###############################################################
#  Generated by:      Cadence Innovus 21.16-s078_1
#  OS:                Linux x86_64(Host ID cadpc24)
#  Generated on:      Thu Apr 11 01:46:05 2024
#  Design:            ibex_top
#  Command:           write_lef_abstract ibex_top.lef -5.7 -PgpinLayers {1 2 3 4 5} -specifyTopLayer 5 -stripePin
###############################################################

VERSION 5.7 ;

BUSBITCHARS "[]" ;
DIVIDERCHAR "/" ;

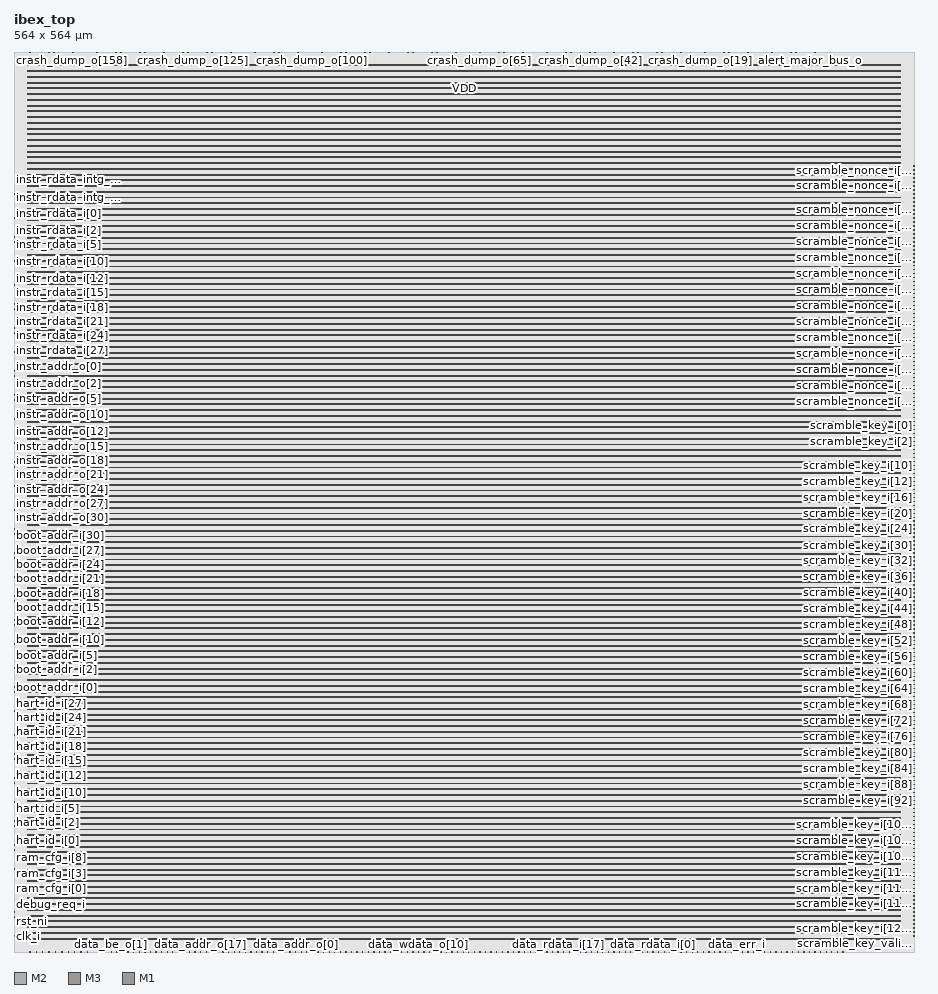
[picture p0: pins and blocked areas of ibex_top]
MACRO ibex_top
  CLASS BLOCK ;
  SIZE 564.000000 BY 564.000000 ;
  FOREIGN ibex_top 0.000000 0.000000 ;
  ORIGIN 0 0 ;
  SYMMETRY X Y R90 ;
  PIN clk_i
    DIRECTION INPUT ;
    USE SIGNAL ;
    ANTENNAPARTIALMETALAREA 0.06 LAYER M2  ;
    ANTENNAPARTIALMETALSIDEAREA 0.222 LAYER M2  ;
    ANTENNAPARTIALCUTAREA 0.04 LAYER V2  ;
    ANTENNAPARTIALMETALAREA 13.76 LAYER M3  ;
    ANTENNAPARTIALMETALSIDEAREA 51.208 LAYER M3  ;
    ANTENNAMODEL OXIDE1 ;
    ANTENNAGATEAREA 0.5976 LAYER M3  ;
    ANTENNAMAXAREACAR 67.0509 LAYER M3  ;
    ANTENNAMAXSIDEAREACAR 249.814 LAYER M3  ;
    ANTENNAMAXCUTCAR 1.38889 LAYER VL  ;
    PORT
      LAYER M2 ;
        RECT 0.000000 9.900000 0.600000 10.100000 ;
    END
  END clk_i
  PIN rst_ni
    DIRECTION INPUT ;
    USE SIGNAL ;
    ANTENNAPARTIALMETALAREA 0.06 LAYER M2  ;
    ANTENNAPARTIALMETALSIDEAREA 0.222 LAYER M2  ;
    ANTENNAPARTIALCUTAREA 0.04 LAYER V2  ;
    ANTENNAPARTIALMETALAREA 2.12 LAYER M3  ;
    ANTENNAPARTIALMETALSIDEAREA 7.992 LAYER M3  ;
    ANTENNAMODEL OXIDE1 ;
    ANTENNAGATEAREA 0.0888 LAYER M3  ;
    ANTENNAMAXAREACAR 26.9369 LAYER M3  ;
    ANTENNAMAXSIDEAREACAR 103.329 LAYER M3  ;
    ANTENNAMAXCUTCAR 0.900901 LAYER VL  ;
    PORT
      LAYER M2 ;
        RECT 0.000000 13.900000 0.600000 14.100000 ;
    END
  END rst_ni
  PIN test_en_i
    DIRECTION INPUT ;
    USE SIGNAL ;
    ANTENNAPARTIALMETALAREA 1.92 LAYER M3  ;
    ANTENNAPARTIALMETALSIDEAREA 7.4 LAYER M3  ;
    ANTENNAMODEL OXIDE1 ;
    ANTENNAGATEAREA 0.0888 LAYER M3  ;
    ANTENNAMAXAREACAR 23.6171 LAYER M3  ;
    ANTENNAMAXSIDEAREACAR 93.0225 LAYER M3  ;
    ANTENNAMAXCUTCAR 0.900901 LAYER VL  ;
    PORT
      LAYER M3 ;
        RECT 0.000000 21.900000 0.600000 22.100000 ;
    END
  END test_en_i
  PIN ram_cfg_i[9]
    DIRECTION INPUT ;
    USE SIGNAL ;
    PORT
      LAYER M2 ;
        RECT 0.000000 66.900000 0.600000 67.100000 ;
    END
  END ram_cfg_i[9]
  PIN ram_cfg_i[8]
    DIRECTION INPUT ;
    USE SIGNAL ;
    PORT
      LAYER M2 ;
        RECT 0.000000 63.900000 0.600000 64.100000 ;
    END
  END ram_cfg_i[8]
  PIN ram_cfg_i[7]
    DIRECTION INPUT ;
    USE SIGNAL ;
    PORT
      LAYER M2 ;
        RECT 0.000000 60.900000 0.600000 61.100000 ;
    END
  END ram_cfg_i[7]
  PIN ram_cfg_i[6]
    DIRECTION INPUT ;
    USE SIGNAL ;
    PORT
      LAYER M2 ;
        RECT 0.000000 57.900000 0.600000 58.100000 ;
    END
  END ram_cfg_i[6]
  PIN ram_cfg_i[5]
    DIRECTION INPUT ;
    USE SIGNAL ;
    PORT
      LAYER M2 ;
        RECT 0.000000 54.900000 0.600000 55.100000 ;
    END
  END ram_cfg_i[5]
  PIN ram_cfg_i[4]
    DIRECTION INPUT ;
    USE SIGNAL ;
    PORT
      LAYER M2 ;
        RECT 0.000000 51.900000 0.600000 52.100000 ;
    END
  END ram_cfg_i[4]
  PIN ram_cfg_i[3]
    DIRECTION INPUT ;
    USE SIGNAL ;
    PORT
      LAYER M2 ;
        RECT 0.000000 48.900000 0.600000 49.100000 ;
    END
  END ram_cfg_i[3]
  PIN ram_cfg_i[2]
    DIRECTION INPUT ;
    USE SIGNAL ;
    PORT
      LAYER M2 ;
        RECT 0.000000 45.900000 0.600000 46.100000 ;
    END
  END ram_cfg_i[2]
  PIN ram_cfg_i[1]
    DIRECTION INPUT ;
    USE SIGNAL ;
    PORT
      LAYER M2 ;
        RECT 0.000000 42.900000 0.600000 43.100000 ;
    END
  END ram_cfg_i[1]
  PIN ram_cfg_i[0]
    DIRECTION INPUT ;
    USE SIGNAL ;
    PORT
      LAYER M2 ;
        RECT 0.000000 39.900000 0.600000 40.100000 ;
    END
  END ram_cfg_i[0]
  PIN hart_id_i[31]
    DIRECTION INPUT ;
    USE SIGNAL ;
    ANTENNAPARTIALMETALAREA 0.02 LAYER M2  ;
    ANTENNAPARTIALMETALSIDEAREA 0.074 LAYER M2  ;
    ANTENNAPARTIALCUTAREA 0.04 LAYER V2  ;
    ANTENNAPARTIALMETALAREA 1.84 LAYER M3  ;
    ANTENNAPARTIALMETALSIDEAREA 7.104 LAYER M3  ;
    ANTENNAMODEL OXIDE1 ;
    ANTENNAGATEAREA 0.0888 LAYER M3  ;
    ANTENNAMAXAREACAR 22.7162 LAYER M3  ;
    ANTENNAMAXSIDEAREACAR 89.6892 LAYER M3  ;
    ANTENNAMAXCUTCAR 0.900901 LAYER VL  ;
    PORT
      LAYER M2 ;
        RECT 0.000000 162.900000 0.600000 163.100000 ;
    END
  END hart_id_i[31]
  PIN hart_id_i[30]
    DIRECTION INPUT ;
    USE SIGNAL ;
    ANTENNAPARTIALMETALAREA 0.3 LAYER M2  ;
    ANTENNAPARTIALMETALSIDEAREA 1.11 LAYER M2  ;
    ANTENNAPARTIALCUTAREA 0.04 LAYER V2  ;
    ANTENNAPARTIALMETALAREA 2.52 LAYER M3  ;
    ANTENNAPARTIALMETALSIDEAREA 9.472 LAYER M3  ;
    ANTENNAMODEL OXIDE1 ;
    ANTENNAGATEAREA 0.0888 LAYER M3  ;
    ANTENNAMAXAREACAR 31.4414 LAYER M3  ;
    ANTENNAMAXSIDEAREACAR 119.995 LAYER M3  ;
    ANTENNAMAXCUTCAR 0.900901 LAYER VL  ;
    PORT
      LAYER M2 ;
        RECT 0.000000 159.900000 0.600000 160.100000 ;
    END
  END hart_id_i[30]
  PIN hart_id_i[29]
    DIRECTION INPUT ;
    USE SIGNAL ;
    ANTENNAPARTIALMETALAREA 0.02 LAYER M2  ;
    ANTENNAPARTIALMETALSIDEAREA 0.074 LAYER M2  ;
    ANTENNAPARTIALCUTAREA 0.04 LAYER V2  ;
    ANTENNAPARTIALMETALAREA 1.92 LAYER M3  ;
    ANTENNAPARTIALMETALSIDEAREA 7.4 LAYER M3  ;
    ANTENNAMODEL OXIDE1 ;
    ANTENNAGATEAREA 0.0888 LAYER M3  ;
    ANTENNAMAXAREACAR 23.6171 LAYER M3  ;
    ANTENNAMAXSIDEAREACAR 93.0225 LAYER M3  ;
    ANTENNAMAXCUTCAR 0.900901 LAYER VL  ;
    PORT
      LAYER M2 ;
        RECT 0.000000 156.900000 0.600000 157.100000 ;
    END
  END hart_id_i[29]
  PIN hart_id_i[28]
    DIRECTION INPUT ;
    USE SIGNAL ;
    ANTENNAPARTIALMETALAREA 0.06 LAYER M2  ;
    ANTENNAPARTIALMETALSIDEAREA 0.222 LAYER M2  ;
    ANTENNAPARTIALCUTAREA 0.04 LAYER V2  ;
    ANTENNAPARTIALMETALAREA 2.08 LAYER M3  ;
    ANTENNAPARTIALMETALSIDEAREA 7.992 LAYER M3  ;
    ANTENNAMODEL OXIDE1 ;
    ANTENNAGATEAREA 0.0888 LAYER M3  ;
    ANTENNAMAXAREACAR 25.4189 LAYER M3  ;
    ANTENNAMAXSIDEAREACAR 99.6892 LAYER M3  ;
    ANTENNAMAXCUTCAR 0.900901 LAYER VL  ;
    PORT
      LAYER M2 ;
        RECT 0.000000 153.900000 0.600000 154.100000 ;
    END
  END hart_id_i[28]
  PIN hart_id_i[27]
    DIRECTION INPUT ;
    USE SIGNAL ;
    ANTENNAPARTIALMETALAREA 0.02 LAYER M2  ;
    ANTENNAPARTIALMETALSIDEAREA 0.074 LAYER M2  ;
    ANTENNAPARTIALCUTAREA 0.04 LAYER V2  ;
    ANTENNAPARTIALMETALAREA 2.08 LAYER M3  ;
    ANTENNAPARTIALMETALSIDEAREA 7.992 LAYER M3  ;
    ANTENNAMODEL OXIDE1 ;
    ANTENNAGATEAREA 0.0888 LAYER M3  ;
    ANTENNAMAXAREACAR 25.4189 LAYER M3  ;
    ANTENNAMAXSIDEAREACAR 99.6892 LAYER M3  ;
    ANTENNAMAXCUTCAR 0.900901 LAYER VL  ;
    PORT
      LAYER M2 ;
        RECT 0.000000 150.900000 0.600000 151.100000 ;
    END
  END hart_id_i[27]
  PIN hart_id_i[26]
    DIRECTION INPUT ;
    USE SIGNAL ;
    ANTENNAPARTIALMETALAREA 0.06 LAYER M2  ;
    ANTENNAPARTIALMETALSIDEAREA 0.222 LAYER M2  ;
    ANTENNAPARTIALCUTAREA 0.04 LAYER V2  ;
    ANTENNAPARTIALMETALAREA 2 LAYER M3  ;
    ANTENNAPARTIALMETALSIDEAREA 7.696 LAYER M3  ;
    ANTENNAMODEL OXIDE1 ;
    ANTENNAGATEAREA 0.0888 LAYER M3  ;
    ANTENNAMAXAREACAR 25.5856 LAYER M3  ;
    ANTENNAMAXSIDEAREACAR 99.9955 LAYER M3  ;
    ANTENNAMAXCUTCAR 0.900901 LAYER VL  ;
    PORT
      LAYER M2 ;
        RECT 0.000000 147.900000 0.600000 148.100000 ;
    END
  END hart_id_i[26]
  PIN hart_id_i[25]
    DIRECTION INPUT ;
    USE SIGNAL ;
    ANTENNAPARTIALMETALAREA 0.02 LAYER M2  ;
    ANTENNAPARTIALMETALSIDEAREA 0.074 LAYER M2  ;
    ANTENNAPARTIALCUTAREA 0.04 LAYER V2  ;
    ANTENNAPARTIALMETALAREA 1.92 LAYER M3  ;
    ANTENNAPARTIALMETALSIDEAREA 7.4 LAYER M3  ;
    ANTENNAMODEL OXIDE1 ;
    ANTENNAGATEAREA 0.0888 LAYER M3  ;
    ANTENNAMAXAREACAR 23.6171 LAYER M3  ;
    ANTENNAMAXSIDEAREACAR 93.0225 LAYER M3  ;
    ANTENNAMAXCUTCAR 0.900901 LAYER VL  ;
    PORT
      LAYER M2 ;
        RECT 0.000000 144.900000 0.600000 145.100000 ;
    END
  END hart_id_i[25]
  PIN hart_id_i[24]
    DIRECTION INPUT ;
    USE SIGNAL ;
    ANTENNAPARTIALMETALAREA 0.14 LAYER M2  ;
    ANTENNAPARTIALMETALSIDEAREA 0.518 LAYER M2  ;
    ANTENNAPARTIALCUTAREA 0.04 LAYER V2  ;
    ANTENNAPARTIALMETALAREA 1.96 LAYER M3  ;
    ANTENNAPARTIALMETALSIDEAREA 7.4 LAYER M3  ;
    ANTENNAMODEL OXIDE1 ;
    ANTENNAGATEAREA 0.0888 LAYER M3  ;
    ANTENNAMAXAREACAR 25.1351 LAYER M3  ;
    ANTENNAMAXSIDEAREACAR 96.6622 LAYER M3  ;
    ANTENNAMAXCUTCAR 0.900901 LAYER VL  ;
    PORT
      LAYER M2 ;
        RECT 0.000000 141.900000 0.600000 142.100000 ;
    END
  END hart_id_i[24]
  PIN hart_id_i[23]
    DIRECTION INPUT ;
    USE SIGNAL ;
    ANTENNAPARTIALMETALAREA 0.18 LAYER M2  ;
    ANTENNAPARTIALMETALSIDEAREA 0.666 LAYER M2  ;
    ANTENNAPARTIALCUTAREA 0.04 LAYER V2  ;
    ANTENNAPARTIALMETALAREA 2.28 LAYER M3  ;
    ANTENNAPARTIALMETALSIDEAREA 8.584 LAYER M3  ;
    ANTENNAMODEL OXIDE1 ;
    ANTENNAGATEAREA 0.0888 LAYER M3  ;
    ANTENNAMAXAREACAR 28.7387 LAYER M3  ;
    ANTENNAMAXSIDEAREACAR 109.995 LAYER M3  ;
    ANTENNAMAXCUTCAR 0.900901 LAYER VL  ;
    PORT
      LAYER M2 ;
        RECT 0.000000 138.900000 0.600000 139.100000 ;
    END
  END hart_id_i[23]
  PIN hart_id_i[22]
    DIRECTION INPUT ;
    USE SIGNAL ;
    ANTENNAPARTIALMETALAREA 0.06 LAYER M2  ;
    ANTENNAPARTIALMETALSIDEAREA 0.222 LAYER M2  ;
    ANTENNAPARTIALCUTAREA 0.04 LAYER V2  ;
    ANTENNAPARTIALMETALAREA 1.92 LAYER M3  ;
    ANTENNAPARTIALMETALSIDEAREA 7.4 LAYER M3  ;
    ANTENNAMODEL OXIDE1 ;
    ANTENNAGATEAREA 0.0888 LAYER M3  ;
    ANTENNAMAXAREACAR 23.6171 LAYER M3  ;
    ANTENNAMAXSIDEAREACAR 93.0225 LAYER M3  ;
    ANTENNAMAXCUTCAR 0.900901 LAYER VL  ;
    PORT
      LAYER M2 ;
        RECT 0.000000 135.900000 0.600000 136.100000 ;
    END
  END hart_id_i[22]
  PIN hart_id_i[21]
    DIRECTION INPUT ;
    USE SIGNAL ;
    ANTENNAPARTIALMETALAREA 0.02 LAYER M2  ;
    ANTENNAPARTIALMETALSIDEAREA 0.074 LAYER M2  ;
    ANTENNAPARTIALCUTAREA 0.04 LAYER V2  ;
    ANTENNAPARTIALMETALAREA 1.88 LAYER M3  ;
    ANTENNAPARTIALMETALSIDEAREA 7.104 LAYER M3  ;
    ANTENNAMODEL OXIDE1 ;
    ANTENNAGATEAREA 0.0888 LAYER M3  ;
    ANTENNAMAXAREACAR 23.1667 LAYER M3  ;
    ANTENNAMAXSIDEAREACAR 89.6892 LAYER M3  ;
    ANTENNAMAXCUTCAR 0.900901 LAYER VL  ;
    PORT
      LAYER M2 ;
        RECT 0.000000 132.900000 0.600000 133.100000 ;
    END
  END hart_id_i[21]
  PIN hart_id_i[20]
    DIRECTION INPUT ;
    USE SIGNAL ;
    ANTENNAPARTIALMETALAREA 0.06 LAYER M2  ;
    ANTENNAPARTIALMETALSIDEAREA 0.222 LAYER M2  ;
    ANTENNAPARTIALCUTAREA 0.04 LAYER V2  ;
    ANTENNAPARTIALMETALAREA 0.44 LAYER M3  ;
    ANTENNAPARTIALMETALSIDEAREA 1.776 LAYER M3  ;
    PORT
      LAYER M2 ;
        RECT 0.000000 129.900000 0.600000 130.100000 ;
    END
  END hart_id_i[20]
  PIN hart_id_i[19]
    DIRECTION INPUT ;
    USE SIGNAL ;
    ANTENNAPARTIALMETALAREA 0.02 LAYER M2  ;
    ANTENNAPARTIALMETALSIDEAREA 0.074 LAYER M2  ;
    ANTENNAPARTIALCUTAREA 0.04 LAYER V2  ;
    ANTENNAPARTIALMETALAREA 2.16 LAYER M3  ;
    ANTENNAPARTIALMETALSIDEAREA 8.288 LAYER M3  ;
    ANTENNAMODEL OXIDE1 ;
    ANTENNAGATEAREA 0.0888 LAYER M3  ;
    ANTENNAMAXAREACAR 26.3198 LAYER M3  ;
    ANTENNAMAXSIDEAREACAR 103.023 LAYER M3  ;
    ANTENNAMAXCUTCAR 0.900901 LAYER VL  ;
    PORT
      LAYER M2 ;
        RECT 0.000000 126.900000 0.600000 127.100000 ;
    END
  END hart_id_i[19]
  PIN hart_id_i[18]
    DIRECTION INPUT ;
    USE SIGNAL ;
    ANTENNAPARTIALMETALAREA 0.3 LAYER M2  ;
    ANTENNAPARTIALMETALSIDEAREA 1.11 LAYER M2  ;
    ANTENNAPARTIALCUTAREA 0.04 LAYER V2  ;
    ANTENNAPARTIALMETALAREA 1.8 LAYER M3  ;
    ANTENNAPARTIALMETALSIDEAREA 6.808 LAYER M3  ;
    ANTENNAMODEL OXIDE1 ;
    ANTENNAGATEAREA 0.0888 LAYER M3  ;
    ANTENNAMAXAREACAR 23.3333 LAYER M3  ;
    ANTENNAMAXSIDEAREACAR 89.9955 LAYER M3  ;
    ANTENNAMAXCUTCAR 0.900901 LAYER VL  ;
    PORT
      LAYER M2 ;
        RECT 0.000000 123.900000 0.600000 124.100000 ;
    END
  END hart_id_i[18]
  PIN hart_id_i[17]
    DIRECTION INPUT ;
    USE SIGNAL ;
    ANTENNAPARTIALMETALAREA 0.02 LAYER M2  ;
    ANTENNAPARTIALMETALSIDEAREA 0.074 LAYER M2  ;
    ANTENNAPARTIALCUTAREA 0.04 LAYER V2  ;
    ANTENNAPARTIALMETALAREA 0.52 LAYER M3  ;
    ANTENNAPARTIALMETALSIDEAREA 2.072 LAYER M3  ;
    PORT
      LAYER M2 ;
        RECT 0.000000 120.900000 0.600000 121.100000 ;
    END
  END hart_id_i[17]
  PIN hart_id_i[16]
    DIRECTION INPUT ;
    USE SIGNAL ;
    ANTENNAPARTIALMETALAREA 0.06 LAYER M2  ;
    ANTENNAPARTIALMETALSIDEAREA 0.222 LAYER M2  ;
    ANTENNAPARTIALCUTAREA 0.04 LAYER V2  ;
    ANTENNAPARTIALMETALAREA 1.84 LAYER M3  ;
    ANTENNAPARTIALMETALSIDEAREA 7.104 LAYER M3  ;
    PORT
      LAYER M2 ;
        RECT 0.000000 117.900000 0.600000 118.100000 ;
    END
  END hart_id_i[16]
  PIN hart_id_i[15]
    DIRECTION INPUT ;
    USE SIGNAL ;
    ANTENNAPARTIALMETALAREA 0.1 LAYER M2  ;
    ANTENNAPARTIALMETALSIDEAREA 0.37 LAYER M2  ;
    ANTENNAPARTIALCUTAREA 0.04 LAYER V2  ;
    ANTENNAPARTIALMETALAREA 1.88 LAYER M3  ;
    ANTENNAPARTIALMETALSIDEAREA 7.104 LAYER M3  ;
    ANTENNAMODEL OXIDE1 ;
    ANTENNAGATEAREA 0.0888 LAYER M3  ;
    ANTENNAMAXAREACAR 24.2342 LAYER M3  ;
    ANTENNAMAXSIDEAREACAR 93.3288 LAYER M3  ;
    ANTENNAMAXCUTCAR 0.900901 LAYER VL  ;
    PORT
      LAYER M2 ;
        RECT 0.000000 114.900000 0.600000 115.100000 ;
    END
  END hart_id_i[15]
  PIN hart_id_i[14]
    DIRECTION INPUT ;
    USE SIGNAL ;
    ANTENNAPARTIALMETALAREA 0.06 LAYER M2  ;
    ANTENNAPARTIALMETALSIDEAREA 0.222 LAYER M2  ;
    ANTENNAPARTIALCUTAREA 0.04 LAYER V2  ;
    ANTENNAPARTIALMETALAREA 0.6 LAYER M3  ;
    ANTENNAPARTIALMETALSIDEAREA 2.368 LAYER M3  ;
    PORT
      LAYER M2 ;
        RECT 0.000000 111.900000 0.600000 112.100000 ;
    END
  END hart_id_i[14]
  PIN hart_id_i[13]
    DIRECTION INPUT ;
    USE SIGNAL ;
    ANTENNAPARTIALMETALAREA 0.02 LAYER M2  ;
    ANTENNAPARTIALMETALSIDEAREA 0.074 LAYER M2  ;
    ANTENNAPARTIALCUTAREA 0.04 LAYER V2  ;
    ANTENNAPARTIALMETALAREA 0.36 LAYER M3  ;
    ANTENNAPARTIALMETALSIDEAREA 1.48 LAYER M3  ;
    PORT
      LAYER M2 ;
        RECT 0.000000 108.900000 0.600000 109.100000 ;
    END
  END hart_id_i[13]
  PIN hart_id_i[12]
    DIRECTION INPUT ;
    USE SIGNAL ;
    ANTENNAPARTIALMETALAREA 0.06 LAYER M2  ;
    ANTENNAPARTIALMETALSIDEAREA 0.222 LAYER M2  ;
    ANTENNAPARTIALCUTAREA 0.04 LAYER V2  ;
    ANTENNAPARTIALMETALAREA 1.92 LAYER M3  ;
    ANTENNAPARTIALMETALSIDEAREA 7.4 LAYER M3  ;
    PORT
      LAYER M2 ;
        RECT 0.000000 105.900000 0.600000 106.100000 ;
    END
  END hart_id_i[12]
  PIN hart_id_i[11]
    DIRECTION INPUT ;
    USE SIGNAL ;
    ANTENNAPARTIALMETALAREA 0.02 LAYER M2  ;
    ANTENNAPARTIALMETALSIDEAREA 0.074 LAYER M2  ;
    ANTENNAPARTIALCUTAREA 0.04 LAYER V2  ;
    ANTENNAPARTIALMETALAREA 0.28 LAYER M3  ;
    ANTENNAPARTIALMETALSIDEAREA 1.184 LAYER M3  ;
    PORT
      LAYER M2 ;
        RECT 0.000000 102.900000 0.600000 103.100000 ;
    END
  END hart_id_i[11]
  PIN hart_id_i[10]
    DIRECTION INPUT ;
    USE SIGNAL ;
    ANTENNAPARTIALMETALAREA 0.06 LAYER M2  ;
    ANTENNAPARTIALMETALSIDEAREA 0.222 LAYER M2  ;
    ANTENNAPARTIALCUTAREA 0.04 LAYER V2  ;
    ANTENNAPARTIALMETALAREA 2.16 LAYER M3  ;
    ANTENNAPARTIALMETALSIDEAREA 8.288 LAYER M3  ;
    ANTENNAMODEL OXIDE1 ;
    ANTENNAGATEAREA 0.0888 LAYER M3  ;
    ANTENNAMAXAREACAR 26.3198 LAYER M3  ;
    ANTENNAMAXSIDEAREACAR 103.023 LAYER M3  ;
    ANTENNAMAXCUTCAR 0.900901 LAYER VL  ;
    PORT
      LAYER M2 ;
        RECT 0.000000 99.900000 0.600000 100.100000 ;
    END
  END hart_id_i[10]
  PIN hart_id_i[9]
    DIRECTION INPUT ;
    USE SIGNAL ;
    ANTENNAPARTIALMETALAREA 0.02 LAYER M2  ;
    ANTENNAPARTIALMETALSIDEAREA 0.074 LAYER M2  ;
    ANTENNAPARTIALCUTAREA 0.04 LAYER V2  ;
    ANTENNAPARTIALMETALAREA 0.44 LAYER M3  ;
    ANTENNAPARTIALMETALSIDEAREA 1.776 LAYER M3  ;
    PORT
      LAYER M2 ;
        RECT 0.000000 96.900000 0.600000 97.100000 ;
    END
  END hart_id_i[9]
  PIN hart_id_i[8]
    DIRECTION INPUT ;
    USE SIGNAL ;
    ANTENNAPARTIALMETALAREA 0.06 LAYER M2  ;
    ANTENNAPARTIALMETALSIDEAREA 0.222 LAYER M2  ;
    ANTENNAPARTIALCUTAREA 0.04 LAYER V2  ;
    ANTENNAPARTIALMETALAREA 0.36 LAYER M3  ;
    ANTENNAPARTIALMETALSIDEAREA 1.48 LAYER M3  ;
    PORT
      LAYER M2 ;
        RECT 0.000000 93.900000 0.600000 94.100000 ;
    END
  END hart_id_i[8]
  PIN hart_id_i[7]
    DIRECTION INPUT ;
    USE SIGNAL ;
    ANTENNAPARTIALMETALAREA 0.02 LAYER M2  ;
    ANTENNAPARTIALMETALSIDEAREA 0.074 LAYER M2  ;
    ANTENNAPARTIALCUTAREA 0.04 LAYER V2  ;
    ANTENNAPARTIALMETALAREA 2.48 LAYER M3  ;
    ANTENNAPARTIALMETALSIDEAREA 9.472 LAYER M3  ;
    PORT
      LAYER M2 ;
        RECT 0.000000 90.900000 0.600000 91.100000 ;
    END
  END hart_id_i[7]
  PIN hart_id_i[6]
    DIRECTION INPUT ;
    USE SIGNAL ;
    ANTENNAPARTIALMETALAREA 0.06 LAYER M2  ;
    ANTENNAPARTIALMETALSIDEAREA 0.222 LAYER M2  ;
    ANTENNAPARTIALCUTAREA 0.04 LAYER V2  ;
    ANTENNAPARTIALMETALAREA 2 LAYER M3  ;
    ANTENNAPARTIALMETALSIDEAREA 7.696 LAYER M3  ;
    PORT
      LAYER M2 ;
        RECT 0.000000 87.900000 0.600000 88.100000 ;
    END
  END hart_id_i[6]
  PIN hart_id_i[5]
    DIRECTION INPUT ;
    USE SIGNAL ;
    ANTENNAPARTIALMETALAREA 0.02 LAYER M2  ;
    ANTENNAPARTIALMETALSIDEAREA 0.074 LAYER M2  ;
    ANTENNAPARTIALCUTAREA 0.04 LAYER V2  ;
    ANTENNAPARTIALMETALAREA 1.8 LAYER M3  ;
    ANTENNAPARTIALMETALSIDEAREA 6.808 LAYER M3  ;
    PORT
      LAYER M2 ;
        RECT 0.000000 84.900000 0.600000 85.100000 ;
    END
  END hart_id_i[5]
  PIN hart_id_i[4]
    DIRECTION INPUT ;
    USE SIGNAL ;
    ANTENNAPARTIALMETALAREA 0.06 LAYER M2  ;
    ANTENNAPARTIALMETALSIDEAREA 0.222 LAYER M2  ;
    ANTENNAPARTIALCUTAREA 0.04 LAYER V2  ;
    ANTENNAPARTIALMETALAREA 0.28 LAYER M3  ;
    ANTENNAPARTIALMETALSIDEAREA 1.184 LAYER M3  ;
    PORT
      LAYER M2 ;
        RECT 0.000000 81.900000 0.600000 82.100000 ;
    END
  END hart_id_i[4]
  PIN hart_id_i[3]
    DIRECTION INPUT ;
    USE SIGNAL ;
    ANTENNAPARTIALMETALAREA 0.02 LAYER M2  ;
    ANTENNAPARTIALMETALSIDEAREA 0.074 LAYER M2  ;
    ANTENNAPARTIALCUTAREA 0.04 LAYER V2  ;
    ANTENNAPARTIALMETALAREA 2.24 LAYER M3  ;
    ANTENNAPARTIALMETALSIDEAREA 8.584 LAYER M3  ;
    PORT
      LAYER M2 ;
        RECT 0.000000 78.900000 0.600000 79.100000 ;
    END
  END hart_id_i[3]
  PIN hart_id_i[2]
    DIRECTION INPUT ;
    USE SIGNAL ;
    ANTENNAPARTIALMETALAREA 0.06 LAYER M2  ;
    ANTENNAPARTIALMETALSIDEAREA 0.222 LAYER M2  ;
    ANTENNAPARTIALCUTAREA 0.04 LAYER V2  ;
    ANTENNAPARTIALMETALAREA 1.88 LAYER M3  ;
    ANTENNAPARTIALMETALSIDEAREA 7.104 LAYER M3  ;
    PORT
      LAYER M2 ;
        RECT 0.000000 75.900000 0.600000 76.100000 ;
    END
  END hart_id_i[2]
  PIN hart_id_i[1]
    DIRECTION INPUT ;
    USE SIGNAL ;
    ANTENNAPARTIALMETALAREA 0.02 LAYER M2  ;
    ANTENNAPARTIALMETALSIDEAREA 0.074 LAYER M2  ;
    ANTENNAPARTIALCUTAREA 0.04 LAYER V2  ;
    ANTENNAPARTIALMETALAREA 1.84 LAYER M3  ;
    ANTENNAPARTIALMETALSIDEAREA 7.104 LAYER M3  ;
    ANTENNAMODEL OXIDE1 ;
    ANTENNAGATEAREA 0.0888 LAYER M3  ;
    ANTENNAMAXAREACAR 23.7838 LAYER M3  ;
    ANTENNAMAXSIDEAREACAR 93.3288 LAYER M3  ;
    ANTENNAMAXCUTCAR 0.900901 LAYER VL  ;
    PORT
      LAYER M2 ;
        RECT 0.000000 72.900000 0.600000 73.100000 ;
    END
  END hart_id_i[1]
  PIN hart_id_i[0]
    DIRECTION INPUT ;
    USE SIGNAL ;
    ANTENNAPARTIALMETALAREA 0.06 LAYER M2  ;
    ANTENNAPARTIALMETALSIDEAREA 0.222 LAYER M2  ;
    ANTENNAPARTIALCUTAREA 0.04 LAYER V2  ;
    ANTENNAPARTIALMETALAREA 1.84 LAYER M3  ;
    ANTENNAPARTIALMETALSIDEAREA 7.104 LAYER M3  ;
    ANTENNAMODEL OXIDE1 ;
    ANTENNAGATEAREA 0.0888 LAYER M3  ;
    ANTENNAMAXAREACAR 22.7162 LAYER M3  ;
    ANTENNAMAXSIDEAREACAR 89.6892 LAYER M3  ;
    ANTENNAMAXCUTCAR 0.900901 LAYER VL  ;
    PORT
      LAYER M2 ;
        RECT 0.000000 69.900000 0.600000 70.100000 ;
    END
  END hart_id_i[0]
  PIN boot_addr_i[31]
    DIRECTION INPUT ;
    USE SIGNAL ;
    ANTENNAPARTIALMETALAREA 0.02 LAYER M2  ;
    ANTENNAPARTIALMETALSIDEAREA 0.074 LAYER M2  ;
    ANTENNAPARTIALCUTAREA 0.04 LAYER V2  ;
    ANTENNAPARTIALMETALAREA 1.56 LAYER M3  ;
    ANTENNAPARTIALMETALSIDEAREA 5.92 LAYER M3  ;
    PORT
      LAYER M2 ;
        RECT 0.000000 258.900000 0.600000 259.100000 ;
    END
  END boot_addr_i[31]
  PIN boot_addr_i[30]
    DIRECTION INPUT ;
    USE SIGNAL ;
    ANTENNAPARTIALMETALAREA 0.06 LAYER M2  ;
    ANTENNAPARTIALMETALSIDEAREA 0.222 LAYER M2  ;
    ANTENNAPARTIALCUTAREA 0.04 LAYER V2  ;
    ANTENNAPARTIALMETALAREA 0.36 LAYER M3  ;
    ANTENNAPARTIALMETALSIDEAREA 1.48 LAYER M3  ;
    PORT
      LAYER M2 ;
        RECT 0.000000 255.900000 0.600000 256.100000 ;
    END
  END boot_addr_i[30]
  PIN boot_addr_i[29]
    DIRECTION INPUT ;
    USE SIGNAL ;
    ANTENNAPARTIALMETALAREA 0.02 LAYER M2  ;
    ANTENNAPARTIALMETALSIDEAREA 0.074 LAYER M2  ;
    ANTENNAPARTIALCUTAREA 0.04 LAYER V2  ;
    ANTENNAPARTIALMETALAREA 3.12 LAYER M3  ;
    ANTENNAPARTIALMETALSIDEAREA 11.84 LAYER M3  ;
    ANTENNAMODEL OXIDE1 ;
    ANTENNAGATEAREA 0.0888 LAYER M3  ;
    ANTENNAMAXAREACAR 37.1306 LAYER M3  ;
    ANTENNAMAXSIDEAREACAR 143.023 LAYER M3  ;
    ANTENNAMAXCUTCAR 0.900901 LAYER VL  ;
    PORT
      LAYER M2 ;
        RECT 0.000000 252.900000 0.600000 253.100000 ;
    END
  END boot_addr_i[29]
  PIN boot_addr_i[28]
    DIRECTION INPUT ;
    USE SIGNAL ;
    ANTENNAPARTIALMETALAREA 0.14 LAYER M2  ;
    ANTENNAPARTIALMETALSIDEAREA 0.518 LAYER M2  ;
    ANTENNAPARTIALCUTAREA 0.04 LAYER V2  ;
    ANTENNAPARTIALMETALAREA 2.2 LAYER M3  ;
    ANTENNAPARTIALMETALSIDEAREA 8.288 LAYER M3  ;
    ANTENNAMODEL OXIDE1 ;
    ANTENNAGATEAREA 0.0888 LAYER M3  ;
    ANTENNAMAXAREACAR 27.8378 LAYER M3  ;
    ANTENNAMAXSIDEAREACAR 106.662 LAYER M3  ;
    ANTENNAMAXCUTCAR 0.900901 LAYER VL  ;
    PORT
      LAYER M2 ;
        RECT 0.000000 249.900000 0.600000 250.100000 ;
    END
  END boot_addr_i[28]
  PIN boot_addr_i[27]
    DIRECTION INPUT ;
    USE SIGNAL ;
    ANTENNAPARTIALMETALAREA 0.02 LAYER M2  ;
    ANTENNAPARTIALMETALSIDEAREA 0.074 LAYER M2  ;
    ANTENNAPARTIALCUTAREA 0.04 LAYER V2  ;
    ANTENNAPARTIALMETALAREA 1.8 LAYER M3  ;
    ANTENNAPARTIALMETALSIDEAREA 6.808 LAYER M3  ;
    PORT
      LAYER M2 ;
        RECT 0.000000 246.900000 0.600000 247.100000 ;
    END
  END boot_addr_i[27]
  PIN boot_addr_i[26]
    DIRECTION INPUT ;
    USE SIGNAL ;
    ANTENNAPARTIALMETALAREA 0.06 LAYER M2  ;
    ANTENNAPARTIALMETALSIDEAREA 0.222 LAYER M2  ;
    ANTENNAPARTIALCUTAREA 0.04 LAYER V2  ;
    ANTENNAPARTIALMETALAREA 3.88 LAYER M3  ;
    ANTENNAPARTIALMETALSIDEAREA 14.504 LAYER M3  ;
    ANTENNAMODEL OXIDE1 ;
    ANTENNAGATEAREA 0.0888 LAYER M3  ;
    ANTENNAMAXAREACAR 45.6892 LAYER M3  ;
    ANTENNAMAXSIDEAREACAR 173.023 LAYER M3  ;
    ANTENNAMAXCUTCAR 0.900901 LAYER VL  ;
    PORT
      LAYER M2 ;
        RECT 0.000000 243.900000 0.600000 244.100000 ;
    END
  END boot_addr_i[26]
  PIN boot_addr_i[25]
    DIRECTION INPUT ;
    USE SIGNAL ;
    ANTENNAPARTIALMETALAREA 0.02 LAYER M2  ;
    ANTENNAPARTIALMETALSIDEAREA 0.074 LAYER M2  ;
    ANTENNAPARTIALCUTAREA 0.04 LAYER V2  ;
    ANTENNAPARTIALMETALAREA 2.24 LAYER M3  ;
    ANTENNAPARTIALMETALSIDEAREA 8.584 LAYER M3  ;
    ANTENNAMODEL OXIDE1 ;
    ANTENNAGATEAREA 0.0888 LAYER M3  ;
    ANTENNAMAXAREACAR 28.2883 LAYER M3  ;
    ANTENNAMAXSIDEAREACAR 109.995 LAYER M3  ;
    ANTENNAMAXCUTCAR 0.900901 LAYER VL  ;
    PORT
      LAYER M2 ;
        RECT 0.000000 240.900000 0.600000 241.100000 ;
    END
  END boot_addr_i[25]
  PIN boot_addr_i[24]
    DIRECTION INPUT ;
    USE SIGNAL ;
    ANTENNAPARTIALMETALAREA 0.06 LAYER M2  ;
    ANTENNAPARTIALMETALSIDEAREA 0.222 LAYER M2  ;
    ANTENNAPARTIALCUTAREA 0.04 LAYER V2  ;
    ANTENNAPARTIALMETALAREA 3.12 LAYER M3  ;
    ANTENNAPARTIALMETALSIDEAREA 11.84 LAYER M3  ;
    ANTENNAMODEL OXIDE1 ;
    ANTENNAGATEAREA 0.0888 LAYER M3  ;
    ANTENNAMAXAREACAR 37.1306 LAYER M3  ;
    ANTENNAMAXSIDEAREACAR 143.023 LAYER M3  ;
    ANTENNAMAXCUTCAR 0.900901 LAYER VL  ;
    PORT
      LAYER M2 ;
        RECT 0.000000 237.900000 0.600000 238.100000 ;
    END
  END boot_addr_i[24]
  PIN boot_addr_i[23]
    DIRECTION INPUT ;
    USE SIGNAL ;
    ANTENNAPARTIALMETALAREA 0.02 LAYER M2  ;
    ANTENNAPARTIALMETALSIDEAREA 0.074 LAYER M2  ;
    ANTENNAPARTIALCUTAREA 0.04 LAYER V2  ;
    ANTENNAPARTIALMETALAREA 2.16 LAYER M3  ;
    ANTENNAPARTIALMETALSIDEAREA 8.288 LAYER M3  ;
    ANTENNAMODEL OXIDE1 ;
    ANTENNAGATEAREA 0.0888 LAYER M3  ;
    ANTENNAMAXAREACAR 27.3874 LAYER M3  ;
    ANTENNAMAXSIDEAREACAR 106.662 LAYER M3  ;
    ANTENNAMAXCUTCAR 0.900901 LAYER VL  ;
    PORT
      LAYER M2 ;
        RECT 0.000000 234.900000 0.600000 235.100000 ;
    END
  END boot_addr_i[23]
  PIN boot_addr_i[22]
    DIRECTION INPUT ;
    USE SIGNAL ;
    ANTENNAPARTIALMETALAREA 0.3 LAYER M2  ;
    ANTENNAPARTIALMETALSIDEAREA 1.11 LAYER M2  ;
    ANTENNAPARTIALCUTAREA 0.04 LAYER V2  ;
    ANTENNAPARTIALMETALAREA 2.92 LAYER M3  ;
    ANTENNAPARTIALMETALSIDEAREA 10.952 LAYER M3  ;
    ANTENNAMODEL OXIDE1 ;
    ANTENNAGATEAREA 0.0888 LAYER M3  ;
    ANTENNAMAXAREACAR 35.9459 LAYER M3  ;
    ANTENNAMAXSIDEAREACAR 136.662 LAYER M3  ;
    ANTENNAMAXCUTCAR 0.900901 LAYER VL  ;
    PORT
      LAYER M2 ;
        RECT 0.000000 231.900000 0.600000 232.100000 ;
    END
  END boot_addr_i[22]
  PIN boot_addr_i[21]
    DIRECTION INPUT ;
    USE SIGNAL ;
    ANTENNAPARTIALMETALAREA 0.02 LAYER M2  ;
    ANTENNAPARTIALMETALSIDEAREA 0.074 LAYER M2  ;
    ANTENNAPARTIALCUTAREA 0.04 LAYER V2  ;
    ANTENNAPARTIALMETALAREA 1.64 LAYER M3  ;
    ANTENNAPARTIALMETALSIDEAREA 6.216 LAYER M3  ;
    PORT
      LAYER M2 ;
        RECT 0.000000 228.900000 0.600000 229.100000 ;
    END
  END boot_addr_i[21]
  PIN boot_addr_i[20]
    DIRECTION INPUT ;
    USE SIGNAL ;
    ANTENNAPARTIALMETALAREA 0.06 LAYER M2  ;
    ANTENNAPARTIALMETALSIDEAREA 0.222 LAYER M2  ;
    ANTENNAPARTIALCUTAREA 0.04 LAYER V2  ;
    ANTENNAPARTIALMETALAREA 0.28 LAYER M3  ;
    ANTENNAPARTIALMETALSIDEAREA 1.184 LAYER M3  ;
    PORT
      LAYER M2 ;
        RECT 0.000000 225.900000 0.600000 226.100000 ;
    END
  END boot_addr_i[20]
  PIN boot_addr_i[19]
    DIRECTION INPUT ;
    USE SIGNAL ;
    ANTENNAPARTIALMETALAREA 0.02 LAYER M2  ;
    ANTENNAPARTIALMETALSIDEAREA 0.074 LAYER M2  ;
    ANTENNAPARTIALCUTAREA 0.04 LAYER V2  ;
    ANTENNAPARTIALMETALAREA 2.16 LAYER M3  ;
    ANTENNAPARTIALMETALSIDEAREA 8.288 LAYER M3  ;
    ANTENNAMODEL OXIDE1 ;
    ANTENNAGATEAREA 0.0888 LAYER M3  ;
    ANTENNAMAXAREACAR 26.3198 LAYER M3  ;
    ANTENNAMAXSIDEAREACAR 103.023 LAYER M3  ;
    ANTENNAMAXCUTCAR 0.900901 LAYER VL  ;
    PORT
      LAYER M2 ;
        RECT 0.000000 222.900000 0.600000 223.100000 ;
    END
  END boot_addr_i[19]
  PIN boot_addr_i[18]
    DIRECTION INPUT ;
    USE SIGNAL ;
    ANTENNAPARTIALMETALAREA 0.06 LAYER M2  ;
    ANTENNAPARTIALMETALSIDEAREA 0.222 LAYER M2  ;
    ANTENNAPARTIALCUTAREA 0.04 LAYER V2  ;
    ANTENNAPARTIALMETALAREA 2.16 LAYER M3  ;
    ANTENNAPARTIALMETALSIDEAREA 8.288 LAYER M3  ;
    ANTENNAMODEL OXIDE1 ;
    ANTENNAGATEAREA 0.0888 LAYER M3  ;
    ANTENNAMAXAREACAR 26.3198 LAYER M3  ;
    ANTENNAMAXSIDEAREACAR 103.023 LAYER M3  ;
    ANTENNAMAXCUTCAR 0.900901 LAYER VL  ;
    PORT
      LAYER M2 ;
        RECT 0.000000 219.900000 0.600000 220.100000 ;
    END
  END boot_addr_i[18]
  PIN boot_addr_i[17]
    DIRECTION INPUT ;
    USE SIGNAL ;
    ANTENNAPARTIALMETALAREA 0.02 LAYER M2  ;
    ANTENNAPARTIALMETALSIDEAREA 0.074 LAYER M2  ;
    ANTENNAPARTIALCUTAREA 0.04 LAYER V2  ;
    ANTENNAPARTIALMETALAREA 1.8 LAYER M3  ;
    ANTENNAPARTIALMETALSIDEAREA 6.808 LAYER M3  ;
    PORT
      LAYER M2 ;
        RECT 0.000000 216.900000 0.600000 217.100000 ;
    END
  END boot_addr_i[17]
  PIN boot_addr_i[16]
    DIRECTION INPUT ;
    USE SIGNAL ;
    ANTENNAPARTIALMETALAREA 0.06 LAYER M2  ;
    ANTENNAPARTIALMETALSIDEAREA 0.222 LAYER M2  ;
    ANTENNAPARTIALCUTAREA 0.04 LAYER V2  ;
    ANTENNAPARTIALMETALAREA 0.44 LAYER M3  ;
    ANTENNAPARTIALMETALSIDEAREA 1.776 LAYER M3  ;
    PORT
      LAYER M2 ;
        RECT 0.000000 213.900000 0.600000 214.100000 ;
    END
  END boot_addr_i[16]
  PIN boot_addr_i[15]
    DIRECTION INPUT ;
    USE SIGNAL ;
    ANTENNAPARTIALMETALAREA 0.02 LAYER M2  ;
    ANTENNAPARTIALMETALSIDEAREA 0.074 LAYER M2  ;
    ANTENNAPARTIALCUTAREA 0.04 LAYER V2  ;
    ANTENNAPARTIALMETALAREA 1.8 LAYER M3  ;
    ANTENNAPARTIALMETALSIDEAREA 6.808 LAYER M3  ;
    PORT
      LAYER M2 ;
        RECT 0.000000 210.900000 0.600000 211.100000 ;
    END
  END boot_addr_i[15]
  PIN boot_addr_i[14]
    DIRECTION INPUT ;
    USE SIGNAL ;
    ANTENNAPARTIALMETALAREA 0.06 LAYER M2  ;
    ANTENNAPARTIALMETALSIDEAREA 0.222 LAYER M2  ;
    ANTENNAPARTIALCUTAREA 0.04 LAYER V2  ;
    ANTENNAPARTIALMETALAREA 1.8 LAYER M3  ;
    ANTENNAPARTIALMETALSIDEAREA 6.808 LAYER M3  ;
    ANTENNAMODEL OXIDE1 ;
    ANTENNAGATEAREA 0.0888 LAYER M3  ;
    ANTENNAMAXAREACAR 22.4324 LAYER M3  ;
    ANTENNAMAXSIDEAREACAR 86.6622 LAYER M3  ;
    ANTENNAMAXCUTCAR 0.900901 LAYER VL  ;
    PORT
      LAYER M2 ;
        RECT 0.000000 207.900000 0.600000 208.100000 ;
    END
  END boot_addr_i[14]
  PIN boot_addr_i[13]
    DIRECTION INPUT ;
    USE SIGNAL ;
    ANTENNAPARTIALMETALAREA 0.02 LAYER M2  ;
    ANTENNAPARTIALMETALSIDEAREA 0.074 LAYER M2  ;
    ANTENNAPARTIALCUTAREA 0.04 LAYER V2  ;
    ANTENNAPARTIALMETALAREA 1.8 LAYER M3  ;
    ANTENNAPARTIALMETALSIDEAREA 6.808 LAYER M3  ;
    ANTENNAMODEL OXIDE1 ;
    ANTENNAGATEAREA 0.0888 LAYER M3  ;
    ANTENNAMAXAREACAR 22.4324 LAYER M3  ;
    ANTENNAMAXSIDEAREACAR 86.6622 LAYER M3  ;
    ANTENNAMAXCUTCAR 0.900901 LAYER VL  ;
    PORT
      LAYER M2 ;
        RECT 0.000000 204.900000 0.600000 205.100000 ;
    END
  END boot_addr_i[13]
  PIN boot_addr_i[12]
    DIRECTION INPUT ;
    USE SIGNAL ;
    ANTENNAPARTIALMETALAREA 0.06 LAYER M2  ;
    ANTENNAPARTIALMETALSIDEAREA 0.222 LAYER M2  ;
    ANTENNAPARTIALCUTAREA 0.04 LAYER V2  ;
    ANTENNAPARTIALMETALAREA 1.8 LAYER M3  ;
    ANTENNAPARTIALMETALSIDEAREA 6.808 LAYER M3  ;
    PORT
      LAYER M2 ;
        RECT 0.000000 201.900000 0.600000 202.100000 ;
    END
  END boot_addr_i[12]
  PIN boot_addr_i[11]
    DIRECTION INPUT ;
    USE SIGNAL ;
    ANTENNAPARTIALMETALAREA 0.02 LAYER M2  ;
    ANTENNAPARTIALMETALSIDEAREA 0.074 LAYER M2  ;
    ANTENNAPARTIALCUTAREA 0.04 LAYER V2  ;
    ANTENNAPARTIALMETALAREA 1.8 LAYER M3  ;
    ANTENNAPARTIALMETALSIDEAREA 6.808 LAYER M3  ;
    PORT
      LAYER M2 ;
        RECT 0.000000 198.900000 0.600000 199.100000 ;
    END
  END boot_addr_i[11]
  PIN boot_addr_i[10]
    DIRECTION INPUT ;
    USE SIGNAL ;
    ANTENNAPARTIALMETALAREA 0.22 LAYER M2  ;
    ANTENNAPARTIALMETALSIDEAREA 0.814 LAYER M2  ;
    ANTENNAPARTIALCUTAREA 0.04 LAYER V2  ;
    ANTENNAPARTIALMETALAREA 1.88 LAYER M3  ;
    ANTENNAPARTIALMETALSIDEAREA 7.104 LAYER M3  ;
    PORT
      LAYER M2 ;
        RECT 0.000000 195.900000 0.600000 196.100000 ;
    END
  END boot_addr_i[10]
  PIN boot_addr_i[9]
    DIRECTION INPUT ;
    USE SIGNAL ;
    ANTENNAPARTIALMETALAREA 0.02 LAYER M2  ;
    ANTENNAPARTIALMETALSIDEAREA 0.074 LAYER M2  ;
    ANTENNAPARTIALCUTAREA 0.04 LAYER V2  ;
    ANTENNAPARTIALMETALAREA 0.28 LAYER M3  ;
    ANTENNAPARTIALMETALSIDEAREA 1.184 LAYER M3  ;
    PORT
      LAYER M2 ;
        RECT 0.000000 192.900000 0.600000 193.100000 ;
    END
  END boot_addr_i[9]
  PIN boot_addr_i[8]
    DIRECTION INPUT ;
    USE SIGNAL ;
    ANTENNAPARTIALMETALAREA 0.06 LAYER M2  ;
    ANTENNAPARTIALMETALSIDEAREA 0.222 LAYER M2  ;
    ANTENNAPARTIALCUTAREA 0.04 LAYER V2  ;
    ANTENNAPARTIALMETALAREA 0.36 LAYER M3  ;
    ANTENNAPARTIALMETALSIDEAREA 1.48 LAYER M3  ;
    PORT
      LAYER M2 ;
        RECT 0.000000 189.900000 0.600000 190.100000 ;
    END
  END boot_addr_i[8]
  PIN boot_addr_i[7]
    DIRECTION INPUT ;
    USE SIGNAL ;
    PORT
      LAYER M2 ;
        RECT 0.000000 186.900000 0.600000 187.100000 ;
    END
  END boot_addr_i[7]
  PIN boot_addr_i[6]
    DIRECTION INPUT ;
    USE SIGNAL ;
    PORT
      LAYER M2 ;
        RECT 0.000000 183.900000 0.600000 184.100000 ;
    END
  END boot_addr_i[6]
  PIN boot_addr_i[5]
    DIRECTION INPUT ;
    USE SIGNAL ;
    PORT
      LAYER M2 ;
        RECT 0.000000 180.900000 0.600000 181.100000 ;
    END
  END boot_addr_i[5]
  PIN boot_addr_i[4]
    DIRECTION INPUT ;
    USE SIGNAL ;
    PORT
      LAYER M2 ;
        RECT 0.000000 177.900000 0.600000 178.100000 ;
    END
  END boot_addr_i[4]
  PIN boot_addr_i[3]
    DIRECTION INPUT ;
    USE SIGNAL ;
    PORT
      LAYER M2 ;
        RECT 0.000000 174.900000 0.600000 175.100000 ;
    END
  END boot_addr_i[3]
  PIN boot_addr_i[2]
    DIRECTION INPUT ;
    USE SIGNAL ;
    PORT
      LAYER M2 ;
        RECT 0.000000 171.900000 0.600000 172.100000 ;
    END
  END boot_addr_i[2]
  PIN boot_addr_i[1]
    DIRECTION INPUT ;
    USE SIGNAL ;
    PORT
      LAYER M2 ;
        RECT 0.000000 168.900000 0.600000 169.100000 ;
    END
  END boot_addr_i[1]
  PIN boot_addr_i[0]
    DIRECTION INPUT ;
    USE SIGNAL ;
    PORT
      LAYER M2 ;
        RECT 0.000000 165.900000 0.600000 166.100000 ;
    END
  END boot_addr_i[0]
  PIN instr_req_o
    DIRECTION OUTPUT ;
    USE SIGNAL ;
    ANTENNAPARTIALMETALAREA 8.78 LAYER M3  ;
    ANTENNAPARTIALMETALSIDEAREA 32.56 LAYER M3  ;
    ANTENNAMODEL OXIDE1 ;
    ANTENNAGATEAREA 0.3 LAYER M3  ;
    ANTENNAMAXAREACAR 158.209 LAYER M3  ;
    ANTENNAMAXSIDEAREACAR 586.476 LAYER M3  ;
    ANTENNAMAXCUTCAR 2.08333 LAYER VL  ;
    PORT
      LAYER M3 ;
        RECT 0.000000 261.900000 0.600000 262.100000 ;
    END
  END instr_req_o
  PIN instr_gnt_i
    DIRECTION INPUT ;
    USE SIGNAL ;
    ANTENNAPARTIALMETALAREA 2.76 LAYER M3  ;
    ANTENNAPARTIALMETALSIDEAREA 10.508 LAYER M3  ;
    ANTENNAMODEL OXIDE1 ;
    ANTENNAGATEAREA 0.0696 LAYER M3  ;
    ANTENNAMAXAREACAR 46.9195 LAYER M3  ;
    ANTENNAMAXSIDEAREACAR 177.069 LAYER M3  ;
    ANTENNAMAXCUTCAR 1.14943 LAYER VL  ;
    PORT
      LAYER M3 ;
        RECT 0.000000 264.900000 0.600000 265.100000 ;
    END
  END instr_gnt_i
  PIN instr_rvalid_i
    DIRECTION INPUT ;
    USE SIGNAL ;
    ANTENNAPARTIALMETALAREA 2.08 LAYER M3  ;
    ANTENNAPARTIALMETALSIDEAREA 7.992 LAYER M3  ;
    ANTENNAMODEL OXIDE1 ;
    ANTENNAGATEAREA 0.0888 LAYER M3  ;
    ANTENNAMAXAREACAR 28.2883 LAYER M3  ;
    ANTENNAMAXSIDEAREACAR 109.995 LAYER M3  ;
    ANTENNAMAXCUTCAR 0.900901 LAYER VL  ;
    PORT
      LAYER M3 ;
        RECT 0.000000 267.900000 0.600000 268.100000 ;
    END
  END instr_rvalid_i
  PIN instr_addr_o[31]
    DIRECTION OUTPUT ;
    USE SIGNAL ;
    ANTENNAPARTIALMETALAREA 2.3 LAYER M3  ;
    ANTENNAPARTIALMETALSIDEAREA 8.288 LAYER M3  ;
    ANTENNAMODEL OXIDE1 ;
    ANTENNAGATEAREA 2.56 LAYER M3  ;
    ANTENNAMAXAREACAR 1.14141 LAYER M3  ;
    ANTENNAMAXSIDEAREACAR 4.17125 LAYER M3  ;
    ANTENNAMAXCUTCAR 0.03125 LAYER VL  ;
    PORT
      LAYER M3 ;
        RECT 0.000000 273.900000 0.600000 274.100000 ;
    END
  END instr_addr_o[31]
  PIN instr_addr_o[30]
    DIRECTION OUTPUT ;
    USE SIGNAL ;
    ANTENNAPARTIALMETALAREA 3.18 LAYER M3  ;
    ANTENNAPARTIALMETALSIDEAREA 11.914 LAYER M3  ;
    ANTENNAMODEL OXIDE1 ;
    ANTENNAGATEAREA 2.56 LAYER M3  ;
    ANTENNAMAXAREACAR 1.54672 LAYER M3  ;
    ANTENNAMAXSIDEAREACAR 5.81891 LAYER M3  ;
    ANTENNAMAXCUTCAR 0.03125 LAYER VL  ;
    PORT
      LAYER M3 ;
        RECT 0.000000 276.900000 0.600000 277.100000 ;
    END
  END instr_addr_o[30]
  PIN instr_addr_o[29]
    DIRECTION OUTPUT ;
    USE SIGNAL ;
    ANTENNAPARTIALMETALAREA 2.38 LAYER M3  ;
    ANTENNAPARTIALMETALSIDEAREA 8.584 LAYER M3  ;
    ANTENNAMODEL OXIDE1 ;
    ANTENNAGATEAREA 2.56 LAYER M3  ;
    ANTENNAMAXAREACAR 1.17266 LAYER M3  ;
    ANTENNAMAXSIDEAREACAR 4.28687 LAYER M3  ;
    ANTENNAMAXCUTCAR 0.03125 LAYER VL  ;
    PORT
      LAYER M3 ;
        RECT 0.000000 279.900000 0.600000 280.100000 ;
    END
  END instr_addr_o[29]
  PIN instr_addr_o[28]
    DIRECTION OUTPUT ;
    USE SIGNAL ;
    ANTENNAPARTIALMETALAREA 2.64 LAYER M3  ;
    ANTENNAPARTIALMETALSIDEAREA 9.916 LAYER M3  ;
    ANTENNAMODEL OXIDE1 ;
    ANTENNAGATEAREA 2.56 LAYER M3  ;
    ANTENNAMAXAREACAR 1.30453 LAYER M3  ;
    ANTENNAMAXSIDEAREACAR 4.92281 LAYER M3  ;
    ANTENNAMAXCUTCAR 0.03125 LAYER VL  ;
    PORT
      LAYER M3 ;
        RECT 0.000000 282.900000 0.600000 283.100000 ;
    END
  END instr_addr_o[28]
  PIN instr_addr_o[27]
    DIRECTION OUTPUT ;
    USE SIGNAL ;
    ANTENNAPARTIALMETALAREA 5.38 LAYER M3  ;
    ANTENNAPARTIALMETALSIDEAREA 19.536 LAYER M3  ;
    ANTENNAMODEL OXIDE1 ;
    ANTENNAGATEAREA 2.56 LAYER M3  ;
    ANTENNAMAXAREACAR 3.09359 LAYER M3  ;
    ANTENNAMAXSIDEAREACAR 11.34 LAYER M3  ;
    ANTENNAMAXCUTCAR 0.03125 LAYER VL  ;
    PORT
      LAYER M3 ;
        RECT 0.000000 285.900000 0.600000 286.100000 ;
    END
  END instr_addr_o[27]
  PIN instr_addr_o[26]
    DIRECTION OUTPUT ;
    USE SIGNAL ;
    ANTENNAPARTIALMETALAREA 6.48 LAYER M3  ;
    ANTENNAPARTIALMETALSIDEAREA 24.124 LAYER M3  ;
    ANTENNAMODEL OXIDE1 ;
    ANTENNAGATEAREA 2.56 LAYER M3  ;
    ANTENNAMAXAREACAR 2.77422 LAYER M3  ;
    ANTENNAMAXSIDEAREACAR 10.3572 LAYER M3  ;
    ANTENNAMAXCUTCAR 0.03125 LAYER VL  ;
    PORT
      LAYER M3 ;
        RECT 0.000000 288.900000 0.600000 289.100000 ;
    END
  END instr_addr_o[26]
  PIN instr_addr_o[25]
    DIRECTION OUTPUT ;
    USE SIGNAL ;
    ANTENNAPARTIALMETALAREA 5.98 LAYER M3  ;
    ANTENNAPARTIALMETALSIDEAREA 21.904 LAYER M3  ;
    ANTENNAMODEL OXIDE1 ;
    ANTENNAGATEAREA 2.56 LAYER M3  ;
    ANTENNAMAXAREACAR 2.57891 LAYER M3  ;
    ANTENNAMAXSIDEAREACAR 9.49 LAYER M3  ;
    ANTENNAMAXCUTCAR 0.03125 LAYER VL  ;
    PORT
      LAYER M3 ;
        RECT 0.000000 291.900000 0.600000 292.100000 ;
    END
  END instr_addr_o[25]
  PIN instr_addr_o[24]
    DIRECTION OUTPUT ;
    USE SIGNAL ;
    ANTENNAPARTIALMETALAREA 5.68 LAYER M3  ;
    ANTENNAPARTIALMETALSIDEAREA 21.164 LAYER M3  ;
    ANTENNAMODEL OXIDE1 ;
    ANTENNAGATEAREA 2.56 LAYER M3  ;
    ANTENNAMAXAREACAR 2.46172 LAYER M3  ;
    ANTENNAMAXSIDEAREACAR 9.20094 LAYER M3  ;
    ANTENNAMAXCUTCAR 0.03125 LAYER VL  ;
    PORT
      LAYER M3 ;
        RECT 0.000000 294.900000 0.600000 295.100000 ;
    END
  END instr_addr_o[24]
  PIN instr_addr_o[23]
    DIRECTION OUTPUT ;
    USE SIGNAL ;
    ANTENNAPARTIALMETALAREA 6.22 LAYER M3  ;
    ANTENNAPARTIALMETALSIDEAREA 22.792 LAYER M3  ;
    ANTENNAMODEL OXIDE1 ;
    ANTENNAGATEAREA 2.56 LAYER M3  ;
    ANTENNAMAXAREACAR 2.67266 LAYER M3  ;
    ANTENNAMAXSIDEAREACAR 9.83687 LAYER M3  ;
    ANTENNAMAXCUTCAR 0.03125 LAYER VL  ;
    PORT
      LAYER M3 ;
        RECT 0.000000 297.900000 0.600000 298.100000 ;
    END
  END instr_addr_o[23]
  PIN instr_addr_o[22]
    DIRECTION OUTPUT ;
    USE SIGNAL ;
    ANTENNAPARTIALMETALAREA 6.08 LAYER M3  ;
    ANTENNAPARTIALMETALSIDEAREA 22.644 LAYER M3  ;
    ANTENNAMODEL OXIDE1 ;
    ANTENNAGATEAREA 2.56 LAYER M3  ;
    ANTENNAMAXAREACAR 2.61797 LAYER M3  ;
    ANTENNAMAXSIDEAREACAR 9.77906 LAYER M3  ;
    ANTENNAMAXCUTCAR 0.03125 LAYER VL  ;
    PORT
      LAYER M3 ;
        RECT 0.000000 300.900000 0.600000 301.100000 ;
    END
  END instr_addr_o[22]
  PIN instr_addr_o[21]
    DIRECTION OUTPUT ;
    USE SIGNAL ;
    ANTENNAPARTIALMETALAREA 2.3 LAYER M3  ;
    ANTENNAPARTIALMETALSIDEAREA 8.288 LAYER M3  ;
    ANTENNAMODEL OXIDE1 ;
    ANTENNAGATEAREA 1.066 LAYER M3  ;
    ANTENNAMAXAREACAR 2.70657 LAYER M3  ;
    ANTENNAMAXSIDEAREACAR 9.87054 LAYER M3  ;
    ANTENNAMAXCUTCAR 0.0750469 LAYER VL  ;
    PORT
      LAYER M3 ;
        RECT 0.000000 303.900000 0.600000 304.100000 ;
    END
  END instr_addr_o[21]
  PIN instr_addr_o[20]
    DIRECTION OUTPUT ;
    USE SIGNAL ;
    ANTENNAPARTIALMETALAREA 2.64 LAYER M3  ;
    ANTENNAPARTIALMETALSIDEAREA 9.916 LAYER M3  ;
    ANTENNAMODEL OXIDE1 ;
    ANTENNAGATEAREA 2.56 LAYER M3  ;
    ANTENNAMAXAREACAR 1.30453 LAYER M3  ;
    ANTENNAMAXSIDEAREACAR 4.92281 LAYER M3  ;
    ANTENNAMAXCUTCAR 0.03125 LAYER VL  ;
    PORT
      LAYER M3 ;
        RECT 0.000000 306.900000 0.600000 307.100000 ;
    END
  END instr_addr_o[20]
  PIN instr_addr_o[19]
    DIRECTION OUTPUT ;
    USE SIGNAL ;
    ANTENNAPARTIALMETALAREA 2.94 LAYER M3  ;
    ANTENNAPARTIALMETALSIDEAREA 10.656 LAYER M3  ;
    ANTENNAMODEL OXIDE1 ;
    ANTENNAGATEAREA 2.56 LAYER M3  ;
    ANTENNAMAXAREACAR 1.39141 LAYER M3  ;
    ANTENNAMAXSIDEAREACAR 5.09625 LAYER M3  ;
    ANTENNAMAXCUTCAR 0.03125 LAYER VL  ;
    PORT
      LAYER M3 ;
        RECT 0.000000 309.900000 0.600000 310.100000 ;
    END
  END instr_addr_o[19]
  PIN instr_addr_o[18]
    DIRECTION OUTPUT ;
    USE SIGNAL ;
    ANTENNAPARTIALMETALAREA 2.16 LAYER M3  ;
    ANTENNAPARTIALMETALSIDEAREA 8.14 LAYER M3  ;
    ANTENNAMODEL OXIDE1 ;
    ANTENNAGATEAREA 2.56 LAYER M3  ;
    ANTENNAMAXAREACAR 1.08672 LAYER M3  ;
    ANTENNAMAXSIDEAREACAR 4.11344 LAYER M3  ;
    ANTENNAMAXCUTCAR 0.03125 LAYER VL  ;
    PORT
      LAYER M3 ;
        RECT 0.000000 312.900000 0.600000 313.100000 ;
    END
  END instr_addr_o[18]
  PIN instr_addr_o[17]
    DIRECTION OUTPUT ;
    USE SIGNAL ;
    ANTENNAPARTIALMETALAREA 5.82 LAYER M3  ;
    ANTENNAPARTIALMETALSIDEAREA 21.312 LAYER M3  ;
    ANTENNAMODEL OXIDE1 ;
    ANTENNAGATEAREA 2.56 LAYER M3  ;
    ANTENNAMAXAREACAR 2.51641 LAYER M3  ;
    ANTENNAMAXSIDEAREACAR 9.25875 LAYER M3  ;
    ANTENNAMAXCUTCAR 0.03125 LAYER VL  ;
    PORT
      LAYER M3 ;
        RECT 0.000000 315.900000 0.600000 316.100000 ;
    END
  END instr_addr_o[17]
  PIN instr_addr_o[16]
    DIRECTION OUTPUT ;
    USE SIGNAL ;
    ANTENNAPARTIALMETALAREA 6.16 LAYER M3  ;
    ANTENNAPARTIALMETALSIDEAREA 22.94 LAYER M3  ;
    ANTENNAMODEL OXIDE1 ;
    ANTENNAGATEAREA 2.56 LAYER M3  ;
    ANTENNAMAXAREACAR 2.64922 LAYER M3  ;
    ANTENNAMAXSIDEAREACAR 9.89469 LAYER M3  ;
    ANTENNAMAXCUTCAR 0.03125 LAYER VL  ;
    PORT
      LAYER M3 ;
        RECT 0.000000 318.900000 0.600000 319.100000 ;
    END
  END instr_addr_o[16]
  PIN instr_addr_o[15]
    DIRECTION OUTPUT ;
    USE SIGNAL ;
    ANTENNAPARTIALMETALAREA 5.66 LAYER M3  ;
    ANTENNAPARTIALMETALSIDEAREA 20.72 LAYER M3  ;
    ANTENNAMODEL OXIDE1 ;
    ANTENNAGATEAREA 2.56 LAYER M3  ;
    ANTENNAMAXAREACAR 2.48422 LAYER M3  ;
    ANTENNAMAXSIDEAREACAR 9.14312 LAYER M3  ;
    ANTENNAMAXCUTCAR 0.03125 LAYER VL  ;
    PORT
      LAYER M3 ;
        RECT 0.000000 321.900000 0.600000 322.100000 ;
    END
  END instr_addr_o[15]
  PIN instr_addr_o[14]
    DIRECTION OUTPUT ;
    USE SIGNAL ;
    ANTENNAPARTIALMETALAREA 5.78 LAYER M3  ;
    ANTENNAPARTIALMETALSIDEAREA 21.682 LAYER M3  ;
    ANTENNAMODEL OXIDE1 ;
    ANTENNAGATEAREA 2.56 LAYER M3  ;
    ANTENNAMAXAREACAR 2.50078 LAYER M3  ;
    ANTENNAMAXSIDEAREACAR 9.40328 LAYER M3  ;
    ANTENNAMAXCUTCAR 0.03125 LAYER VL  ;
    PORT
      LAYER M3 ;
        RECT 0.000000 324.900000 0.600000 325.100000 ;
    END
  END instr_addr_o[14]
  PIN instr_addr_o[13]
    DIRECTION OUTPUT ;
    USE SIGNAL ;
    ANTENNAPARTIALMETALAREA 4.38 LAYER M3  ;
    ANTENNAPARTIALMETALSIDEAREA 15.984 LAYER M3  ;
    ANTENNAMODEL OXIDE1 ;
    ANTENNAGATEAREA 2.56 LAYER M3  ;
    ANTENNAMAXAREACAR 1.95391 LAYER M3  ;
    ANTENNAMAXSIDEAREACAR 7.1775 LAYER M3  ;
    ANTENNAMAXCUTCAR 0.03125 LAYER VL  ;
    PORT
      LAYER M3 ;
        RECT 0.000000 327.900000 0.600000 328.100000 ;
    END
  END instr_addr_o[13]
  PIN instr_addr_o[12]
    DIRECTION OUTPUT ;
    USE SIGNAL ;
    ANTENNAPARTIALMETALAREA 2.16 LAYER M3  ;
    ANTENNAPARTIALMETALSIDEAREA 8.14 LAYER M3  ;
    ANTENNAMODEL OXIDE1 ;
    ANTENNAGATEAREA 2.56 LAYER M3  ;
    ANTENNAMAXAREACAR 1.11703 LAYER M3  ;
    ANTENNAMAXSIDEAREACAR 4.22906 LAYER M3  ;
    ANTENNAMAXCUTCAR 0.03125 LAYER VL  ;
    PORT
      LAYER M3 ;
        RECT 0.000000 330.900000 0.600000 331.100000 ;
    END
  END instr_addr_o[12]
  PIN instr_addr_o[11]
    DIRECTION OUTPUT ;
    USE SIGNAL ;
    ANTENNAPARTIALMETALAREA 5.26 LAYER M3  ;
    ANTENNAPARTIALMETALSIDEAREA 19.24 LAYER M3  ;
    ANTENNAMODEL OXIDE1 ;
    ANTENNAGATEAREA 2.56 LAYER M3  ;
    ANTENNAMAXAREACAR 2.29766 LAYER M3  ;
    ANTENNAMAXSIDEAREACAR 8.44938 LAYER M3  ;
    ANTENNAMAXCUTCAR 0.03125 LAYER VL  ;
    PORT
      LAYER M3 ;
        RECT 0.000000 333.900000 0.600000 334.100000 ;
    END
  END instr_addr_o[11]
  PIN instr_addr_o[10]
    DIRECTION OUTPUT ;
    USE SIGNAL ;
    ANTENNAPARTIALMETALAREA 3.8 LAYER M3  ;
    ANTENNAPARTIALMETALSIDEAREA 14.06 LAYER M3  ;
    ANTENNAMODEL OXIDE1 ;
    ANTENNAGATEAREA 2.56 LAYER M3  ;
    ANTENNAMAXAREACAR 4.10141 LAYER M3  ;
    ANTENNAMAXSIDEAREACAR 15.2134 LAYER M3  ;
    ANTENNAMAXCUTCAR 0.03125 LAYER VL  ;
    PORT
      LAYER M3 ;
        RECT 0.000000 336.900000 0.600000 337.100000 ;
    END
  END instr_addr_o[10]
  PIN instr_addr_o[9]
    DIRECTION OUTPUT ;
    USE SIGNAL ;
    ANTENNAPARTIALMETALAREA 5.54 LAYER M3  ;
    ANTENNAPARTIALMETALSIDEAREA 20.128 LAYER M3  ;
    ANTENNAMODEL OXIDE1 ;
    ANTENNAGATEAREA 2.56 LAYER M3  ;
    ANTENNAMAXAREACAR 4.56234 LAYER M3  ;
    ANTENNAMAXSIDEAREACAR 16.7744 LAYER M3  ;
    ANTENNAMAXCUTCAR 0.03125 LAYER VL  ;
    PORT
      LAYER M3 ;
        RECT 0.000000 339.900000 0.600000 340.100000 ;
    END
  END instr_addr_o[9]
  PIN instr_addr_o[8]
    DIRECTION OUTPUT ;
    USE SIGNAL ;
    ANTENNAPARTIALMETALAREA 4.32 LAYER M3  ;
    ANTENNAPARTIALMETALSIDEAREA 16.132 LAYER M3  ;
    ANTENNAMODEL OXIDE1 ;
    ANTENNAGATEAREA 2.56 LAYER M3  ;
    ANTENNAMAXAREACAR 1.96078 LAYER M3  ;
    ANTENNAMAXSIDEAREACAR 7.35094 LAYER M3  ;
    ANTENNAMAXCUTCAR 0.03125 LAYER VL  ;
    PORT
      LAYER M3 ;
        RECT 0.000000 342.900000 0.600000 343.100000 ;
    END
  END instr_addr_o[8]
  PIN instr_addr_o[7]
    DIRECTION OUTPUT ;
    USE SIGNAL ;
    ANTENNAPARTIALMETALAREA 5.18 LAYER M3  ;
    ANTENNAPARTIALMETALSIDEAREA 18.944 LAYER M3  ;
    ANTENNAMODEL OXIDE1 ;
    ANTENNAGATEAREA 2.56 LAYER M3  ;
    ANTENNAMAXAREACAR 2.26641 LAYER M3  ;
    ANTENNAMAXSIDEAREACAR 8.33375 LAYER M3  ;
    ANTENNAMAXCUTCAR 0.03125 LAYER VL  ;
    PORT
      LAYER M3 ;
        RECT 0.000000 345.900000 0.600000 346.100000 ;
    END
  END instr_addr_o[7]
  PIN instr_addr_o[6]
    DIRECTION OUTPUT ;
    USE SIGNAL ;
    ANTENNAPARTIALMETALAREA 4.64 LAYER M3  ;
    ANTENNAPARTIALMETALSIDEAREA 17.316 LAYER M3  ;
    PORT
      LAYER M3 ;
        RECT 0.000000 348.900000 0.600000 349.100000 ;
    END
  END instr_addr_o[6]
  PIN instr_addr_o[5]
    DIRECTION OUTPUT ;
    USE SIGNAL ;
    ANTENNAPARTIALMETALAREA 3.58 LAYER M3  ;
    ANTENNAPARTIALMETALSIDEAREA 13.024 LAYER M3  ;
    ANTENNAMODEL OXIDE1 ;
    ANTENNAGATEAREA 4.044 LAYER M3  ;
    ANTENNAMAXAREACAR 1.17109 LAYER M3  ;
    ANTENNAMAXSIDEAREACAR 4.25816 LAYER M3  ;
    ANTENNAMAXCUTCAR 0.0197824 LAYER VL  ;
    PORT
      LAYER M3 ;
        RECT 0.000000 351.900000 0.600000 352.100000 ;
    END
  END instr_addr_o[5]
  PIN instr_addr_o[4]
    DIRECTION OUTPUT ;
    USE SIGNAL ;
    ANTENNAPARTIALMETALAREA 3.84 LAYER M3  ;
    ANTENNAPARTIALMETALSIDEAREA 14.356 LAYER M3  ;
    PORT
      LAYER M3 ;
        RECT 0.000000 354.900000 0.600000 355.100000 ;
    END
  END instr_addr_o[4]
  PIN instr_addr_o[3]
    DIRECTION OUTPUT ;
    USE SIGNAL ;
    ANTENNAPARTIALMETALAREA 4.7 LAYER M3  ;
    ANTENNAPARTIALMETALSIDEAREA 17.168 LAYER M3  ;
    ANTENNAMODEL OXIDE1 ;
    ANTENNAGATEAREA 4.044 LAYER M3  ;
    ANTENNAMAXAREACAR 1.43301 LAYER M3  ;
    ANTENNAMAXSIDEAREACAR 5.21978 LAYER M3  ;
    ANTENNAMAXCUTCAR 0.0197824 LAYER VL  ;
    PORT
      LAYER M3 ;
        RECT 0.000000 357.900000 0.600000 358.100000 ;
    END
  END instr_addr_o[3]
  PIN instr_addr_o[2]
    DIRECTION OUTPUT ;
    USE SIGNAL ;
    ANTENNAPARTIALMETALAREA 5.2 LAYER M3  ;
    ANTENNAPARTIALMETALSIDEAREA 19.388 LAYER M3  ;
    ANTENNAMODEL OXIDE1 ;
    ANTENNAGATEAREA 4.044 LAYER M3  ;
    ANTENNAMAXAREACAR 1.55665 LAYER M3  ;
    ANTENNAMAXSIDEAREACAR 5.76874 LAYER M3  ;
    ANTENNAMAXCUTCAR 0.0197824 LAYER VL  ;
    PORT
      LAYER M3 ;
        RECT 0.000000 360.900000 0.600000 361.100000 ;
    END
  END instr_addr_o[2]
  PIN instr_addr_o[1]
    DIRECTION OUTPUT ;
    USE SIGNAL ;
    PORT
      LAYER M3 ;
        RECT 0.000000 363.900000 0.600000 364.100000 ;
    END
  END instr_addr_o[1]
  PIN instr_addr_o[0]
    DIRECTION OUTPUT ;
    USE SIGNAL ;
    PORT
      LAYER M3 ;
        RECT 0.000000 366.900000 0.600000 367.100000 ;
    END
  END instr_addr_o[0]
  PIN instr_rdata_i[31]
    DIRECTION INPUT ;
    USE SIGNAL ;
    ANTENNAPARTIALMETALAREA 1.98 LAYER M3  ;
    ANTENNAPARTIALMETALSIDEAREA 7.104 LAYER M3  ;
    PORT
      LAYER M3 ;
        RECT 0.000000 369.900000 0.600000 370.100000 ;
    END
  END instr_rdata_i[31]
  PIN instr_rdata_i[30]
    DIRECTION INPUT ;
    USE SIGNAL ;
    ANTENNAPARTIALMETALAREA 0.52 LAYER M3  ;
    ANTENNAPARTIALMETALSIDEAREA 1.924 LAYER M3  ;
    PORT
      LAYER M3 ;
        RECT 0.000000 372.900000 0.600000 373.100000 ;
    END
  END instr_rdata_i[30]
  PIN instr_rdata_i[29]
    DIRECTION INPUT ;
    USE SIGNAL ;
    ANTENNAPARTIALMETALAREA 1.86 LAYER M3  ;
    ANTENNAPARTIALMETALSIDEAREA 6.512 LAYER M3  ;
    PORT
      LAYER M3 ;
        RECT 0.000000 375.900000 0.600000 376.100000 ;
    END
  END instr_rdata_i[29]
  PIN instr_rdata_i[28]
    DIRECTION INPUT ;
    USE SIGNAL ;
    ANTENNAPARTIALMETALAREA 0.44 LAYER M3  ;
    ANTENNAPARTIALMETALSIDEAREA 1.628 LAYER M3  ;
    PORT
      LAYER M3 ;
        RECT 0.000000 378.900000 0.600000 379.100000 ;
    END
  END instr_rdata_i[28]
  PIN instr_rdata_i[27]
    DIRECTION INPUT ;
    USE SIGNAL ;
    ANTENNAPARTIALMETALAREA 0.34 LAYER M3  ;
    ANTENNAPARTIALMETALSIDEAREA 0.888 LAYER M3  ;
    PORT
      LAYER M3 ;
        RECT 0.000000 381.900000 0.600000 382.100000 ;
    END
  END instr_rdata_i[27]
  PIN instr_rdata_i[26]
    DIRECTION INPUT ;
    USE SIGNAL ;
    ANTENNAPARTIALMETALAREA 0.36 LAYER M3  ;
    ANTENNAPARTIALMETALSIDEAREA 1.332 LAYER M3  ;
    PORT
      LAYER M3 ;
        RECT 0.000000 384.900000 0.600000 385.100000 ;
    END
  END instr_rdata_i[26]
  PIN instr_rdata_i[25]
    DIRECTION INPUT ;
    USE SIGNAL ;
    ANTENNAPARTIALMETALAREA 1.88 LAYER M3  ;
    ANTENNAPARTIALMETALSIDEAREA 7.104 LAYER M3  ;
    ANTENNAMODEL OXIDE1 ;
    ANTENNAGATEAREA 0.0888 LAYER M3  ;
    ANTENNAMAXAREACAR 23.3333 LAYER M3  ;
    ANTENNAMAXSIDEAREACAR 89.9955 LAYER M3  ;
    ANTENNAMAXCUTCAR 0.900901 LAYER VL  ;
    PORT
      LAYER M3 ;
        RECT 0.000000 387.900000 0.600000 388.100000 ;
    END
  END instr_rdata_i[25]
  PIN instr_rdata_i[24]
    DIRECTION INPUT ;
    USE SIGNAL ;
    ANTENNAPARTIALMETALAREA 1.72 LAYER M3  ;
    ANTENNAPARTIALMETALSIDEAREA 6.364 LAYER M3  ;
    PORT
      LAYER M3 ;
        RECT 0.000000 390.900000 0.600000 391.100000 ;
    END
  END instr_rdata_i[24]
  PIN instr_rdata_i[23]
    DIRECTION INPUT ;
    USE SIGNAL ;
    ANTENNAPARTIALMETALAREA 2.24 LAYER M3  ;
    ANTENNAPARTIALMETALSIDEAREA 8.584 LAYER M3  ;
    ANTENNAMODEL OXIDE1 ;
    ANTENNAGATEAREA 0.0888 LAYER M3  ;
    ANTENNAMAXAREACAR 29.1892 LAYER M3  ;
    ANTENNAMAXSIDEAREACAR 113.329 LAYER M3  ;
    ANTENNAMAXCUTCAR 0.900901 LAYER VL  ;
    PORT
      LAYER M3 ;
        RECT 0.000000 393.900000 0.600000 394.100000 ;
    END
  END instr_rdata_i[23]
  PIN instr_rdata_i[22]
    DIRECTION INPUT ;
    USE SIGNAL ;
    ANTENNAPARTIALMETALAREA 1.72 LAYER M3  ;
    ANTENNAPARTIALMETALSIDEAREA 6.364 LAYER M3  ;
    PORT
      LAYER M3 ;
        RECT 0.000000 396.900000 0.600000 397.100000 ;
    END
  END instr_rdata_i[22]
  PIN instr_rdata_i[21]
    DIRECTION INPUT ;
    USE SIGNAL ;
    ANTENNAPARTIALMETALAREA 2 LAYER M3  ;
    ANTENNAPARTIALMETALSIDEAREA 7.696 LAYER M3  ;
    ANTENNAMODEL OXIDE1 ;
    ANTENNAGATEAREA 0.0888 LAYER M3  ;
    ANTENNAMAXAREACAR 24.518 LAYER M3  ;
    ANTENNAMAXSIDEAREACAR 96.3559 LAYER M3  ;
    ANTENNAMAXCUTCAR 0.900901 LAYER VL  ;
    PORT
      LAYER M3 ;
        RECT 0.000000 399.900000 0.600000 400.100000 ;
    END
  END instr_rdata_i[21]
  PIN instr_rdata_i[20]
    DIRECTION INPUT ;
    USE SIGNAL ;
    ANTENNAPARTIALMETALAREA 1.76 LAYER M3  ;
    ANTENNAPARTIALMETALSIDEAREA 6.66 LAYER M3  ;
    PORT
      LAYER M3 ;
        RECT 0.000000 402.900000 0.600000 403.100000 ;
    END
  END instr_rdata_i[20]
  PIN instr_rdata_i[19]
    DIRECTION INPUT ;
    USE SIGNAL ;
    ANTENNAPARTIALMETALAREA 0.66 LAYER M3  ;
    ANTENNAPARTIALMETALSIDEAREA 2.072 LAYER M3  ;
    PORT
      LAYER M3 ;
        RECT 0.000000 405.900000 0.600000 406.100000 ;
    END
  END instr_rdata_i[19]
  PIN instr_rdata_i[18]
    DIRECTION INPUT ;
    USE SIGNAL ;
    ANTENNAPARTIALMETALAREA 0.28 LAYER M3  ;
    ANTENNAPARTIALMETALSIDEAREA 1.036 LAYER M3  ;
    PORT
      LAYER M3 ;
        RECT 0.000000 408.900000 0.600000 409.100000 ;
    END
  END instr_rdata_i[18]
  PIN instr_rdata_i[17]
    DIRECTION INPUT ;
    USE SIGNAL ;
    ANTENNAPARTIALMETALAREA 2.92 LAYER M3  ;
    ANTENNAPARTIALMETALSIDEAREA 10.952 LAYER M3  ;
    ANTENNAMODEL OXIDE1 ;
    ANTENNAGATEAREA 0.0888 LAYER M3  ;
    ANTENNAMAXAREACAR 45.8559 LAYER M3  ;
    ANTENNAMAXSIDEAREACAR 173.329 LAYER M3  ;
    ANTENNAMAXCUTCAR 0.900901 LAYER VL  ;
    PORT
      LAYER M3 ;
        RECT 0.000000 411.900000 0.600000 412.100000 ;
    END
  END instr_rdata_i[17]
  PIN instr_rdata_i[16]
    DIRECTION INPUT ;
    USE SIGNAL ;
    ANTENNAPARTIALMETALAREA 2.6 LAYER M3  ;
    ANTENNAPARTIALMETALSIDEAREA 9.916 LAYER M3  ;
    ANTENNAMODEL OXIDE1 ;
    ANTENNAGATEAREA 0.0888 LAYER M3  ;
    ANTENNAMAXAREACAR 32.3423 LAYER M3  ;
    ANTENNAMAXSIDEAREACAR 124.995 LAYER M3  ;
    ANTENNAMAXCUTCAR 0.900901 LAYER VL  ;
    PORT
      LAYER M3 ;
        RECT 0.000000 414.900000 0.600000 415.100000 ;
    END
  END instr_rdata_i[16]
  PIN instr_rdata_i[15]
    DIRECTION INPUT ;
    USE SIGNAL ;
    ANTENNAPARTIALMETALAREA 0.5 LAYER M3  ;
    ANTENNAPARTIALMETALSIDEAREA 1.48 LAYER M3  ;
    PORT
      LAYER M3 ;
        RECT 0.000000 417.900000 0.600000 418.100000 ;
    END
  END instr_rdata_i[15]
  PIN instr_rdata_i[14]
    DIRECTION INPUT ;
    USE SIGNAL ;
    ANTENNAPARTIALMETALAREA 1.96 LAYER M3  ;
    ANTENNAPARTIALMETALSIDEAREA 7.548 LAYER M3  ;
    ANTENNAMODEL OXIDE1 ;
    ANTENNAGATEAREA 0.0888 LAYER M3  ;
    ANTENNAMAXAREACAR 25.1351 LAYER M3  ;
    ANTENNAMAXSIDEAREACAR 98.3288 LAYER M3  ;
    ANTENNAMAXCUTCAR 0.900901 LAYER VL  ;
    PORT
      LAYER M3 ;
        RECT 0.000000 420.900000 0.600000 421.100000 ;
    END
  END instr_rdata_i[14]
  PIN instr_rdata_i[13]
    DIRECTION INPUT ;
    USE SIGNAL ;
    ANTENNAPARTIALMETALAREA 2.08 LAYER M3  ;
    ANTENNAPARTIALMETALSIDEAREA 7.992 LAYER M3  ;
    ANTENNAMODEL OXIDE1 ;
    ANTENNAGATEAREA 0.0888 LAYER M3  ;
    ANTENNAMAXAREACAR 25.4189 LAYER M3  ;
    ANTENNAMAXSIDEAREACAR 99.6892 LAYER M3  ;
    ANTENNAMAXCUTCAR 0.900901 LAYER VL  ;
    PORT
      LAYER M3 ;
        RECT 0.000000 423.900000 0.600000 424.100000 ;
    END
  END instr_rdata_i[13]
  PIN instr_rdata_i[12]
    DIRECTION INPUT ;
    USE SIGNAL ;
    ANTENNAPARTIALMETALAREA 1.96 LAYER M3  ;
    ANTENNAPARTIALMETALSIDEAREA 7.548 LAYER M3  ;
    ANTENNAMODEL OXIDE1 ;
    ANTENNAGATEAREA 0.0888 LAYER M3  ;
    ANTENNAMAXAREACAR 26.036 LAYER M3  ;
    ANTENNAMAXSIDEAREACAR 101.662 LAYER M3  ;
    ANTENNAMAXCUTCAR 0.900901 LAYER VL  ;
    PORT
      LAYER M3 ;
        RECT 0.000000 426.900000 0.600000 427.100000 ;
    END
  END instr_rdata_i[12]
  PIN instr_rdata_i[11]
    DIRECTION INPUT ;
    USE SIGNAL ;
    ANTENNAPARTIALMETALAREA 2.4 LAYER M3  ;
    ANTENNAPARTIALMETALSIDEAREA 9.176 LAYER M3  ;
    ANTENNAMODEL OXIDE1 ;
    ANTENNAGATEAREA 0.0888 LAYER M3  ;
    ANTENNAMAXAREACAR 30.991 LAYER M3  ;
    ANTENNAMAXSIDEAREACAR 119.995 LAYER M3  ;
    ANTENNAMAXCUTCAR 0.900901 LAYER VL  ;
    PORT
      LAYER M3 ;
        RECT 0.000000 429.900000 0.600000 430.100000 ;
    END
  END instr_rdata_i[11]
  PIN instr_rdata_i[10]
    DIRECTION INPUT ;
    USE SIGNAL ;
    ANTENNAPARTIALMETALAREA 2.04 LAYER M3  ;
    ANTENNAPARTIALMETALSIDEAREA 7.844 LAYER M3  ;
    ANTENNAMODEL OXIDE1 ;
    ANTENNAGATEAREA 0.0888 LAYER M3  ;
    ANTENNAMAXAREACAR 26.036 LAYER M3  ;
    ANTENNAMAXSIDEAREACAR 101.662 LAYER M3  ;
    ANTENNAMAXCUTCAR 0.900901 LAYER VL  ;
    PORT
      LAYER M3 ;
        RECT 0.000000 432.900000 0.600000 433.100000 ;
    END
  END instr_rdata_i[10]
  PIN instr_rdata_i[9]
    DIRECTION INPUT ;
    USE SIGNAL ;
    ANTENNAPARTIALMETALAREA 1.9 LAYER M3  ;
    ANTENNAPARTIALMETALSIDEAREA 6.808 LAYER M3  ;
    PORT
      LAYER M3 ;
        RECT 0.000000 435.900000 0.600000 436.100000 ;
    END
  END instr_rdata_i[9]
  PIN instr_rdata_i[8]
    DIRECTION INPUT ;
    USE SIGNAL ;
    ANTENNAPARTIALMETALAREA 0.2 LAYER M3  ;
    ANTENNAPARTIALMETALSIDEAREA 0.74 LAYER M3  ;
    PORT
      LAYER M3 ;
        RECT 0.000000 438.900000 0.600000 439.100000 ;
    END
  END instr_rdata_i[8]
  PIN instr_rdata_i[7]
    DIRECTION INPUT ;
    USE SIGNAL ;
    ANTENNAPARTIALMETALAREA 0.42 LAYER M3  ;
    ANTENNAPARTIALMETALSIDEAREA 1.184 LAYER M3  ;
    PORT
      LAYER M3 ;
        RECT 0.000000 441.900000 0.600000 442.100000 ;
    END
  END instr_rdata_i[7]
  PIN instr_rdata_i[6]
    DIRECTION INPUT ;
    USE SIGNAL ;
    ANTENNAPARTIALMETALAREA 1.76 LAYER M3  ;
    ANTENNAPARTIALMETALSIDEAREA 6.66 LAYER M3  ;
    PORT
      LAYER M3 ;
        RECT 0.000000 444.900000 0.600000 445.100000 ;
    END
  END instr_rdata_i[6]
  PIN instr_rdata_i[5]
    DIRECTION INPUT ;
    USE SIGNAL ;
    ANTENNAPARTIALMETALAREA 0.58 LAYER M3  ;
    ANTENNAPARTIALMETALSIDEAREA 1.776 LAYER M3  ;
    PORT
      LAYER M3 ;
        RECT 0.000000 447.900000 0.600000 448.100000 ;
    END
  END instr_rdata_i[5]
  PIN instr_rdata_i[4]
    DIRECTION INPUT ;
    USE SIGNAL ;
    ANTENNAPARTIALMETALAREA 1.76 LAYER M3  ;
    ANTENNAPARTIALMETALSIDEAREA 6.66 LAYER M3  ;
    PORT
      LAYER M3 ;
        RECT 0.000000 450.900000 0.600000 451.100000 ;
    END
  END instr_rdata_i[4]
  PIN instr_rdata_i[3]
    DIRECTION INPUT ;
    USE SIGNAL ;
    ANTENNAPARTIALMETALAREA 0.5 LAYER M3  ;
    ANTENNAPARTIALMETALSIDEAREA 1.48 LAYER M3  ;
    PORT
      LAYER M3 ;
        RECT 0.000000 453.900000 0.600000 454.100000 ;
    END
  END instr_rdata_i[3]
  PIN instr_rdata_i[2]
    DIRECTION INPUT ;
    USE SIGNAL ;
    ANTENNAPARTIALMETALAREA 0.28 LAYER M3  ;
    ANTENNAPARTIALMETALSIDEAREA 1.036 LAYER M3  ;
    PORT
      LAYER M3 ;
        RECT 0.000000 456.900000 0.600000 457.100000 ;
    END
  END instr_rdata_i[2]
  PIN instr_rdata_i[1]
    DIRECTION INPUT ;
    USE SIGNAL ;
    ANTENNAPARTIALMETALAREA 2.04 LAYER M3  ;
    ANTENNAPARTIALMETALSIDEAREA 7.696 LAYER M3  ;
    ANTENNAMODEL OXIDE1 ;
    ANTENNAGATEAREA 0.0888 LAYER M3  ;
    ANTENNAMAXAREACAR 24.9685 LAYER M3  ;
    ANTENNAMAXSIDEAREACAR 96.3559 LAYER M3  ;
    ANTENNAMAXCUTCAR 0.900901 LAYER VL  ;
    PORT
      LAYER M3 ;
        RECT 0.000000 459.900000 0.600000 460.100000 ;
    END
  END instr_rdata_i[1]
  PIN instr_rdata_i[0]
    DIRECTION INPUT ;
    USE SIGNAL ;
    ANTENNAPARTIALMETALAREA 1.88 LAYER M3  ;
    ANTENNAPARTIALMETALSIDEAREA 7.252 LAYER M3  ;
    ANTENNAMODEL OXIDE1 ;
    ANTENNAGATEAREA 0.0888 LAYER M3  ;
    ANTENNAMAXAREACAR 24.2342 LAYER M3  ;
    ANTENNAMAXSIDEAREACAR 94.9955 LAYER M3  ;
    ANTENNAMAXCUTCAR 0.900901 LAYER VL  ;
    PORT
      LAYER M3 ;
        RECT 0.000000 462.900000 0.600000 463.100000 ;
    END
  END instr_rdata_i[0]
  PIN instr_rdata_intg_i[6]
    DIRECTION INPUT ;
    USE SIGNAL ;
    PORT
      LAYER M3 ;
        RECT 0.000000 465.900000 0.600000 466.100000 ;
    END
  END instr_rdata_intg_i[6]
  PIN instr_rdata_intg_i[5]
    DIRECTION INPUT ;
    USE SIGNAL ;
    PORT
      LAYER M3 ;
        RECT 0.000000 468.900000 0.600000 469.100000 ;
    END
  END instr_rdata_intg_i[5]
  PIN instr_rdata_intg_i[4]
    DIRECTION INPUT ;
    USE SIGNAL ;
    PORT
      LAYER M3 ;
        RECT 0.000000 471.900000 0.600000 472.100000 ;
    END
  END instr_rdata_intg_i[4]
  PIN instr_rdata_intg_i[3]
    DIRECTION INPUT ;
    USE SIGNAL ;
    PORT
      LAYER M3 ;
        RECT 0.000000 474.900000 0.600000 475.100000 ;
    END
  END instr_rdata_intg_i[3]
  PIN instr_rdata_intg_i[2]
    DIRECTION INPUT ;
    USE SIGNAL ;
    PORT
      LAYER M3 ;
        RECT 0.000000 477.900000 0.600000 478.100000 ;
    END
  END instr_rdata_intg_i[2]
  PIN instr_rdata_intg_i[1]
    DIRECTION INPUT ;
    USE SIGNAL ;
    PORT
      LAYER M3 ;
        RECT 0.000000 480.900000 0.600000 481.100000 ;
    END
  END instr_rdata_intg_i[1]
  PIN instr_rdata_intg_i[0]
    DIRECTION INPUT ;
    USE SIGNAL ;
    PORT
      LAYER M3 ;
        RECT 0.000000 483.900000 0.600000 484.100000 ;
    END
  END instr_rdata_intg_i[0]
  PIN instr_err_i
    DIRECTION INPUT ;
    USE SIGNAL ;
    ANTENNAPARTIALMETALAREA 2.12 LAYER M3  ;
    ANTENNAPARTIALMETALSIDEAREA 8.14 LAYER M3  ;
    ANTENNAMODEL OXIDE1 ;
    ANTENNAGATEAREA 0.0888 LAYER M3  ;
    ANTENNAMAXAREACAR 25.8694 LAYER M3  ;
    ANTENNAMAXSIDEAREACAR 101.356 LAYER M3  ;
    ANTENNAMAXCUTCAR 0.900901 LAYER VL  ;
    PORT
      LAYER M3 ;
        RECT 0.000000 270.900000 0.600000 271.100000 ;
    END
  END instr_err_i
  PIN data_req_o
    DIRECTION OUTPUT ;
    USE SIGNAL ;
    ANTENNAPARTIALMETALAREA 1.06 LAYER M2  ;
    ANTENNAPARTIALMETALSIDEAREA 3.552 LAYER M2  ;
    ANTENNAPARTIALCUTAREA 0.04 LAYER V2  ;
    ANTENNAPARTIALMETALAREA 41.48 LAYER M3  ;
    ANTENNAPARTIALMETALSIDEAREA 153.624 LAYER M3  ;
    ANTENNAMODEL OXIDE1 ;
    ANTENNAGATEAREA 2.112 LAYER M3  ;
    ANTENNAMAXAREACAR 22.8235 LAYER M3  ;
    ANTENNAMAXSIDEAREACAR 84.5205 LAYER M3  ;
    ANTENNAMAXCUTCAR 0.0378788 LAYER VL  ;
    PORT
      LAYER M2 ;
        RECT 33.900000 0.000000 34.100000 0.600000 ;
    END
  END data_req_o
  PIN data_gnt_i
    DIRECTION INPUT ;
    USE SIGNAL ;
    ANTENNAPARTIALMETALAREA 0.34 LAYER M2  ;
    ANTENNAPARTIALMETALSIDEAREA 0.888 LAYER M2  ;
    ANTENNAPARTIALCUTAREA 0.04 LAYER V2  ;
    ANTENNAPARTIALMETALAREA 0.2 LAYER M3  ;
    ANTENNAPARTIALMETALSIDEAREA 0.888 LAYER M3  ;
    PORT
      LAYER M2 ;
        RECT 37.900000 0.000000 38.100000 0.600000 ;
    END
  END data_gnt_i
  PIN data_rvalid_i
    DIRECTION INPUT ;
    USE SIGNAL ;
    ANTENNAPARTIALMETALAREA 2.02 LAYER M2  ;
    ANTENNAPARTIALMETALSIDEAREA 7.104 LAYER M2  ;
    PORT
      LAYER M2 ;
        RECT 41.900000 0.000000 42.100000 0.600000 ;
    END
  END data_rvalid_i
  PIN data_we_o
    DIRECTION OUTPUT ;
    USE SIGNAL ;
    ANTENNAPARTIALMETALAREA 13.42 LAYER M2  ;
    ANTENNAPARTIALMETALSIDEAREA 49.284 LAYER M2  ;
    ANTENNAPARTIALCUTAREA 0.12 LAYER V2  ;
    ANTENNAPARTIALMETALAREA 55.32 LAYER M3  ;
    ANTENNAPARTIALMETALSIDEAREA 205.128 LAYER M3  ;
    ANTENNAMODEL OXIDE1 ;
    ANTENNAGATEAREA 3.0444 LAYER M3  ;
    ANTENNAMAXAREACAR 20.3861 LAYER M3  ;
    ANTENNAMAXSIDEAREACAR 77.8465 LAYER M3  ;
    ANTENNAMAXCUTCAR 1.07527 LAYER VL  ;
    PORT
      LAYER M2 ;
        RECT 45.900000 0.000000 46.100000 0.600000 ;
    END
  END data_we_o
  PIN data_be_o[3]
    DIRECTION OUTPUT ;
    USE SIGNAL ;
    ANTENNAPARTIALMETALAREA 2.02 LAYER M2  ;
    ANTENNAPARTIALMETALSIDEAREA 7.104 LAYER M2  ;
    ANTENNAPARTIALCUTAREA 0.04 LAYER V2  ;
    ANTENNAPARTIALMETALAREA 30.44 LAYER M3  ;
    ANTENNAPARTIALMETALSIDEAREA 112.776 LAYER M3  ;
    ANTENNAMODEL OXIDE1 ;
    ANTENNAGATEAREA 2.848 LAYER M3  ;
    ANTENNAMAXAREACAR 10.8991 LAYER M3  ;
    ANTENNAMAXSIDEAREACAR 40.3087 LAYER M3  ;
    ANTENNAMAXCUTCAR 0.0280899 LAYER VL  ;
    PORT
      LAYER M2 ;
        RECT 53.900000 0.000000 54.100000 0.600000 ;
    END
  END data_be_o[3]
  PIN data_be_o[2]
    DIRECTION OUTPUT ;
    USE SIGNAL ;
    ANTENNAPARTIALMETALAREA 6.19 LAYER M2  ;
    ANTENNAPARTIALMETALSIDEAREA 22.718 LAYER M2  ;
    ANTENNAPARTIALCUTAREA 0.04 LAYER V2  ;
    ANTENNAPARTIALMETALAREA 32.12 LAYER M3  ;
    ANTENNAPARTIALMETALSIDEAREA 118.992 LAYER M3  ;
    ANTENNAMODEL OXIDE1 ;
    ANTENNAGATEAREA 3.762 LAYER M3  ;
    ANTENNAMAXAREACAR 8.7412 LAYER M3  ;
    ANTENNAMAXSIDEAREACAR 32.4299 LAYER M3  ;
    ANTENNAMAXCUTCAR 0.0212653 LAYER VL  ;
    PORT
      LAYER M2 ;
        RECT 57.400000 0.000000 57.600000 0.600000 ;
    END
  END data_be_o[2]
  PIN data_be_o[1]
    DIRECTION OUTPUT ;
    USE SIGNAL ;
    ANTENNAPARTIALMETALAREA 1 LAYER M2  ;
    ANTENNAPARTIALMETALSIDEAREA 3.7 LAYER M2  ;
    ANTENNAPARTIALCUTAREA 0.04 LAYER V2  ;
    ANTENNAPARTIALMETALAREA 30.36 LAYER M3  ;
    ANTENNAPARTIALMETALSIDEAREA 112.48 LAYER M3  ;
    ANTENNAMODEL OXIDE1 ;
    ANTENNAGATEAREA 2.848 LAYER M3  ;
    ANTENNAMAXAREACAR 12.7013 LAYER M3  ;
    ANTENNAMAXSIDEAREACAR 46.9699 LAYER M3  ;
    ANTENNAMAXCUTCAR 0.0280899 LAYER VL  ;
    PORT
      LAYER M2 ;
        RECT 60.900000 0.000000 61.100000 0.600000 ;
    END
  END data_be_o[1]
  PIN data_be_o[0]
    DIRECTION OUTPUT ;
    USE SIGNAL ;
    ANTENNAPARTIALMETALAREA 1.15 LAYER M2  ;
    ANTENNAPARTIALMETALSIDEAREA 4.07 LAYER M2  ;
    ANTENNAPARTIALCUTAREA 0.04 LAYER V2  ;
    ANTENNAPARTIALMETALAREA 31.2 LAYER M3  ;
    ANTENNAPARTIALMETALSIDEAREA 115.736 LAYER M3  ;
    ANTENNAMODEL OXIDE1 ;
    ANTENNAGATEAREA 1.76 LAYER M3  ;
    ANTENNAMAXAREACAR 18.1823 LAYER M3  ;
    ANTENNAMAXSIDEAREACAR 67.1984 LAYER M3  ;
    ANTENNAMAXCUTCAR 0.0454545 LAYER VL  ;
    PORT
      LAYER M2 ;
        RECT 64.400000 0.000000 64.600000 0.600000 ;
    END
  END data_be_o[0]
  PIN data_addr_o[31]
    DIRECTION OUTPUT ;
    USE SIGNAL ;
    ANTENNAPARTIALMETALAREA 0.34 LAYER M2  ;
    ANTENNAPARTIALMETALSIDEAREA 0.888 LAYER M2  ;
    ANTENNAPARTIALCUTAREA 0.04 LAYER V2  ;
    ANTENNAPARTIALMETALAREA 1.32 LAYER M3  ;
    ANTENNAPARTIALMETALSIDEAREA 5.032 LAYER M3  ;
    ANTENNAMODEL OXIDE1 ;
    ANTENNAGATEAREA 1.76 LAYER M3  ;
    ANTENNAMAXAREACAR 17.1339 LAYER M3  ;
    ANTENNAMAXSIDEAREACAR 63.2705 LAYER M3  ;
    ANTENNAMAXCUTCAR 0.0454545 LAYER VL  ;
    PORT
      LAYER M2 ;
        RECT 67.900000 0.000000 68.100000 0.600000 ;
    END
  END data_addr_o[31]
  PIN data_addr_o[30]
    DIRECTION OUTPUT ;
    USE SIGNAL ;
    ANTENNAPARTIALMETALAREA 0.43 LAYER M2  ;
    ANTENNAPARTIALMETALSIDEAREA 1.406 LAYER M2  ;
    ANTENNAPARTIALCUTAREA 0.04 LAYER V2  ;
    ANTENNAPARTIALMETALAREA 7.52 LAYER M3  ;
    ANTENNAPARTIALMETALSIDEAREA 28.416 LAYER M3  ;
    ANTENNAMODEL OXIDE1 ;
    ANTENNAGATEAREA 3.4192 LAYER M3  ;
    ANTENNAMAXAREACAR 16.5984 LAYER M3  ;
    ANTENNAMAXSIDEAREACAR 62.1011 LAYER M3  ;
    ANTENNAMAXCUTCAR 0.70922 LAYER VL  ;
    PORT
      LAYER M2 ;
        RECT 71.400000 0.000000 71.600000 0.600000 ;
    END
  END data_addr_o[30]
  PIN data_addr_o[29]
    DIRECTION OUTPUT ;
    USE SIGNAL ;
    ANTENNAPARTIALMETALAREA 0.28 LAYER M2  ;
    ANTENNAPARTIALMETALSIDEAREA 1.036 LAYER M2  ;
    ANTENNAPARTIALCUTAREA 0.04 LAYER V2  ;
    ANTENNAPARTIALMETALAREA 5.12 LAYER M3  ;
    ANTENNAPARTIALMETALSIDEAREA 19.24 LAYER M3  ;
    ANTENNAMODEL OXIDE1 ;
    ANTENNAGATEAREA 3.6328 LAYER M3  ;
    ANTENNAMAXAREACAR 6.06529 LAYER M3  ;
    ANTENNAMAXSIDEAREACAR 22.2821 LAYER M3  ;
    ANTENNAMAXCUTCAR 0.70922 LAYER VL  ;
    PORT
      LAYER M2 ;
        RECT 74.900000 0.000000 75.100000 0.600000 ;
    END
  END data_addr_o[29]
  PIN data_addr_o[28]
    DIRECTION OUTPUT ;
    USE SIGNAL ;
    ANTENNAPARTIALMETALAREA 0.27 LAYER M2  ;
    ANTENNAPARTIALMETALSIDEAREA 0.814 LAYER M2  ;
    ANTENNAPARTIALCUTAREA 0.04 LAYER V2  ;
    ANTENNAPARTIALMETALAREA 5.6 LAYER M3  ;
    ANTENNAPARTIALMETALSIDEAREA 21.016 LAYER M3  ;
    ANTENNAMODEL OXIDE1 ;
    ANTENNAGATEAREA 2.9608 LAYER M3  ;
    ANTENNAMAXAREACAR 9.74717 LAYER M3  ;
    ANTENNAMAXSIDEAREACAR 36.0877 LAYER M3  ;
    ANTENNAMAXCUTCAR 0.70922 LAYER VL  ;
    PORT
      LAYER M2 ;
        RECT 78.400000 0.000000 78.600000 0.600000 ;
    END
  END data_addr_o[28]
  PIN data_addr_o[27]
    DIRECTION OUTPUT ;
    USE SIGNAL ;
    ANTENNAPARTIALMETALAREA 25.94 LAYER M2  ;
    ANTENNAPARTIALMETALSIDEAREA 95.608 LAYER M2  ;
    ANTENNAPARTIALCUTAREA 0.04 LAYER V2  ;
    ANTENNAPARTIALMETALAREA 9.48 LAYER M3  ;
    ANTENNAPARTIALMETALSIDEAREA 35.816 LAYER M3  ;
    ANTENNAMODEL OXIDE1 ;
    ANTENNAGATEAREA 3.8488 LAYER M3  ;
    ANTENNAMAXAREACAR 6.14396 LAYER M3  ;
    ANTENNAMAXSIDEAREACAR 21.9972 LAYER M3  ;
    ANTENNAMAXCUTCAR 0.775194 LAYER VL  ;
    PORT
      LAYER M2 ;
        RECT 81.900000 0.000000 82.100000 0.600000 ;
    END
  END data_addr_o[27]
  PIN data_addr_o[26]
    DIRECTION OUTPUT ;
    USE SIGNAL ;
    ANTENNAPARTIALMETALAREA 0.51 LAYER M2  ;
    ANTENNAPARTIALMETALSIDEAREA 1.702 LAYER M2  ;
    ANTENNAPARTIALCUTAREA 0.04 LAYER V2  ;
    ANTENNAPARTIALMETALAREA 5.92 LAYER M3  ;
    ANTENNAPARTIALMETALSIDEAREA 22.2 LAYER M3  ;
    ANTENNAMODEL OXIDE1 ;
    ANTENNAGATEAREA 3.6328 LAYER M3  ;
    ANTENNAMAXAREACAR 8.39497 LAYER M3  ;
    ANTENNAMAXSIDEAREACAR 31.6475 LAYER M3  ;
    ANTENNAMAXCUTCAR 0.365621 LAYER VL  ;
    PORT
      LAYER M2 ;
        RECT 85.400000 0.000000 85.600000 0.600000 ;
    END
  END data_addr_o[26]
  PIN data_addr_o[25]
    DIRECTION OUTPUT ;
    USE SIGNAL ;
    ANTENNAPARTIALMETALAREA 0.28 LAYER M2  ;
    ANTENNAPARTIALMETALSIDEAREA 1.036 LAYER M2  ;
    ANTENNAPARTIALCUTAREA 0.04 LAYER V2  ;
    ANTENNAPARTIALMETALAREA 6.64 LAYER M3  ;
    ANTENNAPARTIALMETALSIDEAREA 25.456 LAYER M3  ;
    ANTENNAMODEL OXIDE1 ;
    ANTENNAGATEAREA 3.8488 LAYER M3  ;
    ANTENNAMAXAREACAR 6.89543 LAYER M3  ;
    ANTENNAMAXSIDEAREACAR 24.7949 LAYER M3  ;
    ANTENNAMAXCUTCAR 0.775194 LAYER VL  ;
    PORT
      LAYER M2 ;
        RECT 88.900000 0.000000 89.100000 0.600000 ;
    END
  END data_addr_o[25]
  PIN data_addr_o[24]
    DIRECTION OUTPUT ;
    USE SIGNAL ;
    ANTENNAPARTIALMETALAREA 23.39 LAYER M2  ;
    ANTENNAPARTIALMETALSIDEAREA 86.358 LAYER M2  ;
    ANTENNAPARTIALCUTAREA 0.04 LAYER V2  ;
    ANTENNAPARTIALMETALAREA 3.56 LAYER M3  ;
    ANTENNAPARTIALMETALSIDEAREA 13.616 LAYER M3  ;
    ANTENNAMODEL OXIDE1 ;
    ANTENNAGATEAREA 3.0736 LAYER M3  ;
    ANTENNAMAXAREACAR 131.109 LAYER M3  ;
    ANTENNAMAXSIDEAREACAR 487.022 LAYER M3  ;
    ANTENNAMAXCUTCAR 1.06383 LAYER VL  ;
    PORT
      LAYER M2 ;
        RECT 92.400000 0.000000 92.600000 0.600000 ;
    END
  END data_addr_o[24]
  PIN data_addr_o[23]
    DIRECTION OUTPUT ;
    USE SIGNAL ;
    ANTENNAPARTIALMETALAREA 24.1 LAYER M2  ;
    ANTENNAPARTIALMETALSIDEAREA 88.8 LAYER M2  ;
    ANTENNAPARTIALCUTAREA 0.04 LAYER V2  ;
    ANTENNAPARTIALMETALAREA 6.24 LAYER M3  ;
    ANTENNAPARTIALMETALSIDEAREA 23.68 LAYER M3  ;
    ANTENNAMODEL OXIDE1 ;
    ANTENNAGATEAREA 3.2464 LAYER M3  ;
    ANTENNAMAXAREACAR 12.4684 LAYER M3  ;
    ANTENNAMAXSIDEAREACAR 46.4123 LAYER M3  ;
    ANTENNAMAXCUTCAR 0.70922 LAYER VL  ;
    PORT
      LAYER M2 ;
        RECT 95.900000 0.000000 96.100000 0.600000 ;
    END
  END data_addr_o[23]
  PIN data_addr_o[22]
    DIRECTION OUTPUT ;
    USE SIGNAL ;
    ANTENNAPARTIALMETALAREA 0.43 LAYER M2  ;
    ANTENNAPARTIALMETALSIDEAREA 1.406 LAYER M2  ;
    ANTENNAPARTIALCUTAREA 0.04 LAYER V2  ;
    ANTENNAPARTIALMETALAREA 8.12 LAYER M3  ;
    ANTENNAPARTIALMETALSIDEAREA 30.784 LAYER M3  ;
    ANTENNAMODEL OXIDE1 ;
    ANTENNAGATEAREA 3.9184 LAYER M3  ;
    ANTENNAMAXAREACAR 5.75313 LAYER M3  ;
    ANTENNAMAXSIDEAREACAR 20.7322 LAYER M3  ;
    ANTENNAMAXCUTCAR 0.70922 LAYER VL  ;
    PORT
      LAYER M2 ;
        RECT 99.400000 0.000000 99.600000 0.600000 ;
    END
  END data_addr_o[22]
  PIN data_addr_o[21]
    DIRECTION OUTPUT ;
    USE SIGNAL ;
    ANTENNAPARTIALMETALAREA 21.8 LAYER M2  ;
    ANTENNAPARTIALMETALSIDEAREA 80.66 LAYER M2  ;
    ANTENNAPARTIALCUTAREA 0.04 LAYER V2  ;
    ANTENNAPARTIALMETALAREA 5.84 LAYER M3  ;
    ANTENNAPARTIALMETALSIDEAREA 21.904 LAYER M3  ;
    ANTENNAMODEL OXIDE1 ;
    ANTENNAGATEAREA 3.0736 LAYER M3  ;
    ANTENNAMAXAREACAR 10.0662 LAYER M3  ;
    ANTENNAMAXSIDEAREACAR 35.1302 LAYER M3  ;
    ANTENNAMAXCUTCAR 0.70922 LAYER VL  ;
    PORT
      LAYER M2 ;
        RECT 102.900000 0.000000 103.100000 0.600000 ;
    END
  END data_addr_o[21]
  PIN data_addr_o[20]
    DIRECTION OUTPUT ;
    USE SIGNAL ;
    ANTENNAPARTIALMETALAREA 0.59 LAYER M2  ;
    ANTENNAPARTIALMETALSIDEAREA 1.998 LAYER M2  ;
    ANTENNAPARTIALCUTAREA 0.04 LAYER V2  ;
    ANTENNAPARTIALMETALAREA 8.8 LAYER M3  ;
    ANTENNAPARTIALMETALSIDEAREA 33.152 LAYER M3  ;
    ANTENNAMODEL OXIDE1 ;
    ANTENNAGATEAREA 4.0912 LAYER M3  ;
    ANTENNAMAXAREACAR 309.449 LAYER M3  ;
    ANTENNAMAXSIDEAREACAR 1144.16 LAYER M3  ;
    ANTENNAMAXCUTCAR 1.41844 LAYER VL  ;
    PORT
      LAYER M2 ;
        RECT 106.400000 0.000000 106.600000 0.600000 ;
    END
  END data_addr_o[20]
  PIN data_addr_o[19]
    DIRECTION OUTPUT ;
    USE SIGNAL ;
    ANTENNAPARTIALMETALAREA 0.34 LAYER M2  ;
    ANTENNAPARTIALMETALSIDEAREA 0.888 LAYER M2  ;
    ANTENNAPARTIALCUTAREA 0.04 LAYER V2  ;
    ANTENNAPARTIALMETALAREA 8.84 LAYER M3  ;
    ANTENNAPARTIALMETALSIDEAREA 33.152 LAYER M3  ;
    ANTENNAMODEL OXIDE1 ;
    ANTENNAGATEAREA 3.736 LAYER M3  ;
    ANTENNAMAXAREACAR 7.53638 LAYER M3  ;
    ANTENNAMAXSIDEAREACAR 27.0545 LAYER M3  ;
    ANTENNAMAXCUTCAR 0.70922 LAYER VL  ;
    PORT
      LAYER M2 ;
        RECT 109.900000 0.000000 110.100000 0.600000 ;
    END
  END data_addr_o[19]
  PIN data_addr_o[18]
    DIRECTION OUTPUT ;
    USE SIGNAL ;
    ANTENNAPARTIALMETALAREA 16.11 LAYER M2  ;
    ANTENNAPARTIALMETALSIDEAREA 59.422 LAYER M2  ;
    ANTENNAPARTIALCUTAREA 0.04 LAYER V2  ;
    ANTENNAPARTIALMETALAREA 12.32 LAYER M3  ;
    ANTENNAPARTIALMETALSIDEAREA 46.176 LAYER M3  ;
    ANTENNAMODEL OXIDE1 ;
    ANTENNAGATEAREA 3.736 LAYER M3  ;
    ANTENNAMAXAREACAR 198.539 LAYER M3  ;
    ANTENNAMAXSIDEAREACAR 733.803 LAYER M3  ;
    ANTENNAMAXCUTCAR 1.41844 LAYER VL  ;
    PORT
      LAYER M2 ;
        RECT 113.400000 0.000000 113.600000 0.600000 ;
    END
  END data_addr_o[18]
  PIN data_addr_o[17]
    DIRECTION OUTPUT ;
    USE SIGNAL ;
    ANTENNAPARTIALMETALAREA 0.28 LAYER M2  ;
    ANTENNAPARTIALMETALSIDEAREA 1.036 LAYER M2  ;
    ANTENNAPARTIALCUTAREA 0.04 LAYER V2  ;
    ANTENNAPARTIALMETALAREA 7.96 LAYER M3  ;
    ANTENNAPARTIALMETALSIDEAREA 29.896 LAYER M3  ;
    ANTENNAMODEL OXIDE1 ;
    ANTENNAGATEAREA 3.8488 LAYER M3  ;
    ANTENNAMAXAREACAR 283.792 LAYER M3  ;
    ANTENNAMAXSIDEAREACAR 1051.92 LAYER M3  ;
    ANTENNAMAXCUTCAR 1.06383 LAYER VL  ;
    PORT
      LAYER M2 ;
        RECT 116.900000 0.000000 117.100000 0.600000 ;
    END
  END data_addr_o[17]
  PIN data_addr_o[16]
    DIRECTION OUTPUT ;
    USE SIGNAL ;
    ANTENNAPARTIALMETALAREA 0.51 LAYER M2  ;
    ANTENNAPARTIALMETALSIDEAREA 1.702 LAYER M2  ;
    ANTENNAPARTIALCUTAREA 0.04 LAYER V2  ;
    ANTENNAPARTIALMETALAREA 9.72 LAYER M3  ;
    ANTENNAPARTIALMETALSIDEAREA 36.704 LAYER M3  ;
    ANTENNAMODEL OXIDE1 ;
    ANTENNAGATEAREA 3.9784 LAYER M3  ;
    ANTENNAMAXAREACAR 9.03185 LAYER M3  ;
    ANTENNAMAXSIDEAREACAR 32.6549 LAYER M3  ;
    ANTENNAMAXCUTCAR 0.70922 LAYER VL  ;
    PORT
      LAYER M2 ;
        RECT 120.400000 0.000000 120.600000 0.600000 ;
    END
  END data_addr_o[16]
  PIN data_addr_o[15]
    DIRECTION OUTPUT ;
    USE SIGNAL ;
    ANTENNAPARTIALMETALAREA 0.74 LAYER M2  ;
    ANTENNAPARTIALMETALSIDEAREA 2.368 LAYER M2  ;
    ANTENNAPARTIALCUTAREA 0.04 LAYER V2  ;
    ANTENNAPARTIALMETALAREA 1.92 LAYER M3  ;
    ANTENNAPARTIALMETALSIDEAREA 7.4 LAYER M3  ;
    ANTENNAMODEL OXIDE1 ;
    ANTENNAGATEAREA 3.8056 LAYER M3  ;
    ANTENNAMAXAREACAR 119.799 LAYER M3  ;
    ANTENNAMAXSIDEAREACAR 444.315 LAYER M3  ;
    ANTENNAMAXCUTCAR 0.634722 LAYER VL  ;
    PORT
      LAYER M2 ;
        RECT 123.900000 0.000000 124.100000 0.600000 ;
    END
  END data_addr_o[15]
  PIN data_addr_o[14]
    DIRECTION OUTPUT ;
    USE SIGNAL ;
    ANTENNAPARTIALMETALAREA 0.43 LAYER M2  ;
    ANTENNAPARTIALMETALSIDEAREA 1.406 LAYER M2  ;
    ANTENNAPARTIALCUTAREA 0.04 LAYER V2  ;
    ANTENNAPARTIALMETALAREA 19.68 LAYER M3  ;
    ANTENNAPARTIALMETALSIDEAREA 73.408 LAYER M3  ;
    ANTENNAMODEL OXIDE1 ;
    ANTENNAGATEAREA 3.6928 LAYER M3  ;
    ANTENNAMAXAREACAR 7.12732 LAYER M3  ;
    ANTENNAMAXSIDEAREACAR 27.0824 LAYER M3  ;
    ANTENNAMAXCUTCAR 0.462963 LAYER VL  ;
    PORT
      LAYER M2 ;
        RECT 127.400000 0.000000 127.600000 0.600000 ;
    END
  END data_addr_o[14]
  PIN data_addr_o[13]
    DIRECTION OUTPUT ;
    USE SIGNAL ;
    ANTENNAPARTIALMETALAREA 13.88 LAYER M2  ;
    ANTENNAPARTIALMETALSIDEAREA 51.356 LAYER M2  ;
    ANTENNAPARTIALCUTAREA 0.04 LAYER V2  ;
    ANTENNAPARTIALMETALAREA 26.4 LAYER M3  ;
    ANTENNAPARTIALMETALSIDEAREA 97.976 LAYER M3  ;
    ANTENNAMODEL OXIDE1 ;
    ANTENNAGATEAREA 3.6328 LAYER M3  ;
    ANTENNAMAXAREACAR 8.70684 LAYER M3  ;
    ANTENNAMAXSIDEAREACAR 34.1152 LAYER M3  ;
    ANTENNAMAXCUTCAR 0.70922 LAYER VL  ;
    PORT
      LAYER M2 ;
        RECT 130.900000 0.000000 131.100000 0.600000 ;
    END
  END data_addr_o[13]
  PIN data_addr_o[12]
    DIRECTION OUTPUT ;
    USE SIGNAL ;
    ANTENNAPARTIALMETALAREA 15.39 LAYER M2  ;
    ANTENNAPARTIALMETALSIDEAREA 56.758 LAYER M2  ;
    ANTENNAPARTIALCUTAREA 0.04 LAYER V2  ;
    ANTENNAPARTIALMETALAREA 29.88 LAYER M3  ;
    ANTENNAPARTIALMETALSIDEAREA 111.296 LAYER M3  ;
    ANTENNAMODEL OXIDE1 ;
    ANTENNAGATEAREA 3.8056 LAYER M3  ;
    ANTENNAMAXAREACAR 9.90833 LAYER M3  ;
    ANTENNAMAXSIDEAREACAR 37.4155 LAYER M3  ;
    ANTENNAMAXCUTCAR 0.70922 LAYER VL  ;
    PORT
      LAYER M2 ;
        RECT 134.400000 0.000000 134.600000 0.600000 ;
    END
  END data_addr_o[12]
  PIN data_addr_o[11]
    DIRECTION OUTPUT ;
    USE SIGNAL ;
    ANTENNAPARTIALMETALAREA 27.34 LAYER M2  ;
    ANTENNAPARTIALMETALSIDEAREA 100.788 LAYER M2  ;
    ANTENNAPARTIALCUTAREA 0.12 LAYER V2  ;
    ANTENNAPARTIALMETALAREA 20.52 LAYER M3  ;
    ANTENNAPARTIALMETALSIDEAREA 76.368 LAYER M3  ;
    ANTENNAMODEL OXIDE1 ;
    ANTENNAGATEAREA 3.8056 LAYER M3  ;
    ANTENNAMAXAREACAR 106.974 LAYER M3  ;
    ANTENNAMAXSIDEAREACAR 397.695 LAYER M3  ;
    ANTENNAMAXCUTCAR 0.70922 LAYER VL  ;
    PORT
      LAYER M2 ;
        RECT 137.900000 0.000000 138.100000 0.600000 ;
    END
  END data_addr_o[11]
  PIN data_addr_o[10]
    DIRECTION OUTPUT ;
    USE SIGNAL ;
    ANTENNAPARTIALMETALAREA 0.59 LAYER M2  ;
    ANTENNAPARTIALMETALSIDEAREA 1.998 LAYER M2  ;
    ANTENNAPARTIALCUTAREA 0.04 LAYER V2  ;
    ANTENNAPARTIALMETALAREA 20.12 LAYER M3  ;
    ANTENNAPARTIALMETALSIDEAREA 74.888 LAYER M3  ;
    ANTENNAMODEL OXIDE1 ;
    ANTENNAGATEAREA 3.4696 LAYER M3  ;
    ANTENNAMAXAREACAR 168.708 LAYER M3  ;
    ANTENNAMAXSIDEAREACAR 624.899 LAYER M3  ;
    ANTENNAMAXCUTCAR 0.775194 LAYER VL  ;
    PORT
      LAYER M2 ;
        RECT 141.400000 0.000000 141.600000 0.600000 ;
    END
  END data_addr_o[10]
  PIN data_addr_o[9]
    DIRECTION OUTPUT ;
    USE SIGNAL ;
    ANTENNAPARTIALMETALAREA 0.6 LAYER M2  ;
    ANTENNAPARTIALMETALSIDEAREA 2.22 LAYER M2  ;
    ANTENNAPARTIALCUTAREA 0.04 LAYER V2  ;
    ANTENNAPARTIALMETALAREA 20.48 LAYER M3  ;
    ANTENNAPARTIALMETALSIDEAREA 76.368 LAYER M3  ;
    ANTENNAMODEL OXIDE1 ;
    ANTENNAGATEAREA 3.8056 LAYER M3  ;
    ANTENNAMAXAREACAR 85.5943 LAYER M3  ;
    ANTENNAMAXSIDEAREACAR 317.372 LAYER M3  ;
    ANTENNAMAXCUTCAR 0.70922 LAYER VL  ;
    PORT
      LAYER M2 ;
        RECT 144.900000 0.000000 145.100000 0.600000 ;
    END
  END data_addr_o[9]
  PIN data_addr_o[8]
    DIRECTION OUTPUT ;
    USE SIGNAL ;
    ANTENNAPARTIALMETALAREA 14.75 LAYER M2  ;
    ANTENNAPARTIALMETALSIDEAREA 54.39 LAYER M2  ;
    ANTENNAPARTIALCUTAREA 0.04 LAYER V2  ;
    ANTENNAPARTIALMETALAREA 16.56 LAYER M3  ;
    ANTENNAPARTIALMETALSIDEAREA 61.864 LAYER M3  ;
    ANTENNAMODEL OXIDE1 ;
    ANTENNAGATEAREA 3.6928 LAYER M3  ;
    ANTENNAMAXAREACAR 6.7454 LAYER M3  ;
    ANTENNAMAXSIDEAREACAR 25.6693 LAYER M3  ;
    ANTENNAMAXCUTCAR 0.462963 LAYER VL  ;
    PORT
      LAYER M2 ;
        RECT 148.400000 0.000000 148.600000 0.600000 ;
    END
  END data_addr_o[8]
  PIN data_addr_o[7]
    DIRECTION OUTPUT ;
    USE SIGNAL ;
    ANTENNAPARTIALMETALAREA 13.46 LAYER M2  ;
    ANTENNAPARTIALMETALSIDEAREA 49.432 LAYER M2  ;
    ANTENNAPARTIALCUTAREA 0.04 LAYER V2  ;
    ANTENNAPARTIALMETALAREA 24 LAYER M3  ;
    ANTENNAPARTIALMETALSIDEAREA 89.392 LAYER M3  ;
    ANTENNAMODEL OXIDE1 ;
    ANTENNAGATEAREA 3.8656 LAYER M3  ;
    ANTENNAMAXAREACAR 21.7318 LAYER M3  ;
    ANTENNAMAXSIDEAREACAR 81.5995 LAYER M3  ;
    ANTENNAMAXCUTCAR 0.694444 LAYER VL  ;
    PORT
      LAYER M2 ;
        RECT 151.900000 0.000000 152.100000 0.600000 ;
    END
  END data_addr_o[7]
  PIN data_addr_o[6]
    DIRECTION OUTPUT ;
    USE SIGNAL ;
    ANTENNAPARTIALMETALAREA 24.75 LAYER M2  ;
    ANTENNAPARTIALMETALSIDEAREA 91.39 LAYER M2  ;
    ANTENNAPARTIALCUTAREA 0.04 LAYER V2  ;
    ANTENNAPARTIALMETALAREA 18.92 LAYER M3  ;
    ANTENNAPARTIALMETALSIDEAREA 70.744 LAYER M3  ;
    ANTENNAMODEL OXIDE1 ;
    ANTENNAGATEAREA 4.2612 LAYER M3  ;
    ANTENNAMAXAREACAR 21.2912 LAYER M3  ;
    ANTENNAMAXSIDEAREACAR 79.2403 LAYER M3  ;
    ANTENNAMAXCUTCAR 0.775194 LAYER VL  ;
    PORT
      LAYER M2 ;
        RECT 155.400000 0.000000 155.600000 0.600000 ;
    END
  END data_addr_o[6]
  PIN data_addr_o[5]
    DIRECTION OUTPUT ;
    USE SIGNAL ;
    ANTENNAPARTIALMETALAREA 15.8 LAYER M2  ;
    ANTENNAPARTIALMETALSIDEAREA 58.46 LAYER M2  ;
    ANTENNAPARTIALCUTAREA 0.04 LAYER V2  ;
    ANTENNAPARTIALMETALAREA 7.28 LAYER M3  ;
    ANTENNAPARTIALMETALSIDEAREA 27.232 LAYER M3  ;
    ANTENNAMODEL OXIDE1 ;
    ANTENNAGATEAREA 0.252 LAYER M3  ;
    ANTENNAMAXAREACAR 31.0245 LAYER M3  ;
    ANTENNAMAXSIDEAREACAR 116.532 LAYER M3  ;
    ANTENNAMAXCUTCAR 0.775194 LAYER VL  ;
    PORT
      LAYER M2 ;
        RECT 158.900000 0.000000 159.100000 0.600000 ;
    END
  END data_addr_o[5]
  PIN data_addr_o[4]
    DIRECTION OUTPUT ;
    USE SIGNAL ;
    ANTENNAPARTIALMETALAREA 0.27 LAYER M2  ;
    ANTENNAPARTIALMETALSIDEAREA 0.814 LAYER M2  ;
    ANTENNAPARTIALCUTAREA 0.04 LAYER V2  ;
    ANTENNAPARTIALMETALAREA 19.28 LAYER M3  ;
    ANTENNAPARTIALMETALSIDEAREA 71.632 LAYER M3  ;
    ANTENNAMODEL OXIDE1 ;
    ANTENNAGATEAREA 0.1128 LAYER M3  ;
    ANTENNAMAXAREACAR 172.362 LAYER M3  ;
    ANTENNAMAXSIDEAREACAR 642.181 LAYER M3  ;
    ANTENNAMAXCUTCAR 0.70922 LAYER VL  ;
    PORT
      LAYER M2 ;
        RECT 162.400000 0.000000 162.600000 0.600000 ;
    END
  END data_addr_o[4]
  PIN data_addr_o[3]
    DIRECTION OUTPUT ;
    USE SIGNAL ;
    ANTENNAPARTIALMETALAREA 0.58 LAYER M2  ;
    ANTENNAPARTIALMETALSIDEAREA 1.776 LAYER M2  ;
    ANTENNAPARTIALCUTAREA 0.04 LAYER V2  ;
    ANTENNAPARTIALMETALAREA 24.12 LAYER M3  ;
    ANTENNAPARTIALMETALSIDEAREA 89.688 LAYER M3  ;
    ANTENNAMODEL OXIDE1 ;
    ANTENNAGATEAREA 9.396 LAYER M3  ;
    ANTENNAMAXAREACAR 2.75085 LAYER M3  ;
    ANTENNAMAXSIDEAREACAR 10.0169 LAYER M3  ;
    ANTENNAMAXCUTCAR 0.00851426 LAYER VL  ;
    PORT
      LAYER M2 ;
        RECT 165.900000 0.000000 166.100000 0.600000 ;
    END
  END data_addr_o[3]
  PIN data_addr_o[2]
    DIRECTION OUTPUT ;
    USE SIGNAL ;
    ANTENNAPARTIALMETALAREA 0.35 LAYER M2  ;
    ANTENNAPARTIALMETALSIDEAREA 1.11 LAYER M2  ;
    ANTENNAPARTIALCUTAREA 0.04 LAYER V2  ;
    ANTENNAPARTIALMETALAREA 16.48 LAYER M3  ;
    ANTENNAPARTIALMETALSIDEAREA 61.272 LAYER M3  ;
    ANTENNAMODEL OXIDE1 ;
    ANTENNAGATEAREA 3.6328 LAYER M3  ;
    ANTENNAMAXAREACAR 11.8969 LAYER M3  ;
    ANTENNAMAXSIDEAREACAR 43.8591 LAYER M3  ;
    ANTENNAMAXCUTCAR 0.70922 LAYER VL  ;
    PORT
      LAYER M2 ;
        RECT 169.400000 0.000000 169.600000 0.600000 ;
    END
  END data_addr_o[2]
  PIN data_addr_o[1]
    DIRECTION OUTPUT ;
    USE SIGNAL ;
    PORT
      LAYER M2 ;
        RECT 172.900000 0.000000 173.100000 0.600000 ;
    END
  END data_addr_o[1]
  PIN data_addr_o[0]
    DIRECTION OUTPUT ;
    USE SIGNAL ;
    PORT
      LAYER M2 ;
        RECT 176.400000 0.000000 176.600000 0.600000 ;
    END
  END data_addr_o[0]
  PIN data_wdata_o[31]
    DIRECTION OUTPUT ;
    USE SIGNAL ;
    ANTENNAPARTIALMETALAREA 1.22 LAYER M2  ;
    ANTENNAPARTIALMETALSIDEAREA 4.144 LAYER M2  ;
    ANTENNAPARTIALCUTAREA 0.04 LAYER V2  ;
    ANTENNAPARTIALMETALAREA 8.6 LAYER M3  ;
    ANTENNAPARTIALMETALSIDEAREA 31.968 LAYER M3  ;
    ANTENNAMODEL OXIDE1 ;
    ANTENNAGATEAREA 2.112 LAYER M3  ;
    ANTENNAMAXAREACAR 8.12652 LAYER M3  ;
    ANTENNAMAXSIDEAREACAR 30.1417 LAYER M3  ;
    ANTENNAMAXCUTCAR 0.0378788 LAYER VL  ;
    PORT
      LAYER M2 ;
        RECT 179.900000 0.000000 180.100000 0.600000 ;
    END
  END data_wdata_o[31]
  PIN data_wdata_o[30]
    DIRECTION OUTPUT ;
    USE SIGNAL ;
    ANTENNAPARTIALMETALAREA 2.03 LAYER M2  ;
    ANTENNAPARTIALMETALSIDEAREA 7.326 LAYER M2  ;
    ANTENNAPARTIALCUTAREA 0.04 LAYER V2  ;
    ANTENNAPARTIALMETALAREA 6.68 LAYER M3  ;
    ANTENNAPARTIALMETALSIDEAREA 24.864 LAYER M3  ;
    ANTENNAMODEL OXIDE1 ;
    ANTENNAGATEAREA 2.112 LAYER M3  ;
    ANTENNAMAXAREACAR 3.46742 LAYER M3  ;
    ANTENNAMAXSIDEAREACAR 12.903 LAYER M3  ;
    ANTENNAMAXCUTCAR 0.0378788 LAYER VL  ;
    PORT
      LAYER M2 ;
        RECT 183.400000 0.000000 183.600000 0.600000 ;
    END
  END data_wdata_o[30]
  PIN data_wdata_o[29]
    DIRECTION OUTPUT ;
    USE SIGNAL ;
    ANTENNAPARTIALMETALAREA 3.32 LAYER M2  ;
    ANTENNAPARTIALMETALSIDEAREA 12.284 LAYER M2  ;
    ANTENNAPARTIALCUTAREA 0.04 LAYER V2  ;
    ANTENNAPARTIALMETALAREA 5 LAYER M3  ;
    ANTENNAPARTIALMETALSIDEAREA 18.648 LAYER M3  ;
    ANTENNAMODEL OXIDE1 ;
    ANTENNAGATEAREA 2.112 LAYER M3  ;
    ANTENNAMAXAREACAR 2.6303 LAYER M3  ;
    ANTENNAMAXSIDEAREACAR 9.80682 LAYER M3  ;
    ANTENNAMAXCUTCAR 0.0378788 LAYER VL  ;
    PORT
      LAYER M2 ;
        RECT 186.900000 0.000000 187.100000 0.600000 ;
    END
  END data_wdata_o[29]
  PIN data_wdata_o[28]
    DIRECTION OUTPUT ;
    USE SIGNAL ;
    ANTENNAPARTIALMETALAREA 7.71 LAYER M2  ;
    ANTENNAPARTIALMETALSIDEAREA 28.342 LAYER M2  ;
    ANTENNAPARTIALCUTAREA 0.04 LAYER V2  ;
    ANTENNAPARTIALMETALAREA 5.32 LAYER M3  ;
    ANTENNAPARTIALMETALSIDEAREA 19.832 LAYER M3  ;
    ANTENNAMODEL OXIDE1 ;
    ANTENNAGATEAREA 2.112 LAYER M3  ;
    ANTENNAMAXAREACAR 2.80909 LAYER M3  ;
    ANTENNAMAXSIDEAREACAR 10.4254 LAYER M3  ;
    ANTENNAMAXCUTCAR 0.0378788 LAYER VL  ;
    PORT
      LAYER M2 ;
        RECT 190.400000 0.000000 190.600000 0.600000 ;
    END
  END data_wdata_o[28]
  PIN data_wdata_o[27]
    DIRECTION OUTPUT ;
    USE SIGNAL ;
    ANTENNAPARTIALMETALAREA 1.94 LAYER M2  ;
    ANTENNAPARTIALMETALSIDEAREA 6.808 LAYER M2  ;
    ANTENNAPARTIALCUTAREA 0.04 LAYER V2  ;
    ANTENNAPARTIALMETALAREA 5.24 LAYER M3  ;
    ANTENNAPARTIALMETALSIDEAREA 19.536 LAYER M3  ;
    ANTENNAMODEL OXIDE1 ;
    ANTENNAGATEAREA 2.112 LAYER M3  ;
    ANTENNAMAXAREACAR 2.78561 LAYER M3  ;
    ANTENNAMAXSIDEAREACAR 10.3803 LAYER M3  ;
    ANTENNAMAXCUTCAR 0.0378788 LAYER VL  ;
    PORT
      LAYER M2 ;
        RECT 193.900000 0.000000 194.100000 0.600000 ;
    END
  END data_wdata_o[27]
  PIN data_wdata_o[26]
    DIRECTION OUTPUT ;
    USE SIGNAL ;
    ANTENNAPARTIALMETALAREA 1.23 LAYER M2  ;
    ANTENNAPARTIALMETALSIDEAREA 4.366 LAYER M2  ;
    ANTENNAPARTIALCUTAREA 0.04 LAYER V2  ;
    ANTENNAPARTIALMETALAREA 3.92 LAYER M3  ;
    ANTENNAPARTIALMETALSIDEAREA 14.8 LAYER M3  ;
    ANTENNAMODEL OXIDE1 ;
    ANTENNAGATEAREA 2.112 LAYER M3  ;
    ANTENNAMAXAREACAR 2.11894 LAYER M3  ;
    ANTENNAMAXSIDEAREACAR 7.98485 LAYER M3  ;
    ANTENNAMAXCUTCAR 0.0378788 LAYER VL  ;
    PORT
      LAYER M2 ;
        RECT 197.400000 0.000000 197.600000 0.600000 ;
    END
  END data_wdata_o[26]
  PIN data_wdata_o[25]
    DIRECTION OUTPUT ;
    USE SIGNAL ;
    ANTENNAPARTIALMETALAREA 0.02 LAYER M2  ;
    ANTENNAPARTIALMETALSIDEAREA 0.074 LAYER M2  ;
    ANTENNAPARTIALCUTAREA 0.04 LAYER V2  ;
    ANTENNAPARTIALMETALAREA 4.56 LAYER M3  ;
    ANTENNAPARTIALMETALSIDEAREA 17.168 LAYER M3  ;
    ANTENNAMODEL OXIDE1 ;
    ANTENNAGATEAREA 2.112 LAYER M3  ;
    ANTENNAMAXAREACAR 2.46364 LAYER M3  ;
    ANTENNAMAXSIDEAREACAR 9.25909 LAYER M3  ;
    ANTENNAMAXCUTCAR 0.0378788 LAYER VL  ;
    PORT
      LAYER M2 ;
        RECT 200.900000 0.000000 201.100000 0.600000 ;
    END
  END data_wdata_o[25]
  PIN data_wdata_o[24]
    DIRECTION OUTPUT ;
    USE SIGNAL ;
    ANTENNAPARTIALMETALAREA 4.83 LAYER M2  ;
    ANTENNAPARTIALMETALSIDEAREA 17.686 LAYER M2  ;
    ANTENNAPARTIALCUTAREA 0.04 LAYER V2  ;
    ANTENNAPARTIALMETALAREA 4.68 LAYER M3  ;
    ANTENNAPARTIALMETALSIDEAREA 17.464 LAYER M3  ;
    ANTENNAMODEL OXIDE1 ;
    ANTENNAGATEAREA 2.112 LAYER M3  ;
    ANTENNAMAXAREACAR 2.47879 LAYER M3  ;
    ANTENNAMAXSIDEAREACAR 9.24621 LAYER M3  ;
    ANTENNAMAXCUTCAR 0.0378788 LAYER VL  ;
    PORT
      LAYER M2 ;
        RECT 204.400000 0.000000 204.600000 0.600000 ;
    END
  END data_wdata_o[24]
  PIN data_wdata_o[23]
    DIRECTION OUTPUT ;
    USE SIGNAL ;
    ANTENNAPARTIALMETALAREA 0.5 LAYER M2  ;
    ANTENNAPARTIALMETALSIDEAREA 1.48 LAYER M2  ;
    ANTENNAPARTIALCUTAREA 0.04 LAYER V2  ;
    ANTENNAPARTIALMETALAREA 3.8 LAYER M3  ;
    ANTENNAPARTIALMETALSIDEAREA 14.208 LAYER M3  ;
    PORT
      LAYER M2 ;
        RECT 207.900000 0.000000 208.100000 0.600000 ;
    END
  END data_wdata_o[23]
  PIN data_wdata_o[22]
    DIRECTION OUTPUT ;
    USE SIGNAL ;
    ANTENNAPARTIALMETALAREA 1.95 LAYER M2  ;
    ANTENNAPARTIALMETALSIDEAREA 7.03 LAYER M2  ;
    ANTENNAPARTIALCUTAREA 0.04 LAYER V2  ;
    ANTENNAPARTIALMETALAREA 2.04 LAYER M3  ;
    ANTENNAPARTIALMETALSIDEAREA 7.696 LAYER M3  ;
    ANTENNAMODEL OXIDE1 ;
    ANTENNAGATEAREA 2.112 LAYER M3  ;
    ANTENNAMAXAREACAR 1.22879 LAYER M3  ;
    ANTENNAMAXSIDEAREACAR 4.62121 LAYER M3  ;
    ANTENNAMAXCUTCAR 0.0378788 LAYER VL  ;
    PORT
      LAYER M2 ;
        RECT 211.400000 0.000000 211.600000 0.600000 ;
    END
  END data_wdata_o[22]
  PIN data_wdata_o[21]
    DIRECTION OUTPUT ;
    USE SIGNAL ;
    ANTENNAPARTIALMETALAREA 0.52 LAYER M2  ;
    ANTENNAPARTIALMETALSIDEAREA 1.924 LAYER M2  ;
    ANTENNAPARTIALCUTAREA 0.04 LAYER V2  ;
    ANTENNAPARTIALMETALAREA 1.76 LAYER M3  ;
    ANTENNAPARTIALMETALSIDEAREA 6.808 LAYER M3  ;
    ANTENNAMODEL OXIDE1 ;
    ANTENNAGATEAREA 2.112 LAYER M3  ;
    ANTENNAMAXAREACAR 1.09621 LAYER M3  ;
    ANTENNAMAXSIDEAREACAR 4.20076 LAYER M3  ;
    ANTENNAMAXCUTCAR 0.0378788 LAYER VL  ;
    PORT
      LAYER M2 ;
        RECT 214.900000 0.000000 215.100000 0.600000 ;
    END
  END data_wdata_o[21]
  PIN data_wdata_o[20]
    DIRECTION OUTPUT ;
    USE SIGNAL ;
    ANTENNAPARTIALMETALAREA 0.51 LAYER M2  ;
    ANTENNAPARTIALMETALSIDEAREA 1.702 LAYER M2  ;
    ANTENNAPARTIALCUTAREA 0.04 LAYER V2  ;
    ANTENNAPARTIALMETALAREA 1.88 LAYER M3  ;
    ANTENNAPARTIALMETALSIDEAREA 7.104 LAYER M3  ;
    ANTENNAMODEL OXIDE1 ;
    ANTENNAGATEAREA 2.112 LAYER M3  ;
    ANTENNAMAXAREACAR 4.58485 LAYER M3  ;
    ANTENNAMAXSIDEAREACAR 17.0318 LAYER M3  ;
    ANTENNAMAXCUTCAR 0.0378788 LAYER VL  ;
    PORT
      LAYER M2 ;
        RECT 218.400000 0.000000 218.600000 0.600000 ;
    END
  END data_wdata_o[20]
  PIN data_wdata_o[19]
    DIRECTION OUTPUT ;
    USE SIGNAL ;
    ANTENNAPARTIALMETALAREA 1.94 LAYER M2  ;
    ANTENNAPARTIALMETALSIDEAREA 6.808 LAYER M2  ;
    ANTENNAPARTIALCUTAREA 0.04 LAYER V2  ;
    ANTENNAPARTIALMETALAREA 1.32 LAYER M3  ;
    ANTENNAPARTIALMETALSIDEAREA 5.032 LAYER M3  ;
    ANTENNAMODEL OXIDE1 ;
    ANTENNAGATEAREA 2.112 LAYER M3  ;
    ANTENNAMAXAREACAR 0.929545 LAYER M3  ;
    ANTENNAMAXSIDEAREACAR 3.51288 LAYER M3  ;
    ANTENNAMAXCUTCAR 0.0378788 LAYER VL  ;
    PORT
      LAYER M2 ;
        RECT 221.900000 0.000000 222.100000 0.600000 ;
    END
  END data_wdata_o[19]
  PIN data_wdata_o[18]
    DIRECTION OUTPUT ;
    USE SIGNAL ;
    ANTENNAPARTIALMETALAREA 0.59 LAYER M2  ;
    ANTENNAPARTIALMETALSIDEAREA 1.998 LAYER M2  ;
    ANTENNAPARTIALCUTAREA 0.04 LAYER V2  ;
    ANTENNAPARTIALMETALAREA 0.76 LAYER M3  ;
    ANTENNAPARTIALMETALSIDEAREA 2.96 LAYER M3  ;
    ANTENNAMODEL OXIDE1 ;
    ANTENNAGATEAREA 2.112 LAYER M3  ;
    ANTENNAMAXAREACAR 3.0697 LAYER M3  ;
    ANTENNAMAXSIDEAREACAR 11.4258 LAYER M3  ;
    ANTENNAMAXCUTCAR 0.0378788 LAYER VL  ;
    PORT
      LAYER M2 ;
        RECT 225.400000 0.000000 225.600000 0.600000 ;
    END
  END data_wdata_o[18]
  PIN data_wdata_o[17]
    DIRECTION OUTPUT ;
    USE SIGNAL ;
    ANTENNAPARTIALMETALAREA 0.36 LAYER M2  ;
    ANTENNAPARTIALMETALSIDEAREA 1.332 LAYER M2  ;
    ANTENNAPARTIALCUTAREA 0.04 LAYER V2  ;
    ANTENNAPARTIALMETALAREA 2.12 LAYER M3  ;
    ANTENNAPARTIALMETALSIDEAREA 7.992 LAYER M3  ;
    ANTENNAMODEL OXIDE1 ;
    ANTENNAGATEAREA 2.112 LAYER M3  ;
    ANTENNAMAXAREACAR 3.08864 LAYER M3  ;
    ANTENNAMAXSIDEAREACAR 11.5015 LAYER M3  ;
    ANTENNAMAXCUTCAR 0.0378788 LAYER VL  ;
    PORT
      LAYER M2 ;
        RECT 228.900000 0.000000 229.100000 0.600000 ;
    END
  END data_wdata_o[17]
  PIN data_wdata_o[16]
    DIRECTION OUTPUT ;
    USE SIGNAL ;
    ANTENNAPARTIALMETALAREA 3.87 LAYER M2  ;
    ANTENNAPARTIALMETALSIDEAREA 14.134 LAYER M2  ;
    ANTENNAPARTIALCUTAREA 0.04 LAYER V2  ;
    ANTENNAPARTIALMETALAREA 0.28 LAYER M3  ;
    ANTENNAPARTIALMETALSIDEAREA 1.184 LAYER M3  ;
    ANTENNAMODEL OXIDE1 ;
    ANTENNAGATEAREA 2.112 LAYER M3  ;
    ANTENNAMAXAREACAR 0.588636 LAYER M3  ;
    ANTENNAMAXSIDEAREACAR 2.25152 LAYER M3  ;
    ANTENNAMAXCUTCAR 0.0378788 LAYER VL  ;
    PORT
      LAYER M2 ;
        RECT 232.400000 0.000000 232.600000 0.600000 ;
    END
  END data_wdata_o[16]
  PIN data_wdata_o[15]
    DIRECTION OUTPUT ;
    USE SIGNAL ;
    ANTENNAPARTIALMETALAREA 9.26 LAYER M2  ;
    ANTENNAPARTIALMETALSIDEAREA 33.892 LAYER M2  ;
    ANTENNAPARTIALCUTAREA 0.12 LAYER V2  ;
    ANTENNAPARTIALMETALAREA 0.24 LAYER M3  ;
    ANTENNAPARTIALMETALSIDEAREA 1.184 LAYER M3  ;
    PORT
      LAYER M2 ;
        RECT 235.900000 0.000000 236.100000 0.600000 ;
    END
  END data_wdata_o[15]
  PIN data_wdata_o[14]
    DIRECTION OUTPUT ;
    USE SIGNAL ;
    ANTENNAPARTIALMETALAREA 0.59 LAYER M2  ;
    ANTENNAPARTIALMETALSIDEAREA 1.998 LAYER M2  ;
    ANTENNAPARTIALCUTAREA 0.04 LAYER V2  ;
    ANTENNAPARTIALMETALAREA 0.52 LAYER M3  ;
    ANTENNAPARTIALMETALSIDEAREA 2.072 LAYER M3  ;
    ANTENNAMODEL OXIDE1 ;
    ANTENNAGATEAREA 2.112 LAYER M3  ;
    ANTENNAMAXAREACAR 1.15682 LAYER M3  ;
    ANTENNAMAXSIDEAREACAR 4.35379 LAYER M3  ;
    ANTENNAMAXCUTCAR 0.0378788 LAYER VL  ;
    PORT
      LAYER M2 ;
        RECT 239.400000 0.000000 239.600000 0.600000 ;
    END
  END data_wdata_o[14]
  PIN data_wdata_o[13]
    DIRECTION OUTPUT ;
    USE SIGNAL ;
    ANTENNAPARTIALMETALAREA 0.02 LAYER M2  ;
    ANTENNAPARTIALMETALSIDEAREA 0.074 LAYER M2  ;
    ANTENNAPARTIALCUTAREA 0.04 LAYER V2  ;
    ANTENNAPARTIALMETALAREA 0.24 LAYER M3  ;
    ANTENNAPARTIALMETALSIDEAREA 1.184 LAYER M3  ;
    ANTENNAMODEL OXIDE1 ;
    ANTENNAGATEAREA 2.112 LAYER M3  ;
    ANTENNAMAXAREACAR 0.376515 LAYER M3  ;
    ANTENNAMAXSIDEAREACAR 1.53788 LAYER M3  ;
    ANTENNAMAXCUTCAR 0.0378788 LAYER VL  ;
    PORT
      LAYER M2 ;
        RECT 242.900000 0.000000 243.100000 0.600000 ;
    END
  END data_wdata_o[13]
  PIN data_wdata_o[12]
    DIRECTION OUTPUT ;
    USE SIGNAL ;
    ANTENNAPARTIALMETALAREA 0.51 LAYER M2  ;
    ANTENNAPARTIALMETALSIDEAREA 1.702 LAYER M2  ;
    ANTENNAPARTIALCUTAREA 0.04 LAYER V2  ;
    ANTENNAPARTIALMETALAREA 1.64 LAYER M3  ;
    ANTENNAPARTIALMETALSIDEAREA 6.216 LAYER M3  ;
    PORT
      LAYER M2 ;
        RECT 246.400000 0.000000 246.600000 0.600000 ;
    END
  END data_wdata_o[12]
  PIN data_wdata_o[11]
    DIRECTION OUTPUT ;
    USE SIGNAL ;
    ANTENNAPARTIALMETALAREA 1.94 LAYER M2  ;
    ANTENNAPARTIALMETALSIDEAREA 6.808 LAYER M2  ;
    ANTENNAPARTIALCUTAREA 0.04 LAYER V2  ;
    ANTENNAPARTIALMETALAREA 1.16 LAYER M3  ;
    ANTENNAPARTIALMETALSIDEAREA 4.44 LAYER M3  ;
    ANTENNAMODEL OXIDE1 ;
    ANTENNAGATEAREA 2.112 LAYER M3  ;
    ANTENNAMAXAREACAR 0.853788 LAYER M3  ;
    ANTENNAMAXSIDEAREACAR 3.23258 LAYER M3  ;
    ANTENNAMAXCUTCAR 0.0378788 LAYER VL  ;
    PORT
      LAYER M2 ;
        RECT 249.900000 0.000000 250.100000 0.600000 ;
    END
  END data_wdata_o[11]
  PIN data_wdata_o[10]
    DIRECTION OUTPUT ;
    USE SIGNAL ;
    ANTENNAPARTIALMETALAREA 0.59 LAYER M2  ;
    ANTENNAPARTIALMETALSIDEAREA 1.998 LAYER M2  ;
    ANTENNAPARTIALCUTAREA 0.04 LAYER V2  ;
    ANTENNAPARTIALMETALAREA 1.36 LAYER M3  ;
    ANTENNAPARTIALMETALSIDEAREA 5.328 LAYER M3  ;
    PORT
      LAYER M2 ;
        RECT 253.400000 0.000000 253.600000 0.600000 ;
    END
  END data_wdata_o[10]
  PIN data_wdata_o[9]
    DIRECTION OUTPUT ;
    USE SIGNAL ;
    ANTENNAPARTIALMETALAREA 0.36 LAYER M2  ;
    ANTENNAPARTIALMETALSIDEAREA 1.332 LAYER M2  ;
    ANTENNAPARTIALCUTAREA 0.04 LAYER V2  ;
    ANTENNAPARTIALMETALAREA 1 LAYER M3  ;
    ANTENNAPARTIALMETALSIDEAREA 3.848 LAYER M3  ;
    ANTENNAMODEL OXIDE1 ;
    ANTENNAGATEAREA 2.112 LAYER M3  ;
    ANTENNAMAXAREACAR 2.82348 LAYER M3  ;
    ANTENNAMAXSIDEAREACAR 10.5205 LAYER M3  ;
    ANTENNAMAXCUTCAR 0.0378788 LAYER VL  ;
    PORT
      LAYER M2 ;
        RECT 256.900000 0.000000 257.100000 0.600000 ;
    END
  END data_wdata_o[9]
  PIN data_wdata_o[8]
    DIRECTION OUTPUT ;
    USE SIGNAL ;
    ANTENNAPARTIALMETALAREA 4.19 LAYER M2  ;
    ANTENNAPARTIALMETALSIDEAREA 15.318 LAYER M2  ;
    ANTENNAPARTIALCUTAREA 0.04 LAYER V2  ;
    ANTENNAPARTIALMETALAREA 1.8 LAYER M3  ;
    ANTENNAPARTIALMETALSIDEAREA 6.808 LAYER M3  ;
    ANTENNAMODEL OXIDE1 ;
    ANTENNAGATEAREA 2.112 LAYER M3  ;
    ANTENNAMAXAREACAR 1.15682 LAYER M3  ;
    ANTENNAMAXSIDEAREACAR 4.35379 LAYER M3  ;
    ANTENNAMAXCUTCAR 0.0378788 LAYER VL  ;
    PORT
      LAYER M2 ;
        RECT 260.400000 0.000000 260.600000 0.600000 ;
    END
  END data_wdata_o[8]
  PIN data_wdata_o[7]
    DIRECTION OUTPUT ;
    USE SIGNAL ;
    ANTENNAPARTIALMETALAREA 9.26 LAYER M2  ;
    ANTENNAPARTIALMETALSIDEAREA 33.892 LAYER M2  ;
    ANTENNAPARTIALCUTAREA 0.12 LAYER V2  ;
    ANTENNAPARTIALMETALAREA 5.36 LAYER M3  ;
    ANTENNAPARTIALMETALSIDEAREA 20.128 LAYER M3  ;
    PORT
      LAYER M2 ;
        RECT 263.900000 0.000000 264.100000 0.600000 ;
    END
  END data_wdata_o[7]
  PIN data_wdata_o[6]
    DIRECTION OUTPUT ;
    USE SIGNAL ;
    ANTENNAPARTIALMETALAREA 2.03 LAYER M2  ;
    ANTENNAPARTIALMETALSIDEAREA 7.326 LAYER M2  ;
    ANTENNAPARTIALCUTAREA 0.04 LAYER V2  ;
    ANTENNAPARTIALMETALAREA 4.2 LAYER M3  ;
    ANTENNAPARTIALMETALSIDEAREA 15.688 LAYER M3  ;
    ANTENNAMODEL OXIDE1 ;
    ANTENNAGATEAREA 2.112 LAYER M3  ;
    ANTENNAMAXAREACAR 2.29318 LAYER M3  ;
    ANTENNAMAXSIDEAREACAR 8.55833 LAYER M3  ;
    ANTENNAMAXCUTCAR 0.0378788 LAYER VL  ;
    PORT
      LAYER M2 ;
        RECT 267.400000 0.000000 267.600000 0.600000 ;
    END
  END data_wdata_o[6]
  PIN data_wdata_o[5]
    DIRECTION OUTPUT ;
    USE SIGNAL ;
    ANTENNAPARTIALMETALAREA 3.32 LAYER M2  ;
    ANTENNAPARTIALMETALSIDEAREA 12.284 LAYER M2  ;
    ANTENNAPARTIALCUTAREA 0.04 LAYER V2  ;
    ANTENNAPARTIALMETALAREA 2.76 LAYER M3  ;
    ANTENNAPARTIALMETALSIDEAREA 10.36 LAYER M3  ;
    ANTENNAMODEL OXIDE1 ;
    ANTENNAGATEAREA 2.112 LAYER M3  ;
    ANTENNAMAXAREACAR 1.5697 LAYER M3  ;
    ANTENNAMAXSIDEAREACAR 5.88258 LAYER M3  ;
    ANTENNAMAXCUTCAR 0.0378788 LAYER VL  ;
    PORT
      LAYER M2 ;
        RECT 270.900000 0.000000 271.100000 0.600000 ;
    END
  END data_wdata_o[5]
  PIN data_wdata_o[4]
    DIRECTION OUTPUT ;
    USE SIGNAL ;
    ANTENNAPARTIALMETALAREA 8.59 LAYER M2  ;
    ANTENNAPARTIALMETALSIDEAREA 31.598 LAYER M2  ;
    ANTENNAPARTIALCUTAREA 0.04 LAYER V2  ;
    ANTENNAPARTIALMETALAREA 7.48 LAYER M3  ;
    ANTENNAPARTIALMETALSIDEAREA 27.824 LAYER M3  ;
    ANTENNAMODEL OXIDE1 ;
    ANTENNAGATEAREA 2.112 LAYER M3  ;
    ANTENNAMAXAREACAR 3.80455 LAYER M3  ;
    ANTENNAMAXSIDEAREACAR 14.1515 LAYER M3  ;
    ANTENNAMAXCUTCAR 0.0378788 LAYER VL  ;
    PORT
      LAYER M2 ;
        RECT 274.400000 0.000000 274.600000 0.600000 ;
    END
  END data_wdata_o[4]
  PIN data_wdata_o[3]
    DIRECTION OUTPUT ;
    USE SIGNAL ;
    ANTENNAPARTIALMETALAREA 2.02 LAYER M2  ;
    ANTENNAPARTIALMETALSIDEAREA 7.104 LAYER M2  ;
    ANTENNAPARTIALCUTAREA 0.04 LAYER V2  ;
    ANTENNAPARTIALMETALAREA 5.4 LAYER M3  ;
    ANTENNAPARTIALMETALSIDEAREA 20.128 LAYER M3  ;
    ANTENNAMODEL OXIDE1 ;
    ANTENNAGATEAREA 2.112 LAYER M3  ;
    ANTENNAMAXAREACAR 2.8197 LAYER M3  ;
    ANTENNAMAXSIDEAREACAR 10.5076 LAYER M3  ;
    ANTENNAMAXCUTCAR 0.0378788 LAYER VL  ;
    PORT
      LAYER M2 ;
        RECT 277.900000 0.000000 278.100000 0.600000 ;
    END
  END data_wdata_o[3]
  PIN data_wdata_o[2]
    DIRECTION OUTPUT ;
    USE SIGNAL ;
    ANTENNAPARTIALMETALAREA 5.71 LAYER M2  ;
    ANTENNAPARTIALMETALSIDEAREA 20.942 LAYER M2  ;
    ANTENNAPARTIALCUTAREA 0.04 LAYER V2  ;
    ANTENNAPARTIALMETALAREA 5.64 LAYER M3  ;
    ANTENNAPARTIALMETALSIDEAREA 21.016 LAYER M3  ;
    PORT
      LAYER M2 ;
        RECT 281.400000 0.000000 281.600000 0.600000 ;
    END
  END data_wdata_o[2]
  PIN data_wdata_o[1]
    DIRECTION OUTPUT ;
    USE SIGNAL ;
    ANTENNAPARTIALMETALAREA 0.28 LAYER M2  ;
    ANTENNAPARTIALMETALSIDEAREA 1.036 LAYER M2  ;
    ANTENNAPARTIALCUTAREA 0.04 LAYER V2  ;
    ANTENNAPARTIALMETALAREA 5.24 LAYER M3  ;
    ANTENNAPARTIALMETALSIDEAREA 19.536 LAYER M3  ;
    ANTENNAMODEL OXIDE1 ;
    ANTENNAGATEAREA 2.112 LAYER M3  ;
    ANTENNAMAXAREACAR 4.60379 LAYER M3  ;
    ANTENNAMAXSIDEAREACAR 17.1076 LAYER M3  ;
    ANTENNAMAXCUTCAR 0.0378788 LAYER VL  ;
    PORT
      LAYER M2 ;
        RECT 284.900000 0.000000 285.100000 0.600000 ;
    END
  END data_wdata_o[1]
  PIN data_wdata_o[0]
    DIRECTION OUTPUT ;
    USE SIGNAL ;
    ANTENNAPARTIALMETALAREA 4.27 LAYER M2  ;
    ANTENNAPARTIALMETALSIDEAREA 15.614 LAYER M2  ;
    ANTENNAPARTIALCUTAREA 0.04 LAYER V2  ;
    ANTENNAPARTIALMETALAREA 6.28 LAYER M3  ;
    ANTENNAPARTIALMETALSIDEAREA 23.384 LAYER M3  ;
    ANTENNAMODEL OXIDE1 ;
    ANTENNAGATEAREA 2.112 LAYER M3  ;
    ANTENNAMAXAREACAR 3.23636 LAYER M3  ;
    ANTENNAMAXSIDEAREACAR 12.0492 LAYER M3  ;
    ANTENNAMAXCUTCAR 0.0378788 LAYER VL  ;
    PORT
      LAYER M2 ;
        RECT 288.400000 0.000000 288.600000 0.600000 ;
    END
  END data_wdata_o[0]
  PIN data_wdata_intg_o[6]
    DIRECTION OUTPUT ;
    USE SIGNAL ;
    PORT
      LAYER M2 ;
        RECT 403.900000 0.000000 404.100000 0.600000 ;
    END
  END data_wdata_intg_o[6]
  PIN data_wdata_intg_o[5]
    DIRECTION OUTPUT ;
    USE SIGNAL ;
    PORT
      LAYER M2 ;
        RECT 407.400000 0.000000 407.600000 0.600000 ;
    END
  END data_wdata_intg_o[5]
  PIN data_wdata_intg_o[4]
    DIRECTION OUTPUT ;
    USE SIGNAL ;
    PORT
      LAYER M2 ;
        RECT 410.900000 0.000000 411.100000 0.600000 ;
    END
  END data_wdata_intg_o[4]
  PIN data_wdata_intg_o[3]
    DIRECTION OUTPUT ;
    USE SIGNAL ;
    PORT
      LAYER M2 ;
        RECT 414.400000 0.000000 414.600000 0.600000 ;
    END
  END data_wdata_intg_o[3]
  PIN data_wdata_intg_o[2]
    DIRECTION OUTPUT ;
    USE SIGNAL ;
    PORT
      LAYER M2 ;
        RECT 417.900000 0.000000 418.100000 0.600000 ;
    END
  END data_wdata_intg_o[2]
  PIN data_wdata_intg_o[1]
    DIRECTION OUTPUT ;
    USE SIGNAL ;
    PORT
      LAYER M2 ;
        RECT 421.400000 0.000000 421.600000 0.600000 ;
    END
  END data_wdata_intg_o[1]
  PIN data_wdata_intg_o[0]
    DIRECTION OUTPUT ;
    USE SIGNAL ;
    PORT
      LAYER M2 ;
        RECT 424.900000 0.000000 425.100000 0.600000 ;
    END
  END data_wdata_intg_o[0]
  PIN data_rdata_i[31]
    DIRECTION INPUT ;
    USE SIGNAL ;
    ANTENNAPARTIALMETALAREA 2.18 LAYER M2  ;
    ANTENNAPARTIALMETALSIDEAREA 7.696 LAYER M2  ;
    ANTENNAPARTIALCUTAREA 0.04 LAYER V2  ;
    ANTENNAPARTIALMETALAREA 0.36 LAYER M3  ;
    ANTENNAPARTIALMETALSIDEAREA 1.48 LAYER M3  ;
    PORT
      LAYER M2 ;
        RECT 291.900000 0.000000 292.100000 0.600000 ;
    END
  END data_rdata_i[31]
  PIN data_rdata_i[30]
    DIRECTION INPUT ;
    USE SIGNAL ;
    ANTENNAPARTIALMETALAREA 0.43 LAYER M2  ;
    ANTENNAPARTIALMETALSIDEAREA 1.406 LAYER M2  ;
    ANTENNAPARTIALCUTAREA 0.04 LAYER V2  ;
    ANTENNAPARTIALMETALAREA 0.44 LAYER M3  ;
    ANTENNAPARTIALMETALSIDEAREA 1.776 LAYER M3  ;
    PORT
      LAYER M2 ;
        RECT 295.400000 0.000000 295.600000 0.600000 ;
    END
  END data_rdata_i[30]
  PIN data_rdata_i[29]
    DIRECTION INPUT ;
    USE SIGNAL ;
    ANTENNAPARTIALMETALAREA 0.44 LAYER M2  ;
    ANTENNAPARTIALMETALSIDEAREA 1.628 LAYER M2  ;
    ANTENNAPARTIALCUTAREA 0.04 LAYER V2  ;
    ANTENNAPARTIALMETALAREA 0.36 LAYER M3  ;
    ANTENNAPARTIALMETALSIDEAREA 1.48 LAYER M3  ;
    PORT
      LAYER M2 ;
        RECT 298.900000 0.000000 299.100000 0.600000 ;
    END
  END data_rdata_i[29]
  PIN data_rdata_i[28]
    DIRECTION INPUT ;
    USE SIGNAL ;
    ANTENNAPARTIALMETALAREA 2.11 LAYER M2  ;
    ANTENNAPARTIALMETALSIDEAREA 7.622 LAYER M2  ;
    PORT
      LAYER M2 ;
        RECT 302.400000 0.000000 302.600000 0.600000 ;
    END
  END data_rdata_i[28]
  PIN data_rdata_i[27]
    DIRECTION INPUT ;
    USE SIGNAL ;
    ANTENNAPARTIALMETALAREA 0.1 LAYER M2  ;
    ANTENNAPARTIALMETALSIDEAREA 0.222 LAYER M2  ;
    ANTENNAPARTIALCUTAREA 0.04 LAYER V2  ;
    ANTENNAPARTIALMETALAREA 0.4 LAYER M3  ;
    ANTENNAPARTIALMETALSIDEAREA 1.776 LAYER M3  ;
    PORT
      LAYER M2 ;
        RECT 305.900000 0.000000 306.100000 0.600000 ;
    END
  END data_rdata_i[27]
  PIN data_rdata_i[26]
    DIRECTION INPUT ;
    USE SIGNAL ;
    ANTENNAPARTIALMETALAREA 0.43 LAYER M2  ;
    ANTENNAPARTIALMETALSIDEAREA 1.406 LAYER M2  ;
    ANTENNAPARTIALCUTAREA 0.04 LAYER V2  ;
    ANTENNAPARTIALMETALAREA 1.56 LAYER M3  ;
    ANTENNAPARTIALMETALSIDEAREA 5.92 LAYER M3  ;
    PORT
      LAYER M2 ;
        RECT 309.400000 0.000000 309.600000 0.600000 ;
    END
  END data_rdata_i[26]
  PIN data_rdata_i[25]
    DIRECTION INPUT ;
    USE SIGNAL ;
    ANTENNAPARTIALMETALAREA 1.88 LAYER M2  ;
    ANTENNAPARTIALMETALSIDEAREA 6.956 LAYER M2  ;
    PORT
      LAYER M2 ;
        RECT 312.900000 0.000000 313.100000 0.600000 ;
    END
  END data_rdata_i[25]
  PIN data_rdata_i[24]
    DIRECTION INPUT ;
    USE SIGNAL ;
    ANTENNAPARTIALMETALAREA 1.95 LAYER M2  ;
    ANTENNAPARTIALMETALSIDEAREA 7.03 LAYER M2  ;
    PORT
      LAYER M2 ;
        RECT 316.400000 0.000000 316.600000 0.600000 ;
    END
  END data_rdata_i[24]
  PIN data_rdata_i[23]
    DIRECTION INPUT ;
    USE SIGNAL ;
    ANTENNAPARTIALMETALAREA 0.42 LAYER M2  ;
    ANTENNAPARTIALMETALSIDEAREA 1.184 LAYER M2  ;
    PORT
      LAYER M2 ;
        RECT 319.900000 0.000000 320.100000 0.600000 ;
    END
  END data_rdata_i[23]
  PIN data_rdata_i[22]
    DIRECTION INPUT ;
    USE SIGNAL ;
    ANTENNAPARTIALMETALAREA 0.43 LAYER M2  ;
    ANTENNAPARTIALMETALSIDEAREA 1.406 LAYER M2  ;
    ANTENNAPARTIALCUTAREA 0.04 LAYER V2  ;
    ANTENNAPARTIALMETALAREA 0.92 LAYER M3  ;
    ANTENNAPARTIALMETALSIDEAREA 3.552 LAYER M3  ;
    ANTENNAMODEL OXIDE1 ;
    ANTENNAGATEAREA 0.0888 LAYER M3  ;
    ANTENNAMAXAREACAR 31.4414 LAYER M3  ;
    ANTENNAMAXSIDEAREACAR 119.995 LAYER M3  ;
    ANTENNAMAXCUTCAR 0.900901 LAYER VL  ;
    PORT
      LAYER M2 ;
        RECT 323.400000 0.000000 323.600000 0.600000 ;
    END
  END data_rdata_i[22]
  PIN data_rdata_i[21]
    DIRECTION INPUT ;
    USE SIGNAL ;
    ANTENNAPARTIALMETALAREA 1.88 LAYER M2  ;
    ANTENNAPARTIALMETALSIDEAREA 6.956 LAYER M2  ;
    PORT
      LAYER M2 ;
        RECT 326.900000 0.000000 327.100000 0.600000 ;
    END
  END data_rdata_i[21]
  PIN data_rdata_i[20]
    DIRECTION INPUT ;
    USE SIGNAL ;
    ANTENNAPARTIALMETALAREA 0.35 LAYER M2  ;
    ANTENNAPARTIALMETALSIDEAREA 1.11 LAYER M2  ;
    ANTENNAPARTIALCUTAREA 0.04 LAYER V2  ;
    ANTENNAPARTIALMETALAREA 1.8 LAYER M3  ;
    ANTENNAPARTIALMETALSIDEAREA 6.808 LAYER M3  ;
    PORT
      LAYER M2 ;
        RECT 330.400000 0.000000 330.600000 0.600000 ;
    END
  END data_rdata_i[20]
  PIN data_rdata_i[19]
    DIRECTION INPUT ;
    USE SIGNAL ;
    ANTENNAPARTIALMETALAREA 0.34 LAYER M2  ;
    ANTENNAPARTIALMETALSIDEAREA 0.888 LAYER M2  ;
    PORT
      LAYER M2 ;
        RECT 333.900000 0.000000 334.100000 0.600000 ;
    END
  END data_rdata_i[19]
  PIN data_rdata_i[18]
    DIRECTION INPUT ;
    USE SIGNAL ;
    ANTENNAPARTIALMETALAREA 0.06 LAYER M2  ;
    ANTENNAPARTIALMETALSIDEAREA 0.148 LAYER M2  ;
    ANTENNAPARTIALCUTAREA 0.04 LAYER V2  ;
    ANTENNAPARTIALMETALAREA 0.24 LAYER M3  ;
    ANTENNAPARTIALMETALSIDEAREA 1.184 LAYER M3  ;
    ANTENNAMODEL OXIDE1 ;
    ANTENNAGATEAREA 0.0888 LAYER M3  ;
    ANTENNAMAXAREACAR 4.6982 LAYER M3  ;
    ANTENNAMAXSIDEAREACAR 23.0225 LAYER M3  ;
    ANTENNAMAXCUTCAR 0.900901 LAYER VL  ;
    PORT
      LAYER M2 ;
        RECT 337.400000 0.000000 337.600000 0.600000 ;
    END
  END data_rdata_i[18]
  PIN data_rdata_i[17]
    DIRECTION INPUT ;
    USE SIGNAL ;
    ANTENNAPARTIALMETALAREA 0.02 LAYER M2  ;
    ANTENNAPARTIALMETALSIDEAREA 0.074 LAYER M2  ;
    ANTENNAPARTIALCUTAREA 0.04 LAYER V2  ;
    ANTENNAPARTIALMETALAREA 0.12 LAYER M3  ;
    ANTENNAPARTIALMETALSIDEAREA 0.592 LAYER M3  ;
    PORT
      LAYER M2 ;
        RECT 340.900000 0.000000 341.100000 0.600000 ;
    END
  END data_rdata_i[17]
  PIN data_rdata_i[16]
    DIRECTION INPUT ;
    USE SIGNAL ;
    ANTENNAPARTIALMETALAREA 0.06 LAYER M2  ;
    ANTENNAPARTIALMETALSIDEAREA 0.148 LAYER M2  ;
    ANTENNAPARTIALCUTAREA 0.04 LAYER V2  ;
    ANTENNAPARTIALMETALAREA 0.24 LAYER M3  ;
    ANTENNAPARTIALMETALSIDEAREA 1.184 LAYER M3  ;
    PORT
      LAYER M2 ;
        RECT 344.400000 0.000000 344.600000 0.600000 ;
    END
  END data_rdata_i[16]
  PIN data_rdata_i[15]
    DIRECTION INPUT ;
    USE SIGNAL ;
    ANTENNAPARTIALMETALAREA 2.78 LAYER M2  ;
    ANTENNAPARTIALMETALSIDEAREA 9.916 LAYER M2  ;
    ANTENNAPARTIALCUTAREA 0.08 LAYER V2  ;
    ANTENNAPARTIALMETALAREA 0.12 LAYER M3  ;
    ANTENNAPARTIALMETALSIDEAREA 0.592 LAYER M3  ;
    PORT
      LAYER M2 ;
        RECT 347.900000 0.000000 348.100000 0.600000 ;
    END
  END data_rdata_i[15]
  PIN data_rdata_i[14]
    DIRECTION INPUT ;
    USE SIGNAL ;
    ANTENNAPARTIALMETALAREA 0.59 LAYER M2  ;
    ANTENNAPARTIALMETALSIDEAREA 1.998 LAYER M2  ;
    ANTENNAPARTIALCUTAREA 0.04 LAYER V2  ;
    ANTENNAPARTIALMETALAREA 1.88 LAYER M3  ;
    ANTENNAPARTIALMETALSIDEAREA 7.104 LAYER M3  ;
    PORT
      LAYER M2 ;
        RECT 351.400000 0.000000 351.600000 0.600000 ;
    END
  END data_rdata_i[14]
  PIN data_rdata_i[13]
    DIRECTION INPUT ;
    USE SIGNAL ;
    ANTENNAPARTIALMETALAREA 0.6 LAYER M2  ;
    ANTENNAPARTIALMETALSIDEAREA 2.22 LAYER M2  ;
    ANTENNAPARTIALCUTAREA 0.04 LAYER V2  ;
    ANTENNAPARTIALMETALAREA 0.28 LAYER M3  ;
    ANTENNAPARTIALMETALSIDEAREA 1.184 LAYER M3  ;
    PORT
      LAYER M2 ;
        RECT 354.900000 0.000000 355.100000 0.600000 ;
    END
  END data_rdata_i[13]
  PIN data_rdata_i[12]
    DIRECTION INPUT ;
    USE SIGNAL ;
    ANTENNAPARTIALMETALAREA 0.43 LAYER M2  ;
    ANTENNAPARTIALMETALSIDEAREA 1.406 LAYER M2  ;
    PORT
      LAYER M2 ;
        RECT 358.400000 0.000000 358.600000 0.600000 ;
    END
  END data_rdata_i[12]
  PIN data_rdata_i[11]
    DIRECTION INPUT ;
    USE SIGNAL ;
    ANTENNAPARTIALMETALAREA 0.82 LAYER M2  ;
    ANTENNAPARTIALMETALSIDEAREA 2.664 LAYER M2  ;
    ANTENNAPARTIALCUTAREA 0.04 LAYER V2  ;
    ANTENNAPARTIALMETALAREA 1.24 LAYER M3  ;
    ANTENNAPARTIALMETALSIDEAREA 4.736 LAYER M3  ;
    PORT
      LAYER M2 ;
        RECT 361.900000 0.000000 362.100000 0.600000 ;
    END
  END data_rdata_i[11]
  PIN data_rdata_i[10]
    DIRECTION INPUT ;
    USE SIGNAL ;
    ANTENNAPARTIALMETALAREA 0.51 LAYER M2  ;
    ANTENNAPARTIALMETALSIDEAREA 1.702 LAYER M2  ;
    PORT
      LAYER M2 ;
        RECT 365.400000 0.000000 365.600000 0.600000 ;
    END
  END data_rdata_i[10]
  PIN data_rdata_i[9]
    DIRECTION INPUT ;
    USE SIGNAL ;
    ANTENNAPARTIALMETALAREA 1.88 LAYER M2  ;
    ANTENNAPARTIALMETALSIDEAREA 6.956 LAYER M2  ;
    PORT
      LAYER M2 ;
        RECT 368.900000 0.000000 369.100000 0.600000 ;
    END
  END data_rdata_i[9]
  PIN data_rdata_i[8]
    DIRECTION INPUT ;
    USE SIGNAL ;
    ANTENNAPARTIALMETALAREA 0.67 LAYER M2  ;
    ANTENNAPARTIALMETALSIDEAREA 2.294 LAYER M2  ;
    PORT
      LAYER M2 ;
        RECT 372.400000 0.000000 372.600000 0.600000 ;
    END
  END data_rdata_i[8]
  PIN data_rdata_i[7]
    DIRECTION INPUT ;
    USE SIGNAL ;
    ANTENNAPARTIALMETALAREA 0.66 LAYER M2  ;
    ANTENNAPARTIALMETALSIDEAREA 2.072 LAYER M2  ;
    PORT
      LAYER M2 ;
        RECT 375.900000 0.000000 376.100000 0.600000 ;
    END
  END data_rdata_i[7]
  PIN data_rdata_i[6]
    DIRECTION INPUT ;
    USE SIGNAL ;
    ANTENNAPARTIALMETALAREA 1.95 LAYER M2  ;
    ANTENNAPARTIALMETALSIDEAREA 7.03 LAYER M2  ;
    PORT
      LAYER M2 ;
        RECT 379.400000 0.000000 379.600000 0.600000 ;
    END
  END data_rdata_i[6]
  PIN data_rdata_i[5]
    DIRECTION INPUT ;
    USE SIGNAL ;
    ANTENNAPARTIALMETALAREA 1.88 LAYER M2  ;
    ANTENNAPARTIALMETALSIDEAREA 6.956 LAYER M2  ;
    PORT
      LAYER M2 ;
        RECT 382.900000 0.000000 383.100000 0.600000 ;
    END
  END data_rdata_i[5]
  PIN data_rdata_i[4]
    DIRECTION INPUT ;
    USE SIGNAL ;
    ANTENNAPARTIALMETALAREA 0.27 LAYER M2  ;
    ANTENNAPARTIALMETALSIDEAREA 0.814 LAYER M2  ;
    PORT
      LAYER M2 ;
        RECT 386.400000 0.000000 386.600000 0.600000 ;
    END
  END data_rdata_i[4]
  PIN data_rdata_i[3]
    DIRECTION INPUT ;
    USE SIGNAL ;
    ANTENNAPARTIALMETALAREA 2.06 LAYER M2  ;
    ANTENNAPARTIALMETALSIDEAREA 7.252 LAYER M2  ;
    ANTENNAPARTIALCUTAREA 0.08 LAYER V2  ;
    ANTENNAPARTIALMETALAREA 0.12 LAYER M3  ;
    ANTENNAPARTIALMETALSIDEAREA 0.592 LAYER M3  ;
    PORT
      LAYER M2 ;
        RECT 389.900000 0.000000 390.100000 0.600000 ;
    END
  END data_rdata_i[3]
  PIN data_rdata_i[2]
    DIRECTION INPUT ;
    USE SIGNAL ;
    ANTENNAPARTIALMETALAREA 0.35 LAYER M2  ;
    ANTENNAPARTIALMETALSIDEAREA 1.11 LAYER M2  ;
    PORT
      LAYER M2 ;
        RECT 393.400000 0.000000 393.600000 0.600000 ;
    END
  END data_rdata_i[2]
  PIN data_rdata_i[1]
    DIRECTION INPUT ;
    USE SIGNAL ;
    ANTENNAPARTIALMETALAREA 0.36 LAYER M2  ;
    ANTENNAPARTIALMETALSIDEAREA 1.332 LAYER M2  ;
    PORT
      LAYER M2 ;
        RECT 396.900000 0.000000 397.100000 0.600000 ;
    END
  END data_rdata_i[1]
  PIN data_rdata_i[0]
    DIRECTION INPUT ;
    USE SIGNAL ;
    ANTENNAPARTIALMETALAREA 0.51 LAYER M2  ;
    ANTENNAPARTIALMETALSIDEAREA 1.702 LAYER M2  ;
    PORT
      LAYER M2 ;
        RECT 400.400000 0.000000 400.600000 0.600000 ;
    END
  END data_rdata_i[0]
  PIN data_rdata_intg_i[6]
    DIRECTION INPUT ;
    USE SIGNAL ;
    PORT
      LAYER M2 ;
        RECT 428.400000 0.000000 428.600000 0.600000 ;
    END
  END data_rdata_intg_i[6]
  PIN data_rdata_intg_i[5]
    DIRECTION INPUT ;
    USE SIGNAL ;
    PORT
      LAYER M2 ;
        RECT 431.900000 0.000000 432.100000 0.600000 ;
    END
  END data_rdata_intg_i[5]
  PIN data_rdata_intg_i[4]
    DIRECTION INPUT ;
    USE SIGNAL ;
    PORT
      LAYER M2 ;
        RECT 435.400000 0.000000 435.600000 0.600000 ;
    END
  END data_rdata_intg_i[4]
  PIN data_rdata_intg_i[3]
    DIRECTION INPUT ;
    USE SIGNAL ;
    PORT
      LAYER M2 ;
        RECT 438.900000 0.000000 439.100000 0.600000 ;
    END
  END data_rdata_intg_i[3]
  PIN data_rdata_intg_i[2]
    DIRECTION INPUT ;
    USE SIGNAL ;
    PORT
      LAYER M2 ;
        RECT 442.400000 0.000000 442.600000 0.600000 ;
    END
  END data_rdata_intg_i[2]
  PIN data_rdata_intg_i[1]
    DIRECTION INPUT ;
    USE SIGNAL ;
    PORT
      LAYER M2 ;
        RECT 445.900000 0.000000 446.100000 0.600000 ;
    END
  END data_rdata_intg_i[1]
  PIN data_rdata_intg_i[0]
    DIRECTION INPUT ;
    USE SIGNAL ;
    PORT
      LAYER M2 ;
        RECT 449.400000 0.000000 449.600000 0.600000 ;
    END
  END data_rdata_intg_i[0]
  PIN data_err_i
    DIRECTION INPUT ;
    USE SIGNAL ;
    ANTENNAPARTIALMETALAREA 0.44 LAYER M2  ;
    ANTENNAPARTIALMETALSIDEAREA 1.628 LAYER M2  ;
    ANTENNAPARTIALCUTAREA 0.04 LAYER V2  ;
    ANTENNAPARTIALMETALAREA 1.16 LAYER M3  ;
    ANTENNAPARTIALMETALSIDEAREA 4.44 LAYER M3  ;
    PORT
      LAYER M2 ;
        RECT 452.900000 0.000000 453.100000 0.600000 ;
    END
  END data_err_i
  PIN irq_software_i
    DIRECTION INPUT ;
    USE SIGNAL ;
    ANTENNAPARTIALMETALAREA 0.12 LAYER M3  ;
    ANTENNAPARTIALMETALSIDEAREA 0.444 LAYER M3  ;
    PORT
      LAYER M3 ;
        RECT 456.400000 0.000000 456.600000 0.600000 ;
    END
  END irq_software_i
  PIN irq_timer_i
    DIRECTION INPUT ;
    USE SIGNAL ;
    ANTENNAPARTIALMETALAREA 0.06 LAYER M3  ;
    ANTENNAPARTIALMETALSIDEAREA 0.222 LAYER M3  ;
    PORT
      LAYER M3 ;
        RECT 459.900000 0.000000 460.100000 0.600000 ;
    END
  END irq_timer_i
  PIN irq_external_i
    DIRECTION INPUT ;
    USE SIGNAL ;
    ANTENNAPARTIALMETALAREA 0.08 LAYER M3  ;
    ANTENNAPARTIALMETALSIDEAREA 0.296 LAYER M3  ;
    PORT
      LAYER M3 ;
        RECT 463.400000 0.000000 463.600000 0.600000 ;
    END
  END irq_external_i
  PIN irq_fast_i[14]
    DIRECTION INPUT ;
    USE SIGNAL ;
    ANTENNAPARTIALMETALAREA 0.02 LAYER M3  ;
    ANTENNAPARTIALMETALSIDEAREA 0.074 LAYER M3  ;
    PORT
      LAYER M3 ;
        RECT 466.900000 0.000000 467.100000 0.600000 ;
    END
  END irq_fast_i[14]
  PIN irq_fast_i[13]
    DIRECTION INPUT ;
    USE SIGNAL ;
    ANTENNAPARTIALMETALAREA 0.12 LAYER M3  ;
    ANTENNAPARTIALMETALSIDEAREA 0.444 LAYER M3  ;
    PORT
      LAYER M3 ;
        RECT 470.400000 0.000000 470.600000 0.600000 ;
    END
  END irq_fast_i[13]
  PIN irq_fast_i[12]
    DIRECTION INPUT ;
    USE SIGNAL ;
    ANTENNAPARTIALMETALAREA 0.02 LAYER M3  ;
    ANTENNAPARTIALMETALSIDEAREA 0.074 LAYER M3  ;
    ANTENNAMODEL OXIDE1 ;
    ANTENNAGATEAREA 0.1608 LAYER M3  ;
    ANTENNAMAXAREACAR 15.8259 LAYER M3  ;
    ANTENNAMAXSIDEAREACAR 60.2164 LAYER M3  ;
    ANTENNAMAXCUTCAR 0.497512 LAYER VL  ;
    PORT
      LAYER M3 ;
        RECT 473.900000 0.000000 474.100000 0.600000 ;
    END
  END irq_fast_i[12]
  PIN irq_fast_i[11]
    DIRECTION INPUT ;
    USE SIGNAL ;
    ANTENNAPARTIALMETALAREA 1.28 LAYER M3  ;
    ANTENNAPARTIALMETALSIDEAREA 4.884 LAYER M3  ;
    PORT
      LAYER M3 ;
        RECT 477.400000 0.000000 477.600000 0.600000 ;
    END
  END irq_fast_i[11]
  PIN irq_fast_i[10]
    DIRECTION INPUT ;
    USE SIGNAL ;
    ANTENNAPARTIALMETALAREA 0.26 LAYER M3  ;
    ANTENNAPARTIALMETALSIDEAREA 0.962 LAYER M3  ;
    ANTENNAMODEL OXIDE1 ;
    ANTENNAGATEAREA 0.1608 LAYER M3  ;
    ANTENNAMAXAREACAR 15.8458 LAYER M3  ;
    ANTENNAMAXSIDEAREACAR 59.6493 LAYER M3  ;
    ANTENNAMAXCUTCAR 0.497512 LAYER VL  ;
    PORT
      LAYER M3 ;
        RECT 480.900000 0.000000 481.100000 0.600000 ;
    END
  END irq_fast_i[10]
  PIN irq_fast_i[9]
    DIRECTION INPUT ;
    USE SIGNAL ;
    ANTENNAPARTIALMETALAREA 0.4 LAYER M3  ;
    ANTENNAPARTIALMETALSIDEAREA 1.628 LAYER M3  ;
    PORT
      LAYER M3 ;
        RECT 484.400000 0.000000 484.600000 0.600000 ;
    END
  END irq_fast_i[9]
  PIN irq_fast_i[8]
    DIRECTION INPUT ;
    USE SIGNAL ;
    ANTENNAPARTIALMETALAREA 0.06 LAYER M3  ;
    ANTENNAPARTIALMETALSIDEAREA 0.222 LAYER M3  ;
    ANTENNAMODEL OXIDE1 ;
    ANTENNAGATEAREA 0.1608 LAYER M3  ;
    ANTENNAMAXAREACAR 14.602 LAYER M3  ;
    ANTENNAMAXSIDEAREACAR 55.0473 LAYER M3  ;
    ANTENNAMAXCUTCAR 0.497512 LAYER VL  ;
    PORT
      LAYER M3 ;
        RECT 487.900000 0.000000 488.100000 0.600000 ;
    END
  END irq_fast_i[8]
  PIN irq_fast_i[7]
    DIRECTION INPUT ;
    USE SIGNAL ;
    ANTENNAPARTIALMETALAREA 0.08 LAYER M3  ;
    ANTENNAPARTIALMETALSIDEAREA 0.296 LAYER M3  ;
    ANTENNAMODEL OXIDE1 ;
    ANTENNAGATEAREA 0.1608 LAYER M3  ;
    ANTENNAMAXAREACAR 14.7264 LAYER M3  ;
    ANTENNAMAXSIDEAREACAR 55.5075 LAYER M3  ;
    ANTENNAMAXCUTCAR 0.497512 LAYER VL  ;
    PORT
      LAYER M3 ;
        RECT 491.400000 0.000000 491.600000 0.600000 ;
    END
  END irq_fast_i[7]
  PIN irq_fast_i[6]
    DIRECTION INPUT ;
    USE SIGNAL ;
    ANTENNAPARTIALMETALAREA 0.1 LAYER M3  ;
    ANTENNAPARTIALMETALSIDEAREA 0.37 LAYER M3  ;
    ANTENNAMODEL OXIDE1 ;
    ANTENNAGATEAREA 0.1608 LAYER M3  ;
    ANTENNAMAXAREACAR 14.8507 LAYER M3  ;
    ANTENNAMAXSIDEAREACAR 55.9677 LAYER M3  ;
    ANTENNAMAXCUTCAR 0.497512 LAYER VL  ;
    PORT
      LAYER M3 ;
        RECT 494.900000 0.000000 495.100000 0.600000 ;
    END
  END irq_fast_i[6]
  PIN irq_fast_i[5]
    DIRECTION INPUT ;
    USE SIGNAL ;
    ANTENNAPARTIALMETALAREA 0.4 LAYER M3  ;
    ANTENNAPARTIALMETALSIDEAREA 1.628 LAYER M3  ;
    PORT
      LAYER M3 ;
        RECT 498.400000 0.000000 498.600000 0.600000 ;
    END
  END irq_fast_i[5]
  PIN irq_fast_i[4]
    DIRECTION INPUT ;
    USE SIGNAL ;
    ANTENNAPARTIALMETALAREA 0.74 LAYER M3  ;
    ANTENNAPARTIALMETALSIDEAREA 2.886 LAYER M3  ;
    PORT
      LAYER M3 ;
        RECT 501.900000 0.000000 502.100000 0.600000 ;
    END
  END irq_fast_i[4]
  PIN irq_fast_i[3]
    DIRECTION INPUT ;
    USE SIGNAL ;
    ANTENNAPARTIALMETALAREA 0.02 LAYER M3  ;
    ANTENNAPARTIALMETALSIDEAREA 0.074 LAYER M3  ;
    ANTENNAMODEL OXIDE1 ;
    ANTENNAGATEAREA 0.1608 LAYER M3  ;
    ANTENNAMAXAREACAR 16.1244 LAYER M3  ;
    ANTENNAMAXSIDEAREACAR 61.4851 LAYER M3  ;
    ANTENNAMAXCUTCAR 0.497512 LAYER VL  ;
    PORT
      LAYER M3 ;
        RECT 505.400000 0.000000 505.600000 0.600000 ;
    END
  END irq_fast_i[3]
  PIN irq_fast_i[2]
    DIRECTION INPUT ;
    USE SIGNAL ;
    ANTENNAPARTIALMETALAREA 0.02 LAYER M3  ;
    ANTENNAPARTIALMETALSIDEAREA 0.074 LAYER M3  ;
    PORT
      LAYER M3 ;
        RECT 508.900000 0.000000 509.100000 0.600000 ;
    END
  END irq_fast_i[2]
  PIN irq_fast_i[1]
    DIRECTION INPUT ;
    USE SIGNAL ;
    ANTENNAPARTIALMETALAREA 0.56 LAYER M3  ;
    ANTENNAPARTIALMETALSIDEAREA 2.22 LAYER M3  ;
    PORT
      LAYER M3 ;
        RECT 512.400000 0.000000 512.600000 0.600000 ;
    END
  END irq_fast_i[1]
  PIN irq_fast_i[0]
    DIRECTION INPUT ;
    USE SIGNAL ;
    ANTENNAPARTIALMETALAREA 0.58 LAYER M3  ;
    ANTENNAPARTIALMETALSIDEAREA 2.294 LAYER M3  ;
    PORT
      LAYER M3 ;
        RECT 515.900000 0.000000 516.100000 0.600000 ;
    END
  END irq_fast_i[0]
  PIN irq_nm_i
    DIRECTION INPUT ;
    USE SIGNAL ;
    ANTENNAPARTIALMETALAREA 0.16 LAYER M3  ;
    ANTENNAPARTIALMETALSIDEAREA 0.592 LAYER M3  ;
    ANTENNAMODEL OXIDE1 ;
    ANTENNAGATEAREA 0.1608 LAYER M3  ;
    ANTENNAMAXAREACAR 15.2239 LAYER M3  ;
    ANTENNAMAXSIDEAREACAR 57.3483 LAYER M3  ;
    ANTENNAMAXCUTCAR 0.497512 LAYER VL  ;
    PORT
      LAYER M3 ;
        RECT 519.400000 0.000000 519.600000 0.600000 ;
    END
  END irq_nm_i
  PIN scramble_key_valid_i
    DIRECTION INPUT ;
    USE SIGNAL ;
    PORT
      LAYER M3 ;
        RECT 563.400000 9.900000 564.000000 10.100000 ;
    END
  END scramble_key_valid_i
  PIN scramble_key_i[127]
    DIRECTION INPUT ;
    USE SIGNAL ;
    PORT
      LAYER M3 ;
        RECT 563.400000 12.400000 564.000000 12.600000 ;
    END
  END scramble_key_i[127]
  PIN scramble_key_i[126]
    DIRECTION INPUT ;
    USE SIGNAL ;
    PORT
      LAYER M3 ;
        RECT 563.400000 14.900000 564.000000 15.100000 ;
    END
  END scramble_key_i[126]
  PIN scramble_key_i[125]
    DIRECTION INPUT ;
    USE SIGNAL ;
    PORT
      LAYER M3 ;
        RECT 563.400000 17.400000 564.000000 17.600000 ;
    END
  END scramble_key_i[125]
  PIN scramble_key_i[124]
    DIRECTION INPUT ;
    USE SIGNAL ;
    PORT
      LAYER M3 ;
        RECT 563.400000 19.900000 564.000000 20.100000 ;
    END
  END scramble_key_i[124]
  PIN scramble_key_i[123]
    DIRECTION INPUT ;
    USE SIGNAL ;
    PORT
      LAYER M3 ;
        RECT 563.400000 22.400000 564.000000 22.600000 ;
    END
  END scramble_key_i[123]
  PIN scramble_key_i[122]
    DIRECTION INPUT ;
    USE SIGNAL ;
    PORT
      LAYER M3 ;
        RECT 563.400000 24.900000 564.000000 25.100000 ;
    END
  END scramble_key_i[122]
  PIN scramble_key_i[121]
    DIRECTION INPUT ;
    USE SIGNAL ;
    PORT
      LAYER M3 ;
        RECT 563.400000 27.400000 564.000000 27.600000 ;
    END
  END scramble_key_i[121]
  PIN scramble_key_i[120]
    DIRECTION INPUT ;
    USE SIGNAL ;
    PORT
      LAYER M3 ;
        RECT 563.400000 29.900000 564.000000 30.100000 ;
    END
  END scramble_key_i[120]
  PIN scramble_key_i[119]
    DIRECTION INPUT ;
    USE SIGNAL ;
    PORT
      LAYER M3 ;
        RECT 563.400000 32.400000 564.000000 32.600000 ;
    END
  END scramble_key_i[119]
  PIN scramble_key_i[118]
    DIRECTION INPUT ;
    USE SIGNAL ;
    PORT
      LAYER M3 ;
        RECT 563.400000 34.900000 564.000000 35.100000 ;
    END
  END scramble_key_i[118]
  PIN scramble_key_i[117]
    DIRECTION INPUT ;
    USE SIGNAL ;
    PORT
      LAYER M3 ;
        RECT 563.400000 37.400000 564.000000 37.600000 ;
    END
  END scramble_key_i[117]
  PIN scramble_key_i[116]
    DIRECTION INPUT ;
    USE SIGNAL ;
    PORT
      LAYER M3 ;
        RECT 563.400000 39.900000 564.000000 40.100000 ;
    END
  END scramble_key_i[116]
  PIN scramble_key_i[115]
    DIRECTION INPUT ;
    USE SIGNAL ;
    PORT
      LAYER M3 ;
        RECT 563.400000 42.400000 564.000000 42.600000 ;
    END
  END scramble_key_i[115]
  PIN scramble_key_i[114]
    DIRECTION INPUT ;
    USE SIGNAL ;
    PORT
      LAYER M3 ;
        RECT 563.400000 44.900000 564.000000 45.100000 ;
    END
  END scramble_key_i[114]
  PIN scramble_key_i[113]
    DIRECTION INPUT ;
    USE SIGNAL ;
    PORT
      LAYER M3 ;
        RECT 563.400000 47.400000 564.000000 47.600000 ;
    END
  END scramble_key_i[113]
  PIN scramble_key_i[112]
    DIRECTION INPUT ;
    USE SIGNAL ;
    PORT
      LAYER M3 ;
        RECT 563.400000 49.900000 564.000000 50.100000 ;
    END
  END scramble_key_i[112]
  PIN scramble_key_i[111]
    DIRECTION INPUT ;
    USE SIGNAL ;
    PORT
      LAYER M3 ;
        RECT 563.400000 52.400000 564.000000 52.600000 ;
    END
  END scramble_key_i[111]
  PIN scramble_key_i[110]
    DIRECTION INPUT ;
    USE SIGNAL ;
    PORT
      LAYER M3 ;
        RECT 563.400000 54.900000 564.000000 55.100000 ;
    END
  END scramble_key_i[110]
  PIN scramble_key_i[109]
    DIRECTION INPUT ;
    USE SIGNAL ;
    PORT
      LAYER M3 ;
        RECT 563.400000 57.400000 564.000000 57.600000 ;
    END
  END scramble_key_i[109]
  PIN scramble_key_i[108]
    DIRECTION INPUT ;
    USE SIGNAL ;
    PORT
      LAYER M3 ;
        RECT 563.400000 59.900000 564.000000 60.100000 ;
    END
  END scramble_key_i[108]
  PIN scramble_key_i[107]
    DIRECTION INPUT ;
    USE SIGNAL ;
    PORT
      LAYER M3 ;
        RECT 563.400000 62.400000 564.000000 62.600000 ;
    END
  END scramble_key_i[107]
  PIN scramble_key_i[106]
    DIRECTION INPUT ;
    USE SIGNAL ;
    PORT
      LAYER M3 ;
        RECT 563.400000 64.900000 564.000000 65.100000 ;
    END
  END scramble_key_i[106]
  PIN scramble_key_i[105]
    DIRECTION INPUT ;
    USE SIGNAL ;
    PORT
      LAYER M3 ;
        RECT 563.400000 67.400000 564.000000 67.600000 ;
    END
  END scramble_key_i[105]
  PIN scramble_key_i[104]
    DIRECTION INPUT ;
    USE SIGNAL ;
    PORT
      LAYER M3 ;
        RECT 563.400000 69.900000 564.000000 70.100000 ;
    END
  END scramble_key_i[104]
  PIN scramble_key_i[103]
    DIRECTION INPUT ;
    USE SIGNAL ;
    PORT
      LAYER M3 ;
        RECT 563.400000 72.400000 564.000000 72.600000 ;
    END
  END scramble_key_i[103]
  PIN scramble_key_i[102]
    DIRECTION INPUT ;
    USE SIGNAL ;
    PORT
      LAYER M3 ;
        RECT 563.400000 74.900000 564.000000 75.100000 ;
    END
  END scramble_key_i[102]
  PIN scramble_key_i[101]
    DIRECTION INPUT ;
    USE SIGNAL ;
    PORT
      LAYER M3 ;
        RECT 563.400000 77.400000 564.000000 77.600000 ;
    END
  END scramble_key_i[101]
  PIN scramble_key_i[100]
    DIRECTION INPUT ;
    USE SIGNAL ;
    PORT
      LAYER M3 ;
        RECT 563.400000 79.900000 564.000000 80.100000 ;
    END
  END scramble_key_i[100]
  PIN scramble_key_i[99]
    DIRECTION INPUT ;
    USE SIGNAL ;
    PORT
      LAYER M3 ;
        RECT 563.400000 82.400000 564.000000 82.600000 ;
    END
  END scramble_key_i[99]
  PIN scramble_key_i[98]
    DIRECTION INPUT ;
    USE SIGNAL ;
    PORT
      LAYER M3 ;
        RECT 563.400000 84.900000 564.000000 85.100000 ;
    END
  END scramble_key_i[98]
  PIN scramble_key_i[97]
    DIRECTION INPUT ;
    USE SIGNAL ;
    PORT
      LAYER M3 ;
        RECT 563.400000 87.400000 564.000000 87.600000 ;
    END
  END scramble_key_i[97]
  PIN scramble_key_i[96]
    DIRECTION INPUT ;
    USE SIGNAL ;
    PORT
      LAYER M3 ;
        RECT 563.400000 89.900000 564.000000 90.100000 ;
    END
  END scramble_key_i[96]
  PIN scramble_key_i[95]
    DIRECTION INPUT ;
    USE SIGNAL ;
    PORT
      LAYER M3 ;
        RECT 563.400000 92.400000 564.000000 92.600000 ;
    END
  END scramble_key_i[95]
  PIN scramble_key_i[94]
    DIRECTION INPUT ;
    USE SIGNAL ;
    PORT
      LAYER M3 ;
        RECT 563.400000 94.900000 564.000000 95.100000 ;
    END
  END scramble_key_i[94]
  PIN scramble_key_i[93]
    DIRECTION INPUT ;
    USE SIGNAL ;
    PORT
      LAYER M3 ;
        RECT 563.400000 97.400000 564.000000 97.600000 ;
    END
  END scramble_key_i[93]
  PIN scramble_key_i[92]
    DIRECTION INPUT ;
    USE SIGNAL ;
    PORT
      LAYER M3 ;
        RECT 563.400000 99.900000 564.000000 100.100000 ;
    END
  END scramble_key_i[92]
  PIN scramble_key_i[91]
    DIRECTION INPUT ;
    USE SIGNAL ;
    PORT
      LAYER M3 ;
        RECT 563.400000 102.400000 564.000000 102.600000 ;
    END
  END scramble_key_i[91]
  PIN scramble_key_i[90]
    DIRECTION INPUT ;
    USE SIGNAL ;
    PORT
      LAYER M3 ;
        RECT 563.400000 104.900000 564.000000 105.100000 ;
    END
  END scramble_key_i[90]
  PIN scramble_key_i[89]
    DIRECTION INPUT ;
    USE SIGNAL ;
    PORT
      LAYER M3 ;
        RECT 563.400000 107.400000 564.000000 107.600000 ;
    END
  END scramble_key_i[89]
  PIN scramble_key_i[88]
    DIRECTION INPUT ;
    USE SIGNAL ;
    PORT
      LAYER M3 ;
        RECT 563.400000 109.900000 564.000000 110.100000 ;
    END
  END scramble_key_i[88]
  PIN scramble_key_i[87]
    DIRECTION INPUT ;
    USE SIGNAL ;
    PORT
      LAYER M3 ;
        RECT 563.400000 112.400000 564.000000 112.600000 ;
    END
  END scramble_key_i[87]
  PIN scramble_key_i[86]
    DIRECTION INPUT ;
    USE SIGNAL ;
    PORT
      LAYER M3 ;
        RECT 563.400000 114.900000 564.000000 115.100000 ;
    END
  END scramble_key_i[86]
  PIN scramble_key_i[85]
    DIRECTION INPUT ;
    USE SIGNAL ;
    PORT
      LAYER M3 ;
        RECT 563.400000 117.400000 564.000000 117.600000 ;
    END
  END scramble_key_i[85]
  PIN scramble_key_i[84]
    DIRECTION INPUT ;
    USE SIGNAL ;
    PORT
      LAYER M3 ;
        RECT 563.400000 119.900000 564.000000 120.100000 ;
    END
  END scramble_key_i[84]
  PIN scramble_key_i[83]
    DIRECTION INPUT ;
    USE SIGNAL ;
    PORT
      LAYER M3 ;
        RECT 563.400000 122.400000 564.000000 122.600000 ;
    END
  END scramble_key_i[83]
  PIN scramble_key_i[82]
    DIRECTION INPUT ;
    USE SIGNAL ;
    PORT
      LAYER M3 ;
        RECT 563.400000 124.900000 564.000000 125.100000 ;
    END
  END scramble_key_i[82]
  PIN scramble_key_i[81]
    DIRECTION INPUT ;
    USE SIGNAL ;
    PORT
      LAYER M3 ;
        RECT 563.400000 127.400000 564.000000 127.600000 ;
    END
  END scramble_key_i[81]
  PIN scramble_key_i[80]
    DIRECTION INPUT ;
    USE SIGNAL ;
    PORT
      LAYER M3 ;
        RECT 563.400000 129.900000 564.000000 130.100000 ;
    END
  END scramble_key_i[80]
  PIN scramble_key_i[79]
    DIRECTION INPUT ;
    USE SIGNAL ;
    PORT
      LAYER M3 ;
        RECT 563.400000 132.400000 564.000000 132.600000 ;
    END
  END scramble_key_i[79]
  PIN scramble_key_i[78]
    DIRECTION INPUT ;
    USE SIGNAL ;
    PORT
      LAYER M3 ;
        RECT 563.400000 134.900000 564.000000 135.100000 ;
    END
  END scramble_key_i[78]
  PIN scramble_key_i[77]
    DIRECTION INPUT ;
    USE SIGNAL ;
    PORT
      LAYER M3 ;
        RECT 563.400000 137.400000 564.000000 137.600000 ;
    END
  END scramble_key_i[77]
  PIN scramble_key_i[76]
    DIRECTION INPUT ;
    USE SIGNAL ;
    PORT
      LAYER M3 ;
        RECT 563.400000 139.900000 564.000000 140.100000 ;
    END
  END scramble_key_i[76]
  PIN scramble_key_i[75]
    DIRECTION INPUT ;
    USE SIGNAL ;
    PORT
      LAYER M3 ;
        RECT 563.400000 142.400000 564.000000 142.600000 ;
    END
  END scramble_key_i[75]
  PIN scramble_key_i[74]
    DIRECTION INPUT ;
    USE SIGNAL ;
    PORT
      LAYER M3 ;
        RECT 563.400000 144.900000 564.000000 145.100000 ;
    END
  END scramble_key_i[74]
  PIN scramble_key_i[73]
    DIRECTION INPUT ;
    USE SIGNAL ;
    PORT
      LAYER M3 ;
        RECT 563.400000 147.400000 564.000000 147.600000 ;
    END
  END scramble_key_i[73]
  PIN scramble_key_i[72]
    DIRECTION INPUT ;
    USE SIGNAL ;
    PORT
      LAYER M3 ;
        RECT 563.400000 149.900000 564.000000 150.100000 ;
    END
  END scramble_key_i[72]
  PIN scramble_key_i[71]
    DIRECTION INPUT ;
    USE SIGNAL ;
    PORT
      LAYER M3 ;
        RECT 563.400000 152.400000 564.000000 152.600000 ;
    END
  END scramble_key_i[71]
  PIN scramble_key_i[70]
    DIRECTION INPUT ;
    USE SIGNAL ;
    PORT
      LAYER M3 ;
        RECT 563.400000 154.900000 564.000000 155.100000 ;
    END
  END scramble_key_i[70]
  PIN scramble_key_i[69]
    DIRECTION INPUT ;
    USE SIGNAL ;
    PORT
      LAYER M3 ;
        RECT 563.400000 157.400000 564.000000 157.600000 ;
    END
  END scramble_key_i[69]
  PIN scramble_key_i[68]
    DIRECTION INPUT ;
    USE SIGNAL ;
    PORT
      LAYER M3 ;
        RECT 563.400000 159.900000 564.000000 160.100000 ;
    END
  END scramble_key_i[68]
  PIN scramble_key_i[67]
    DIRECTION INPUT ;
    USE SIGNAL ;
    PORT
      LAYER M3 ;
        RECT 563.400000 162.400000 564.000000 162.600000 ;
    END
  END scramble_key_i[67]
  PIN scramble_key_i[66]
    DIRECTION INPUT ;
    USE SIGNAL ;
    PORT
      LAYER M3 ;
        RECT 563.400000 164.900000 564.000000 165.100000 ;
    END
  END scramble_key_i[66]
  PIN scramble_key_i[65]
    DIRECTION INPUT ;
    USE SIGNAL ;
    PORT
      LAYER M3 ;
        RECT 563.400000 167.400000 564.000000 167.600000 ;
    END
  END scramble_key_i[65]
  PIN scramble_key_i[64]
    DIRECTION INPUT ;
    USE SIGNAL ;
    PORT
      LAYER M3 ;
        RECT 563.400000 169.900000 564.000000 170.100000 ;
    END
  END scramble_key_i[64]
  PIN scramble_key_i[63]
    DIRECTION INPUT ;
    USE SIGNAL ;
    PORT
      LAYER M3 ;
        RECT 563.400000 172.400000 564.000000 172.600000 ;
    END
  END scramble_key_i[63]
  PIN scramble_key_i[62]
    DIRECTION INPUT ;
    USE SIGNAL ;
    PORT
      LAYER M3 ;
        RECT 563.400000 174.900000 564.000000 175.100000 ;
    END
  END scramble_key_i[62]
  PIN scramble_key_i[61]
    DIRECTION INPUT ;
    USE SIGNAL ;
    PORT
      LAYER M3 ;
        RECT 563.400000 177.400000 564.000000 177.600000 ;
    END
  END scramble_key_i[61]
  PIN scramble_key_i[60]
    DIRECTION INPUT ;
    USE SIGNAL ;
    PORT
      LAYER M3 ;
        RECT 563.400000 179.900000 564.000000 180.100000 ;
    END
  END scramble_key_i[60]
  PIN scramble_key_i[59]
    DIRECTION INPUT ;
    USE SIGNAL ;
    PORT
      LAYER M3 ;
        RECT 563.400000 182.400000 564.000000 182.600000 ;
    END
  END scramble_key_i[59]
  PIN scramble_key_i[58]
    DIRECTION INPUT ;
    USE SIGNAL ;
    PORT
      LAYER M3 ;
        RECT 563.400000 184.900000 564.000000 185.100000 ;
    END
  END scramble_key_i[58]
  PIN scramble_key_i[57]
    DIRECTION INPUT ;
    USE SIGNAL ;
    PORT
      LAYER M3 ;
        RECT 563.400000 187.400000 564.000000 187.600000 ;
    END
  END scramble_key_i[57]
  PIN scramble_key_i[56]
    DIRECTION INPUT ;
    USE SIGNAL ;
    PORT
      LAYER M3 ;
        RECT 563.400000 189.900000 564.000000 190.100000 ;
    END
  END scramble_key_i[56]
  PIN scramble_key_i[55]
    DIRECTION INPUT ;
    USE SIGNAL ;
    PORT
      LAYER M3 ;
        RECT 563.400000 192.400000 564.000000 192.600000 ;
    END
  END scramble_key_i[55]
  PIN scramble_key_i[54]
    DIRECTION INPUT ;
    USE SIGNAL ;
    PORT
      LAYER M3 ;
        RECT 563.400000 194.900000 564.000000 195.100000 ;
    END
  END scramble_key_i[54]
  PIN scramble_key_i[53]
    DIRECTION INPUT ;
    USE SIGNAL ;
    PORT
      LAYER M3 ;
        RECT 563.400000 197.400000 564.000000 197.600000 ;
    END
  END scramble_key_i[53]
  PIN scramble_key_i[52]
    DIRECTION INPUT ;
    USE SIGNAL ;
    PORT
      LAYER M3 ;
        RECT 563.400000 199.900000 564.000000 200.100000 ;
    END
  END scramble_key_i[52]
  PIN scramble_key_i[51]
    DIRECTION INPUT ;
    USE SIGNAL ;
    PORT
      LAYER M3 ;
        RECT 563.400000 202.400000 564.000000 202.600000 ;
    END
  END scramble_key_i[51]
  PIN scramble_key_i[50]
    DIRECTION INPUT ;
    USE SIGNAL ;
    PORT
      LAYER M3 ;
        RECT 563.400000 204.900000 564.000000 205.100000 ;
    END
  END scramble_key_i[50]
  PIN scramble_key_i[49]
    DIRECTION INPUT ;
    USE SIGNAL ;
    PORT
      LAYER M3 ;
        RECT 563.400000 207.400000 564.000000 207.600000 ;
    END
  END scramble_key_i[49]
  PIN scramble_key_i[48]
    DIRECTION INPUT ;
    USE SIGNAL ;
    PORT
      LAYER M3 ;
        RECT 563.400000 209.900000 564.000000 210.100000 ;
    END
  END scramble_key_i[48]
  PIN scramble_key_i[47]
    DIRECTION INPUT ;
    USE SIGNAL ;
    PORT
      LAYER M3 ;
        RECT 563.400000 212.400000 564.000000 212.600000 ;
    END
  END scramble_key_i[47]
  PIN scramble_key_i[46]
    DIRECTION INPUT ;
    USE SIGNAL ;
    PORT
      LAYER M3 ;
        RECT 563.400000 214.900000 564.000000 215.100000 ;
    END
  END scramble_key_i[46]
  PIN scramble_key_i[45]
    DIRECTION INPUT ;
    USE SIGNAL ;
    PORT
      LAYER M3 ;
        RECT 563.400000 217.400000 564.000000 217.600000 ;
    END
  END scramble_key_i[45]
  PIN scramble_key_i[44]
    DIRECTION INPUT ;
    USE SIGNAL ;
    PORT
      LAYER M3 ;
        RECT 563.400000 219.900000 564.000000 220.100000 ;
    END
  END scramble_key_i[44]
  PIN scramble_key_i[43]
    DIRECTION INPUT ;
    USE SIGNAL ;
    PORT
      LAYER M3 ;
        RECT 563.400000 222.400000 564.000000 222.600000 ;
    END
  END scramble_key_i[43]
  PIN scramble_key_i[42]
    DIRECTION INPUT ;
    USE SIGNAL ;
    PORT
      LAYER M3 ;
        RECT 563.400000 224.900000 564.000000 225.100000 ;
    END
  END scramble_key_i[42]
  PIN scramble_key_i[41]
    DIRECTION INPUT ;
    USE SIGNAL ;
    PORT
      LAYER M3 ;
        RECT 563.400000 227.400000 564.000000 227.600000 ;
    END
  END scramble_key_i[41]
  PIN scramble_key_i[40]
    DIRECTION INPUT ;
    USE SIGNAL ;
    PORT
      LAYER M3 ;
        RECT 563.400000 229.900000 564.000000 230.100000 ;
    END
  END scramble_key_i[40]
  PIN scramble_key_i[39]
    DIRECTION INPUT ;
    USE SIGNAL ;
    PORT
      LAYER M3 ;
        RECT 563.400000 232.400000 564.000000 232.600000 ;
    END
  END scramble_key_i[39]
  PIN scramble_key_i[38]
    DIRECTION INPUT ;
    USE SIGNAL ;
    PORT
      LAYER M3 ;
        RECT 563.400000 234.900000 564.000000 235.100000 ;
    END
  END scramble_key_i[38]
  PIN scramble_key_i[37]
    DIRECTION INPUT ;
    USE SIGNAL ;
    PORT
      LAYER M3 ;
        RECT 563.400000 237.400000 564.000000 237.600000 ;
    END
  END scramble_key_i[37]
  PIN scramble_key_i[36]
    DIRECTION INPUT ;
    USE SIGNAL ;
    PORT
      LAYER M3 ;
        RECT 563.400000 239.900000 564.000000 240.100000 ;
    END
  END scramble_key_i[36]
  PIN scramble_key_i[35]
    DIRECTION INPUT ;
    USE SIGNAL ;
    PORT
      LAYER M3 ;
        RECT 563.400000 242.400000 564.000000 242.600000 ;
    END
  END scramble_key_i[35]
  PIN scramble_key_i[34]
    DIRECTION INPUT ;
    USE SIGNAL ;
    PORT
      LAYER M3 ;
        RECT 563.400000 244.900000 564.000000 245.100000 ;
    END
  END scramble_key_i[34]
  PIN scramble_key_i[33]
    DIRECTION INPUT ;
    USE SIGNAL ;
    PORT
      LAYER M3 ;
        RECT 563.400000 247.400000 564.000000 247.600000 ;
    END
  END scramble_key_i[33]
  PIN scramble_key_i[32]
    DIRECTION INPUT ;
    USE SIGNAL ;
    PORT
      LAYER M3 ;
        RECT 563.400000 249.900000 564.000000 250.100000 ;
    END
  END scramble_key_i[32]
  PIN scramble_key_i[31]
    DIRECTION INPUT ;
    USE SIGNAL ;
    PORT
      LAYER M3 ;
        RECT 563.400000 252.400000 564.000000 252.600000 ;
    END
  END scramble_key_i[31]
  PIN scramble_key_i[30]
    DIRECTION INPUT ;
    USE SIGNAL ;
    PORT
      LAYER M3 ;
        RECT 563.400000 254.900000 564.000000 255.100000 ;
    END
  END scramble_key_i[30]
  PIN scramble_key_i[29]
    DIRECTION INPUT ;
    USE SIGNAL ;
    PORT
      LAYER M3 ;
        RECT 563.400000 257.400000 564.000000 257.600000 ;
    END
  END scramble_key_i[29]
  PIN scramble_key_i[28]
    DIRECTION INPUT ;
    USE SIGNAL ;
    PORT
      LAYER M3 ;
        RECT 563.400000 259.900000 564.000000 260.100000 ;
    END
  END scramble_key_i[28]
  PIN scramble_key_i[27]
    DIRECTION INPUT ;
    USE SIGNAL ;
    PORT
      LAYER M3 ;
        RECT 563.400000 262.400000 564.000000 262.600000 ;
    END
  END scramble_key_i[27]
  PIN scramble_key_i[26]
    DIRECTION INPUT ;
    USE SIGNAL ;
    PORT
      LAYER M3 ;
        RECT 563.400000 264.900000 564.000000 265.100000 ;
    END
  END scramble_key_i[26]
  PIN scramble_key_i[25]
    DIRECTION INPUT ;
    USE SIGNAL ;
    PORT
      LAYER M3 ;
        RECT 563.400000 267.400000 564.000000 267.600000 ;
    END
  END scramble_key_i[25]
  PIN scramble_key_i[24]
    DIRECTION INPUT ;
    USE SIGNAL ;
    PORT
      LAYER M3 ;
        RECT 563.400000 269.900000 564.000000 270.100000 ;
    END
  END scramble_key_i[24]
  PIN scramble_key_i[23]
    DIRECTION INPUT ;
    USE SIGNAL ;
    PORT
      LAYER M3 ;
        RECT 563.400000 272.400000 564.000000 272.600000 ;
    END
  END scramble_key_i[23]
  PIN scramble_key_i[22]
    DIRECTION INPUT ;
    USE SIGNAL ;
    PORT
      LAYER M3 ;
        RECT 563.400000 274.900000 564.000000 275.100000 ;
    END
  END scramble_key_i[22]
  PIN scramble_key_i[21]
    DIRECTION INPUT ;
    USE SIGNAL ;
    PORT
      LAYER M3 ;
        RECT 563.400000 277.400000 564.000000 277.600000 ;
    END
  END scramble_key_i[21]
  PIN scramble_key_i[20]
    DIRECTION INPUT ;
    USE SIGNAL ;
    PORT
      LAYER M3 ;
        RECT 563.400000 279.900000 564.000000 280.100000 ;
    END
  END scramble_key_i[20]
  PIN scramble_key_i[19]
    DIRECTION INPUT ;
    USE SIGNAL ;
    PORT
      LAYER M3 ;
        RECT 563.400000 282.400000 564.000000 282.600000 ;
    END
  END scramble_key_i[19]
  PIN scramble_key_i[18]
    DIRECTION INPUT ;
    USE SIGNAL ;
    PORT
      LAYER M3 ;
        RECT 563.400000 284.900000 564.000000 285.100000 ;
    END
  END scramble_key_i[18]
  PIN scramble_key_i[17]
    DIRECTION INPUT ;
    USE SIGNAL ;
    PORT
      LAYER M3 ;
        RECT 563.400000 287.400000 564.000000 287.600000 ;
    END
  END scramble_key_i[17]
  PIN scramble_key_i[16]
    DIRECTION INPUT ;
    USE SIGNAL ;
    PORT
      LAYER M3 ;
        RECT 563.400000 289.900000 564.000000 290.100000 ;
    END
  END scramble_key_i[16]
  PIN scramble_key_i[15]
    DIRECTION INPUT ;
    USE SIGNAL ;
    PORT
      LAYER M3 ;
        RECT 563.400000 292.400000 564.000000 292.600000 ;
    END
  END scramble_key_i[15]
  PIN scramble_key_i[14]
    DIRECTION INPUT ;
    USE SIGNAL ;
    PORT
      LAYER M3 ;
        RECT 563.400000 294.900000 564.000000 295.100000 ;
    END
  END scramble_key_i[14]
  PIN scramble_key_i[13]
    DIRECTION INPUT ;
    USE SIGNAL ;
    PORT
      LAYER M3 ;
        RECT 563.400000 297.400000 564.000000 297.600000 ;
    END
  END scramble_key_i[13]
  PIN scramble_key_i[12]
    DIRECTION INPUT ;
    USE SIGNAL ;
    PORT
      LAYER M3 ;
        RECT 563.400000 299.900000 564.000000 300.100000 ;
    END
  END scramble_key_i[12]
  PIN scramble_key_i[11]
    DIRECTION INPUT ;
    USE SIGNAL ;
    PORT
      LAYER M3 ;
        RECT 563.400000 302.400000 564.000000 302.600000 ;
    END
  END scramble_key_i[11]
  PIN scramble_key_i[10]
    DIRECTION INPUT ;
    USE SIGNAL ;
    PORT
      LAYER M3 ;
        RECT 563.400000 304.900000 564.000000 305.100000 ;
    END
  END scramble_key_i[10]
  PIN scramble_key_i[9]
    DIRECTION INPUT ;
    USE SIGNAL ;
    PORT
      LAYER M3 ;
        RECT 563.400000 307.400000 564.000000 307.600000 ;
    END
  END scramble_key_i[9]
  PIN scramble_key_i[8]
    DIRECTION INPUT ;
    USE SIGNAL ;
    PORT
      LAYER M3 ;
        RECT 563.400000 309.900000 564.000000 310.100000 ;
    END
  END scramble_key_i[8]
  PIN scramble_key_i[7]
    DIRECTION INPUT ;
    USE SIGNAL ;
    PORT
      LAYER M3 ;
        RECT 563.400000 312.400000 564.000000 312.600000 ;
    END
  END scramble_key_i[7]
  PIN scramble_key_i[6]
    DIRECTION INPUT ;
    USE SIGNAL ;
    PORT
      LAYER M3 ;
        RECT 563.400000 314.900000 564.000000 315.100000 ;
    END
  END scramble_key_i[6]
  PIN scramble_key_i[5]
    DIRECTION INPUT ;
    USE SIGNAL ;
    PORT
      LAYER M3 ;
        RECT 563.400000 317.400000 564.000000 317.600000 ;
    END
  END scramble_key_i[5]
  PIN scramble_key_i[4]
    DIRECTION INPUT ;
    USE SIGNAL ;
    PORT
      LAYER M3 ;
        RECT 563.400000 319.900000 564.000000 320.100000 ;
    END
  END scramble_key_i[4]
  PIN scramble_key_i[3]
    DIRECTION INPUT ;
    USE SIGNAL ;
    PORT
      LAYER M3 ;
        RECT 563.400000 322.400000 564.000000 322.600000 ;
    END
  END scramble_key_i[3]
  PIN scramble_key_i[2]
    DIRECTION INPUT ;
    USE SIGNAL ;
    PORT
      LAYER M3 ;
        RECT 563.400000 324.900000 564.000000 325.100000 ;
    END
  END scramble_key_i[2]
  PIN scramble_key_i[1]
    DIRECTION INPUT ;
    USE SIGNAL ;
    PORT
      LAYER M3 ;
        RECT 563.400000 327.400000 564.000000 327.600000 ;
    END
  END scramble_key_i[1]
  PIN scramble_key_i[0]
    DIRECTION INPUT ;
    USE SIGNAL ;
    PORT
      LAYER M3 ;
        RECT 563.400000 329.900000 564.000000 330.100000 ;
    END
  END scramble_key_i[0]
  PIN scramble_nonce_i[63]
    DIRECTION INPUT ;
    USE SIGNAL ;
    PORT
      LAYER M3 ;
        RECT 563.400000 332.400000 564.000000 332.600000 ;
    END
  END scramble_nonce_i[63]
  PIN scramble_nonce_i[62]
    DIRECTION INPUT ;
    USE SIGNAL ;
    PORT
      LAYER M3 ;
        RECT 563.400000 334.900000 564.000000 335.100000 ;
    END
  END scramble_nonce_i[62]
  PIN scramble_nonce_i[61]
    DIRECTION INPUT ;
    USE SIGNAL ;
    PORT
      LAYER M3 ;
        RECT 563.400000 337.400000 564.000000 337.600000 ;
    END
  END scramble_nonce_i[61]
  PIN scramble_nonce_i[60]
    DIRECTION INPUT ;
    USE SIGNAL ;
    PORT
      LAYER M3 ;
        RECT 563.400000 339.900000 564.000000 340.100000 ;
    END
  END scramble_nonce_i[60]
  PIN scramble_nonce_i[59]
    DIRECTION INPUT ;
    USE SIGNAL ;
    PORT
      LAYER M3 ;
        RECT 563.400000 342.400000 564.000000 342.600000 ;
    END
  END scramble_nonce_i[59]
  PIN scramble_nonce_i[58]
    DIRECTION INPUT ;
    USE SIGNAL ;
    PORT
      LAYER M3 ;
        RECT 563.400000 344.900000 564.000000 345.100000 ;
    END
  END scramble_nonce_i[58]
  PIN scramble_nonce_i[57]
    DIRECTION INPUT ;
    USE SIGNAL ;
    PORT
      LAYER M3 ;
        RECT 563.400000 347.400000 564.000000 347.600000 ;
    END
  END scramble_nonce_i[57]
  PIN scramble_nonce_i[56]
    DIRECTION INPUT ;
    USE SIGNAL ;
    PORT
      LAYER M3 ;
        RECT 563.400000 349.900000 564.000000 350.100000 ;
    END
  END scramble_nonce_i[56]
  PIN scramble_nonce_i[55]
    DIRECTION INPUT ;
    USE SIGNAL ;
    PORT
      LAYER M3 ;
        RECT 563.400000 352.400000 564.000000 352.600000 ;
    END
  END scramble_nonce_i[55]
  PIN scramble_nonce_i[54]
    DIRECTION INPUT ;
    USE SIGNAL ;
    PORT
      LAYER M3 ;
        RECT 563.400000 354.900000 564.000000 355.100000 ;
    END
  END scramble_nonce_i[54]
  PIN scramble_nonce_i[53]
    DIRECTION INPUT ;
    USE SIGNAL ;
    PORT
      LAYER M3 ;
        RECT 563.400000 357.400000 564.000000 357.600000 ;
    END
  END scramble_nonce_i[53]
  PIN scramble_nonce_i[52]
    DIRECTION INPUT ;
    USE SIGNAL ;
    PORT
      LAYER M3 ;
        RECT 563.400000 359.900000 564.000000 360.100000 ;
    END
  END scramble_nonce_i[52]
  PIN scramble_nonce_i[51]
    DIRECTION INPUT ;
    USE SIGNAL ;
    PORT
      LAYER M3 ;
        RECT 563.400000 362.400000 564.000000 362.600000 ;
    END
  END scramble_nonce_i[51]
  PIN scramble_nonce_i[50]
    DIRECTION INPUT ;
    USE SIGNAL ;
    PORT
      LAYER M3 ;
        RECT 563.400000 364.900000 564.000000 365.100000 ;
    END
  END scramble_nonce_i[50]
  PIN scramble_nonce_i[49]
    DIRECTION INPUT ;
    USE SIGNAL ;
    PORT
      LAYER M3 ;
        RECT 563.400000 367.400000 564.000000 367.600000 ;
    END
  END scramble_nonce_i[49]
  PIN scramble_nonce_i[48]
    DIRECTION INPUT ;
    USE SIGNAL ;
    PORT
      LAYER M3 ;
        RECT 563.400000 369.900000 564.000000 370.100000 ;
    END
  END scramble_nonce_i[48]
  PIN scramble_nonce_i[47]
    DIRECTION INPUT ;
    USE SIGNAL ;
    PORT
      LAYER M3 ;
        RECT 563.400000 372.400000 564.000000 372.600000 ;
    END
  END scramble_nonce_i[47]
  PIN scramble_nonce_i[46]
    DIRECTION INPUT ;
    USE SIGNAL ;
    PORT
      LAYER M3 ;
        RECT 563.400000 374.900000 564.000000 375.100000 ;
    END
  END scramble_nonce_i[46]
  PIN scramble_nonce_i[45]
    DIRECTION INPUT ;
    USE SIGNAL ;
    PORT
      LAYER M3 ;
        RECT 563.400000 377.400000 564.000000 377.600000 ;
    END
  END scramble_nonce_i[45]
  PIN scramble_nonce_i[44]
    DIRECTION INPUT ;
    USE SIGNAL ;
    PORT
      LAYER M3 ;
        RECT 563.400000 379.900000 564.000000 380.100000 ;
    END
  END scramble_nonce_i[44]
  PIN scramble_nonce_i[43]
    DIRECTION INPUT ;
    USE SIGNAL ;
    PORT
      LAYER M3 ;
        RECT 563.400000 382.400000 564.000000 382.600000 ;
    END
  END scramble_nonce_i[43]
  PIN scramble_nonce_i[42]
    DIRECTION INPUT ;
    USE SIGNAL ;
    PORT
      LAYER M3 ;
        RECT 563.400000 384.900000 564.000000 385.100000 ;
    END
  END scramble_nonce_i[42]
  PIN scramble_nonce_i[41]
    DIRECTION INPUT ;
    USE SIGNAL ;
    PORT
      LAYER M3 ;
        RECT 563.400000 387.400000 564.000000 387.600000 ;
    END
  END scramble_nonce_i[41]
  PIN scramble_nonce_i[40]
    DIRECTION INPUT ;
    USE SIGNAL ;
    PORT
      LAYER M3 ;
        RECT 563.400000 389.900000 564.000000 390.100000 ;
    END
  END scramble_nonce_i[40]
  PIN scramble_nonce_i[39]
    DIRECTION INPUT ;
    USE SIGNAL ;
    PORT
      LAYER M3 ;
        RECT 563.400000 392.400000 564.000000 392.600000 ;
    END
  END scramble_nonce_i[39]
  PIN scramble_nonce_i[38]
    DIRECTION INPUT ;
    USE SIGNAL ;
    PORT
      LAYER M3 ;
        RECT 563.400000 394.900000 564.000000 395.100000 ;
    END
  END scramble_nonce_i[38]
  PIN scramble_nonce_i[37]
    DIRECTION INPUT ;
    USE SIGNAL ;
    PORT
      LAYER M3 ;
        RECT 563.400000 397.400000 564.000000 397.600000 ;
    END
  END scramble_nonce_i[37]
  PIN scramble_nonce_i[36]
    DIRECTION INPUT ;
    USE SIGNAL ;
    PORT
      LAYER M3 ;
        RECT 563.400000 399.900000 564.000000 400.100000 ;
    END
  END scramble_nonce_i[36]
  PIN scramble_nonce_i[35]
    DIRECTION INPUT ;
    USE SIGNAL ;
    PORT
      LAYER M3 ;
        RECT 563.400000 402.400000 564.000000 402.600000 ;
    END
  END scramble_nonce_i[35]
  PIN scramble_nonce_i[34]
    DIRECTION INPUT ;
    USE SIGNAL ;
    PORT
      LAYER M3 ;
        RECT 563.400000 404.900000 564.000000 405.100000 ;
    END
  END scramble_nonce_i[34]
  PIN scramble_nonce_i[33]
    DIRECTION INPUT ;
    USE SIGNAL ;
    PORT
      LAYER M3 ;
        RECT 563.400000 407.400000 564.000000 407.600000 ;
    END
  END scramble_nonce_i[33]
  PIN scramble_nonce_i[32]
    DIRECTION INPUT ;
    USE SIGNAL ;
    PORT
      LAYER M3 ;
        RECT 563.400000 409.900000 564.000000 410.100000 ;
    END
  END scramble_nonce_i[32]
  PIN scramble_nonce_i[31]
    DIRECTION INPUT ;
    USE SIGNAL ;
    PORT
      LAYER M3 ;
        RECT 563.400000 412.400000 564.000000 412.600000 ;
    END
  END scramble_nonce_i[31]
  PIN scramble_nonce_i[30]
    DIRECTION INPUT ;
    USE SIGNAL ;
    PORT
      LAYER M3 ;
        RECT 563.400000 414.900000 564.000000 415.100000 ;
    END
  END scramble_nonce_i[30]
  PIN scramble_nonce_i[29]
    DIRECTION INPUT ;
    USE SIGNAL ;
    PORT
      LAYER M3 ;
        RECT 563.400000 417.400000 564.000000 417.600000 ;
    END
  END scramble_nonce_i[29]
  PIN scramble_nonce_i[28]
    DIRECTION INPUT ;
    USE SIGNAL ;
    PORT
      LAYER M3 ;
        RECT 563.400000 419.900000 564.000000 420.100000 ;
    END
  END scramble_nonce_i[28]
  PIN scramble_nonce_i[27]
    DIRECTION INPUT ;
    USE SIGNAL ;
    PORT
      LAYER M3 ;
        RECT 563.400000 422.400000 564.000000 422.600000 ;
    END
  END scramble_nonce_i[27]
  PIN scramble_nonce_i[26]
    DIRECTION INPUT ;
    USE SIGNAL ;
    PORT
      LAYER M3 ;
        RECT 563.400000 424.900000 564.000000 425.100000 ;
    END
  END scramble_nonce_i[26]
  PIN scramble_nonce_i[25]
    DIRECTION INPUT ;
    USE SIGNAL ;
    PORT
      LAYER M3 ;
        RECT 563.400000 427.400000 564.000000 427.600000 ;
    END
  END scramble_nonce_i[25]
  PIN scramble_nonce_i[24]
    DIRECTION INPUT ;
    USE SIGNAL ;
    PORT
      LAYER M3 ;
        RECT 563.400000 429.900000 564.000000 430.100000 ;
    END
  END scramble_nonce_i[24]
  PIN scramble_nonce_i[23]
    DIRECTION INPUT ;
    USE SIGNAL ;
    PORT
      LAYER M3 ;
        RECT 563.400000 432.400000 564.000000 432.600000 ;
    END
  END scramble_nonce_i[23]
  PIN scramble_nonce_i[22]
    DIRECTION INPUT ;
    USE SIGNAL ;
    PORT
      LAYER M3 ;
        RECT 563.400000 434.900000 564.000000 435.100000 ;
    END
  END scramble_nonce_i[22]
  PIN scramble_nonce_i[21]
    DIRECTION INPUT ;
    USE SIGNAL ;
    PORT
      LAYER M3 ;
        RECT 563.400000 437.400000 564.000000 437.600000 ;
    END
  END scramble_nonce_i[21]
  PIN scramble_nonce_i[20]
    DIRECTION INPUT ;
    USE SIGNAL ;
    PORT
      LAYER M3 ;
        RECT 563.400000 439.900000 564.000000 440.100000 ;
    END
  END scramble_nonce_i[20]
  PIN scramble_nonce_i[19]
    DIRECTION INPUT ;
    USE SIGNAL ;
    PORT
      LAYER M3 ;
        RECT 563.400000 442.400000 564.000000 442.600000 ;
    END
  END scramble_nonce_i[19]
  PIN scramble_nonce_i[18]
    DIRECTION INPUT ;
    USE SIGNAL ;
    PORT
      LAYER M3 ;
        RECT 563.400000 444.900000 564.000000 445.100000 ;
    END
  END scramble_nonce_i[18]
  PIN scramble_nonce_i[17]
    DIRECTION INPUT ;
    USE SIGNAL ;
    PORT
      LAYER M3 ;
        RECT 563.400000 447.400000 564.000000 447.600000 ;
    END
  END scramble_nonce_i[17]
  PIN scramble_nonce_i[16]
    DIRECTION INPUT ;
    USE SIGNAL ;
    PORT
      LAYER M3 ;
        RECT 563.400000 449.900000 564.000000 450.100000 ;
    END
  END scramble_nonce_i[16]
  PIN scramble_nonce_i[15]
    DIRECTION INPUT ;
    USE SIGNAL ;
    PORT
      LAYER M3 ;
        RECT 563.400000 452.400000 564.000000 452.600000 ;
    END
  END scramble_nonce_i[15]
  PIN scramble_nonce_i[14]
    DIRECTION INPUT ;
    USE SIGNAL ;
    PORT
      LAYER M3 ;
        RECT 563.400000 454.900000 564.000000 455.100000 ;
    END
  END scramble_nonce_i[14]
  PIN scramble_nonce_i[13]
    DIRECTION INPUT ;
    USE SIGNAL ;
    PORT
      LAYER M3 ;
        RECT 563.400000 457.400000 564.000000 457.600000 ;
    END
  END scramble_nonce_i[13]
  PIN scramble_nonce_i[12]
    DIRECTION INPUT ;
    USE SIGNAL ;
    PORT
      LAYER M3 ;
        RECT 563.400000 459.900000 564.000000 460.100000 ;
    END
  END scramble_nonce_i[12]
  PIN scramble_nonce_i[11]
    DIRECTION INPUT ;
    USE SIGNAL ;
    PORT
      LAYER M3 ;
        RECT 563.400000 462.400000 564.000000 462.600000 ;
    END
  END scramble_nonce_i[11]
  PIN scramble_nonce_i[10]
    DIRECTION INPUT ;
    USE SIGNAL ;
    PORT
      LAYER M3 ;
        RECT 563.400000 464.900000 564.000000 465.100000 ;
    END
  END scramble_nonce_i[10]
  PIN scramble_nonce_i[9]
    DIRECTION INPUT ;
    USE SIGNAL ;
    PORT
      LAYER M3 ;
        RECT 563.400000 467.400000 564.000000 467.600000 ;
    END
  END scramble_nonce_i[9]
  PIN scramble_nonce_i[8]
    DIRECTION INPUT ;
    USE SIGNAL ;
    PORT
      LAYER M3 ;
        RECT 563.400000 469.900000 564.000000 470.100000 ;
    END
  END scramble_nonce_i[8]
  PIN scramble_nonce_i[7]
    DIRECTION INPUT ;
    USE SIGNAL ;
    PORT
      LAYER M3 ;
        RECT 563.400000 472.400000 564.000000 472.600000 ;
    END
  END scramble_nonce_i[7]
  PIN scramble_nonce_i[6]
    DIRECTION INPUT ;
    USE SIGNAL ;
    PORT
      LAYER M3 ;
        RECT 563.400000 474.900000 564.000000 475.100000 ;
    END
  END scramble_nonce_i[6]
  PIN scramble_nonce_i[5]
    DIRECTION INPUT ;
    USE SIGNAL ;
    PORT
      LAYER M3 ;
        RECT 563.400000 477.400000 564.000000 477.600000 ;
    END
  END scramble_nonce_i[5]
  PIN scramble_nonce_i[4]
    DIRECTION INPUT ;
    USE SIGNAL ;
    PORT
      LAYER M3 ;
        RECT 563.400000 479.900000 564.000000 480.100000 ;
    END
  END scramble_nonce_i[4]
  PIN scramble_nonce_i[3]
    DIRECTION INPUT ;
    USE SIGNAL ;
    PORT
      LAYER M3 ;
        RECT 563.400000 482.400000 564.000000 482.600000 ;
    END
  END scramble_nonce_i[3]
  PIN scramble_nonce_i[2]
    DIRECTION INPUT ;
    USE SIGNAL ;
    PORT
      LAYER M3 ;
        RECT 563.400000 484.900000 564.000000 485.100000 ;
    END
  END scramble_nonce_i[2]
  PIN scramble_nonce_i[1]
    DIRECTION INPUT ;
    USE SIGNAL ;
    PORT
      LAYER M3 ;
        RECT 563.400000 487.400000 564.000000 487.600000 ;
    END
  END scramble_nonce_i[1]
  PIN scramble_nonce_i[0]
    DIRECTION INPUT ;
    USE SIGNAL ;
    PORT
      LAYER M3 ;
        RECT 563.400000 489.900000 564.000000 490.100000 ;
    END
  END scramble_nonce_i[0]
  PIN scramble_req_o
    DIRECTION OUTPUT ;
    USE SIGNAL ;
    PORT
      LAYER M3 ;
        RECT 563.400000 492.400000 564.000000 492.600000 ;
    END
  END scramble_req_o
  PIN debug_req_i
    DIRECTION INPUT ;
    USE SIGNAL ;
    ANTENNAPARTIALMETALAREA 1.76 LAYER M3  ;
    ANTENNAPARTIALMETALSIDEAREA 6.66 LAYER M3  ;
    PORT
      LAYER M3 ;
        RECT 0.000000 24.900000 0.600000 25.100000 ;
    END
  END debug_req_i
  PIN crash_dump_o[159]
    DIRECTION OUTPUT ;
    USE SIGNAL ;
    ANTENNAPARTIALMETALAREA 2.5 LAYER M2  ;
    ANTENNAPARTIALMETALSIDEAREA 8.88 LAYER M2  ;
    ANTENNAPARTIALCUTAREA 0.04 LAYER V2  ;
    ANTENNAPARTIALMETALAREA 45.08 LAYER M3  ;
    ANTENNAPARTIALMETALSIDEAREA 167.24 LAYER M3  ;
    ANTENNAMODEL OXIDE1 ;
    ANTENNAGATEAREA 3.5772 LAYER M3  ;
    ANTENNAMAXAREACAR 204.82 LAYER M3  ;
    ANTENNAMAXSIDEAREACAR 759.213 LAYER M3  ;
    ANTENNAMAXCUTCAR 0.961538 LAYER VL  ;
    PORT
      LAYER M2 ;
        RECT 9.900000 563.400000 10.100000 564.000000 ;
    END
  END crash_dump_o[159]
  PIN crash_dump_o[158]
    DIRECTION OUTPUT ;
    USE SIGNAL ;
    ANTENNAPARTIALMETALAREA 5 LAYER M2  ;
    ANTENNAPARTIALMETALSIDEAREA 18.5 LAYER M2  ;
    ANTENNAPARTIALCUTAREA 0.04 LAYER V2  ;
    ANTENNAPARTIALMETALAREA 45.4 LAYER M3  ;
    ANTENNAPARTIALMETALSIDEAREA 168.72 LAYER M3  ;
    ANTENNAMODEL OXIDE1 ;
    ANTENNAGATEAREA 4.0552 LAYER M3  ;
    ANTENNAMAXAREACAR 166.234 LAYER M3  ;
    ANTENNAMAXSIDEAREACAR 616.503 LAYER M3  ;
    ANTENNAMAXCUTCAR 1.07527 LAYER VL  ;
    PORT
      LAYER M2 ;
        RECT 12.900000 563.400000 13.100000 564.000000 ;
    END
  END crash_dump_o[158]
  PIN crash_dump_o[157]
    DIRECTION OUTPUT ;
    USE SIGNAL ;
    ANTENNAPARTIALMETALAREA 4.02 LAYER M2  ;
    ANTENNAPARTIALMETALSIDEAREA 14.504 LAYER M2  ;
    ANTENNAPARTIALCUTAREA 0.04 LAYER V2  ;
    ANTENNAPARTIALMETALAREA 26.28 LAYER M3  ;
    ANTENNAPARTIALMETALSIDEAREA 97.68 LAYER M3  ;
    ANTENNAMODEL OXIDE1 ;
    ANTENNAGATEAREA 3.8032 LAYER M3  ;
    ANTENNAMAXAREACAR 90.1189 LAYER M3  ;
    ANTENNAMAXSIDEAREACAR 334.408 LAYER M3  ;
    ANTENNAMAXCUTCAR 0.591693 LAYER VL  ;
    PORT
      LAYER M2 ;
        RECT 15.900000 563.400000 16.100000 564.000000 ;
    END
  END crash_dump_o[157]
  PIN crash_dump_o[156]
    DIRECTION OUTPUT ;
    USE SIGNAL ;
    ANTENNAPARTIALMETALAREA 3.56 LAYER M2  ;
    ANTENNAPARTIALMETALSIDEAREA 13.172 LAYER M2  ;
    ANTENNAPARTIALCUTAREA 0.04 LAYER V2  ;
    ANTENNAPARTIALMETALAREA 29.88 LAYER M3  ;
    ANTENNAPARTIALMETALSIDEAREA 111 LAYER M3  ;
    ANTENNAMODEL OXIDE1 ;
    ANTENNAGATEAREA 3.7336 LAYER M3  ;
    ANTENNAMAXAREACAR 397.553 LAYER M3  ;
    ANTENNAMAXSIDEAREACAR 1473.06 LAYER M3  ;
    ANTENNAMAXCUTCAR 1.35135 LAYER VL  ;
    PORT
      LAYER M2 ;
        RECT 18.900000 563.400000 19.100000 564.000000 ;
    END
  END crash_dump_o[156]
  PIN crash_dump_o[155]
    DIRECTION OUTPUT ;
    USE SIGNAL ;
    ANTENNAPARTIALMETALAREA 4.1 LAYER M2  ;
    ANTENNAPARTIALMETALSIDEAREA 14.8 LAYER M2  ;
    ANTENNAPARTIALCUTAREA 0.04 LAYER V2  ;
    ANTENNAPARTIALMETALAREA 25.4 LAYER M3  ;
    ANTENNAPARTIALMETALSIDEAREA 94.424 LAYER M3  ;
    ANTENNAMODEL OXIDE1 ;
    ANTENNAGATEAREA 3.7144 LAYER M3  ;
    ANTENNAMAXAREACAR 126.812 LAYER M3  ;
    ANTENNAMAXSIDEAREACAR 469.888 LAYER M3  ;
    ANTENNAMAXCUTCAR 0.411523 LAYER VL  ;
    PORT
      LAYER M2 ;
        RECT 21.900000 563.400000 22.100000 564.000000 ;
    END
  END crash_dump_o[155]
  PIN crash_dump_o[154]
    DIRECTION OUTPUT ;
    USE SIGNAL ;
    ANTENNAPARTIALMETALAREA 0.02 LAYER M2  ;
    ANTENNAPARTIALMETALSIDEAREA 0.074 LAYER M2  ;
    ANTENNAPARTIALCUTAREA 0.04 LAYER V2  ;
    ANTENNAPARTIALMETALAREA 19.08 LAYER M3  ;
    ANTENNAPARTIALMETALSIDEAREA 70.744 LAYER M3  ;
    ANTENNAMODEL OXIDE1 ;
    ANTENNAGATEAREA 3.7096 LAYER M3  ;
    ANTENNAMAXAREACAR 14.8533 LAYER M3  ;
    ANTENNAMAXSIDEAREACAR 54.0899 LAYER M3  ;
    ANTENNAMAXCUTCAR 1.36213 LAYER VL  ;
    PORT
      LAYER M2 ;
        RECT 24.900000 563.400000 25.100000 564.000000 ;
    END
  END crash_dump_o[154]
  PIN crash_dump_o[153]
    DIRECTION OUTPUT ;
    USE SIGNAL ;
    ANTENNAPARTIALMETALAREA 1.82 LAYER M2  ;
    ANTENNAPARTIALMETALSIDEAREA 6.364 LAYER M2  ;
    ANTENNAPARTIALCUTAREA 0.12 LAYER V2  ;
    ANTENNAPARTIALMETALAREA 27.24 LAYER M3  ;
    ANTENNAPARTIALMETALSIDEAREA 101.528 LAYER M3  ;
    ANTENNAMODEL OXIDE1 ;
    ANTENNAGATEAREA 2.2756 LAYER M3  ;
    ANTENNAMAXAREACAR 15.9779 LAYER M3  ;
    ANTENNAMAXSIDEAREACAR 59.5146 LAYER M3  ;
    ANTENNAMAXCUTCAR 0.900901 LAYER VL  ;
    PORT
      LAYER M2 ;
        RECT 27.900000 563.400000 28.100000 564.000000 ;
    END
  END crash_dump_o[153]
  PIN crash_dump_o[152]
    DIRECTION OUTPUT ;
    USE SIGNAL ;
    ANTENNAPARTIALMETALAREA 4.6 LAYER M2  ;
    ANTENNAPARTIALMETALSIDEAREA 17.02 LAYER M2  ;
    ANTENNAPARTIALCUTAREA 0.04 LAYER V2  ;
    ANTENNAPARTIALMETALAREA 27.08 LAYER M3  ;
    ANTENNAPARTIALMETALSIDEAREA 100.936 LAYER M3  ;
    ANTENNAMODEL OXIDE1 ;
    ANTENNAGATEAREA 2.2756 LAYER M3  ;
    ANTENNAMAXAREACAR 13.8957 LAYER M3  ;
    ANTENNAMAXSIDEAREACAR 54.045 LAYER M3  ;
    ANTENNAMAXCUTCAR 0.900901 LAYER VL  ;
    PORT
      LAYER M2 ;
        RECT 30.900000 563.400000 31.100000 564.000000 ;
    END
  END crash_dump_o[152]
  PIN crash_dump_o[151]
    DIRECTION OUTPUT ;
    USE SIGNAL ;
    ANTENNAPARTIALMETALAREA 0.18 LAYER M2  ;
    ANTENNAPARTIALMETALSIDEAREA 0.296 LAYER M2  ;
    ANTENNAPARTIALCUTAREA 0.04 LAYER V2  ;
    ANTENNAPARTIALMETALAREA 5.64 LAYER M3  ;
    ANTENNAPARTIALMETALSIDEAREA 21.016 LAYER M3  ;
    ANTENNAMODEL OXIDE1 ;
    ANTENNAGATEAREA 2.848 LAYER M3  ;
    ANTENNAMAXAREACAR 3.65636 LAYER M3  ;
    ANTENNAMAXSIDEAREACAR 13.5037 LAYER M3  ;
    ANTENNAMAXCUTCAR 0.0280899 LAYER VL  ;
    PORT
      LAYER M2 ;
        RECT 33.900000 563.400000 34.100000 564.000000 ;
    END
  END crash_dump_o[151]
  PIN crash_dump_o[150]
    DIRECTION OUTPUT ;
    USE SIGNAL ;
    ANTENNAPARTIALMETALAREA 2.44 LAYER M2  ;
    ANTENNAPARTIALMETALSIDEAREA 9.028 LAYER M2  ;
    ANTENNAPARTIALCUTAREA 0.04 LAYER V2  ;
    ANTENNAPARTIALMETALAREA 6.36 LAYER M3  ;
    ANTENNAPARTIALMETALSIDEAREA 23.68 LAYER M3  ;
    ANTENNAMODEL OXIDE1 ;
    ANTENNAGATEAREA 3.52 LAYER M3  ;
    ANTENNAMAXAREACAR 2.07636 LAYER M3  ;
    ANTENNAMAXSIDEAREACAR 7.47205 LAYER M3  ;
    ANTENNAMAXCUTCAR 0.0227273 LAYER VL  ;
    PORT
      LAYER M2 ;
        RECT 36.900000 563.400000 37.100000 564.000000 ;
    END
  END crash_dump_o[150]
  PIN crash_dump_o[149]
    DIRECTION OUTPUT ;
    USE SIGNAL ;
    ANTENNAPARTIALMETALAREA 0.1 LAYER M2  ;
    ANTENNAPARTIALMETALSIDEAREA 0.222 LAYER M2  ;
    ANTENNAPARTIALCUTAREA 0.04 LAYER V2  ;
    ANTENNAPARTIALMETALAREA 26.92 LAYER M3  ;
    ANTENNAPARTIALMETALSIDEAREA 100.048 LAYER M3  ;
    ANTENNAMODEL OXIDE1 ;
    ANTENNAGATEAREA 3.8032 LAYER M3  ;
    ANTENNAMAXAREACAR 102.434 LAYER M3  ;
    ANTENNAMAXSIDEAREACAR 379.974 LAYER M3  ;
    ANTENNAMAXCUTCAR 0.591693 LAYER VL  ;
    PORT
      LAYER M2 ;
        RECT 39.900000 563.400000 40.100000 564.000000 ;
    END
  END crash_dump_o[149]
  PIN crash_dump_o[148]
    DIRECTION OUTPUT ;
    USE SIGNAL ;
    ANTENNAPARTIALMETALAREA 0.44 LAYER M2  ;
    ANTENNAPARTIALMETALSIDEAREA 1.628 LAYER M2  ;
    ANTENNAPARTIALCUTAREA 0.04 LAYER V2  ;
    ANTENNAPARTIALMETALAREA 33.44 LAYER M3  ;
    ANTENNAPARTIALMETALSIDEAREA 124.32 LAYER M3  ;
    ANTENNAMODEL OXIDE1 ;
    ANTENNAGATEAREA 2.2756 LAYER M3  ;
    ANTENNAMAXAREACAR 17.908 LAYER M3  ;
    ANTENNAMAXSIDEAREACAR 66.591 LAYER M3  ;
    ANTENNAMAXCUTCAR 0.900901 LAYER VL  ;
    PORT
      LAYER M2 ;
        RECT 42.900000 563.400000 43.100000 564.000000 ;
    END
  END crash_dump_o[148]
  PIN crash_dump_o[147]
    DIRECTION OUTPUT ;
    USE SIGNAL ;
    ANTENNAPARTIALMETALAREA 6.1 LAYER M2  ;
    ANTENNAPARTIALMETALSIDEAREA 22.2 LAYER M2  ;
    ANTENNAPARTIALCUTAREA 0.04 LAYER V2  ;
    ANTENNAPARTIALMETALAREA 22.68 LAYER M3  ;
    ANTENNAPARTIALMETALSIDEAREA 84.36 LAYER M3  ;
    ANTENNAMODEL OXIDE1 ;
    ANTENNAGATEAREA 2.1868 LAYER M3  ;
    ANTENNAMAXAREACAR 63.4917 LAYER M3  ;
    ANTENNAMAXSIDEAREACAR 236.077 LAYER M3  ;
    ANTENNAMAXCUTCAR 0.694444 LAYER VL  ;
    PORT
      LAYER M2 ;
        RECT 45.900000 563.400000 46.100000 564.000000 ;
    END
  END crash_dump_o[147]
  PIN crash_dump_o[146]
    DIRECTION OUTPUT ;
    USE SIGNAL ;
    ANTENNAPARTIALMETALAREA 1.72 LAYER M2  ;
    ANTENNAPARTIALMETALSIDEAREA 6.364 LAYER M2  ;
    ANTENNAPARTIALCUTAREA 0.04 LAYER V2  ;
    ANTENNAPARTIALMETALAREA 31.68 LAYER M3  ;
    ANTENNAPARTIALMETALSIDEAREA 118.104 LAYER M3  ;
    ANTENNAMODEL OXIDE1 ;
    ANTENNAGATEAREA 4.1488 LAYER M3  ;
    ANTENNAMAXAREACAR 113.617 LAYER M3  ;
    ANTENNAMAXSIDEAREACAR 421.165 LAYER M3  ;
    ANTENNAMAXCUTCAR 0.900901 LAYER VL  ;
    PORT
      LAYER M2 ;
        RECT 48.900000 563.400000 49.100000 564.000000 ;
    END
  END crash_dump_o[146]
  PIN crash_dump_o[145]
    DIRECTION OUTPUT ;
    USE SIGNAL ;
    ANTENNAPARTIALMETALAREA 6.98 LAYER M2  ;
    ANTENNAPARTIALMETALSIDEAREA 25.456 LAYER M2  ;
    ANTENNAPARTIALCUTAREA 0.04 LAYER V2  ;
    ANTENNAPARTIALMETALAREA 32.88 LAYER M3  ;
    ANTENNAPARTIALMETALSIDEAREA 122.248 LAYER M3  ;
    ANTENNAMODEL OXIDE1 ;
    ANTENNAGATEAREA 3.6088 LAYER M3  ;
    ANTENNAMAXAREACAR 14.8768 LAYER M3  ;
    ANTENNAMAXSIDEAREACAR 57.2038 LAYER M3  ;
    ANTENNAMAXCUTCAR 0.900901 LAYER VL  ;
    PORT
      LAYER M2 ;
        RECT 51.900000 563.400000 52.100000 564.000000 ;
    END
  END crash_dump_o[145]
  PIN crash_dump_o[144]
    DIRECTION OUTPUT ;
    USE SIGNAL ;
    ANTENNAPARTIALMETALAREA 0.92 LAYER M2  ;
    ANTENNAPARTIALMETALSIDEAREA 3.404 LAYER M2  ;
    ANTENNAPARTIALCUTAREA 0.04 LAYER V2  ;
    ANTENNAPARTIALMETALAREA 21.6 LAYER M3  ;
    ANTENNAPARTIALMETALSIDEAREA 80.512 LAYER M3  ;
    ANTENNAMODEL OXIDE1 ;
    ANTENNAGATEAREA 2.2756 LAYER M3  ;
    ANTENNAMAXAREACAR 78.3208 LAYER M3  ;
    ANTENNAMAXSIDEAREACAR 292.043 LAYER M3  ;
    ANTENNAMAXCUTCAR 1.35135 LAYER VL  ;
    PORT
      LAYER M2 ;
        RECT 54.900000 563.400000 55.100000 564.000000 ;
    END
  END crash_dump_o[144]
  PIN crash_dump_o[143]
    DIRECTION OUTPUT ;
    USE SIGNAL ;
    ANTENNAPARTIALMETALAREA 3.78 LAYER M2  ;
    ANTENNAPARTIALMETALSIDEAREA 13.616 LAYER M2  ;
    ANTENNAPARTIALCUTAREA 0.04 LAYER V2  ;
    ANTENNAPARTIALMETALAREA 1.08 LAYER M3  ;
    ANTENNAPARTIALMETALSIDEAREA 4.144 LAYER M3  ;
    ANTENNAMODEL OXIDE1 ;
    ANTENNAGATEAREA 3.52 LAYER M3  ;
    ANTENNAMAXAREACAR 0.576364 LAYER M3  ;
    ANTENNAMAXSIDEAREACAR 1.92205 LAYER M3  ;
    ANTENNAMAXCUTCAR 0.0227273 LAYER VL  ;
    PORT
      LAYER M2 ;
        RECT 57.900000 563.400000 58.100000 564.000000 ;
    END
  END crash_dump_o[143]
  PIN crash_dump_o[142]
    DIRECTION OUTPUT ;
    USE SIGNAL ;
    ANTENNAPARTIALMETALAREA 2.52 LAYER M2  ;
    ANTENNAPARTIALMETALSIDEAREA 9.324 LAYER M2  ;
    ANTENNAPARTIALCUTAREA 0.04 LAYER V2  ;
    ANTENNAPARTIALMETALAREA 1.32 LAYER M3  ;
    ANTENNAPARTIALMETALSIDEAREA 5.032 LAYER M3  ;
    ANTENNAMODEL OXIDE1 ;
    ANTENNAGATEAREA 3.52 LAYER M3  ;
    ANTENNAMAXAREACAR 0.667273 LAYER M3  ;
    ANTENNAMAXSIDEAREACAR 2.27 LAYER M3  ;
    ANTENNAMAXCUTCAR 0.0227273 LAYER VL  ;
    PORT
      LAYER M2 ;
        RECT 60.900000 563.400000 61.100000 564.000000 ;
    END
  END crash_dump_o[142]
  PIN crash_dump_o[141]
    DIRECTION OUTPUT ;
    USE SIGNAL ;
    ANTENNAPARTIALMETALAREA 0.5 LAYER M2  ;
    ANTENNAPARTIALMETALSIDEAREA 1.48 LAYER M2  ;
    ANTENNAPARTIALCUTAREA 0.04 LAYER V2  ;
    ANTENNAPARTIALMETALAREA 29.76 LAYER M3  ;
    ANTENNAPARTIALMETALSIDEAREA 110.408 LAYER M3  ;
    ANTENNAMODEL OXIDE1 ;
    ANTENNAGATEAREA 2.2036 LAYER M3  ;
    ANTENNAMAXAREACAR 21.9736 LAYER M3  ;
    ANTENNAMAXSIDEAREACAR 83.4323 LAYER M3  ;
    ANTENNAMAXCUTCAR 0.900901 LAYER VL  ;
    PORT
      LAYER M2 ;
        RECT 63.900000 563.400000 64.100000 564.000000 ;
    END
  END crash_dump_o[141]
  PIN crash_dump_o[140]
    DIRECTION OUTPUT ;
    USE SIGNAL ;
    ANTENNAPARTIALMETALAREA 0.28 LAYER M2  ;
    ANTENNAPARTIALMETALSIDEAREA 1.036 LAYER M2  ;
    ANTENNAPARTIALCUTAREA 0.04 LAYER V2  ;
    ANTENNAPARTIALMETALAREA 36.64 LAYER M3  ;
    ANTENNAPARTIALMETALSIDEAREA 136.16 LAYER M3  ;
    ANTENNAMODEL OXIDE1 ;
    ANTENNAGATEAREA 3.9544 LAYER M3  ;
    ANTENNAMAXAREACAR 188.775 LAYER M3  ;
    ANTENNAMAXSIDEAREACAR 699.571 LAYER M3  ;
    ANTENNAMAXCUTCAR 0.900901 LAYER VL  ;
    PORT
      LAYER M2 ;
        RECT 66.900000 563.400000 67.100000 564.000000 ;
    END
  END crash_dump_o[140]
  PIN crash_dump_o[139]
    DIRECTION OUTPUT ;
    USE SIGNAL ;
    ANTENNAPARTIALMETALAREA 0.18 LAYER M2  ;
    ANTENNAPARTIALMETALSIDEAREA 0.296 LAYER M2  ;
    ANTENNAPARTIALCUTAREA 0.04 LAYER V2  ;
    ANTENNAPARTIALMETALAREA 35.32 LAYER M3  ;
    ANTENNAPARTIALMETALSIDEAREA 131.424 LAYER M3  ;
    ANTENNAMODEL OXIDE1 ;
    ANTENNAGATEAREA 3.9064 LAYER M3  ;
    ANTENNAMAXAREACAR 175.618 LAYER M3  ;
    ANTENNAMAXSIDEAREACAR 651.233 LAYER M3  ;
    ANTENNAMAXCUTCAR 0.900901 LAYER VL  ;
    PORT
      LAYER M2 ;
        RECT 69.900000 563.400000 70.100000 564.000000 ;
    END
  END crash_dump_o[139]
  PIN crash_dump_o[138]
    DIRECTION OUTPUT ;
    USE SIGNAL ;
    ANTENNAPARTIALMETALAREA 2.44 LAYER M2  ;
    ANTENNAPARTIALMETALSIDEAREA 9.028 LAYER M2  ;
    ANTENNAPARTIALCUTAREA 0.04 LAYER V2  ;
    ANTENNAPARTIALMETALAREA 39.84 LAYER M3  ;
    ANTENNAPARTIALMETALSIDEAREA 148 LAYER M3  ;
    ANTENNAMODEL OXIDE1 ;
    ANTENNAGATEAREA 4.1728 LAYER M3  ;
    ANTENNAMAXAREACAR 70.9341 LAYER M3  ;
    ANTENNAMAXSIDEAREACAR 263.041 LAYER M3  ;
    ANTENNAMAXCUTCAR 0.900901 LAYER VL  ;
    PORT
      LAYER M2 ;
        RECT 72.900000 563.400000 73.100000 564.000000 ;
    END
  END crash_dump_o[138]
  PIN crash_dump_o[137]
    DIRECTION OUTPUT ;
    USE SIGNAL ;
    ANTENNAPARTIALMETALAREA 4.66 LAYER M2  ;
    ANTENNAPARTIALMETALSIDEAREA 16.872 LAYER M2  ;
    ANTENNAPARTIALCUTAREA 0.04 LAYER V2  ;
    ANTENNAPARTIALMETALAREA 38.28 LAYER M3  ;
    ANTENNAPARTIALMETALSIDEAREA 142.08 LAYER M3  ;
    ANTENNAMODEL OXIDE1 ;
    ANTENNAGATEAREA 2.2756 LAYER M3  ;
    ANTENNAMAXAREACAR 50.5156 LAYER M3  ;
    ANTENNAMAXSIDEAREACAR 189.098 LAYER M3  ;
    ANTENNAMAXCUTCAR 1.35135 LAYER VL  ;
    PORT
      LAYER M2 ;
        RECT 75.900000 563.400000 76.100000 564.000000 ;
    END
  END crash_dump_o[137]
  PIN crash_dump_o[136]
    DIRECTION OUTPUT ;
    USE SIGNAL ;
    ANTENNAPARTIALMETALAREA 1.16 LAYER M2  ;
    ANTENNAPARTIALMETALSIDEAREA 4.292 LAYER M2  ;
    ANTENNAPARTIALCUTAREA 0.04 LAYER V2  ;
    ANTENNAPARTIALMETALAREA 35.76 LAYER M3  ;
    ANTENNAPARTIALMETALSIDEAREA 132.904 LAYER M3  ;
    ANTENNAMODEL OXIDE1 ;
    ANTENNAGATEAREA 2.362 LAYER M3  ;
    ANTENNAMAXAREACAR 25.0114 LAYER M3  ;
    ANTENNAMAXSIDEAREACAR 92.7326 LAYER M3  ;
    ANTENNAMAXCUTCAR 0.900901 LAYER VL  ;
    PORT
      LAYER M2 ;
        RECT 78.900000 563.400000 79.100000 564.000000 ;
    END
  END crash_dump_o[136]
  PIN crash_dump_o[135]
    DIRECTION OUTPUT ;
    USE SIGNAL ;
    ANTENNAPARTIALMETALAREA 2.66 LAYER M2  ;
    ANTENNAPARTIALMETALSIDEAREA 9.472 LAYER M2  ;
    ANTENNAPARTIALCUTAREA 0.04 LAYER V2  ;
    ANTENNAPARTIALMETALAREA 36.36 LAYER M3  ;
    ANTENNAPARTIALMETALSIDEAREA 134.976 LAYER M3  ;
    ANTENNAMODEL OXIDE1 ;
    ANTENNAGATEAREA 2.266 LAYER M3  ;
    ANTENNAMAXAREACAR 34.4243 LAYER M3  ;
    ANTENNAMAXSIDEAREACAR 129.561 LAYER M3  ;
    ANTENNAMAXCUTCAR 1.28205 LAYER VL  ;
    PORT
      LAYER M2 ;
        RECT 81.900000 563.400000 82.100000 564.000000 ;
    END
  END crash_dump_o[135]
  PIN crash_dump_o[134]
    DIRECTION OUTPUT ;
    USE SIGNAL ;
    ANTENNAPARTIALMETALAREA 1.08 LAYER M2  ;
    ANTENNAPARTIALMETALSIDEAREA 3.996 LAYER M2  ;
    ANTENNAPARTIALCUTAREA 0.04 LAYER V2  ;
    ANTENNAPARTIALMETALAREA 30.84 LAYER M3  ;
    ANTENNAPARTIALMETALSIDEAREA 114.552 LAYER M3  ;
    ANTENNAMODEL OXIDE1 ;
    ANTENNAGATEAREA 2.362 LAYER M3  ;
    ANTENNAMAXAREACAR 22.3907 LAYER M3  ;
    ANTENNAMAXSIDEAREACAR 82.9737 LAYER M3  ;
    ANTENNAMAXCUTCAR 0.900901 LAYER VL  ;
    PORT
      LAYER M2 ;
        RECT 84.900000 563.400000 85.100000 564.000000 ;
    END
  END crash_dump_o[134]
  PIN crash_dump_o[133]
    DIRECTION OUTPUT ;
    USE SIGNAL ;
    ANTENNAPARTIALMETALAREA 1.94 LAYER M2  ;
    ANTENNAPARTIALMETALSIDEAREA 6.808 LAYER M2  ;
    ANTENNAPARTIALCUTAREA 0.04 LAYER V2  ;
    ANTENNAPARTIALMETALAREA 33.2 LAYER M3  ;
    ANTENNAPARTIALMETALSIDEAREA 123.432 LAYER M3  ;
    ANTENNAMODEL OXIDE1 ;
    ANTENNAGATEAREA 2.266 LAYER M3  ;
    ANTENNAMAXAREACAR 53.6801 LAYER M3  ;
    ANTENNAMAXSIDEAREACAR 198.082 LAYER M3  ;
    ANTENNAMAXCUTCAR 1.5873 LAYER VL  ;
    PORT
      LAYER M2 ;
        RECT 87.900000 563.400000 88.100000 564.000000 ;
    END
  END crash_dump_o[133]
  PIN crash_dump_o[132]
    DIRECTION OUTPUT ;
    USE SIGNAL ;
    ANTENNAPARTIALMETALAREA 1.24 LAYER M2  ;
    ANTENNAPARTIALMETALSIDEAREA 4.588 LAYER M2  ;
    ANTENNAPARTIALCUTAREA 0.04 LAYER V2  ;
    ANTENNAPARTIALMETALAREA 22.92 LAYER M3  ;
    ANTENNAPARTIALMETALSIDEAREA 85.248 LAYER M3  ;
    ANTENNAMODEL OXIDE1 ;
    ANTENNAGATEAREA 3.7792 LAYER M3  ;
    ANTENNAMAXAREACAR 10.1083 LAYER M3  ;
    ANTENNAMAXSIDEAREACAR 38.4557 LAYER M3  ;
    ANTENNAMAXCUTCAR 0.724638 LAYER VL  ;
    PORT
      LAYER M2 ;
        RECT 90.900000 563.400000 91.100000 564.000000 ;
    END
  END crash_dump_o[132]
  PIN crash_dump_o[131]
    DIRECTION OUTPUT ;
    USE SIGNAL ;
    ANTENNAPARTIALMETALAREA 0.66 LAYER M2  ;
    ANTENNAPARTIALMETALSIDEAREA 2.072 LAYER M2  ;
    ANTENNAPARTIALCUTAREA 0.04 LAYER V2  ;
    ANTENNAPARTIALMETALAREA 20.92 LAYER M3  ;
    ANTENNAPARTIALMETALSIDEAREA 77.848 LAYER M3  ;
    ANTENNAMODEL OXIDE1 ;
    ANTENNAGATEAREA 2.278 LAYER M3  ;
    ANTENNAMAXAREACAR 12.1396 LAYER M3  ;
    ANTENNAMAXSIDEAREACAR 44.3132 LAYER M3  ;
    ANTENNAMAXCUTCAR 0.30303 LAYER VL  ;
    PORT
      LAYER M2 ;
        RECT 93.900000 563.400000 94.100000 564.000000 ;
    END
  END crash_dump_o[131]
  PIN crash_dump_o[130]
    DIRECTION OUTPUT ;
    USE SIGNAL ;
    ANTENNAPARTIALMETALAREA 0.6 LAYER M2  ;
    ANTENNAPARTIALMETALSIDEAREA 2.22 LAYER M2  ;
    ANTENNAPARTIALCUTAREA 0.04 LAYER V2  ;
    ANTENNAPARTIALMETALAREA 27.2 LAYER M3  ;
    ANTENNAPARTIALMETALSIDEAREA 101.528 LAYER M3  ;
    ANTENNAMODEL OXIDE1 ;
    ANTENNAGATEAREA 4.3984 LAYER M3  ;
    ANTENNAMAXAREACAR 43.5958 LAYER M3  ;
    ANTENNAMAXSIDEAREACAR 161.171 LAYER M3  ;
    ANTENNAMAXCUTCAR 0.735294 LAYER VL  ;
    PORT
      LAYER M2 ;
        RECT 96.900000 563.400000 97.100000 564.000000 ;
    END
  END crash_dump_o[130]
  PIN crash_dump_o[129]
    DIRECTION OUTPUT ;
    USE SIGNAL ;
    ANTENNAPARTIALMETALAREA 2.5 LAYER M2  ;
    ANTENNAPARTIALMETALSIDEAREA 8.88 LAYER M2  ;
    ANTENNAPARTIALCUTAREA 0.04 LAYER V2  ;
    ANTENNAPARTIALMETALAREA 18.64 LAYER M3  ;
    ANTENNAPARTIALMETALSIDEAREA 69.56 LAYER M3  ;
    ANTENNAMODEL OXIDE1 ;
    ANTENNAGATEAREA 2.7004 LAYER M3  ;
    ANTENNAMAXAREACAR 16.7216 LAYER M3  ;
    ANTENNAMAXSIDEAREACAR 61.7664 LAYER M3  ;
    ANTENNAMAXCUTCAR 0.537634 LAYER VL  ;
    PORT
      LAYER M2 ;
        RECT 99.900000 563.400000 100.100000 564.000000 ;
    END
  END crash_dump_o[129]
  PIN crash_dump_o[128]
    DIRECTION OUTPUT ;
    USE SIGNAL ;
    PORT
      LAYER M2 ;
        RECT 102.900000 563.400000 103.100000 564.000000 ;
    END
  END crash_dump_o[128]
  PIN crash_dump_o[127]
    DIRECTION OUTPUT ;
    USE SIGNAL ;
    ANTENNAPARTIALMETALAREA 2.9 LAYER M2  ;
    ANTENNAPARTIALMETALSIDEAREA 10.36 LAYER M2  ;
    ANTENNAPARTIALCUTAREA 0.04 LAYER V2  ;
    ANTENNAPARTIALMETALAREA 34.8 LAYER M3  ;
    ANTENNAPARTIALMETALSIDEAREA 129.648 LAYER M3  ;
    ANTENNAMODEL OXIDE1 ;
    ANTENNAGATEAREA 4.1784 LAYER M3  ;
    ANTENNAMAXAREACAR 74.5848 LAYER M3  ;
    ANTENNAMAXSIDEAREACAR 277.189 LAYER M3  ;
    ANTENNAMAXCUTCAR 1.38889 LAYER VL  ;
    PORT
      LAYER M2 ;
        RECT 105.900000 563.400000 106.100000 564.000000 ;
    END
  END crash_dump_o[127]
  PIN crash_dump_o[126]
    DIRECTION OUTPUT ;
    USE SIGNAL ;
    ANTENNAPARTIALMETALAREA 4.68 LAYER M2  ;
    ANTENNAPARTIALMETALSIDEAREA 17.316 LAYER M2  ;
    ANTENNAPARTIALCUTAREA 0.04 LAYER V2  ;
    ANTENNAPARTIALMETALAREA 3.32 LAYER M3  ;
    ANTENNAPARTIALMETALSIDEAREA 12.728 LAYER M3  ;
    ANTENNAMODEL OXIDE1 ;
    ANTENNAGATEAREA 2.1604 LAYER M3  ;
    ANTENNAMAXAREACAR 168.481 LAYER M3  ;
    ANTENNAMAXSIDEAREACAR 626.391 LAYER M3  ;
    ANTENNAMAXCUTCAR 2.08333 LAYER VL  ;
    PORT
      LAYER M2 ;
        RECT 108.900000 563.400000 109.100000 564.000000 ;
    END
  END crash_dump_o[126]
  PIN crash_dump_o[125]
    DIRECTION OUTPUT ;
    USE SIGNAL ;
    ANTENNAPARTIALMETALAREA 4.34 LAYER M2  ;
    ANTENNAPARTIALMETALSIDEAREA 15.688 LAYER M2  ;
    ANTENNAPARTIALCUTAREA 0.08 LAYER V2  ;
    ANTENNAPARTIALMETALAREA 21.72 LAYER M3  ;
    ANTENNAPARTIALMETALSIDEAREA 81.104 LAYER M3  ;
    ANTENNAMODEL OXIDE1 ;
    ANTENNAGATEAREA 4.1872 LAYER M3  ;
    ANTENNAMAXAREACAR 11.0206 LAYER M3  ;
    ANTENNAMAXSIDEAREACAR 43.7584 LAYER M3  ;
    ANTENNAMAXCUTCAR 1.38889 LAYER VL  ;
    PORT
      LAYER M2 ;
        RECT 111.900000 563.400000 112.100000 564.000000 ;
    END
  END crash_dump_o[125]
  PIN crash_dump_o[124]
    DIRECTION OUTPUT ;
    USE SIGNAL ;
    ANTENNAPARTIALMETALAREA 3.08 LAYER M2  ;
    ANTENNAPARTIALMETALSIDEAREA 11.396 LAYER M2  ;
    ANTENNAPARTIALCUTAREA 0.04 LAYER V2  ;
    ANTENNAPARTIALMETALAREA 7.32 LAYER M3  ;
    ANTENNAPARTIALMETALSIDEAREA 27.824 LAYER M3  ;
    ANTENNAMODEL OXIDE1 ;
    ANTENNAGATEAREA 3.1648 LAYER M3  ;
    ANTENNAMAXAREACAR 6.75739 LAYER M3  ;
    ANTENNAMAXSIDEAREACAR 28.0417 LAYER M3  ;
    ANTENNAMAXCUTCAR 1.38889 LAYER VL  ;
    PORT
      LAYER M2 ;
        RECT 114.900000 563.400000 115.100000 564.000000 ;
    END
  END crash_dump_o[124]
  PIN crash_dump_o[123]
    DIRECTION OUTPUT ;
    USE SIGNAL ;
    ANTENNAPARTIALMETALAREA 3.94 LAYER M2  ;
    ANTENNAPARTIALMETALSIDEAREA 14.208 LAYER M2  ;
    ANTENNAPARTIALCUTAREA 0.04 LAYER V2  ;
    ANTENNAPARTIALMETALAREA 9.92 LAYER M3  ;
    ANTENNAPARTIALMETALSIDEAREA 37.296 LAYER M3  ;
    ANTENNAMODEL OXIDE1 ;
    ANTENNAGATEAREA 2.6812 LAYER M3  ;
    ANTENNAMAXAREACAR 185.922 LAYER M3  ;
    ANTENNAMAXSIDEAREACAR 690.938 LAYER M3  ;
    ANTENNAMAXCUTCAR 2.08333 LAYER VL  ;
    PORT
      LAYER M2 ;
        RECT 117.900000 563.400000 118.100000 564.000000 ;
    END
  END crash_dump_o[123]
  PIN crash_dump_o[122]
    DIRECTION OUTPUT ;
    USE SIGNAL ;
    ANTENNAPARTIALMETALAREA 5.48 LAYER M2  ;
    ANTENNAPARTIALMETALSIDEAREA 20.276 LAYER M2  ;
    ANTENNAPARTIALCUTAREA 0.08 LAYER V2  ;
    ANTENNAPARTIALMETALAREA 14.24 LAYER M3  ;
    ANTENNAPARTIALMETALSIDEAREA 53.576 LAYER M3  ;
    ANTENNAMODEL OXIDE1 ;
    ANTENNAGATEAREA 3.4 LAYER M3  ;
    ANTENNAMAXAREACAR 11.4105 LAYER M3  ;
    ANTENNAMAXSIDEAREACAR 45.2854 LAYER M3  ;
    ANTENNAMAXCUTCAR 1.38889 LAYER VL  ;
    PORT
      LAYER M2 ;
        RECT 120.900000 563.400000 121.100000 564.000000 ;
    END
  END crash_dump_o[122]
  PIN crash_dump_o[121]
    DIRECTION OUTPUT ;
    USE SIGNAL ;
    ANTENNAPARTIALMETALAREA 0.26 LAYER M2  ;
    ANTENNAPARTIALMETALSIDEAREA 0.592 LAYER M2  ;
    ANTENNAPARTIALCUTAREA 0.04 LAYER V2  ;
    ANTENNAPARTIALMETALAREA 13.6 LAYER M3  ;
    ANTENNAPARTIALMETALSIDEAREA 51.208 LAYER M3  ;
    ANTENNAMODEL OXIDE1 ;
    ANTENNAGATEAREA 2.6812 LAYER M3  ;
    ANTENNAMAXAREACAR 8.21124 LAYER M3  ;
    ANTENNAMAXSIDEAREACAR 32.6197 LAYER M3  ;
    ANTENNAMAXCUTCAR 1.38889 LAYER VL  ;
    PORT
      LAYER M2 ;
        RECT 123.900000 563.400000 124.100000 564.000000 ;
    END
  END crash_dump_o[121]
  PIN crash_dump_o[120]
    DIRECTION OUTPUT ;
    USE SIGNAL ;
    ANTENNAPARTIALMETALAREA 0.02 LAYER M2  ;
    ANTENNAPARTIALMETALSIDEAREA 0.074 LAYER M2  ;
    ANTENNAPARTIALCUTAREA 0.04 LAYER V2  ;
    ANTENNAPARTIALMETALAREA 8.92 LAYER M3  ;
    ANTENNAPARTIALMETALSIDEAREA 33.744 LAYER M3  ;
    ANTENNAMODEL OXIDE1 ;
    ANTENNAGATEAREA 3.4 LAYER M3  ;
    ANTENNAMAXAREACAR 8.79717 LAYER M3  ;
    ANTENNAMAXSIDEAREACAR 31.7619 LAYER M3  ;
    ANTENNAMAXCUTCAR 1.38889 LAYER VL  ;
    PORT
      LAYER M2 ;
        RECT 126.900000 563.400000 127.100000 564.000000 ;
    END
  END crash_dump_o[120]
  PIN crash_dump_o[119]
    DIRECTION OUTPUT ;
    USE SIGNAL ;
    ANTENNAPARTIALMETALAREA 0.26 LAYER M2  ;
    ANTENNAPARTIALMETALSIDEAREA 0.592 LAYER M2  ;
    ANTENNAPARTIALCUTAREA 0.04 LAYER V2  ;
    ANTENNAPARTIALMETALAREA 20.28 LAYER M3  ;
    ANTENNAPARTIALMETALSIDEAREA 75.776 LAYER M3  ;
    ANTENNAMODEL OXIDE1 ;
    ANTENNAGATEAREA 2.6812 LAYER M3  ;
    ANTENNAMAXAREACAR 13.3971 LAYER M3  ;
    ANTENNAMAXSIDEAREACAR 52.6509 LAYER M3  ;
    ANTENNAMAXCUTCAR 1.38889 LAYER VL  ;
    PORT
      LAYER M2 ;
        RECT 129.900000 563.400000 130.100000 564.000000 ;
    END
  END crash_dump_o[119]
  PIN crash_dump_o[118]
    DIRECTION OUTPUT ;
    USE SIGNAL ;
    ANTENNAPARTIALMETALAREA 2.84 LAYER M2  ;
    ANTENNAPARTIALMETALSIDEAREA 10.508 LAYER M2  ;
    ANTENNAPARTIALCUTAREA 0.08 LAYER V2  ;
    ANTENNAPARTIALMETALAREA 2.8 LAYER M3  ;
    ANTENNAPARTIALMETALSIDEAREA 10.656 LAYER M3  ;
    ANTENNAMODEL OXIDE1 ;
    ANTENNAGATEAREA 3.0784 LAYER M3  ;
    ANTENNAMAXAREACAR 6.62137 LAYER M3  ;
    ANTENNAMAXSIDEAREACAR 27.9685 LAYER M3  ;
    ANTENNAMAXCUTCAR 1.38889 LAYER VL  ;
    PORT
      LAYER M2 ;
        RECT 132.900000 563.400000 133.100000 564.000000 ;
    END
  END crash_dump_o[118]
  PIN crash_dump_o[117]
    DIRECTION OUTPUT ;
    USE SIGNAL ;
    ANTENNAPARTIALMETALAREA 8.22 LAYER M2  ;
    ANTENNAPARTIALMETALSIDEAREA 30.044 LAYER M2  ;
    ANTENNAPARTIALCUTAREA 0.12 LAYER V2  ;
    ANTENNAPARTIALMETALAREA 12.88 LAYER M3  ;
    ANTENNAPARTIALMETALSIDEAREA 48.544 LAYER M3  ;
    ANTENNAMODEL OXIDE1 ;
    ANTENNAGATEAREA 4.1872 LAYER M3  ;
    ANTENNAMAXAREACAR 66.4001 LAYER M3  ;
    ANTENNAMAXSIDEAREACAR 245.989 LAYER M3  ;
    ANTENNAMAXCUTCAR 1.38889 LAYER VL  ;
    PORT
      LAYER M2 ;
        RECT 135.900000 563.400000 136.100000 564.000000 ;
    END
  END crash_dump_o[117]
  PIN crash_dump_o[116]
    DIRECTION OUTPUT ;
    USE SIGNAL ;
    ANTENNAPARTIALMETALAREA 2.76 LAYER M2  ;
    ANTENNAPARTIALMETALSIDEAREA 10.212 LAYER M2  ;
    ANTENNAPARTIALCUTAREA 0.04 LAYER V2  ;
    ANTENNAPARTIALMETALAREA 18.16 LAYER M3  ;
    ANTENNAPARTIALMETALSIDEAREA 67.784 LAYER M3  ;
    ANTENNAMODEL OXIDE1 ;
    ANTENNAGATEAREA 3.3376 LAYER M3  ;
    ANTENNAMAXAREACAR 170.875 LAYER M3  ;
    ANTENNAMAXSIDEAREACAR 635.788 LAYER M3  ;
    ANTENNAMAXCUTCAR 2.08333 LAYER VL  ;
    PORT
      LAYER M2 ;
        RECT 138.900000 563.400000 139.100000 564.000000 ;
    END
  END crash_dump_o[116]
  PIN crash_dump_o[115]
    DIRECTION OUTPUT ;
    USE SIGNAL ;
    ANTENNAPARTIALMETALAREA 6.42 LAYER M2  ;
    ANTENNAPARTIALMETALSIDEAREA 23.384 LAYER M2  ;
    ANTENNAPARTIALCUTAREA 0.08 LAYER V2  ;
    ANTENNAPARTIALMETALAREA 10.16 LAYER M3  ;
    ANTENNAPARTIALMETALSIDEAREA 38.48 LAYER M3  ;
    ANTENNAMODEL OXIDE1 ;
    ANTENNAGATEAREA 2.6812 LAYER M3  ;
    ANTENNAMAXAREACAR 9.50115 LAYER M3  ;
    ANTENNAMAXSIDEAREACAR 38.8587 LAYER M3  ;
    ANTENNAMAXCUTCAR 1.38889 LAYER VL  ;
    PORT
      LAYER M2 ;
        RECT 141.900000 563.400000 142.100000 564.000000 ;
    END
  END crash_dump_o[115]
  PIN crash_dump_o[114]
    DIRECTION OUTPUT ;
    USE SIGNAL ;
    ANTENNAPARTIALMETALAREA 1.64 LAYER M2  ;
    ANTENNAPARTIALMETALSIDEAREA 6.068 LAYER M2  ;
    ANTENNAPARTIALCUTAREA 0.04 LAYER V2  ;
    ANTENNAPARTIALMETALAREA 11.44 LAYER M3  ;
    ANTENNAPARTIALMETALSIDEAREA 42.92 LAYER M3  ;
    ANTENNAMODEL OXIDE1 ;
    ANTENNAGATEAREA 3.0784 LAYER M3  ;
    ANTENNAMAXAREACAR 6.63288 LAYER M3  ;
    ANTENNAMAXSIDEAREACAR 27.5812 LAYER M3  ;
    ANTENNAMAXCUTCAR 1.38889 LAYER VL  ;
    PORT
      LAYER M2 ;
        RECT 144.900000 563.400000 145.100000 564.000000 ;
    END
  END crash_dump_o[114]
  PIN crash_dump_o[113]
    DIRECTION OUTPUT ;
    USE SIGNAL ;
    ANTENNAPARTIALMETALAREA 6.94 LAYER M2  ;
    ANTENNAPARTIALMETALSIDEAREA 25.308 LAYER M2  ;
    ANTENNAPARTIALCUTAREA 0.12 LAYER V2  ;
    ANTENNAPARTIALMETALAREA 25.6 LAYER M3  ;
    ANTENNAPARTIALMETALSIDEAREA 95.608 LAYER M3  ;
    ANTENNAMODEL OXIDE1 ;
    ANTENNAGATEAREA 4.1872 LAYER M3  ;
    ANTENNAMAXAREACAR 9.03054 LAYER M3  ;
    ANTENNAMAXSIDEAREACAR 36.4723 LAYER M3  ;
    ANTENNAMAXCUTCAR 1.38889 LAYER VL  ;
    PORT
      LAYER M2 ;
        RECT 147.900000 563.400000 148.100000 564.000000 ;
    END
  END crash_dump_o[113]
  PIN crash_dump_o[112]
    DIRECTION OUTPUT ;
    USE SIGNAL ;
    ANTENNAPARTIALMETALAREA 4.76 LAYER M2  ;
    ANTENNAPARTIALMETALSIDEAREA 17.612 LAYER M2  ;
    ANTENNAPARTIALCUTAREA 0.08 LAYER V2  ;
    ANTENNAPARTIALMETALAREA 8.12 LAYER M3  ;
    ANTENNAPARTIALMETALSIDEAREA 30.784 LAYER M3  ;
    ANTENNAMODEL OXIDE1 ;
    ANTENNAGATEAREA 3.3376 LAYER M3  ;
    ANTENNAMAXAREACAR 201.2 LAYER M3  ;
    ANTENNAMAXSIDEAREACAR 748.036 LAYER M3  ;
    ANTENNAMAXCUTCAR 2.08333 LAYER VL  ;
    PORT
      LAYER M2 ;
        RECT 150.900000 563.400000 151.100000 564.000000 ;
    END
  END crash_dump_o[112]
  PIN crash_dump_o[111]
    DIRECTION OUTPUT ;
    USE SIGNAL ;
    ANTENNAPARTIALMETALAREA 3.7 LAYER M2  ;
    ANTENNAPARTIALMETALSIDEAREA 13.32 LAYER M2  ;
    ANTENNAPARTIALCUTAREA 0.04 LAYER V2  ;
    ANTENNAPARTIALMETALAREA 22.08 LAYER M3  ;
    ANTENNAPARTIALMETALSIDEAREA 82.584 LAYER M3  ;
    ANTENNAMODEL OXIDE1 ;
    ANTENNAGATEAREA 4.1872 LAYER M3  ;
    ANTENNAMAXAREACAR 77.8565 LAYER M3  ;
    ANTENNAMAXSIDEAREACAR 288.378 LAYER M3  ;
    ANTENNAMAXCUTCAR 1.38889 LAYER VL  ;
    PORT
      LAYER M2 ;
        RECT 153.900000 563.400000 154.100000 564.000000 ;
    END
  END crash_dump_o[111]
  PIN crash_dump_o[110]
    DIRECTION OUTPUT ;
    USE SIGNAL ;
    ANTENNAPARTIALMETALAREA 2.12 LAYER M2  ;
    ANTENNAPARTIALMETALSIDEAREA 7.844 LAYER M2  ;
    ANTENNAPARTIALCUTAREA 0.04 LAYER V2  ;
    ANTENNAPARTIALMETALAREA 2.8 LAYER M3  ;
    ANTENNAPARTIALMETALSIDEAREA 10.952 LAYER M3  ;
    ANTENNAMODEL OXIDE1 ;
    ANTENNAGATEAREA 2.2708 LAYER M3  ;
    ANTENNAMAXAREACAR 170.963 LAYER M3  ;
    ANTENNAMAXSIDEAREACAR 634.818 LAYER M3  ;
    ANTENNAMAXCUTCAR 1.38889 LAYER VL  ;
    PORT
      LAYER M2 ;
        RECT 156.900000 563.400000 157.100000 564.000000 ;
    END
  END crash_dump_o[110]
  PIN crash_dump_o[109]
    DIRECTION OUTPUT ;
    USE SIGNAL ;
    ANTENNAPARTIALMETALAREA 4.42 LAYER M2  ;
    ANTENNAPARTIALMETALSIDEAREA 15.984 LAYER M2  ;
    ANTENNAPARTIALCUTAREA 0.08 LAYER V2  ;
    ANTENNAPARTIALMETALAREA 15.92 LAYER M3  ;
    ANTENNAPARTIALMETALSIDEAREA 59.496 LAYER M3  ;
    ANTENNAMODEL OXIDE1 ;
    ANTENNAGATEAREA 4.1872 LAYER M3  ;
    ANTENNAMAXAREACAR 90.2743 LAYER M3  ;
    ANTENNAMAXSIDEAREACAR 334.253 LAYER M3  ;
    ANTENNAMAXCUTCAR 1.38889 LAYER VL  ;
    PORT
      LAYER M2 ;
        RECT 159.900000 563.400000 160.100000 564.000000 ;
    END
  END crash_dump_o[109]
  PIN crash_dump_o[108]
    DIRECTION OUTPUT ;
    USE SIGNAL ;
    ANTENNAPARTIALMETALAREA 0.02 LAYER M2  ;
    ANTENNAPARTIALMETALSIDEAREA 0.074 LAYER M2  ;
    ANTENNAPARTIALCUTAREA 0.04 LAYER V2  ;
    ANTENNAPARTIALMETALAREA 17.88 LAYER M3  ;
    ANTENNAPARTIALMETALSIDEAREA 66.896 LAYER M3  ;
    ANTENNAMODEL OXIDE1 ;
    ANTENNAGATEAREA 3.2512 LAYER M3  ;
    ANTENNAMAXAREACAR 8.41617 LAYER M3  ;
    ANTENNAMAXSIDEAREACAR 34.2147 LAYER M3  ;
    ANTENNAMAXCUTCAR 1.38889 LAYER VL  ;
    PORT
      LAYER M2 ;
        RECT 162.900000 563.400000 163.100000 564.000000 ;
    END
  END crash_dump_o[108]
  PIN crash_dump_o[107]
    DIRECTION OUTPUT ;
    USE SIGNAL ;
    ANTENNAPARTIALMETALAREA 0.1 LAYER M2  ;
    ANTENNAPARTIALMETALSIDEAREA 0.222 LAYER M2  ;
    ANTENNAPARTIALCUTAREA 0.04 LAYER V2  ;
    ANTENNAPARTIALMETALAREA 26.56 LAYER M3  ;
    ANTENNAPARTIALMETALSIDEAREA 98.864 LAYER M3  ;
    ANTENNAMODEL OXIDE1 ;
    ANTENNAGATEAREA 4.1872 LAYER M3  ;
    ANTENNAMAXAREACAR 63.5654 LAYER M3  ;
    ANTENNAMAXSIDEAREACAR 238.139 LAYER M3  ;
    ANTENNAMAXCUTCAR 2.08333 LAYER VL  ;
    PORT
      LAYER M2 ;
        RECT 165.900000 563.400000 166.100000 564.000000 ;
    END
  END crash_dump_o[107]
  PIN crash_dump_o[106]
    DIRECTION OUTPUT ;
    USE SIGNAL ;
    ANTENNAPARTIALMETALAREA 8.52 LAYER M2  ;
    ANTENNAPARTIALMETALSIDEAREA 31.524 LAYER M2  ;
    ANTENNAPARTIALCUTAREA 0.04 LAYER V2  ;
    ANTENNAPARTIALMETALAREA 21.12 LAYER M3  ;
    ANTENNAPARTIALMETALSIDEAREA 78.736 LAYER M3  ;
    ANTENNAMODEL OXIDE1 ;
    ANTENNAGATEAREA 3.2512 LAYER M3  ;
    ANTENNAMAXAREACAR 58.6581 LAYER M3  ;
    ANTENNAMAXSIDEAREACAR 217.345 LAYER M3  ;
    ANTENNAMAXCUTCAR 1.38889 LAYER VL  ;
    PORT
      LAYER M2 ;
        RECT 168.900000 563.400000 169.100000 564.000000 ;
    END
  END crash_dump_o[106]
  PIN crash_dump_o[105]
    DIRECTION OUTPUT ;
    USE SIGNAL ;
    ANTENNAPARTIALMETALAREA 0.26 LAYER M2  ;
    ANTENNAPARTIALMETALSIDEAREA 0.592 LAYER M2  ;
    ANTENNAPARTIALCUTAREA 0.04 LAYER V2  ;
    ANTENNAPARTIALMETALAREA 19.28 LAYER M3  ;
    ANTENNAPARTIALMETALSIDEAREA 71.928 LAYER M3  ;
    ANTENNAMODEL OXIDE1 ;
    ANTENNAGATEAREA 4.1872 LAYER M3  ;
    ANTENNAMAXAREACAR 149.205 LAYER M3  ;
    ANTENNAMAXSIDEAREACAR 555.574 LAYER M3  ;
    ANTENNAMAXCUTCAR 2.08333 LAYER VL  ;
    PORT
      LAYER M2 ;
        RECT 171.900000 563.400000 172.100000 564.000000 ;
    END
  END crash_dump_o[105]
  PIN crash_dump_o[104]
    DIRECTION OUTPUT ;
    USE SIGNAL ;
    ANTENNAPARTIALMETALAREA 0.76 LAYER M2  ;
    ANTENNAPARTIALMETALSIDEAREA 2.812 LAYER M2  ;
    ANTENNAPARTIALCUTAREA 0.04 LAYER V2  ;
    ANTENNAPARTIALMETALAREA 6.04 LAYER M3  ;
    ANTENNAPARTIALMETALSIDEAREA 22.792 LAYER M3  ;
    ANTENNAMODEL OXIDE1 ;
    ANTENNAGATEAREA 2.4196 LAYER M3  ;
    ANTENNAMAXAREACAR 165.153 LAYER M3  ;
    ANTENNAMAXSIDEAREACAR 614.621 LAYER M3  ;
    ANTENNAMAXCUTCAR 2.08333 LAYER VL  ;
    PORT
      LAYER M2 ;
        RECT 174.900000 563.400000 175.100000 564.000000 ;
    END
  END crash_dump_o[104]
  PIN crash_dump_o[103]
    DIRECTION OUTPUT ;
    USE SIGNAL ;
    ANTENNAPARTIALMETALAREA 0.1 LAYER M2  ;
    ANTENNAPARTIALMETALSIDEAREA 0.222 LAYER M2  ;
    ANTENNAPARTIALCUTAREA 0.04 LAYER V2  ;
    ANTENNAPARTIALMETALAREA 0.56 LAYER M3  ;
    ANTENNAPARTIALMETALSIDEAREA 2.368 LAYER M3  ;
    ANTENNAMODEL OXIDE1 ;
    ANTENNAGATEAREA 3.5776 LAYER M3  ;
    ANTENNAMAXAREACAR 2.88222 LAYER M3  ;
    ANTENNAMAXSIDEAREACAR 14.1827 LAYER M3  ;
    ANTENNAMAXCUTCAR 1.38889 LAYER VL  ;
    PORT
      LAYER M2 ;
        RECT 177.900000 563.400000 178.100000 564.000000 ;
    END
  END crash_dump_o[103]
  PIN crash_dump_o[102]
    DIRECTION OUTPUT ;
    USE SIGNAL ;
    ANTENNAPARTIALMETALAREA 0.02 LAYER M2  ;
    ANTENNAPARTIALMETALSIDEAREA 0.074 LAYER M2  ;
    ANTENNAPARTIALCUTAREA 0.04 LAYER V2  ;
    ANTENNAPARTIALMETALAREA 11.44 LAYER M3  ;
    ANTENNAPARTIALMETALSIDEAREA 43.216 LAYER M3  ;
    ANTENNAMODEL OXIDE1 ;
    ANTENNAGATEAREA 2.566 LAYER M3  ;
    ANTENNAMAXAREACAR 7.77714 LAYER M3  ;
    ANTENNAMAXSIDEAREACAR 30.3626 LAYER M3  ;
    ANTENNAMAXCUTCAR 1.38889 LAYER VL  ;
    PORT
      LAYER M2 ;
        RECT 180.900000 563.400000 181.100000 564.000000 ;
    END
  END crash_dump_o[102]
  PIN crash_dump_o[101]
    DIRECTION OUTPUT ;
    USE SIGNAL ;
    ANTENNAPARTIALMETALAREA 0.18 LAYER M2  ;
    ANTENNAPARTIALMETALSIDEAREA 0.296 LAYER M2  ;
    ANTENNAPARTIALCUTAREA 0.04 LAYER V2  ;
    ANTENNAPARTIALMETALAREA 3.64 LAYER M3  ;
    ANTENNAPARTIALMETALSIDEAREA 13.912 LAYER M3  ;
    ANTENNAMODEL OXIDE1 ;
    ANTENNAGATEAREA 3.5776 LAYER M3  ;
    ANTENNAMAXAREACAR 3.74314 LAYER M3  ;
    ANTENNAMAXSIDEAREACAR 17.4095 LAYER M3  ;
    ANTENNAMAXCUTCAR 1.38889 LAYER VL  ;
    PORT
      LAYER M2 ;
        RECT 183.900000 563.400000 184.100000 564.000000 ;
    END
  END crash_dump_o[101]
  PIN crash_dump_o[100]
    DIRECTION OUTPUT ;
    USE SIGNAL ;
    ANTENNAPARTIALMETALAREA 22.48 LAYER M2  ;
    ANTENNAPARTIALMETALSIDEAREA 83.62 LAYER M2  ;
    ANTENNAMODEL OXIDE1 ;
    ANTENNAGATEAREA 2.2708 LAYER M2  ;
    ANTENNAMAXAREACAR 56.8058 LAYER M2  ;
    ANTENNAMAXSIDEAREACAR 235.275 LAYER M2  ;
    ANTENNAMAXCUTCAR 1.38889 LAYER V2  ;
    PORT
      LAYER M2 ;
        RECT 186.900000 563.400000 187.100000 564.000000 ;
    END
  END crash_dump_o[100]
  PIN crash_dump_o[99]
    DIRECTION OUTPUT ;
    USE SIGNAL ;
    ANTENNAPARTIALMETALAREA 0.1 LAYER M2  ;
    ANTENNAPARTIALMETALSIDEAREA 0.222 LAYER M2  ;
    ANTENNAPARTIALCUTAREA 0.04 LAYER V2  ;
    ANTENNAPARTIALMETALAREA 1.56 LAYER M3  ;
    ANTENNAPARTIALMETALSIDEAREA 6.216 LAYER M3  ;
    ANTENNAMODEL OXIDE1 ;
    ANTENNAGATEAREA 0.0576 LAYER M3  ;
    ANTENNAMAXAREACAR 29.809 LAYER M3  ;
    ANTENNAMAXSIDEAREACAR 121.438 LAYER M3  ;
    ANTENNAMAXCUTCAR 1.38889 LAYER VL  ;
    PORT
      LAYER M2 ;
        RECT 189.900000 563.400000 190.100000 564.000000 ;
    END
  END crash_dump_o[99]
  PIN crash_dump_o[98]
    DIRECTION OUTPUT ;
    USE SIGNAL ;
    ANTENNAPARTIALMETALAREA 7.48 LAYER M2  ;
    ANTENNAPARTIALMETALSIDEAREA 27.676 LAYER M2  ;
    ANTENNAPARTIALCUTAREA 0.04 LAYER V2  ;
    ANTENNAPARTIALMETALAREA 1.52 LAYER M3  ;
    ANTENNAPARTIALMETALSIDEAREA 6.216 LAYER M3  ;
    ANTENNAMODEL OXIDE1 ;
    ANTENNAGATEAREA 3.8368 LAYER M3  ;
    ANTENNAMAXAREACAR 9.00727 LAYER M3  ;
    ANTENNAMAXSIDEAREACAR 36.2868 LAYER M3  ;
    ANTENNAMAXCUTCAR 1.38889 LAYER VL  ;
    PORT
      LAYER M2 ;
        RECT 192.900000 563.400000 193.100000 564.000000 ;
    END
  END crash_dump_o[98]
  PIN crash_dump_o[97]
    DIRECTION OUTPUT ;
    USE SIGNAL ;
    ANTENNAPARTIALMETALAREA 2.82 LAYER M2  ;
    ANTENNAPARTIALMETALSIDEAREA 10.064 LAYER M2  ;
    ANTENNAPARTIALCUTAREA 0.04 LAYER V2  ;
    ANTENNAPARTIALMETALAREA 43.92 LAYER M3  ;
    ANTENNAPARTIALMETALSIDEAREA 163.392 LAYER M3  ;
    ANTENNAMODEL OXIDE1 ;
    ANTENNAGATEAREA 3.3208 LAYER M3  ;
    ANTENNAMAXAREACAR 268.938 LAYER M3  ;
    ANTENNAMAXSIDEAREACAR 998.71 LAYER M3  ;
    ANTENNAMAXCUTCAR 2.08333 LAYER VL  ;
    PORT
      LAYER M2 ;
        RECT 195.900000 563.400000 196.100000 564.000000 ;
    END
  END crash_dump_o[97]
  PIN crash_dump_o[96]
    DIRECTION OUTPUT ;
    USE SIGNAL ;
    PORT
      LAYER M2 ;
        RECT 198.900000 563.400000 199.100000 564.000000 ;
    END
  END crash_dump_o[96]
  PIN crash_dump_o[95]
    DIRECTION OUTPUT ;
    USE SIGNAL ;
    ANTENNAPARTIALMETALAREA 15.94 LAYER M2  ;
    ANTENNAPARTIALMETALSIDEAREA 58.608 LAYER M2  ;
    ANTENNAPARTIALCUTAREA 0.04 LAYER V2  ;
    ANTENNAPARTIALMETALAREA 7 LAYER M3  ;
    ANTENNAPARTIALMETALSIDEAREA 26.344 LAYER M3  ;
    ANTENNAMODEL OXIDE1 ;
    ANTENNAGATEAREA 3.8176 LAYER M3  ;
    ANTENNAMAXAREACAR 6.69748 LAYER M3  ;
    ANTENNAMAXSIDEAREACAR 24.8571 LAYER M3  ;
    ANTENNAMAXCUTCAR 0.641026 LAYER VL  ;
    PORT
      LAYER M2 ;
        RECT 201.900000 563.400000 202.100000 564.000000 ;
    END
  END crash_dump_o[95]
  PIN crash_dump_o[94]
    DIRECTION OUTPUT ;
    USE SIGNAL ;
    ANTENNAPARTIALMETALAREA 15.48 LAYER M2  ;
    ANTENNAPARTIALMETALSIDEAREA 57.276 LAYER M2  ;
    ANTENNAPARTIALCUTAREA 0.04 LAYER V2  ;
    ANTENNAPARTIALMETALAREA 11.84 LAYER M3  ;
    ANTENNAPARTIALMETALSIDEAREA 44.4 LAYER M3  ;
    ANTENNAMODEL OXIDE1 ;
    ANTENNAGATEAREA 3.8176 LAYER M3  ;
    ANTENNAMAXAREACAR 95.0135 LAYER M3  ;
    ANTENNAMAXSIDEAREACAR 352.744 LAYER M3  ;
    ANTENNAMAXCUTCAR 0.694444 LAYER VL  ;
    PORT
      LAYER M2 ;
        RECT 204.900000 563.400000 205.100000 564.000000 ;
    END
  END crash_dump_o[94]
  PIN crash_dump_o[93]
    DIRECTION OUTPUT ;
    USE SIGNAL ;
    ANTENNAPARTIALMETALAREA 2.02 LAYER M2  ;
    ANTENNAPARTIALMETALSIDEAREA 7.104 LAYER M2  ;
    ANTENNAPARTIALCUTAREA 0.04 LAYER V2  ;
    ANTENNAPARTIALMETALAREA 12.64 LAYER M3  ;
    ANTENNAPARTIALMETALSIDEAREA 47.36 LAYER M3  ;
    ANTENNAMODEL OXIDE1 ;
    ANTENNAGATEAREA 3.8872 LAYER M3  ;
    ANTENNAMAXAREACAR 177.108 LAYER M3  ;
    ANTENNAMAXSIDEAREACAR 656.491 LAYER M3  ;
    ANTENNAMAXCUTCAR 0.925926 LAYER VL  ;
    PORT
      LAYER M2 ;
        RECT 207.900000 563.400000 208.100000 564.000000 ;
    END
  END crash_dump_o[93]
  PIN crash_dump_o[92]
    DIRECTION OUTPUT ;
    USE SIGNAL ;
    ANTENNAPARTIALMETALAREA 0.02 LAYER M2  ;
    ANTENNAPARTIALMETALSIDEAREA 0.074 LAYER M2  ;
    ANTENNAPARTIALCUTAREA 0.04 LAYER V2  ;
    ANTENNAPARTIALMETALAREA 11.04 LAYER M3  ;
    ANTENNAPARTIALMETALSIDEAREA 41.736 LAYER M3  ;
    ANTENNAMODEL OXIDE1 ;
    ANTENNAGATEAREA 3.8176 LAYER M3  ;
    ANTENNAMAXAREACAR 79.5261 LAYER M3  ;
    ANTENNAMAXSIDEAREACAR 295.518 LAYER M3  ;
    ANTENNAMAXCUTCAR 0.694444 LAYER VL  ;
    PORT
      LAYER M2 ;
        RECT 210.900000 563.400000 211.100000 564.000000 ;
    END
  END crash_dump_o[92]
  PIN crash_dump_o[91]
    DIRECTION OUTPUT ;
    USE SIGNAL ;
    ANTENNAPARTIALMETALAREA 5.58 LAYER M2  ;
    ANTENNAPARTIALMETALSIDEAREA 20.276 LAYER M2  ;
    ANTENNAPARTIALCUTAREA 0.12 LAYER V2  ;
    ANTENNAPARTIALMETALAREA 16.56 LAYER M3  ;
    ANTENNAPARTIALMETALSIDEAREA 62.16 LAYER M3  ;
    ANTENNAMODEL OXIDE1 ;
    ANTENNAGATEAREA 3.8872 LAYER M3  ;
    ANTENNAMAXAREACAR 53.1166 LAYER M3  ;
    ANTENNAMAXSIDEAREACAR 197.799 LAYER M3  ;
    ANTENNAMAXCUTCAR 0.694444 LAYER VL  ;
    PORT
      LAYER M2 ;
        RECT 213.900000 563.400000 214.100000 564.000000 ;
    END
  END crash_dump_o[91]
  PIN crash_dump_o[90]
    DIRECTION OUTPUT ;
    USE SIGNAL ;
    ANTENNAPARTIALMETALAREA 0.02 LAYER M2  ;
    ANTENNAPARTIALMETALSIDEAREA 0.074 LAYER M2  ;
    ANTENNAPARTIALCUTAREA 0.04 LAYER V2  ;
    ANTENNAPARTIALMETALAREA 12.28 LAYER M3  ;
    ANTENNAPARTIALMETALSIDEAREA 45.584 LAYER M3  ;
    ANTENNAMODEL OXIDE1 ;
    ANTENNAGATEAREA 3.8872 LAYER M3  ;
    ANTENNAMAXAREACAR 26.2079 LAYER M3  ;
    ANTENNAMAXSIDEAREACAR 103.92 LAYER M3  ;
    ANTENNAMAXCUTCAR 0.241772 LAYER VL  ;
    PORT
      LAYER M2 ;
        RECT 216.900000 563.400000 217.100000 564.000000 ;
    END
  END crash_dump_o[90]
  PIN crash_dump_o[89]
    DIRECTION OUTPUT ;
    USE SIGNAL ;
    ANTENNAPARTIALMETALAREA 0.82 LAYER M2  ;
    ANTENNAPARTIALMETALSIDEAREA 2.664 LAYER M2  ;
    ANTENNAPARTIALCUTAREA 0.04 LAYER V2  ;
    ANTENNAPARTIALMETALAREA 16.28 LAYER M3  ;
    ANTENNAPARTIALMETALSIDEAREA 60.976 LAYER M3  ;
    ANTENNAMODEL OXIDE1 ;
    ANTENNAGATEAREA 3.8872 LAYER M3  ;
    ANTENNAMAXAREACAR 6.93708 LAYER M3  ;
    ANTENNAMAXSIDEAREACAR 26.7275 LAYER M3  ;
    ANTENNAMAXCUTCAR 0.462963 LAYER VL  ;
    PORT
      LAYER M2 ;
        RECT 219.900000 563.400000 220.100000 564.000000 ;
    END
  END crash_dump_o[89]
  PIN crash_dump_o[88]
    DIRECTION OUTPUT ;
    USE SIGNAL ;
    ANTENNAPARTIALMETALAREA 0.02 LAYER M2  ;
    ANTENNAPARTIALMETALSIDEAREA 0.074 LAYER M2  ;
    ANTENNAPARTIALCUTAREA 0.04 LAYER V2  ;
    ANTENNAPARTIALMETALAREA 12 LAYER M3  ;
    ANTENNAPARTIALMETALSIDEAREA 44.992 LAYER M3  ;
    ANTENNAMODEL OXIDE1 ;
    ANTENNAGATEAREA 3.8872 LAYER M3  ;
    ANTENNAMAXAREACAR 24.3545 LAYER M3  ;
    ANTENNAMAXSIDEAREACAR 91.1341 LAYER M3  ;
    ANTENNAMAXCUTCAR 0.462963 LAYER VL  ;
    PORT
      LAYER M2 ;
        RECT 222.900000 563.400000 223.100000 564.000000 ;
    END
  END crash_dump_o[88]
  PIN crash_dump_o[87]
    DIRECTION OUTPUT ;
    USE SIGNAL ;
    ANTENNAPARTIALMETALAREA 1.62 LAYER M2  ;
    ANTENNAPARTIALMETALSIDEAREA 5.624 LAYER M2  ;
    ANTENNAPARTIALCUTAREA 0.04 LAYER V2  ;
    ANTENNAPARTIALMETALAREA 12.16 LAYER M3  ;
    ANTENNAPARTIALMETALSIDEAREA 45.88 LAYER M3  ;
    ANTENNAMODEL OXIDE1 ;
    ANTENNAGATEAREA 4.084 LAYER M3  ;
    ANTENNAMAXAREACAR 5.53766 LAYER M3  ;
    ANTENNAMAXSIDEAREACAR 21.7457 LAYER M3  ;
    ANTENNAMAXCUTCAR 0.462963 LAYER VL  ;
    PORT
      LAYER M2 ;
        RECT 225.900000 563.400000 226.100000 564.000000 ;
    END
  END crash_dump_o[87]
  PIN crash_dump_o[86]
    DIRECTION OUTPUT ;
    USE SIGNAL ;
    ANTENNAPARTIALMETALAREA 27.96 LAYER M2  ;
    ANTENNAPARTIALMETALSIDEAREA 103.452 LAYER M2  ;
    ANTENNAPARTIALCUTAREA 0.04 LAYER V2  ;
    ANTENNAPARTIALMETALAREA 11.56 LAYER M3  ;
    ANTENNAPARTIALMETALSIDEAREA 43.216 LAYER M3  ;
    ANTENNAMODEL OXIDE1 ;
    ANTENNAGATEAREA 3.8872 LAYER M3  ;
    ANTENNAMAXAREACAR 26.2748 LAYER M3  ;
    ANTENNAMAXSIDEAREACAR 98.3976 LAYER M3  ;
    ANTENNAMAXCUTCAR 0.925926 LAYER VL  ;
    PORT
      LAYER M2 ;
        RECT 228.900000 563.400000 229.100000 564.000000 ;
    END
  END crash_dump_o[86]
  PIN crash_dump_o[85]
    DIRECTION OUTPUT ;
    USE SIGNAL ;
    ANTENNAPARTIALMETALAREA 1.54 LAYER M2  ;
    ANTENNAPARTIALMETALSIDEAREA 5.328 LAYER M2  ;
    ANTENNAPARTIALCUTAREA 0.04 LAYER V2  ;
    ANTENNAPARTIALMETALAREA 13.16 LAYER M3  ;
    ANTENNAPARTIALMETALSIDEAREA 49.136 LAYER M3  ;
    ANTENNAMODEL OXIDE1 ;
    ANTENNAGATEAREA 3.8872 LAYER M3  ;
    ANTENNAMAXAREACAR 191.131 LAYER M3  ;
    ANTENNAMAXSIDEAREACAR 708.337 LAYER M3  ;
    ANTENNAMAXCUTCAR 0.694444 LAYER VL  ;
    PORT
      LAYER M2 ;
        RECT 231.900000 563.400000 232.100000 564.000000 ;
    END
  END crash_dump_o[85]
  PIN crash_dump_o[84]
    DIRECTION OUTPUT ;
    USE SIGNAL ;
    ANTENNAPARTIALMETALAREA 27.64 LAYER M2  ;
    ANTENNAPARTIALMETALSIDEAREA 102.268 LAYER M2  ;
    ANTENNAPARTIALCUTAREA 0.04 LAYER V2  ;
    ANTENNAPARTIALMETALAREA 8.08 LAYER M3  ;
    ANTENNAPARTIALMETALSIDEAREA 30.488 LAYER M3  ;
    ANTENNAMODEL OXIDE1 ;
    ANTENNAGATEAREA 3.6928 LAYER M3  ;
    ANTENNAMAXAREACAR 3.26675 LAYER M3  ;
    ANTENNAMAXSIDEAREACAR 13.3139 LAYER M3  ;
    ANTENNAMAXCUTCAR 0.462963 LAYER VL  ;
    PORT
      LAYER M2 ;
        RECT 234.900000 563.400000 235.100000 564.000000 ;
    END
  END crash_dump_o[84]
  PIN crash_dump_o[83]
    DIRECTION OUTPUT ;
    USE SIGNAL ;
    ANTENNAPARTIALMETALAREA 28.74 LAYER M2  ;
    ANTENNAPARTIALMETALSIDEAREA 105.968 LAYER M2  ;
    ANTENNAPARTIALCUTAREA 0.04 LAYER V2  ;
    ANTENNAPARTIALMETALAREA 9.76 LAYER M3  ;
    ANTENNAPARTIALMETALSIDEAREA 36.704 LAYER M3  ;
    ANTENNAMODEL OXIDE1 ;
    ANTENNAGATEAREA 3.8872 LAYER M3  ;
    ANTENNAMAXAREACAR 32.3858 LAYER M3  ;
    ANTENNAMAXSIDEAREACAR 121.019 LAYER M3  ;
    ANTENNAMAXCUTCAR 0.694444 LAYER VL  ;
    PORT
      LAYER M2 ;
        RECT 237.900000 563.400000 238.100000 564.000000 ;
    END
  END crash_dump_o[83]
  PIN crash_dump_o[82]
    DIRECTION OUTPUT ;
    USE SIGNAL ;
    ANTENNAPARTIALMETALAREA 27.88 LAYER M2  ;
    ANTENNAPARTIALMETALSIDEAREA 103.156 LAYER M2  ;
    ANTENNAPARTIALCUTAREA 0.04 LAYER V2  ;
    ANTENNAPARTIALMETALAREA 8.52 LAYER M3  ;
    ANTENNAPARTIALMETALSIDEAREA 31.968 LAYER M3  ;
    ANTENNAMODEL OXIDE1 ;
    ANTENNAGATEAREA 3.8872 LAYER M3  ;
    ANTENNAMAXAREACAR 4.31022 LAYER M3  ;
    ANTENNAMAXSIDEAREACAR 16.0208 LAYER M3  ;
    ANTENNAMAXCUTCAR 0.462963 LAYER VL  ;
    PORT
      LAYER M2 ;
        RECT 240.900000 563.400000 241.100000 564.000000 ;
    END
  END crash_dump_o[82]
  PIN crash_dump_o[81]
    DIRECTION OUTPUT ;
    USE SIGNAL ;
    ANTENNAPARTIALMETALAREA 29.46 LAYER M2  ;
    ANTENNAPARTIALMETALSIDEAREA 108.632 LAYER M2  ;
    ANTENNAPARTIALCUTAREA 0.04 LAYER V2  ;
    ANTENNAPARTIALMETALAREA 9.64 LAYER M3  ;
    ANTENNAPARTIALMETALSIDEAREA 36.112 LAYER M3  ;
    ANTENNAMODEL OXIDE1 ;
    ANTENNAGATEAREA 3.8872 LAYER M3  ;
    ANTENNAMAXAREACAR 28.2145 LAYER M3  ;
    ANTENNAMAXSIDEAREACAR 105.074 LAYER M3  ;
    ANTENNAMAXCUTCAR 0.462963 LAYER VL  ;
    PORT
      LAYER M2 ;
        RECT 243.900000 563.400000 244.100000 564.000000 ;
    END
  END crash_dump_o[81]
  PIN crash_dump_o[80]
    DIRECTION OUTPUT ;
    USE SIGNAL ;
    ANTENNAPARTIALMETALAREA 5.24 LAYER M2  ;
    ANTENNAPARTIALMETALSIDEAREA 19.388 LAYER M2  ;
    ANTENNAPARTIALCUTAREA 0.04 LAYER V2  ;
    ANTENNAPARTIALMETALAREA 9.68 LAYER M3  ;
    ANTENNAPARTIALMETALSIDEAREA 36.408 LAYER M3  ;
    ANTENNAMODEL OXIDE1 ;
    ANTENNAGATEAREA 3.6928 LAYER M3  ;
    ANTENNAMAXAREACAR 4.71854 LAYER M3  ;
    ANTENNAMAXSIDEAREACAR 18.6578 LAYER M3  ;
    ANTENNAMAXCUTCAR 0.462963 LAYER VL  ;
    PORT
      LAYER M2 ;
        RECT 246.900000 563.400000 247.100000 564.000000 ;
    END
  END crash_dump_o[80]
  PIN crash_dump_o[79]
    DIRECTION OUTPUT ;
    USE SIGNAL ;
    ANTENNAPARTIALMETALAREA 35.36 LAYER M2  ;
    ANTENNAPARTIALMETALSIDEAREA 131.276 LAYER M2  ;
    ANTENNAMODEL OXIDE1 ;
    ANTENNAGATEAREA 4.084 LAYER M2  ;
    ANTENNAMAXAREACAR 47.2647 LAYER M2  ;
    ANTENNAMAXSIDEAREACAR 195.73 LAYER M2  ;
    ANTENNAMAXCUTCAR 0.462963 LAYER V2  ;
    PORT
      LAYER M2 ;
        RECT 249.900000 563.400000 250.100000 564.000000 ;
    END
  END crash_dump_o[79]
  PIN crash_dump_o[78]
    DIRECTION OUTPUT ;
    USE SIGNAL ;
    ANTENNAPARTIALMETALAREA 0.02 LAYER M2  ;
    ANTENNAPARTIALMETALSIDEAREA 0.074 LAYER M2  ;
    ANTENNAPARTIALCUTAREA 0.04 LAYER V2  ;
    ANTENNAPARTIALMETALAREA 12.88 LAYER M3  ;
    ANTENNAPARTIALMETALSIDEAREA 48.544 LAYER M3  ;
    ANTENNAMODEL OXIDE1 ;
    ANTENNAGATEAREA 3.8176 LAYER M3  ;
    ANTENNAMAXAREACAR 5.96439 LAYER M3  ;
    ANTENNAMAXSIDEAREACAR 22.7992 LAYER M3  ;
    ANTENNAMAXCUTCAR 0.641026 LAYER VL  ;
    PORT
      LAYER M2 ;
        RECT 252.900000 563.400000 253.100000 564.000000 ;
    END
  END crash_dump_o[78]
  PIN crash_dump_o[77]
    DIRECTION OUTPUT ;
    USE SIGNAL ;
    ANTENNAPARTIALMETALAREA 2.74 LAYER M2  ;
    ANTENNAPARTIALMETALSIDEAREA 9.768 LAYER M2  ;
    ANTENNAPARTIALCUTAREA 0.04 LAYER V2  ;
    ANTENNAPARTIALMETALAREA 15.32 LAYER M3  ;
    ANTENNAPARTIALMETALSIDEAREA 57.424 LAYER M3  ;
    ANTENNAMODEL OXIDE1 ;
    ANTENNAGATEAREA 3.8176 LAYER M3  ;
    ANTENNAMAXAREACAR 26.9435 LAYER M3  ;
    ANTENNAMAXSIDEAREACAR 100.924 LAYER M3  ;
    ANTENNAMAXCUTCAR 0.694444 LAYER VL  ;
    PORT
      LAYER M2 ;
        RECT 255.900000 563.400000 256.100000 564.000000 ;
    END
  END crash_dump_o[77]
  PIN crash_dump_o[76]
    DIRECTION OUTPUT ;
    USE SIGNAL ;
    ANTENNAPARTIALMETALAREA 0.02 LAYER M2  ;
    ANTENNAPARTIALMETALSIDEAREA 0.074 LAYER M2  ;
    ANTENNAPARTIALCUTAREA 0.04 LAYER V2  ;
    ANTENNAPARTIALMETALAREA 10.48 LAYER M3  ;
    ANTENNAPARTIALMETALSIDEAREA 39.368 LAYER M3  ;
    ANTENNAMODEL OXIDE1 ;
    ANTENNAGATEAREA 3.8656 LAYER M3  ;
    ANTENNAMAXAREACAR 4.34535 LAYER M3  ;
    ANTENNAMAXSIDEAREACAR 17.2698 LAYER M3  ;
    ANTENNAMAXCUTCAR 0.462963 LAYER VL  ;
    PORT
      LAYER M2 ;
        RECT 258.900000 563.400000 259.100000 564.000000 ;
    END
  END crash_dump_o[76]
  PIN crash_dump_o[75]
    DIRECTION OUTPUT ;
    USE SIGNAL ;
    ANTENNAPARTIALMETALAREA 6.1 LAYER M2  ;
    ANTENNAPARTIALMETALSIDEAREA 22.2 LAYER M2  ;
    ANTENNAPARTIALCUTAREA 0.04 LAYER V2  ;
    ANTENNAPARTIALMETALAREA 10.96 LAYER M3  ;
    ANTENNAPARTIALMETALSIDEAREA 41.144 LAYER M3  ;
    ANTENNAMODEL OXIDE1 ;
    ANTENNAGATEAREA 3.8176 LAYER M3  ;
    ANTENNAMAXAREACAR 10.9393 LAYER M3  ;
    ANTENNAMAXSIDEAREACAR 40.5907 LAYER M3  ;
    ANTENNAMAXCUTCAR 0.641026 LAYER VL  ;
    PORT
      LAYER M2 ;
        RECT 261.900000 563.400000 262.100000 564.000000 ;
    END
  END crash_dump_o[75]
  PIN crash_dump_o[74]
    DIRECTION OUTPUT ;
    USE SIGNAL ;
    ANTENNAPARTIALMETALAREA 6.12 LAYER M2  ;
    ANTENNAPARTIALMETALSIDEAREA 22.644 LAYER M2  ;
    ANTENNAPARTIALCUTAREA 0.04 LAYER V2  ;
    ANTENNAPARTIALMETALAREA 9.92 LAYER M3  ;
    ANTENNAPARTIALMETALSIDEAREA 37.296 LAYER M3  ;
    ANTENNAMODEL OXIDE1 ;
    ANTENNAGATEAREA 4.084 LAYER M3  ;
    ANTENNAMAXAREACAR 10.4519 LAYER M3  ;
    ANTENNAMAXSIDEAREACAR 38.7773 LAYER M3  ;
    ANTENNAMAXCUTCAR 0.462963 LAYER VL  ;
    PORT
      LAYER M2 ;
        RECT 264.900000 563.400000 265.100000 564.000000 ;
    END
  END crash_dump_o[74]
  PIN crash_dump_o[73]
    DIRECTION OUTPUT ;
    USE SIGNAL ;
    ANTENNAPARTIALMETALAREA 9.18 LAYER M2  ;
    ANTENNAPARTIALMETALSIDEAREA 33.596 LAYER M2  ;
    ANTENNAPARTIALCUTAREA 0.12 LAYER V2  ;
    ANTENNAPARTIALMETALAREA 12.16 LAYER M3  ;
    ANTENNAPARTIALMETALSIDEAREA 45.88 LAYER M3  ;
    ANTENNAMODEL OXIDE1 ;
    ANTENNAGATEAREA 3.8872 LAYER M3  ;
    ANTENNAMAXAREACAR 5.22544 LAYER M3  ;
    ANTENNAMAXSIDEAREACAR 20.6015 LAYER M3  ;
    ANTENNAMAXCUTCAR 0.462963 LAYER VL  ;
    PORT
      LAYER M2 ;
        RECT 267.900000 563.400000 268.100000 564.000000 ;
    END
  END crash_dump_o[73]
  PIN crash_dump_o[72]
    DIRECTION OUTPUT ;
    USE SIGNAL ;
    ANTENNAPARTIALMETALAREA 0.02 LAYER M2  ;
    ANTENNAPARTIALMETALSIDEAREA 0.074 LAYER M2  ;
    ANTENNAPARTIALCUTAREA 0.04 LAYER V2  ;
    ANTENNAPARTIALMETALAREA 16.2 LAYER M3  ;
    ANTENNAPARTIALMETALSIDEAREA 60.68 LAYER M3  ;
    ANTENNAMODEL OXIDE1 ;
    ANTENNAGATEAREA 3.6928 LAYER M3  ;
    ANTENNAMAXAREACAR 11.8417 LAYER M3  ;
    ANTENNAMAXSIDEAREACAR 43.9748 LAYER M3  ;
    ANTENNAMAXCUTCAR 0.462963 LAYER VL  ;
    PORT
      LAYER M2 ;
        RECT 270.900000 563.400000 271.100000 564.000000 ;
    END
  END crash_dump_o[72]
  PIN crash_dump_o[71]
    DIRECTION OUTPUT ;
    USE SIGNAL ;
    ANTENNAPARTIALMETALAREA 9.7 LAYER M2  ;
    ANTENNAPARTIALMETALSIDEAREA 35.52 LAYER M2  ;
    ANTENNAPARTIALCUTAREA 0.04 LAYER V2  ;
    ANTENNAPARTIALMETALAREA 13 LAYER M3  ;
    ANTENNAPARTIALMETALSIDEAREA 48.84 LAYER M3  ;
    ANTENNAMODEL OXIDE1 ;
    ANTENNAGATEAREA 3.6928 LAYER M3  ;
    ANTENNAMAXAREACAR 5.61759 LAYER M3  ;
    ANTENNAMAXSIDEAREACAR 22.0243 LAYER M3  ;
    ANTENNAMAXCUTCAR 0.462963 LAYER VL  ;
    PORT
      LAYER M2 ;
        RECT 273.900000 563.400000 274.100000 564.000000 ;
    END
  END crash_dump_o[71]
  PIN crash_dump_o[70]
    DIRECTION OUTPUT ;
    USE SIGNAL ;
    ANTENNAPARTIALMETALAREA 11.96 LAYER M2  ;
    ANTENNAPARTIALMETALSIDEAREA 44.252 LAYER M2  ;
    ANTENNAPARTIALCUTAREA 0.04 LAYER V2  ;
    ANTENNAPARTIALMETALAREA 12.44 LAYER M3  ;
    ANTENNAPARTIALMETALSIDEAREA 46.472 LAYER M3  ;
    ANTENNAMODEL OXIDE1 ;
    ANTENNAGATEAREA 3.6928 LAYER M3  ;
    ANTENNAMAXAREACAR 10.1417 LAYER M3  ;
    ANTENNAMAXSIDEAREACAR 37.6046 LAYER M3  ;
    ANTENNAMAXCUTCAR 0.462963 LAYER VL  ;
    PORT
      LAYER M2 ;
        RECT 276.900000 563.400000 277.100000 564.000000 ;
    END
  END crash_dump_o[70]
  PIN crash_dump_o[69]
    DIRECTION OUTPUT ;
    USE SIGNAL ;
    ANTENNAPARTIALMETALAREA 11.38 LAYER M2  ;
    ANTENNAPARTIALMETALSIDEAREA 41.736 LAYER M2  ;
    ANTENNAPARTIALCUTAREA 0.04 LAYER V2  ;
    ANTENNAPARTIALMETALAREA 14.36 LAYER M3  ;
    ANTENNAPARTIALMETALSIDEAREA 53.576 LAYER M3  ;
    ANTENNAMODEL OXIDE1 ;
    ANTENNAGATEAREA 4.084 LAYER M3  ;
    ANTENNAMAXAREACAR 6.07635 LAYER M3  ;
    ANTENNAMAXSIDEAREACAR 23.6301 LAYER M3  ;
    ANTENNAMAXCUTCAR 0.462963 LAYER VL  ;
    PORT
      LAYER M2 ;
        RECT 279.900000 563.400000 280.100000 564.000000 ;
    END
  END crash_dump_o[69]
  PIN crash_dump_o[68]
    DIRECTION OUTPUT ;
    USE SIGNAL ;
    ANTENNAPARTIALMETALAREA 12.52 LAYER M2  ;
    ANTENNAPARTIALMETALSIDEAREA 46.324 LAYER M2  ;
    ANTENNAPARTIALCUTAREA 0.04 LAYER V2  ;
    ANTENNAPARTIALMETALAREA 16.4 LAYER M3  ;
    ANTENNAPARTIALMETALSIDEAREA 61.272 LAYER M3  ;
    ANTENNAMODEL OXIDE1 ;
    ANTENNAGATEAREA 3.8656 LAYER M3  ;
    ANTENNAMAXAREACAR 6.80273 LAYER M3  ;
    ANTENNAMAXSIDEAREACAR 26.3622 LAYER M3  ;
    ANTENNAMAXCUTCAR 0.462963 LAYER VL  ;
    PORT
      LAYER M2 ;
        RECT 282.900000 563.400000 283.100000 564.000000 ;
    END
  END crash_dump_o[68]
  PIN crash_dump_o[67]
    DIRECTION OUTPUT ;
    USE SIGNAL ;
    ANTENNAPARTIALMETALAREA 0.18 LAYER M2  ;
    ANTENNAPARTIALMETALSIDEAREA 0.296 LAYER M2  ;
    ANTENNAPARTIALCUTAREA 0.04 LAYER V2  ;
    ANTENNAPARTIALMETALAREA 17.72 LAYER M3  ;
    ANTENNAPARTIALMETALSIDEAREA 66.304 LAYER M3  ;
    ANTENNAMODEL OXIDE1 ;
    ANTENNAGATEAREA 3.8656 LAYER M3  ;
    ANTENNAMAXAREACAR 7.14421 LAYER M3  ;
    ANTENNAMAXSIDEAREACAR 27.6639 LAYER M3  ;
    ANTENNAMAXCUTCAR 0.462963 LAYER VL  ;
    PORT
      LAYER M2 ;
        RECT 285.900000 563.400000 286.100000 564.000000 ;
    END
  END crash_dump_o[67]
  PIN crash_dump_o[66]
    DIRECTION OUTPUT ;
    USE SIGNAL ;
    ANTENNAPARTIALMETALAREA 2.44 LAYER M2  ;
    ANTENNAPARTIALMETALSIDEAREA 9.028 LAYER M2  ;
    ANTENNAPARTIALCUTAREA 0.04 LAYER V2  ;
    ANTENNAPARTIALMETALAREA 18.88 LAYER M3  ;
    ANTENNAPARTIALMETALSIDEAREA 70.448 LAYER M3  ;
    ANTENNAMODEL OXIDE1 ;
    ANTENNAGATEAREA 3.8416 LAYER M3  ;
    ANTENNAMAXAREACAR 7.29298 LAYER M3  ;
    ANTENNAMAXSIDEAREACAR 28.0075 LAYER M3  ;
    ANTENNAMAXCUTCAR 0.537634 LAYER VL  ;
    PORT
      LAYER M2 ;
        RECT 288.900000 563.400000 289.100000 564.000000 ;
    END
  END crash_dump_o[66]
  PIN crash_dump_o[65]
    DIRECTION OUTPUT ;
    USE SIGNAL ;
    ANTENNAPARTIALMETALAREA 8.42 LAYER M2  ;
    ANTENNAPARTIALMETALSIDEAREA 30.784 LAYER M2  ;
    ANTENNAPARTIALCUTAREA 0.04 LAYER V2  ;
    ANTENNAPARTIALMETALAREA 15.08 LAYER M3  ;
    ANTENNAPARTIALMETALSIDEAREA 56.24 LAYER M3  ;
    ANTENNAMODEL OXIDE1 ;
    ANTENNAGATEAREA 3.8416 LAYER M3  ;
    ANTENNAMAXAREACAR 12.0211 LAYER M3  ;
    ANTENNAMAXSIDEAREACAR 44.5526 LAYER M3  ;
    ANTENNAMAXCUTCAR 0.537634 LAYER VL  ;
    PORT
      LAYER M2 ;
        RECT 291.900000 563.400000 292.100000 564.000000 ;
    END
  END crash_dump_o[65]
  PIN crash_dump_o[64]
    DIRECTION OUTPUT ;
    USE SIGNAL ;
    ANTENNAPARTIALMETALAREA 0.02 LAYER M2  ;
    ANTENNAPARTIALMETALSIDEAREA 0.074 LAYER M2  ;
    ANTENNAPARTIALCUTAREA 0.04 LAYER V2  ;
    ANTENNAPARTIALMETALAREA 13.72 LAYER M3  ;
    ANTENNAPARTIALMETALSIDEAREA 50.912 LAYER M3  ;
    ANTENNAMODEL OXIDE1 ;
    ANTENNAGATEAREA 3.8272 LAYER M3  ;
    ANTENNAMAXAREACAR 138.275 LAYER M3  ;
    ANTENNAMAXSIDEAREACAR 580.359 LAYER M3  ;
    ANTENNAMAXCUTCAR 0.365061 LAYER VL  ;
    PORT
      LAYER M2 ;
        RECT 294.900000 563.400000 295.100000 564.000000 ;
    END
  END crash_dump_o[64]
  PIN crash_dump_o[63]
    DIRECTION OUTPUT ;
    USE SIGNAL ;
    ANTENNAPARTIALMETALAREA 7.78 LAYER M2  ;
    ANTENNAPARTIALMETALSIDEAREA 28.416 LAYER M2  ;
    ANTENNAPARTIALCUTAREA 0.04 LAYER V2  ;
    ANTENNAPARTIALMETALAREA 28.08 LAYER M3  ;
    ANTENNAPARTIALMETALSIDEAREA 104.488 LAYER M3  ;
    ANTENNAMODEL OXIDE1 ;
    ANTENNAGATEAREA 3.94 LAYER M3  ;
    ANTENNAMAXAREACAR 97.6501 LAYER M3  ;
    ANTENNAMAXSIDEAREACAR 362.494 LAYER M3  ;
    ANTENNAMAXCUTCAR 1.07527 LAYER VL  ;
    PORT
      LAYER M2 ;
        RECT 297.900000 563.400000 298.100000 564.000000 ;
    END
  END crash_dump_o[63]
  PIN crash_dump_o[62]
    DIRECTION OUTPUT ;
    USE SIGNAL ;
    ANTENNAPARTIALMETALAREA 3.8 LAYER M2  ;
    ANTENNAPARTIALMETALSIDEAREA 14.06 LAYER M2  ;
    ANTENNAPARTIALCUTAREA 0.04 LAYER V2  ;
    ANTENNAPARTIALMETALAREA 30.6 LAYER M3  ;
    ANTENNAPARTIALMETALSIDEAREA 113.96 LAYER M3  ;
    ANTENNAMODEL OXIDE1 ;
    ANTENNAGATEAREA 3.94 LAYER M3  ;
    ANTENNAMAXAREACAR 97.7341 LAYER M3  ;
    ANTENNAMAXSIDEAREACAR 362.871 LAYER M3  ;
    ANTENNAMAXCUTCAR 1.07527 LAYER VL  ;
    PORT
      LAYER M2 ;
        RECT 300.900000 563.400000 301.100000 564.000000 ;
    END
  END crash_dump_o[62]
  PIN crash_dump_o[61]
    DIRECTION OUTPUT ;
    USE SIGNAL ;
    ANTENNAPARTIALMETALAREA 0.1 LAYER M2  ;
    ANTENNAPARTIALMETALSIDEAREA 0.222 LAYER M2  ;
    ANTENNAPARTIALCUTAREA 0.04 LAYER V2  ;
    ANTENNAPARTIALMETALAREA 35.4 LAYER M3  ;
    ANTENNAPARTIALMETALSIDEAREA 131.424 LAYER M3  ;
    ANTENNAMODEL OXIDE1 ;
    ANTENNAGATEAREA 3.94 LAYER M3  ;
    ANTENNAMAXAREACAR 122.656 LAYER M3  ;
    ANTENNAMAXSIDEAREACAR 454.979 LAYER M3  ;
    ANTENNAMAXCUTCAR 1.07527 LAYER VL  ;
    PORT
      LAYER M2 ;
        RECT 303.900000 563.400000 304.100000 564.000000 ;
    END
  END crash_dump_o[61]
  PIN crash_dump_o[60]
    DIRECTION OUTPUT ;
    USE SIGNAL ;
    ANTENNAPARTIALMETALAREA 1.72 LAYER M2  ;
    ANTENNAPARTIALMETALSIDEAREA 6.364 LAYER M2  ;
    ANTENNAPARTIALCUTAREA 0.04 LAYER V2  ;
    ANTENNAPARTIALMETALAREA 41.2 LAYER M3  ;
    ANTENNAPARTIALMETALSIDEAREA 153.032 LAYER M3  ;
    ANTENNAMODEL OXIDE1 ;
    ANTENNAGATEAREA 3.6616 LAYER M3  ;
    ANTENNAMAXAREACAR 16.1805 LAYER M3  ;
    ANTENNAMAXSIDEAREACAR 62.6985 LAYER M3  ;
    ANTENNAMAXCUTCAR 1.19048 LAYER VL  ;
    PORT
      LAYER M2 ;
        RECT 306.900000 563.400000 307.100000 564.000000 ;
    END
  END crash_dump_o[60]
  PIN crash_dump_o[59]
    DIRECTION OUTPUT ;
    USE SIGNAL ;
    ANTENNAPARTIALMETALAREA 2.5 LAYER M2  ;
    ANTENNAPARTIALMETALSIDEAREA 8.88 LAYER M2  ;
    ANTENNAPARTIALCUTAREA 0.04 LAYER V2  ;
    ANTENNAPARTIALMETALAREA 41.16 LAYER M3  ;
    ANTENNAPARTIALMETALSIDEAREA 153.032 LAYER M3  ;
    ANTENNAMODEL OXIDE1 ;
    ANTENNAGATEAREA 3.8344 LAYER M3  ;
    ANTENNAMAXAREACAR 17.3415 LAYER M3  ;
    ANTENNAMAXSIDEAREACAR 65.7258 LAYER M3  ;
    ANTENNAMAXCUTCAR 1.19048 LAYER VL  ;
    PORT
      LAYER M2 ;
        RECT 309.900000 563.400000 310.100000 564.000000 ;
    END
  END crash_dump_o[59]
  PIN crash_dump_o[58]
    DIRECTION OUTPUT ;
    USE SIGNAL ;
    ANTENNAPARTIALMETALAREA 1.64 LAYER M2  ;
    ANTENNAPARTIALMETALSIDEAREA 6.068 LAYER M2  ;
    ANTENNAPARTIALCUTAREA 0.04 LAYER V2  ;
    ANTENNAPARTIALMETALAREA 37.96 LAYER M3  ;
    ANTENNAPARTIALMETALSIDEAREA 141.192 LAYER M3  ;
    ANTENNAMODEL OXIDE1 ;
    ANTENNAGATEAREA 3.94 LAYER M3  ;
    ANTENNAMAXAREACAR 11.8496 LAYER M3  ;
    ANTENNAMAXSIDEAREACAR 46.3033 LAYER M3  ;
    ANTENNAMAXCUTCAR 1.07527 LAYER VL  ;
    PORT
      LAYER M2 ;
        RECT 312.900000 563.400000 313.100000 564.000000 ;
    END
  END crash_dump_o[58]
  PIN crash_dump_o[57]
    DIRECTION OUTPUT ;
    USE SIGNAL ;
    ANTENNAPARTIALMETALAREA 1.06 LAYER M2  ;
    ANTENNAPARTIALMETALSIDEAREA 3.552 LAYER M2  ;
    ANTENNAPARTIALCUTAREA 0.04 LAYER V2  ;
    ANTENNAPARTIALMETALAREA 43.44 LAYER M3  ;
    ANTENNAPARTIALMETALSIDEAREA 161.32 LAYER M3  ;
    ANTENNAMODEL OXIDE1 ;
    ANTENNAGATEAREA 3.8344 LAYER M3  ;
    ANTENNAMAXAREACAR 155.556 LAYER M3  ;
    ANTENNAMAXSIDEAREACAR 576.75 LAYER M3  ;
    ANTENNAMAXCUTCAR 1.6129 LAYER VL  ;
    PORT
      LAYER M2 ;
        RECT 315.900000 563.400000 316.100000 564.000000 ;
    END
  END crash_dump_o[57]
  PIN crash_dump_o[56]
    DIRECTION OUTPUT ;
    USE SIGNAL ;
    ANTENNAPARTIALMETALAREA 0.44 LAYER M2  ;
    ANTENNAPARTIALMETALSIDEAREA 1.628 LAYER M2  ;
    ANTENNAPARTIALCUTAREA 0.04 LAYER V2  ;
    ANTENNAPARTIALMETALAREA 40 LAYER M3  ;
    ANTENNAPARTIALMETALSIDEAREA 148.592 LAYER M3  ;
    ANTENNAMODEL OXIDE1 ;
    ANTENNAGATEAREA 3.94 LAYER M3  ;
    ANTENNAMAXAREACAR 148.361 LAYER M3  ;
    ANTENNAMAXSIDEAREACAR 550.123 LAYER M3  ;
    ANTENNAMAXCUTCAR 1.07527 LAYER VL  ;
    PORT
      LAYER M2 ;
        RECT 318.900000 563.400000 319.100000 564.000000 ;
    END
  END crash_dump_o[56]
  PIN crash_dump_o[55]
    DIRECTION OUTPUT ;
    USE SIGNAL ;
    ANTENNAPARTIALMETALAREA 4.1 LAYER M2  ;
    ANTENNAPARTIALMETALSIDEAREA 14.8 LAYER M2  ;
    ANTENNAPARTIALCUTAREA 0.04 LAYER V2  ;
    ANTENNAPARTIALMETALAREA 31.6 LAYER M3  ;
    ANTENNAPARTIALMETALSIDEAREA 117.808 LAYER M3  ;
    ANTENNAMODEL OXIDE1 ;
    ANTENNAGATEAREA 3.94 LAYER M3  ;
    ANTENNAMAXAREACAR 11.4182 LAYER M3  ;
    ANTENNAMAXSIDEAREACAR 44.7123 LAYER M3  ;
    ANTENNAMAXCUTCAR 1.07527 LAYER VL  ;
    PORT
      LAYER M2 ;
        RECT 321.900000 563.400000 322.100000 564.000000 ;
    END
  END crash_dump_o[55]
  PIN crash_dump_o[54]
    DIRECTION OUTPUT ;
    USE SIGNAL ;
    ANTENNAPARTIALMETALAREA 1 LAYER M2  ;
    ANTENNAPARTIALMETALSIDEAREA 3.7 LAYER M2  ;
    ANTENNAPARTIALCUTAREA 0.04 LAYER V2  ;
    ANTENNAPARTIALMETALAREA 39.76 LAYER M3  ;
    ANTENNAPARTIALMETALSIDEAREA 147.704 LAYER M3  ;
    ANTENNAMODEL OXIDE1 ;
    ANTENNAGATEAREA 3.94 LAYER M3  ;
    ANTENNAMAXAREACAR 26.3924 LAYER M3  ;
    ANTENNAMAXSIDEAREACAR 100.042 LAYER M3  ;
    ANTENNAMAXCUTCAR 1.6129 LAYER VL  ;
    PORT
      LAYER M2 ;
        RECT 324.900000 563.400000 325.100000 564.000000 ;
    END
  END crash_dump_o[54]
  PIN crash_dump_o[53]
    DIRECTION OUTPUT ;
    USE SIGNAL ;
    ANTENNAPARTIALMETALAREA 3.86 LAYER M2  ;
    ANTENNAPARTIALMETALSIDEAREA 13.912 LAYER M2  ;
    ANTENNAPARTIALCUTAREA 0.08 LAYER V2  ;
    ANTENNAPARTIALMETALAREA 37.44 LAYER M3  ;
    ANTENNAPARTIALMETALSIDEAREA 139.12 LAYER M3  ;
    ANTENNAMODEL OXIDE1 ;
    ANTENNAGATEAREA 3.94 LAYER M3  ;
    ANTENNAMAXAREACAR 124.1 LAYER M3  ;
    ANTENNAMAXSIDEAREACAR 460.358 LAYER M3  ;
    ANTENNAMAXCUTCAR 1.07527 LAYER VL  ;
    PORT
      LAYER M2 ;
        RECT 327.900000 563.400000 328.100000 564.000000 ;
    END
  END crash_dump_o[53]
  PIN crash_dump_o[52]
    DIRECTION OUTPUT ;
    USE SIGNAL ;
    ANTENNAPARTIALMETALAREA 2.52 LAYER M2  ;
    ANTENNAPARTIALMETALSIDEAREA 9.324 LAYER M2  ;
    ANTENNAPARTIALCUTAREA 0.04 LAYER V2  ;
    ANTENNAPARTIALMETALAREA 44.24 LAYER M3  ;
    ANTENNAPARTIALMETALSIDEAREA 164.28 LAYER M3  ;
    ANTENNAMODEL OXIDE1 ;
    ANTENNAGATEAREA 3.8344 LAYER M3  ;
    ANTENNAMAXAREACAR 325.288 LAYER M3  ;
    ANTENNAMAXSIDEAREACAR 1205.09 LAYER M3  ;
    ANTENNAMAXCUTCAR 1.19048 LAYER VL  ;
    PORT
      LAYER M2 ;
        RECT 330.900000 563.400000 331.100000 564.000000 ;
    END
  END crash_dump_o[52]
  PIN crash_dump_o[51]
    DIRECTION OUTPUT ;
    USE SIGNAL ;
    ANTENNAPARTIALMETALAREA 0.5 LAYER M2  ;
    ANTENNAPARTIALMETALSIDEAREA 1.48 LAYER M2  ;
    ANTENNAPARTIALCUTAREA 0.04 LAYER V2  ;
    ANTENNAPARTIALMETALAREA 42.24 LAYER M3  ;
    ANTENNAPARTIALMETALSIDEAREA 156.88 LAYER M3  ;
    ANTENNAMODEL OXIDE1 ;
    ANTENNAGATEAREA 3.94 LAYER M3  ;
    ANTENNAMAXAREACAR 91.0588 LAYER M3  ;
    ANTENNAMAXSIDEAREACAR 338.107 LAYER M3  ;
    ANTENNAMAXCUTCAR 1.6129 LAYER VL  ;
    PORT
      LAYER M2 ;
        RECT 333.900000 563.400000 334.100000 564.000000 ;
    END
  END crash_dump_o[51]
  PIN crash_dump_o[50]
    DIRECTION OUTPUT ;
    USE SIGNAL ;
    ANTENNAPARTIALMETALAREA 1.08 LAYER M2  ;
    ANTENNAPARTIALMETALSIDEAREA 3.996 LAYER M2  ;
    ANTENNAPARTIALCUTAREA 0.04 LAYER V2  ;
    ANTENNAPARTIALMETALAREA 36.64 LAYER M3  ;
    ANTENNAPARTIALMETALSIDEAREA 136.456 LAYER M3  ;
    ANTENNAMODEL OXIDE1 ;
    ANTENNAGATEAREA 3.94 LAYER M3  ;
    ANTENNAMAXAREACAR 16.9984 LAYER M3  ;
    ANTENNAMAXSIDEAREACAR 65.3593 LAYER M3  ;
    ANTENNAMAXCUTCAR 1.07527 LAYER VL  ;
    PORT
      LAYER M2 ;
        RECT 336.900000 563.400000 337.100000 564.000000 ;
    END
  END crash_dump_o[50]
  PIN crash_dump_o[49]
    DIRECTION OUTPUT ;
    USE SIGNAL ;
    ANTENNAPARTIALMETALAREA 5.62 LAYER M2  ;
    ANTENNAPARTIALMETALSIDEAREA 20.424 LAYER M2  ;
    ANTENNAPARTIALCUTAREA 0.04 LAYER V2  ;
    ANTENNAPARTIALMETALAREA 30.32 LAYER M3  ;
    ANTENNAPARTIALMETALSIDEAREA 112.776 LAYER M3  ;
    ANTENNAMODEL OXIDE1 ;
    ANTENNAGATEAREA 3.94 LAYER M3  ;
    ANTENNAMAXAREACAR 203.566 LAYER M3  ;
    ANTENNAMAXSIDEAREACAR 755.586 LAYER M3  ;
    ANTENNAMAXCUTCAR 2.15054 LAYER VL  ;
    PORT
      LAYER M2 ;
        RECT 339.900000 563.400000 340.100000 564.000000 ;
    END
  END crash_dump_o[49]
  PIN crash_dump_o[48]
    DIRECTION OUTPUT ;
    USE SIGNAL ;
    ANTENNAPARTIALMETALAREA 0.02 LAYER M2  ;
    ANTENNAPARTIALMETALSIDEAREA 0.074 LAYER M2  ;
    ANTENNAPARTIALCUTAREA 0.04 LAYER V2  ;
    ANTENNAPARTIALMETALAREA 43.4 LAYER M3  ;
    ANTENNAPARTIALMETALSIDEAREA 161.32 LAYER M3  ;
    ANTENNAMODEL OXIDE1 ;
    ANTENNAGATEAREA 3.8368 LAYER M3  ;
    ANTENNAMAXAREACAR 15.277 LAYER M3  ;
    ANTENNAMAXSIDEAREACAR 58.2696 LAYER M3  ;
    ANTENNAMAXCUTCAR 1.14943 LAYER VL  ;
    PORT
      LAYER M2 ;
        RECT 342.900000 563.400000 343.100000 564.000000 ;
    END
  END crash_dump_o[48]
  PIN crash_dump_o[47]
    DIRECTION OUTPUT ;
    USE SIGNAL ;
    ANTENNAPARTIALMETALAREA 3.7 LAYER M2  ;
    ANTENNAPARTIALMETALSIDEAREA 13.32 LAYER M2  ;
    ANTENNAPARTIALCUTAREA 0.04 LAYER V2  ;
    ANTENNAPARTIALMETALAREA 32.88 LAYER M3  ;
    ANTENNAPARTIALMETALSIDEAREA 122.248 LAYER M3  ;
    ANTENNAMODEL OXIDE1 ;
    ANTENNAGATEAREA 3.94 LAYER M3  ;
    ANTENNAMAXAREACAR 123.405 LAYER M3  ;
    ANTENNAMAXSIDEAREACAR 457.789 LAYER M3  ;
    ANTENNAMAXCUTCAR 1.07527 LAYER VL  ;
    PORT
      LAYER M2 ;
        RECT 345.900000 563.400000 346.100000 564.000000 ;
    END
  END crash_dump_o[47]
  PIN crash_dump_o[46]
    DIRECTION OUTPUT ;
    USE SIGNAL ;
    ANTENNAPARTIALMETALAREA 0.6 LAYER M2  ;
    ANTENNAPARTIALMETALSIDEAREA 2.22 LAYER M2  ;
    ANTENNAPARTIALCUTAREA 0.04 LAYER V2  ;
    ANTENNAPARTIALMETALAREA 29.8 LAYER M3  ;
    ANTENNAPARTIALMETALSIDEAREA 111 LAYER M3  ;
    ANTENNAMODEL OXIDE1 ;
    ANTENNAGATEAREA 3.8344 LAYER M3  ;
    ANTENNAMAXAREACAR 11.1696 LAYER M3  ;
    ANTENNAMAXSIDEAREACAR 43.7603 LAYER M3  ;
    ANTENNAMAXCUTCAR 1.19048 LAYER VL  ;
    PORT
      LAYER M2 ;
        RECT 348.900000 563.400000 349.100000 564.000000 ;
    END
  END crash_dump_o[46]
  PIN crash_dump_o[45]
    DIRECTION OUTPUT ;
    USE SIGNAL ;
    ANTENNAPARTIALMETALAREA 20.74 LAYER M2  ;
    ANTENNAPARTIALMETALSIDEAREA 76.368 LAYER M2  ;
    ANTENNAPARTIALCUTAREA 0.04 LAYER V2  ;
    ANTENNAPARTIALMETALAREA 27.36 LAYER M3  ;
    ANTENNAPARTIALMETALSIDEAREA 101.824 LAYER M3  ;
    ANTENNAMODEL OXIDE1 ;
    ANTENNAGATEAREA 3.94 LAYER M3  ;
    ANTENNAMAXAREACAR 10.342 LAYER M3  ;
    ANTENNAMAXSIDEAREACAR 40.6555 LAYER M3  ;
    ANTENNAMAXCUTCAR 1.07527 LAYER VL  ;
    PORT
      LAYER M2 ;
        RECT 351.900000 563.400000 352.100000 564.000000 ;
    END
  END crash_dump_o[45]
  PIN crash_dump_o[44]
    DIRECTION OUTPUT ;
    USE SIGNAL ;
    ANTENNAPARTIALMETALAREA 2.12 LAYER M2  ;
    ANTENNAPARTIALMETALSIDEAREA 7.844 LAYER M2  ;
    ANTENNAPARTIALCUTAREA 0.04 LAYER V2  ;
    ANTENNAPARTIALMETALAREA 24.36 LAYER M3  ;
    ANTENNAPARTIALMETALSIDEAREA 90.872 LAYER M3  ;
    ANTENNAMODEL OXIDE1 ;
    ANTENNAGATEAREA 3.94 LAYER M3  ;
    ANTENNAMAXAREACAR 8.39779 LAYER M3  ;
    ANTENNAMAXSIDEAREACAR 33.5317 LAYER M3  ;
    ANTENNAMAXCUTCAR 1.07527 LAYER VL  ;
    PORT
      LAYER M2 ;
        RECT 354.900000 563.400000 355.100000 564.000000 ;
    END
  END crash_dump_o[44]
  PIN crash_dump_o[43]
    DIRECTION OUTPUT ;
    USE SIGNAL ;
    ANTENNAPARTIALMETALAREA 4.02 LAYER M2  ;
    ANTENNAPARTIALMETALSIDEAREA 14.504 LAYER M2  ;
    ANTENNAPARTIALCUTAREA 0.08 LAYER V2  ;
    ANTENNAPARTIALMETALAREA 31.6 LAYER M3  ;
    ANTENNAPARTIALMETALSIDEAREA 117.512 LAYER M3  ;
    ANTENNAMODEL OXIDE1 ;
    ANTENNAGATEAREA 3.94 LAYER M3  ;
    ANTENNAMAXAREACAR 121.807 LAYER M3  ;
    ANTENNAMAXSIDEAREACAR 450.934 LAYER M3  ;
    ANTENNAMAXCUTCAR 1.07527 LAYER VL  ;
    PORT
      LAYER M2 ;
        RECT 357.900000 563.400000 358.100000 564.000000 ;
    END
  END crash_dump_o[43]
  PIN crash_dump_o[42]
    DIRECTION OUTPUT ;
    USE SIGNAL ;
    ANTENNAPARTIALMETALAREA 0.02 LAYER M2  ;
    ANTENNAPARTIALMETALSIDEAREA 0.074 LAYER M2  ;
    ANTENNAPARTIALCUTAREA 0.04 LAYER V2  ;
    ANTENNAPARTIALMETALAREA 19.48 LAYER M3  ;
    ANTENNAPARTIALMETALSIDEAREA 72.816 LAYER M3  ;
    ANTENNAMODEL OXIDE1 ;
    ANTENNAGATEAREA 3.8344 LAYER M3  ;
    ANTENNAMAXAREACAR 55.247 LAYER M3  ;
    ANTENNAMAXSIDEAREACAR 207.276 LAYER M3  ;
    ANTENNAMAXCUTCAR 1.19048 LAYER VL  ;
    PORT
      LAYER M2 ;
        RECT 360.900000 563.400000 361.100000 564.000000 ;
    END
  END crash_dump_o[42]
  PIN crash_dump_o[41]
    DIRECTION OUTPUT ;
    USE SIGNAL ;
    ANTENNAPARTIALMETALAREA 2.74 LAYER M2  ;
    ANTENNAPARTIALMETALSIDEAREA 9.768 LAYER M2  ;
    ANTENNAPARTIALCUTAREA 0.04 LAYER V2  ;
    ANTENNAPARTIALMETALAREA 21.64 LAYER M3  ;
    ANTENNAPARTIALMETALSIDEAREA 80.512 LAYER M3  ;
    ANTENNAMODEL OXIDE1 ;
    ANTENNAGATEAREA 3.8368 LAYER M3  ;
    ANTENNAMAXAREACAR 98.941 LAYER M3  ;
    ANTENNAMAXSIDEAREACAR 367.236 LAYER M3  ;
    ANTENNAMAXCUTCAR 1.14943 LAYER VL  ;
    PORT
      LAYER M2 ;
        RECT 363.900000 563.400000 364.100000 564.000000 ;
    END
  END crash_dump_o[41]
  PIN crash_dump_o[40]
    DIRECTION OUTPUT ;
    USE SIGNAL ;
    ANTENNAPARTIALMETALAREA 15.48 LAYER M2  ;
    ANTENNAPARTIALMETALSIDEAREA 57.276 LAYER M2  ;
    ANTENNAPARTIALCUTAREA 0.04 LAYER V2  ;
    ANTENNAPARTIALMETALAREA 20.68 LAYER M3  ;
    ANTENNAPARTIALMETALSIDEAREA 76.96 LAYER M3  ;
    ANTENNAMODEL OXIDE1 ;
    ANTENNAGATEAREA 3.94 LAYER M3  ;
    ANTENNAMAXAREACAR 39.8294 LAYER M3  ;
    ANTENNAMAXSIDEAREACAR 149.721 LAYER M3  ;
    ANTENNAMAXCUTCAR 1.07527 LAYER VL  ;
    PORT
      LAYER M2 ;
        RECT 366.900000 563.400000 367.100000 564.000000 ;
    END
  END crash_dump_o[40]
  PIN crash_dump_o[39]
    DIRECTION OUTPUT ;
    USE SIGNAL ;
    ANTENNAPARTIALMETALAREA 1.38 LAYER M2  ;
    ANTENNAPARTIALMETALSIDEAREA 4.736 LAYER M2  ;
    ANTENNAPARTIALCUTAREA 0.04 LAYER V2  ;
    ANTENNAPARTIALMETALAREA 28.52 LAYER M3  ;
    ANTENNAPARTIALMETALSIDEAREA 106.264 LAYER M3  ;
    ANTENNAMODEL OXIDE1 ;
    ANTENNAGATEAREA 3.94 LAYER M3  ;
    ANTENNAMAXAREACAR 94.521 LAYER M3  ;
    ANTENNAMAXSIDEAREACAR 350.954 LAYER M3  ;
    ANTENNAMAXCUTCAR 1.07527 LAYER VL  ;
    PORT
      LAYER M2 ;
        RECT 369.900000 563.400000 370.100000 564.000000 ;
    END
  END crash_dump_o[39]
  PIN crash_dump_o[38]
    DIRECTION OUTPUT ;
    USE SIGNAL ;
    ANTENNAPARTIALMETALAREA 1.88 LAYER M2  ;
    ANTENNAPARTIALMETALSIDEAREA 6.956 LAYER M2  ;
    ANTENNAPARTIALCUTAREA 0.04 LAYER V2  ;
    ANTENNAPARTIALMETALAREA 28.88 LAYER M3  ;
    ANTENNAPARTIALMETALSIDEAREA 107.448 LAYER M3  ;
    ANTENNAMODEL OXIDE1 ;
    ANTENNAGATEAREA 3.7672 LAYER M3  ;
    ANTENNAMAXAREACAR 231.494 LAYER M3  ;
    ANTENNAMAXSIDEAREACAR 858.925 LAYER M3  ;
    ANTENNAMAXCUTCAR 2.15054 LAYER VL  ;
    PORT
      LAYER M2 ;
        RECT 372.900000 563.400000 373.100000 564.000000 ;
    END
  END crash_dump_o[38]
  PIN crash_dump_o[37]
    DIRECTION OUTPUT ;
    USE SIGNAL ;
    ANTENNAPARTIALMETALAREA 1.94 LAYER M2  ;
    ANTENNAPARTIALMETALSIDEAREA 6.808 LAYER M2  ;
    ANTENNAPARTIALCUTAREA 0.04 LAYER V2  ;
    ANTENNAPARTIALMETALAREA 32.04 LAYER M3  ;
    ANTENNAPARTIALMETALSIDEAREA 119.288 LAYER M3  ;
    ANTENNAMODEL OXIDE1 ;
    ANTENNAGATEAREA 3.94 LAYER M3  ;
    ANTENNAMAXAREACAR 11.5298 LAYER M3  ;
    ANTENNAMAXSIDEAREACAR 45.088 LAYER M3  ;
    ANTENNAMAXCUTCAR 1.07527 LAYER VL  ;
    PORT
      LAYER M2 ;
        RECT 375.900000 563.400000 376.100000 564.000000 ;
    END
  END crash_dump_o[37]
  PIN crash_dump_o[36]
    DIRECTION OUTPUT ;
    USE SIGNAL ;
    ANTENNAPARTIALMETALAREA 0.12 LAYER M2  ;
    ANTENNAPARTIALMETALSIDEAREA 0.444 LAYER M2  ;
    ANTENNAPARTIALCUTAREA 0.04 LAYER V2  ;
    ANTENNAPARTIALMETALAREA 19.32 LAYER M3  ;
    ANTENNAPARTIALMETALSIDEAREA 72.224 LAYER M3  ;
    ANTENNAMODEL OXIDE1 ;
    ANTENNAGATEAREA 3.8368 LAYER M3  ;
    ANTENNAMAXAREACAR 200.906 LAYER M3  ;
    ANTENNAMAXSIDEAREACAR 745.786 LAYER M3  ;
    ANTENNAMAXCUTCAR 1.72414 LAYER VL  ;
    PORT
      LAYER M2 ;
        RECT 378.900000 563.400000 379.100000 564.000000 ;
    END
  END crash_dump_o[36]
  PIN crash_dump_o[35]
    DIRECTION OUTPUT ;
    USE SIGNAL ;
    ANTENNAPARTIALMETALAREA 1.3 LAYER M2  ;
    ANTENNAPARTIALMETALSIDEAREA 4.44 LAYER M2  ;
    ANTENNAPARTIALCUTAREA 0.04 LAYER V2  ;
    ANTENNAPARTIALMETALAREA 22.52 LAYER M3  ;
    ANTENNAPARTIALMETALSIDEAREA 84.064 LAYER M3  ;
    ANTENNAMODEL OXIDE1 ;
    ANTENNAGATEAREA 0.8928 LAYER M3  ;
    ANTENNAMAXAREACAR 30.6335 LAYER M3  ;
    ANTENNAMAXSIDEAREACAR 112.355 LAYER M3  ;
    ANTENNAMAXCUTCAR 0.411523 LAYER VL  ;
    PORT
      LAYER M2 ;
        RECT 381.900000 563.400000 382.100000 564.000000 ;
    END
  END crash_dump_o[35]
  PIN crash_dump_o[34]
    DIRECTION OUTPUT ;
    USE SIGNAL ;
    ANTENNAPARTIALMETALAREA 7 LAYER M2  ;
    ANTENNAPARTIALMETALSIDEAREA 25.9 LAYER M2  ;
    ANTENNAPARTIALCUTAREA 0.04 LAYER V2  ;
    ANTENNAPARTIALMETALAREA 26.56 LAYER M3  ;
    ANTENNAPARTIALMETALSIDEAREA 98.864 LAYER M3  ;
    ANTENNAMODEL OXIDE1 ;
    ANTENNAGATEAREA 3.94 LAYER M3  ;
    ANTENNAMAXAREACAR 10.8059 LAYER M3  ;
    ANTENNAMAXSIDEAREACAR 40.229 LAYER M3  ;
    ANTENNAMAXCUTCAR 1.07527 LAYER VL  ;
    PORT
      LAYER M2 ;
        RECT 384.900000 563.400000 385.100000 564.000000 ;
    END
  END crash_dump_o[34]
  PIN crash_dump_o[33]
    DIRECTION OUTPUT ;
    USE SIGNAL ;
    ANTENNAPARTIALMETALAREA 0.18 LAYER M2  ;
    ANTENNAPARTIALMETALSIDEAREA 0.296 LAYER M2  ;
    ANTENNAPARTIALCUTAREA 0.04 LAYER V2  ;
    ANTENNAPARTIALMETALAREA 41 LAYER M3  ;
    ANTENNAPARTIALMETALSIDEAREA 152.44 LAYER M3  ;
    ANTENNAMODEL OXIDE1 ;
    ANTENNAGATEAREA 3.7672 LAYER M3  ;
    ANTENNAMAXAREACAR 13.5593 LAYER M3  ;
    ANTENNAMAXSIDEAREACAR 50.9328 LAYER M3  ;
    ANTENNAMAXCUTCAR 1.07527 LAYER VL  ;
    PORT
      LAYER M2 ;
        RECT 387.900000 563.400000 388.100000 564.000000 ;
    END
  END crash_dump_o[33]
  PIN crash_dump_o[32]
    DIRECTION OUTPUT ;
    USE SIGNAL ;
    PORT
      LAYER M2 ;
        RECT 390.900000 563.400000 391.100000 564.000000 ;
    END
  END crash_dump_o[32]
  PIN crash_dump_o[31]
    DIRECTION OUTPUT ;
    USE SIGNAL ;
    ANTENNAPARTIALMETALAREA 1.46 LAYER M2  ;
    ANTENNAPARTIALMETALSIDEAREA 5.032 LAYER M2  ;
    ANTENNAPARTIALCUTAREA 0.04 LAYER V2  ;
    ANTENNAPARTIALMETALAREA 13.16 LAYER M3  ;
    ANTENNAPARTIALMETALSIDEAREA 49.136 LAYER M3  ;
    ANTENNAMODEL OXIDE1 ;
    ANTENNAGATEAREA 3.6928 LAYER M3  ;
    ANTENNAMAXAREACAR 6.86392 LAYER M3  ;
    ANTENNAMAXSIDEAREACAR 25.4756 LAYER M3  ;
    ANTENNAMAXCUTCAR 0.462963 LAYER VL  ;
    PORT
      LAYER M2 ;
        RECT 393.900000 563.400000 394.100000 564.000000 ;
    END
  END crash_dump_o[31]
  PIN crash_dump_o[30]
    DIRECTION OUTPUT ;
    USE SIGNAL ;
    ANTENNAPARTIALMETALAREA 12.36 LAYER M2  ;
    ANTENNAPARTIALMETALSIDEAREA 45.732 LAYER M2  ;
    ANTENNAPARTIALCUTAREA 0.08 LAYER V2  ;
    ANTENNAPARTIALMETALAREA 21.6 LAYER M3  ;
    ANTENNAPARTIALMETALSIDEAREA 80.216 LAYER M3  ;
    ANTENNAMODEL OXIDE1 ;
    ANTENNAGATEAREA 3.6928 LAYER M3  ;
    ANTENNAMAXAREACAR 42.2057 LAYER M3  ;
    ANTENNAMAXSIDEAREACAR 157.28 LAYER M3  ;
    ANTENNAMAXCUTCAR 0.462963 LAYER VL  ;
    PORT
      LAYER M2 ;
        RECT 396.900000 563.400000 397.100000 564.000000 ;
    END
  END crash_dump_o[30]
  PIN crash_dump_o[29]
    DIRECTION OUTPUT ;
    USE SIGNAL ;
    ANTENNAPARTIALMETALAREA 11.3 LAYER M2  ;
    ANTENNAPARTIALMETALSIDEAREA 41.44 LAYER M2  ;
    ANTENNAPARTIALCUTAREA 0.04 LAYER V2  ;
    ANTENNAPARTIALMETALAREA 18.72 LAYER M3  ;
    ANTENNAPARTIALMETALSIDEAREA 69.56 LAYER M3  ;
    ANTENNAMODEL OXIDE1 ;
    ANTENNAGATEAREA 3.6928 LAYER M3  ;
    ANTENNAMAXAREACAR 6.70358 LAYER M3  ;
    ANTENNAMAXSIDEAREACAR 25.9223 LAYER M3  ;
    ANTENNAMAXCUTCAR 0.462963 LAYER VL  ;
    PORT
      LAYER M2 ;
        RECT 399.900000 563.400000 400.100000 564.000000 ;
    END
  END crash_dump_o[29]
  PIN crash_dump_o[28]
    DIRECTION OUTPUT ;
    USE SIGNAL ;
    ANTENNAPARTIALMETALAREA 13.8 LAYER M2  ;
    ANTENNAPARTIALMETALSIDEAREA 51.06 LAYER M2  ;
    ANTENNAPARTIALCUTAREA 0.08 LAYER V2  ;
    ANTENNAPARTIALMETALAREA 24.16 LAYER M3  ;
    ANTENNAPARTIALMETALSIDEAREA 89.688 LAYER M3  ;
    ANTENNAMODEL OXIDE1 ;
    ANTENNAGATEAREA 3.6928 LAYER M3  ;
    ANTENNAMAXAREACAR 31.3249 LAYER M3  ;
    ANTENNAMAXSIDEAREACAR 117.021 LAYER M3  ;
    ANTENNAMAXCUTCAR 0.462963 LAYER VL  ;
    PORT
      LAYER M2 ;
        RECT 402.900000 563.400000 403.100000 564.000000 ;
    END
  END crash_dump_o[28]
  PIN crash_dump_o[27]
    DIRECTION OUTPUT ;
    USE SIGNAL ;
    ANTENNAPARTIALMETALAREA 1.02 LAYER M2  ;
    ANTENNAPARTIALMETALSIDEAREA 3.404 LAYER M2  ;
    ANTENNAPARTIALCUTAREA 0.12 LAYER V2  ;
    ANTENNAPARTIALMETALAREA 24.24 LAYER M3  ;
    ANTENNAPARTIALMETALSIDEAREA 90.28 LAYER M3  ;
    ANTENNAMODEL OXIDE1 ;
    ANTENNAGATEAREA 3.6928 LAYER M3  ;
    ANTENNAMAXAREACAR 8.66135 LAYER M3  ;
    ANTENNAMAXSIDEAREACAR 33.2462 LAYER M3  ;
    ANTENNAMAXCUTCAR 0.462963 LAYER VL  ;
    PORT
      LAYER M2 ;
        RECT 405.900000 563.400000 406.100000 564.000000 ;
    END
  END crash_dump_o[27]
  PIN crash_dump_o[26]
    DIRECTION OUTPUT ;
    USE SIGNAL ;
    ANTENNAPARTIALMETALAREA 11.64 LAYER M2  ;
    ANTENNAPARTIALMETALSIDEAREA 43.068 LAYER M2  ;
    ANTENNAPARTIALCUTAREA 0.08 LAYER V2  ;
    ANTENNAPARTIALMETALAREA 22.8 LAYER M3  ;
    ANTENNAPARTIALMETALSIDEAREA 84.656 LAYER M3  ;
    ANTENNAMODEL OXIDE1 ;
    ANTENNAGATEAREA 3.6928 LAYER M3  ;
    ANTENNAMAXAREACAR 38.364 LAYER M3  ;
    ANTENNAMAXSIDEAREACAR 143.066 LAYER M3  ;
    ANTENNAMAXCUTCAR 0.462963 LAYER VL  ;
    PORT
      LAYER M2 ;
        RECT 408.900000 563.400000 409.100000 564.000000 ;
    END
  END crash_dump_o[26]
  PIN crash_dump_o[25]
    DIRECTION OUTPUT ;
    USE SIGNAL ;
    ANTENNAPARTIALMETALAREA 0.94 LAYER M2  ;
    ANTENNAPARTIALMETALSIDEAREA 3.108 LAYER M2  ;
    ANTENNAPARTIALCUTAREA 0.12 LAYER V2  ;
    ANTENNAPARTIALMETALAREA 24.04 LAYER M3  ;
    ANTENNAPARTIALMETALSIDEAREA 89.392 LAYER M3  ;
    ANTENNAMODEL OXIDE1 ;
    ANTENNAGATEAREA 3.6928 LAYER M3  ;
    ANTENNAMAXAREACAR 106.755 LAYER M3  ;
    ANTENNAMAXSIDEAREACAR 396.154 LAYER M3  ;
    ANTENNAMAXCUTCAR 0.462963 LAYER VL  ;
    PORT
      LAYER M2 ;
        RECT 411.900000 563.400000 412.100000 564.000000 ;
    END
  END crash_dump_o[25]
  PIN crash_dump_o[24]
    DIRECTION OUTPUT ;
    USE SIGNAL ;
    ANTENNAPARTIALMETALAREA 10.68 LAYER M2  ;
    ANTENNAPARTIALMETALSIDEAREA 39.516 LAYER M2  ;
    ANTENNAPARTIALCUTAREA 0.04 LAYER V2  ;
    ANTENNAPARTIALMETALAREA 23.44 LAYER M3  ;
    ANTENNAPARTIALMETALSIDEAREA 87.024 LAYER M3  ;
    ANTENNAMODEL OXIDE1 ;
    ANTENNAGATEAREA 3.6928 LAYER M3  ;
    ANTENNAMAXAREACAR 7.42619 LAYER M3  ;
    ANTENNAMAXSIDEAREACAR 28.6237 LAYER M3  ;
    ANTENNAMAXCUTCAR 0.462963 LAYER VL  ;
    PORT
      LAYER M2 ;
        RECT 414.900000 563.400000 415.100000 564.000000 ;
    END
  END crash_dump_o[24]
  PIN crash_dump_o[23]
    DIRECTION OUTPUT ;
    USE SIGNAL ;
    ANTENNAPARTIALMETALAREA 9.38 LAYER M2  ;
    ANTENNAPARTIALMETALSIDEAREA 34.336 LAYER M2  ;
    ANTENNAPARTIALCUTAREA 0.04 LAYER V2  ;
    ANTENNAPARTIALMETALAREA 25.92 LAYER M3  ;
    ANTENNAPARTIALMETALSIDEAREA 96.2 LAYER M3  ;
    ANTENNAMODEL OXIDE1 ;
    ANTENNAGATEAREA 3.6928 LAYER M3  ;
    ANTENNAMAXAREACAR 9.11629 LAYER M3  ;
    ANTENNAMAXSIDEAREACAR 34.8493 LAYER M3  ;
    ANTENNAMAXCUTCAR 0.462963 LAYER VL  ;
    PORT
      LAYER M2 ;
        RECT 417.900000 563.400000 418.100000 564.000000 ;
    END
  END crash_dump_o[23]
  PIN crash_dump_o[22]
    DIRECTION OUTPUT ;
    USE SIGNAL ;
    ANTENNAPARTIALMETALAREA 15.08 LAYER M2  ;
    ANTENNAPARTIALMETALSIDEAREA 55.796 LAYER M2  ;
    ANTENNAPARTIALCUTAREA 0.08 LAYER V2  ;
    ANTENNAPARTIALMETALAREA 21.52 LAYER M3  ;
    ANTENNAPARTIALMETALSIDEAREA 79.92 LAYER M3  ;
    ANTENNAMODEL OXIDE1 ;
    ANTENNAGATEAREA 3.6928 LAYER M3  ;
    ANTENNAMAXAREACAR 7.46182 LAYER M3  ;
    ANTENNAMAXSIDEAREACAR 28.7278 LAYER M3  ;
    ANTENNAMAXCUTCAR 0.462963 LAYER VL  ;
    PORT
      LAYER M2 ;
        RECT 420.900000 563.400000 421.100000 564.000000 ;
    END
  END crash_dump_o[22]
  PIN crash_dump_o[21]
    DIRECTION OUTPUT ;
    USE SIGNAL ;
    ANTENNAPARTIALMETALAREA 9.78 LAYER M2  ;
    ANTENNAPARTIALMETALSIDEAREA 35.816 LAYER M2  ;
    ANTENNAPARTIALCUTAREA 0.08 LAYER V2  ;
    ANTENNAPARTIALMETALAREA 18.96 LAYER M3  ;
    ANTENNAPARTIALMETALSIDEAREA 70.448 LAYER M3  ;
    ANTENNAMODEL OXIDE1 ;
    ANTENNAGATEAREA 3.6928 LAYER M3  ;
    ANTENNAMAXAREACAR 112.787 LAYER M3  ;
    ANTENNAMAXSIDEAREACAR 418.431 LAYER M3  ;
    ANTENNAMAXCUTCAR 0.462963 LAYER VL  ;
    PORT
      LAYER M2 ;
        RECT 423.900000 563.400000 424.100000 564.000000 ;
    END
  END crash_dump_o[21]
  PIN crash_dump_o[20]
    DIRECTION OUTPUT ;
    USE SIGNAL ;
    ANTENNAPARTIALMETALAREA 10.2 LAYER M2  ;
    ANTENNAPARTIALMETALSIDEAREA 37.74 LAYER M2  ;
    ANTENNAPARTIALCUTAREA 0.08 LAYER V2  ;
    ANTENNAPARTIALMETALAREA 20.08 LAYER M3  ;
    ANTENNAPARTIALMETALSIDEAREA 74.592 LAYER M3  ;
    ANTENNAMODEL OXIDE1 ;
    ANTENNAGATEAREA 3.6928 LAYER M3  ;
    ANTENNAMAXAREACAR 34.3867 LAYER M3  ;
    ANTENNAMAXSIDEAREACAR 128.35 LAYER M3  ;
    ANTENNAMAXCUTCAR 0.462963 LAYER VL  ;
    PORT
      LAYER M2 ;
        RECT 426.900000 563.400000 427.100000 564.000000 ;
    END
  END crash_dump_o[20]
  PIN crash_dump_o[19]
    DIRECTION OUTPUT ;
    USE SIGNAL ;
    ANTENNAPARTIALMETALAREA 9.46 LAYER M2  ;
    ANTENNAPARTIALMETALSIDEAREA 34.632 LAYER M2  ;
    ANTENNAPARTIALCUTAREA 0.08 LAYER V2  ;
    ANTENNAPARTIALMETALAREA 22.88 LAYER M3  ;
    ANTENNAPARTIALMETALSIDEAREA 84.952 LAYER M3  ;
    ANTENNAMODEL OXIDE1 ;
    ANTENNAGATEAREA 3.6928 LAYER M3  ;
    ANTENNAMAXAREACAR 93.4782 LAYER M3  ;
    ANTENNAMAXSIDEAREACAR 346.989 LAYER M3  ;
    ANTENNAMAXCUTCAR 0.462963 LAYER VL  ;
    PORT
      LAYER M2 ;
        RECT 429.900000 563.400000 430.100000 564.000000 ;
    END
  END crash_dump_o[19]
  PIN crash_dump_o[18]
    DIRECTION OUTPUT ;
    USE SIGNAL ;
    ANTENNAPARTIALMETALAREA 2.52 LAYER M2  ;
    ANTENNAPARTIALMETALSIDEAREA 9.324 LAYER M2  ;
    ANTENNAPARTIALCUTAREA 0.08 LAYER V2  ;
    ANTENNAPARTIALMETALAREA 19.68 LAYER M3  ;
    ANTENNAPARTIALMETALSIDEAREA 73.112 LAYER M3  ;
    ANTENNAMODEL OXIDE1 ;
    ANTENNAGATEAREA 3.6928 LAYER M3  ;
    ANTENNAMAXAREACAR 93.5376 LAYER M3  ;
    ANTENNAMAXSIDEAREACAR 347.208 LAYER M3  ;
    ANTENNAMAXCUTCAR 0.462963 LAYER VL  ;
    PORT
      LAYER M2 ;
        RECT 432.900000 563.400000 433.100000 564.000000 ;
    END
  END crash_dump_o[18]
  PIN crash_dump_o[17]
    DIRECTION OUTPUT ;
    USE SIGNAL ;
    ANTENNAPARTIALMETALAREA 1.78 LAYER M2  ;
    ANTENNAPARTIALMETALSIDEAREA 6.216 LAYER M2  ;
    ANTENNAPARTIALCUTAREA 0.04 LAYER V2  ;
    ANTENNAPARTIALMETALAREA 21.8 LAYER M3  ;
    ANTENNAPARTIALMETALSIDEAREA 81.104 LAYER M3  ;
    ANTENNAMODEL OXIDE1 ;
    ANTENNAGATEAREA 3.6928 LAYER M3  ;
    ANTENNAMAXAREACAR 100.593 LAYER M3  ;
    ANTENNAMAXSIDEAREACAR 373.354 LAYER M3  ;
    ANTENNAMAXCUTCAR 0.462963 LAYER VL  ;
    PORT
      LAYER M2 ;
        RECT 435.900000 563.400000 436.100000 564.000000 ;
    END
  END crash_dump_o[17]
  PIN crash_dump_o[16]
    DIRECTION OUTPUT ;
    USE SIGNAL ;
    ANTENNAPARTIALMETALAREA 3.56 LAYER M2  ;
    ANTENNAPARTIALMETALSIDEAREA 13.172 LAYER M2  ;
    ANTENNAPARTIALCUTAREA 0.08 LAYER V2  ;
    ANTENNAPARTIALMETALAREA 19.04 LAYER M3  ;
    ANTENNAPARTIALMETALSIDEAREA 70.744 LAYER M3  ;
    ANTENNAMODEL OXIDE1 ;
    ANTENNAGATEAREA 3.6928 LAYER M3  ;
    ANTENNAMAXAREACAR 92.4384 LAYER M3  ;
    ANTENNAMAXSIDEAREACAR 343.141 LAYER M3  ;
    ANTENNAMAXCUTCAR 0.462963 LAYER VL  ;
    PORT
      LAYER M2 ;
        RECT 438.900000 563.400000 439.100000 564.000000 ;
    END
  END crash_dump_o[16]
  PIN crash_dump_o[15]
    DIRECTION OUTPUT ;
    USE SIGNAL ;
    ANTENNAPARTIALMETALAREA 6.1 LAYER M2  ;
    ANTENNAPARTIALMETALSIDEAREA 22.2 LAYER M2  ;
    ANTENNAPARTIALCUTAREA 0.04 LAYER V2  ;
    ANTENNAPARTIALMETALAREA 23.12 LAYER M3  ;
    ANTENNAPARTIALMETALSIDEAREA 85.84 LAYER M3  ;
    ANTENNAMODEL OXIDE1 ;
    ANTENNAGATEAREA 3.6928 LAYER M3  ;
    ANTENNAMAXAREACAR 60.2099 LAYER M3  ;
    ANTENNAMAXSIDEAREACAR 223.896 LAYER M3  ;
    ANTENNAMAXCUTCAR 0.462963 LAYER VL  ;
    PORT
      LAYER M2 ;
        RECT 441.900000 563.400000 442.100000 564.000000 ;
    END
  END crash_dump_o[15]
  PIN crash_dump_o[14]
    DIRECTION OUTPUT ;
    USE SIGNAL ;
    ANTENNAPARTIALMETALAREA 0.02 LAYER M2  ;
    ANTENNAPARTIALMETALSIDEAREA 0.074 LAYER M2  ;
    ANTENNAPARTIALCUTAREA 0.04 LAYER V2  ;
    ANTENNAPARTIALMETALAREA 23.24 LAYER M3  ;
    ANTENNAPARTIALMETALSIDEAREA 86.432 LAYER M3  ;
    ANTENNAMODEL OXIDE1 ;
    ANTENNAGATEAREA 3.6928 LAYER M3  ;
    ANTENNAMAXAREACAR 33.8535 LAYER M3  ;
    ANTENNAMAXSIDEAREACAR 126.417 LAYER M3  ;
    ANTENNAMAXCUTCAR 0.694444 LAYER VL  ;
    PORT
      LAYER M2 ;
        RECT 444.900000 563.400000 445.100000 564.000000 ;
    END
  END crash_dump_o[14]
  PIN crash_dump_o[13]
    DIRECTION OUTPUT ;
    USE SIGNAL ;
    ANTENNAPARTIALMETALAREA 3.94 LAYER M2  ;
    ANTENNAPARTIALMETALSIDEAREA 14.208 LAYER M2  ;
    ANTENNAPARTIALCUTAREA 0.04 LAYER V2  ;
    ANTENNAPARTIALMETALAREA 22.6 LAYER M3  ;
    ANTENNAPARTIALMETALSIDEAREA 84.064 LAYER M3  ;
    ANTENNAMODEL OXIDE1 ;
    ANTENNAGATEAREA 0.1728 LAYER M3  ;
    ANTENNAMAXAREACAR 132.884 LAYER M3  ;
    ANTENNAMAXSIDEAREACAR 495.28 LAYER M3  ;
    ANTENNAMAXCUTCAR 0.462963 LAYER VL  ;
    PORT
      LAYER M2 ;
        RECT 447.900000 563.400000 448.100000 564.000000 ;
    END
  END crash_dump_o[13]
  PIN crash_dump_o[12]
    DIRECTION OUTPUT ;
    USE SIGNAL ;
    ANTENNAPARTIALMETALAREA 0.52 LAYER M2  ;
    ANTENNAPARTIALMETALSIDEAREA 1.924 LAYER M2  ;
    ANTENNAPARTIALCUTAREA 0.04 LAYER V2  ;
    ANTENNAPARTIALMETALAREA 28.04 LAYER M3  ;
    ANTENNAPARTIALMETALSIDEAREA 104.192 LAYER M3  ;
    ANTENNAMODEL OXIDE1 ;
    ANTENNAGATEAREA 3.6928 LAYER M3  ;
    ANTENNAMAXAREACAR 14.8025 LAYER M3  ;
    ANTENNAMAXSIDEAREACAR 54.8482 LAYER M3  ;
    ANTENNAMAXCUTCAR 0.462963 LAYER VL  ;
    PORT
      LAYER M2 ;
        RECT 450.900000 563.400000 451.100000 564.000000 ;
    END
  END crash_dump_o[12]
  PIN crash_dump_o[11]
    DIRECTION OUTPUT ;
    USE SIGNAL ;
    ANTENNAPARTIALMETALAREA 1.06 LAYER M2  ;
    ANTENNAPARTIALMETALSIDEAREA 3.552 LAYER M2  ;
    ANTENNAPARTIALCUTAREA 0.04 LAYER V2  ;
    ANTENNAPARTIALMETALAREA 25.96 LAYER M3  ;
    ANTENNAPARTIALMETALSIDEAREA 96.496 LAYER M3  ;
    ANTENNAMODEL OXIDE1 ;
    ANTENNAGATEAREA 0.1728 LAYER M3  ;
    ANTENNAMAXAREACAR 153.255 LAYER M3  ;
    ANTENNAMAXSIDEAREACAR 570.65 LAYER M3  ;
    ANTENNAMAXCUTCAR 0.462963 LAYER VL  ;
    PORT
      LAYER M2 ;
        RECT 453.900000 563.400000 454.100000 564.000000 ;
    END
  END crash_dump_o[11]
  PIN crash_dump_o[10]
    DIRECTION OUTPUT ;
    USE SIGNAL ;
    ANTENNAPARTIALMETALAREA 0.36 LAYER M2  ;
    ANTENNAPARTIALMETALSIDEAREA 1.332 LAYER M2  ;
    ANTENNAPARTIALCUTAREA 0.04 LAYER V2  ;
    ANTENNAPARTIALMETALAREA 25.48 LAYER M3  ;
    ANTENNAPARTIALMETALSIDEAREA 94.72 LAYER M3  ;
    ANTENNAMODEL OXIDE1 ;
    ANTENNAGATEAREA 3.52 LAYER M3  ;
    ANTENNAMAXAREACAR 7.42523 LAYER M3  ;
    ANTENNAMAXSIDEAREACAR 27.5583 LAYER M3  ;
    ANTENNAMAXCUTCAR 0.0227273 LAYER VL  ;
    PORT
      LAYER M2 ;
        RECT 456.900000 563.400000 457.100000 564.000000 ;
    END
  END crash_dump_o[10]
  PIN crash_dump_o[9]
    DIRECTION OUTPUT ;
    USE SIGNAL ;
    ANTENNAPARTIALMETALAREA 1.14 LAYER M2  ;
    ANTENNAPARTIALMETALSIDEAREA 3.848 LAYER M2  ;
    ANTENNAPARTIALCUTAREA 0.04 LAYER V2  ;
    ANTENNAPARTIALMETALAREA 26.76 LAYER M3  ;
    ANTENNAPARTIALMETALSIDEAREA 99.456 LAYER M3  ;
    ANTENNAMODEL OXIDE1 ;
    ANTENNAGATEAREA 0.1728 LAYER M3  ;
    ANTENNAMAXAREACAR 155.94 LAYER M3  ;
    ANTENNAMAXSIDEAREACAR 580.613 LAYER M3  ;
    ANTENNAMAXCUTCAR 0.462963 LAYER VL  ;
    PORT
      LAYER M2 ;
        RECT 459.900000 563.400000 460.100000 564.000000 ;
    END
  END crash_dump_o[9]
  PIN crash_dump_o[8]
    DIRECTION OUTPUT ;
    USE SIGNAL ;
    ANTENNAPARTIALMETALAREA 2.36 LAYER M2  ;
    ANTENNAPARTIALMETALSIDEAREA 8.732 LAYER M2  ;
    ANTENNAPARTIALCUTAREA 0.04 LAYER V2  ;
    ANTENNAPARTIALMETALAREA 24.52 LAYER M3  ;
    ANTENNAPARTIALMETALSIDEAREA 91.168 LAYER M3  ;
    ANTENNAMODEL OXIDE1 ;
    ANTENNAGATEAREA 3.6928 LAYER M3  ;
    ANTENNAMAXAREACAR 7.71865 LAYER M3  ;
    ANTENNAMAXSIDEAREACAR 29.7459 LAYER M3  ;
    ANTENNAMAXCUTCAR 0.462963 LAYER VL  ;
    PORT
      LAYER M2 ;
        RECT 462.900000 563.400000 463.100000 564.000000 ;
    END
  END crash_dump_o[8]
  PIN crash_dump_o[7]
    DIRECTION OUTPUT ;
    USE SIGNAL ;
    ANTENNAPARTIALMETALAREA 1.86 LAYER M2  ;
    ANTENNAPARTIALMETALSIDEAREA 6.512 LAYER M2  ;
    ANTENNAPARTIALCUTAREA 0.04 LAYER V2  ;
    ANTENNAPARTIALMETALAREA 26.16 LAYER M3  ;
    ANTENNAPARTIALMETALSIDEAREA 97.088 LAYER M3  ;
    ANTENNAMODEL OXIDE1 ;
    ANTENNAGATEAREA 3.6928 LAYER M3  ;
    ANTENNAMAXAREACAR 60.6859 LAYER M3  ;
    ANTENNAMAXSIDEAREACAR 224.715 LAYER M3  ;
    ANTENNAMAXCUTCAR 0.694444 LAYER VL  ;
    PORT
      LAYER M2 ;
        RECT 465.900000 563.400000 466.100000 564.000000 ;
    END
  END crash_dump_o[7]
  PIN crash_dump_o[6]
    DIRECTION OUTPUT ;
    USE SIGNAL ;
    ANTENNAPARTIALMETALAREA 6.84 LAYER M2  ;
    ANTENNAPARTIALMETALSIDEAREA 25.308 LAYER M2  ;
    ANTENNAPARTIALCUTAREA 0.04 LAYER V2  ;
    ANTENNAPARTIALMETALAREA 27.56 LAYER M3  ;
    ANTENNAPARTIALMETALSIDEAREA 102.416 LAYER M3  ;
    ANTENNAMODEL OXIDE1 ;
    ANTENNAGATEAREA 3.6928 LAYER M3  ;
    ANTENNAMAXAREACAR 11.065 LAYER M3  ;
    ANTENNAMAXSIDEAREACAR 41.1576 LAYER M3  ;
    ANTENNAMAXCUTCAR 0.462963 LAYER VL  ;
    PORT
      LAYER M2 ;
        RECT 468.900000 563.400000 469.100000 564.000000 ;
    END
  END crash_dump_o[6]
  PIN crash_dump_o[5]
    DIRECTION OUTPUT ;
    USE SIGNAL ;
    ANTENNAPARTIALMETALAREA 0.42 LAYER M2  ;
    ANTENNAPARTIALMETALSIDEAREA 1.184 LAYER M2  ;
    ANTENNAPARTIALCUTAREA 0.04 LAYER V2  ;
    ANTENNAPARTIALMETALAREA 28.76 LAYER M3  ;
    ANTENNAPARTIALMETALSIDEAREA 106.856 LAYER M3  ;
    ANTENNAMODEL OXIDE1 ;
    ANTENNAGATEAREA 3.6928 LAYER M3  ;
    ANTENNAMAXAREACAR 8.86683 LAYER M3  ;
    ANTENNAMAXSIDEAREACAR 33.9942 LAYER M3  ;
    ANTENNAMAXCUTCAR 0.462963 LAYER VL  ;
    PORT
      LAYER M2 ;
        RECT 471.900000 563.400000 472.100000 564.000000 ;
    END
  END crash_dump_o[5]
  PIN crash_dump_o[4]
    DIRECTION OUTPUT ;
    USE SIGNAL ;
    ANTENNAPARTIALMETALAREA 6.36 LAYER M2  ;
    ANTENNAPARTIALMETALSIDEAREA 23.532 LAYER M2  ;
    ANTENNAPARTIALCUTAREA 0.04 LAYER V2  ;
    ANTENNAPARTIALMETALAREA 27.32 LAYER M3  ;
    ANTENNAPARTIALMETALSIDEAREA 101.232 LAYER M3  ;
    PORT
      LAYER M2 ;
        RECT 474.900000 563.400000 475.100000 564.000000 ;
    END
  END crash_dump_o[4]
  PIN crash_dump_o[3]
    DIRECTION OUTPUT ;
    USE SIGNAL ;
    ANTENNAPARTIALMETALAREA 4.7 LAYER M2  ;
    ANTENNAPARTIALMETALSIDEAREA 17.02 LAYER M2  ;
    ANTENNAPARTIALCUTAREA 0.12 LAYER V2  ;
    ANTENNAPARTIALMETALAREA 32.16 LAYER M3  ;
    ANTENNAPARTIALMETALSIDEAREA 119.584 LAYER M3  ;
    ANTENNAMODEL OXIDE1 ;
    ANTENNAGATEAREA 3.6928 LAYER M3  ;
    ANTENNAMAXAREACAR 10.8709 LAYER M3  ;
    ANTENNAMAXSIDEAREACAR 40.5103 LAYER M3  ;
    ANTENNAMAXCUTCAR 0.462963 LAYER VL  ;
    PORT
      LAYER M2 ;
        RECT 477.900000 563.400000 478.100000 564.000000 ;
    END
  END crash_dump_o[3]
  PIN crash_dump_o[2]
    DIRECTION OUTPUT ;
    USE SIGNAL ;
    ANTENNAPARTIALMETALAREA 7.48 LAYER M2  ;
    ANTENNAPARTIALMETALSIDEAREA 27.676 LAYER M2  ;
    ANTENNAPARTIALCUTAREA 0.04 LAYER V2  ;
    ANTENNAPARTIALMETALAREA 25.52 LAYER M3  ;
    ANTENNAPARTIALMETALSIDEAREA 94.72 LAYER M3  ;
    ANTENNAMODEL OXIDE1 ;
    ANTENNAGATEAREA 3.6928 LAYER M3  ;
    ANTENNAMAXAREACAR 11.7857 LAYER M3  ;
    ANTENNAMAXSIDEAREACAR 44.7263 LAYER M3  ;
    ANTENNAMAXCUTCAR 0.462963 LAYER VL  ;
    PORT
      LAYER M2 ;
        RECT 480.900000 563.400000 481.100000 564.000000 ;
    END
  END crash_dump_o[2]
  PIN crash_dump_o[1]
    DIRECTION OUTPUT ;
    USE SIGNAL ;
    ANTENNAPARTIALMETALAREA 5.38 LAYER M2  ;
    ANTENNAPARTIALMETALSIDEAREA 19.536 LAYER M2  ;
    ANTENNAPARTIALCUTAREA 0.04 LAYER V2  ;
    ANTENNAPARTIALMETALAREA 28.56 LAYER M3  ;
    ANTENNAPARTIALMETALSIDEAREA 105.968 LAYER M3  ;
    ANTENNAMODEL OXIDE1 ;
    ANTENNAGATEAREA 3.6928 LAYER M3  ;
    ANTENNAMAXAREACAR 10.2942 LAYER M3  ;
    ANTENNAMAXSIDEAREACAR 39.2074 LAYER M3  ;
    ANTENNAMAXCUTCAR 0.462963 LAYER VL  ;
    PORT
      LAYER M2 ;
        RECT 483.900000 563.400000 484.100000 564.000000 ;
    END
  END crash_dump_o[1]
  PIN crash_dump_o[0]
    DIRECTION OUTPUT ;
    USE SIGNAL ;
    ANTENNAPARTIALMETALAREA 1.08 LAYER M2  ;
    ANTENNAPARTIALMETALSIDEAREA 3.996 LAYER M2  ;
    ANTENNAPARTIALCUTAREA 0.04 LAYER V2  ;
    ANTENNAPARTIALMETALAREA 27.6 LAYER M3  ;
    ANTENNAPARTIALMETALSIDEAREA 102.416 LAYER M3  ;
    ANTENNAMODEL OXIDE1 ;
    ANTENNAGATEAREA 0.1728 LAYER M3  ;
    ANTENNAMAXAREACAR 163.671 LAYER M3  ;
    ANTENNAMAXSIDEAREACAR 608.336 LAYER M3  ;
    ANTENNAMAXCUTCAR 0.462963 LAYER VL  ;
    PORT
      LAYER M2 ;
        RECT 486.900000 563.400000 487.100000 564.000000 ;
    END
  END crash_dump_o[0]
  PIN double_fault_seen_o
    DIRECTION OUTPUT ;
    USE SIGNAL ;
    ANTENNAPARTIALMETALAREA 27.7 LAYER M2  ;
    ANTENNAPARTIALMETALSIDEAREA 102.12 LAYER M2  ;
    ANTENNAPARTIALCUTAREA 0.04 LAYER V2  ;
    ANTENNAPARTIALMETALAREA 25 LAYER M3  ;
    ANTENNAPARTIALMETALSIDEAREA 92.944 LAYER M3  ;
    ANTENNAMODEL OXIDE1 ;
    ANTENNAGATEAREA 3.004 LAYER M3  ;
    ANTENNAMAXAREACAR 9.93758 LAYER M3  ;
    ANTENNAMAXSIDEAREACAR 36.8471 LAYER M3  ;
    ANTENNAMAXCUTCAR 0.512821 LAYER VL  ;
    PORT
      LAYER M2 ;
        RECT 489.900000 563.400000 490.100000 564.000000 ;
    END
  END double_fault_seen_o
  PIN fetch_enable_i[3]
    DIRECTION INPUT ;
    USE SIGNAL ;
    PORT
      LAYER M2 ;
        RECT 9.900000 0.000000 10.100000 0.600000 ;
    END
  END fetch_enable_i[3]
  PIN fetch_enable_i[2]
    DIRECTION INPUT ;
    USE SIGNAL ;
    PORT
      LAYER M2 ;
        RECT 13.900000 0.000000 14.100000 0.600000 ;
    END
  END fetch_enable_i[2]
  PIN fetch_enable_i[1]
    DIRECTION INPUT ;
    USE SIGNAL ;
    PORT
      LAYER M2 ;
        RECT 17.900000 0.000000 18.100000 0.600000 ;
    END
  END fetch_enable_i[1]
  PIN fetch_enable_i[0]
    DIRECTION INPUT ;
    USE SIGNAL ;
    ANTENNAPARTIALMETALAREA 2.22 LAYER M2  ;
    ANTENNAPARTIALMETALSIDEAREA 7.844 LAYER M2  ;
    ANTENNAPARTIALCUTAREA 0.12 LAYER V2  ;
    ANTENNAPARTIALMETALAREA 0.24 LAYER M3  ;
    ANTENNAPARTIALMETALSIDEAREA 1.184 LAYER M3  ;
    ANTENNAMODEL OXIDE1 ;
    ANTENNAGATEAREA 0.0888 LAYER M3  ;
    ANTENNAMAXAREACAR 4.6982 LAYER M3  ;
    ANTENNAMAXSIDEAREACAR 23.0225 LAYER M3  ;
    ANTENNAMAXCUTCAR 0.900901 LAYER VL  ;
    PORT
      LAYER M2 ;
        RECT 21.900000 0.000000 22.100000 0.600000 ;
    END
  END fetch_enable_i[0]
  PIN alert_minor_o
    DIRECTION OUTPUT ;
    USE SIGNAL ;
    PORT
      LAYER M2 ;
        RECT 492.900000 563.400000 493.100000 564.000000 ;
    END
  END alert_minor_o
  PIN alert_major_internal_o
    DIRECTION OUTPUT ;
    USE SIGNAL ;
    PORT
      LAYER M2 ;
        RECT 495.900000 563.400000 496.100000 564.000000 ;
    END
  END alert_major_internal_o
  PIN alert_major_bus_o
    DIRECTION OUTPUT ;
    USE SIGNAL ;
    PORT
      LAYER M2 ;
        RECT 498.900000 563.400000 499.100000 564.000000 ;
    END
  END alert_major_bus_o
  PIN core_sleep_o
    DIRECTION OUTPUT ;
    USE SIGNAL ;
    ANTENNAPARTIALMETALAREA 0.34 LAYER M2  ;
    ANTENNAPARTIALMETALSIDEAREA 0.888 LAYER M2  ;
    ANTENNAPARTIALCUTAREA 0.04 LAYER V2  ;
    ANTENNAPARTIALMETALAREA 84.44 LAYER M3  ;
    ANTENNAPARTIALMETALSIDEAREA 312.872 LAYER M3  ;
    ANTENNAMODEL OXIDE1 ;
    ANTENNAGATEAREA 0.264 LAYER M3  ;
    ANTENNAMAXAREACAR 352.805 LAYER M3  ;
    ANTENNAMAXSIDEAREACAR 1306.26 LAYER M3  ;
    ANTENNAMAXCUTCAR 0.30303 LAYER VL  ;
    PORT
      LAYER M2 ;
        RECT 501.900000 563.400000 502.100000 564.000000 ;
    END
  END core_sleep_o
  PIN scan_rst_ni
    DIRECTION INPUT ;
    USE SIGNAL ;
    ANTENNAPARTIALMETALAREA 0.34 LAYER M3  ;
    ANTENNAPARTIALMETALSIDEAREA 0.888 LAYER M3  ;
    PORT
      LAYER M3 ;
        RECT 0.000000 27.900000 0.600000 28.100000 ;
    END
  END scan_rst_ni
  PIN test_si
    DIRECTION INPUT ;
    USE SIGNAL ;
    ANTENNAPARTIALMETALAREA 0.42 LAYER M2  ;
    ANTENNAPARTIALMETALSIDEAREA 1.184 LAYER M2  ;
    ANTENNAPARTIALCUTAREA 0.04 LAYER V2  ;
    ANTENNAPARTIALMETALAREA 0.28 LAYER M3  ;
    ANTENNAPARTIALMETALSIDEAREA 1.184 LAYER M3  ;
    ANTENNAMODEL OXIDE1 ;
    ANTENNAGATEAREA 0.0576 LAYER M3  ;
    ANTENNAMAXAREACAR 33.4444 LAYER M3  ;
    ANTENNAMAXSIDEAREACAR 128.111 LAYER M3  ;
    ANTENNAMAXCUTCAR 1.38889 LAYER VL  ;
    PORT
      LAYER M2 ;
        RECT 25.900000 0.000000 26.100000 0.600000 ;
    END
  END test_si
  PIN test_so
    DIRECTION OUTPUT ;
    USE SIGNAL ;
    ANTENNAPARTIALMETALAREA 0.34 LAYER M2  ;
    ANTENNAPARTIALMETALSIDEAREA 0.888 LAYER M2  ;
    ANTENNAPARTIALCUTAREA 0.04 LAYER V2  ;
    ANTENNAPARTIALMETALAREA 1.16 LAYER M3  ;
    ANTENNAPARTIALMETALSIDEAREA 4.44 LAYER M3  ;
    ANTENNAMODEL OXIDE1 ;
    ANTENNAGATEAREA 3.25 LAYER M3  ;
    ANTENNAMAXAREACAR 1.0692 LAYER M3  ;
    ANTENNAMAXSIDEAREACAR 3.99975 LAYER M3  ;
    ANTENNAMAXCUTCAR 0.0246154 LAYER VL  ;
    PORT
      LAYER M2 ;
        RECT 29.900000 0.000000 30.100000 0.600000 ;
    END
  END test_so
  PIN VSS
    DIRECTION INOUT ;
    USE GROUND ;

# P/G power stripe data as pin
    PORT
      LAYER M1 ;
        RECT 8.400000 11.720000 555.600000 12.280000 ;
        RECT 8.400000 18.920000 555.600000 19.480000 ;
        RECT 8.400000 26.120000 555.600000 26.680000 ;
        RECT 8.400000 33.320000 555.600000 33.880000 ;
        RECT 8.400000 40.520000 555.600000 41.080000 ;
        RECT 8.400000 47.720000 555.600000 48.280000 ;
        RECT 8.400000 54.920000 555.600000 55.480000 ;
        RECT 8.400000 69.320000 555.600000 69.880000 ;
        RECT 8.400000 62.120000 555.600000 62.680000 ;
        RECT 8.400000 134.120000 555.600000 134.680000 ;
        RECT 8.400000 126.920000 555.600000 127.480000 ;
        RECT 8.400000 119.720000 555.600000 120.280000 ;
        RECT 8.400000 112.520000 555.600000 113.080000 ;
        RECT 8.400000 105.320000 555.600000 105.880000 ;
        RECT 8.400000 98.120000 555.600000 98.680000 ;
        RECT 8.400000 90.920000 555.600000 91.480000 ;
        RECT 8.400000 83.720000 555.600000 84.280000 ;
        RECT 8.400000 76.520000 555.600000 77.080000 ;
        RECT 8.400000 141.320000 555.600000 141.880000 ;
        RECT 8.400000 148.520000 555.600000 149.080000 ;
        RECT 8.400000 155.720000 555.600000 156.280000 ;
        RECT 8.400000 162.920000 555.600000 163.480000 ;
        RECT 8.400000 170.120000 555.600000 170.680000 ;
        RECT 8.400000 177.320000 555.600000 177.880000 ;
        RECT 8.400000 184.520000 555.600000 185.080000 ;
        RECT 8.400000 191.720000 555.600000 192.280000 ;
        RECT 8.400000 198.920000 555.600000 199.480000 ;
        RECT 8.400000 206.120000 555.600000 206.680000 ;
        RECT 8.400000 278.120000 555.600000 278.680000 ;
        RECT 8.400000 270.920000 555.600000 271.480000 ;
        RECT 8.400000 263.720000 555.600000 264.280000 ;
        RECT 8.400000 256.520000 555.600000 257.080000 ;
        RECT 8.400000 249.320000 555.600000 249.880000 ;
        RECT 8.400000 242.120000 555.600000 242.680000 ;
        RECT 8.400000 234.920000 555.600000 235.480000 ;
        RECT 8.400000 227.720000 555.600000 228.280000 ;
        RECT 8.400000 220.520000 555.600000 221.080000 ;
        RECT 8.400000 213.320000 555.600000 213.880000 ;
        RECT 8.400000 285.320000 555.600000 285.880000 ;
        RECT 8.400000 292.520000 555.600000 293.080000 ;
        RECT 8.400000 299.720000 555.600000 300.280000 ;
        RECT 8.400000 306.920000 555.600000 307.480000 ;
        RECT 8.400000 314.120000 555.600000 314.680000 ;
        RECT 8.400000 321.320000 555.600000 321.880000 ;
        RECT 8.400000 328.520000 555.600000 329.080000 ;
        RECT 8.400000 335.720000 555.600000 336.280000 ;
        RECT 8.400000 342.920000 555.600000 343.480000 ;
        RECT 8.400000 350.120000 555.600000 350.680000 ;
        RECT 8.400000 422.120000 555.600000 422.680000 ;
        RECT 8.400000 414.920000 555.600000 415.480000 ;
        RECT 8.400000 407.720000 555.600000 408.280000 ;
        RECT 8.400000 400.520000 555.600000 401.080000 ;
        RECT 8.400000 393.320000 555.600000 393.880000 ;
        RECT 8.400000 386.120000 555.600000 386.680000 ;
        RECT 8.400000 378.920000 555.600000 379.480000 ;
        RECT 8.400000 371.720000 555.600000 372.280000 ;
        RECT 8.400000 364.520000 555.600000 365.080000 ;
        RECT 8.400000 357.320000 555.600000 357.880000 ;
        RECT 8.400000 429.320000 555.600000 429.880000 ;
        RECT 8.400000 436.520000 555.600000 437.080000 ;
        RECT 8.400000 443.720000 555.600000 444.280000 ;
        RECT 8.400000 450.920000 555.600000 451.480000 ;
        RECT 8.400000 458.120000 555.600000 458.680000 ;
        RECT 8.400000 465.320000 555.600000 465.880000 ;
        RECT 8.400000 472.520000 555.600000 473.080000 ;
        RECT 8.400000 486.920000 555.600000 487.480000 ;
        RECT 8.400000 479.720000 555.600000 480.280000 ;
        RECT 8.400000 551.720000 555.600000 552.280000 ;
        RECT 8.400000 544.520000 555.600000 545.080000 ;
        RECT 8.400000 537.320000 555.600000 537.880000 ;
        RECT 8.400000 530.120000 555.600000 530.680000 ;
        RECT 8.400000 522.920000 555.600000 523.480000 ;
        RECT 8.400000 515.720000 555.600000 516.280000 ;
        RECT 8.400000 508.520000 555.600000 509.080000 ;
        RECT 8.400000 501.320000 555.600000 501.880000 ;
        RECT 8.400000 494.120000 555.600000 494.680000 ;
    END
# end of P/G power stripe data as pin

  END VSS
  PIN VDD
    DIRECTION INOUT ;
    USE POWER ;

# P/G power stripe data as pin
    PORT
      LAYER M1 ;
        RECT 8.400000 281.720000 555.600000 282.280000 ;
        RECT 8.400000 58.520000 555.600000 59.080000 ;
        RECT 8.400000 65.720000 555.600000 66.280000 ;
        RECT 8.400000 51.320000 555.600000 51.880000 ;
        RECT 8.400000 44.120000 555.600000 44.680000 ;
        RECT 8.400000 36.920000 555.600000 37.480000 ;
        RECT 8.400000 29.720000 555.600000 30.280000 ;
        RECT 8.400000 22.520000 555.600000 23.080000 ;
        RECT 8.400000 15.320000 555.600000 15.880000 ;
        RECT 8.400000 8.120000 555.600000 8.680000 ;
        RECT 8.400000 72.920000 555.600000 73.480000 ;
        RECT 8.400000 80.120000 555.600000 80.680000 ;
        RECT 8.400000 87.320000 555.600000 87.880000 ;
        RECT 8.400000 94.520000 555.600000 95.080000 ;
        RECT 8.400000 101.720000 555.600000 102.280000 ;
        RECT 8.400000 108.920000 555.600000 109.480000 ;
        RECT 8.400000 116.120000 555.600000 116.680000 ;
        RECT 8.400000 123.320000 555.600000 123.880000 ;
        RECT 8.400000 130.520000 555.600000 131.080000 ;
        RECT 8.400000 137.720000 555.600000 138.280000 ;
        RECT 8.400000 144.920000 555.600000 145.480000 ;
        RECT 8.400000 152.120000 555.600000 152.680000 ;
        RECT 8.400000 159.320000 555.600000 159.880000 ;
        RECT 8.400000 166.520000 555.600000 167.080000 ;
        RECT 8.400000 173.720000 555.600000 174.280000 ;
        RECT 8.400000 180.920000 555.600000 181.480000 ;
        RECT 8.400000 188.120000 555.600000 188.680000 ;
        RECT 8.400000 195.320000 555.600000 195.880000 ;
        RECT 8.400000 202.520000 555.600000 203.080000 ;
        RECT 8.400000 209.720000 555.600000 210.280000 ;
        RECT 8.400000 216.920000 555.600000 217.480000 ;
        RECT 8.400000 224.120000 555.600000 224.680000 ;
        RECT 8.400000 231.320000 555.600000 231.880000 ;
        RECT 8.400000 238.520000 555.600000 239.080000 ;
        RECT 8.400000 245.720000 555.600000 246.280000 ;
        RECT 8.400000 252.920000 555.600000 253.480000 ;
        RECT 8.400000 260.120000 555.600000 260.680000 ;
        RECT 8.400000 267.320000 555.600000 267.880000 ;
        RECT 8.400000 274.520000 555.600000 275.080000 ;
        RECT 8.400000 332.120000 555.600000 332.680000 ;
        RECT 8.400000 339.320000 555.600000 339.880000 ;
        RECT 8.400000 346.520000 555.600000 347.080000 ;
        RECT 8.400000 324.920000 555.600000 325.480000 ;
        RECT 8.400000 317.720000 555.600000 318.280000 ;
        RECT 8.400000 310.520000 555.600000 311.080000 ;
        RECT 8.400000 303.320000 555.600000 303.880000 ;
        RECT 8.400000 296.120000 555.600000 296.680000 ;
        RECT 8.400000 288.920000 555.600000 289.480000 ;
        RECT 8.400000 418.520000 555.600000 419.080000 ;
        RECT 8.400000 411.320000 555.600000 411.880000 ;
        RECT 8.400000 404.120000 555.600000 404.680000 ;
        RECT 8.400000 396.920000 555.600000 397.480000 ;
        RECT 8.400000 389.720000 555.600000 390.280000 ;
        RECT 8.400000 382.520000 555.600000 383.080000 ;
        RECT 8.400000 375.320000 555.600000 375.880000 ;
        RECT 8.400000 368.120000 555.600000 368.680000 ;
        RECT 8.400000 360.920000 555.600000 361.480000 ;
        RECT 8.400000 353.720000 555.600000 354.280000 ;
        RECT 8.400000 490.520000 555.600000 491.080000 ;
        RECT 8.400000 483.320000 555.600000 483.880000 ;
        RECT 8.400000 476.120000 555.600000 476.680000 ;
        RECT 8.400000 468.920000 555.600000 469.480000 ;
        RECT 8.400000 461.720000 555.600000 462.280000 ;
        RECT 8.400000 454.520000 555.600000 455.080000 ;
        RECT 8.400000 447.320000 555.600000 447.880000 ;
        RECT 8.400000 440.120000 555.600000 440.680000 ;
        RECT 8.400000 432.920000 555.600000 433.480000 ;
        RECT 8.400000 425.720000 555.600000 426.280000 ;
        RECT 8.400000 555.320000 555.600000 555.880000 ;
        RECT 8.400000 548.120000 555.600000 548.680000 ;
        RECT 8.400000 540.920000 555.600000 541.480000 ;
        RECT 8.400000 533.720000 555.600000 534.280000 ;
        RECT 8.400000 526.520000 555.600000 527.080000 ;
        RECT 8.400000 519.320000 555.600000 519.880000 ;
        RECT 8.400000 512.120000 555.600000 512.680000 ;
        RECT 8.400000 504.920000 555.600000 505.480000 ;
        RECT 8.400000 497.720000 555.600000 498.280000 ;
    END
# end of P/G power stripe data as pin

  END VDD
  OBS
    LAYER M1 ;
      RECT 0.000000 557.800000 564.000000 564.000000 ;
      RECT 557.520000 6.200000 564.000000 557.800000 ;
      RECT 0.000000 6.200000 6.480000 557.800000 ;
      RECT 0.000000 0.000000 564.000000 6.200000 ;
    LAYER M2 ;
      RECT 504.020000 561.480000 564.000000 564.000000 ;
      RECT 0.000000 561.480000 7.980000 564.000000 ;
      RECT 0.000000 261.020000 564.000000 561.480000 ;
      RECT 2.520000 37.980000 564.000000 261.020000 ;
      RECT 0.000000 16.020000 564.000000 37.980000 ;
      RECT 2.520000 7.980000 564.000000 16.020000 ;
      RECT 0.000000 2.520000 564.000000 7.980000 ;
      RECT 455.020000 0.000000 564.000000 2.520000 ;
      RECT 48.020000 0.000000 51.980000 2.520000 ;
      RECT 0.000000 0.000000 7.980000 2.520000 ;
    LAYER M3 ;
      RECT 0.000000 494.520000 564.000000 564.000000 ;
      RECT 0.000000 486.020000 561.480000 494.520000 ;
      RECT 2.520000 259.980000 561.480000 486.020000 ;
      RECT 0.000000 30.020000 561.480000 259.980000 ;
      RECT 2.520000 19.980000 561.480000 30.020000 ;
      RECT 0.000000 7.980000 561.480000 19.980000 ;
      RECT 0.000000 2.520000 564.000000 7.980000 ;
      RECT 521.520000 0.000000 564.000000 2.520000 ;
      RECT 0.000000 0.000000 454.480000 2.520000 ;
    LAYER MQ ;
      RECT 0.000000 0.000000 564.000000 564.000000 ;
    LAYER MG ;
      RECT 0.000000 0.000000 564.000000 564.000000 ;
  END
END ibex_top

END LIBRARY
